VERSION 5.8 ;
BUSBITCHARS "[]" ;
DIVIDERCHAR "/" ;
UNITS
    DATABASE MICRONS 1000 ;
END UNITS

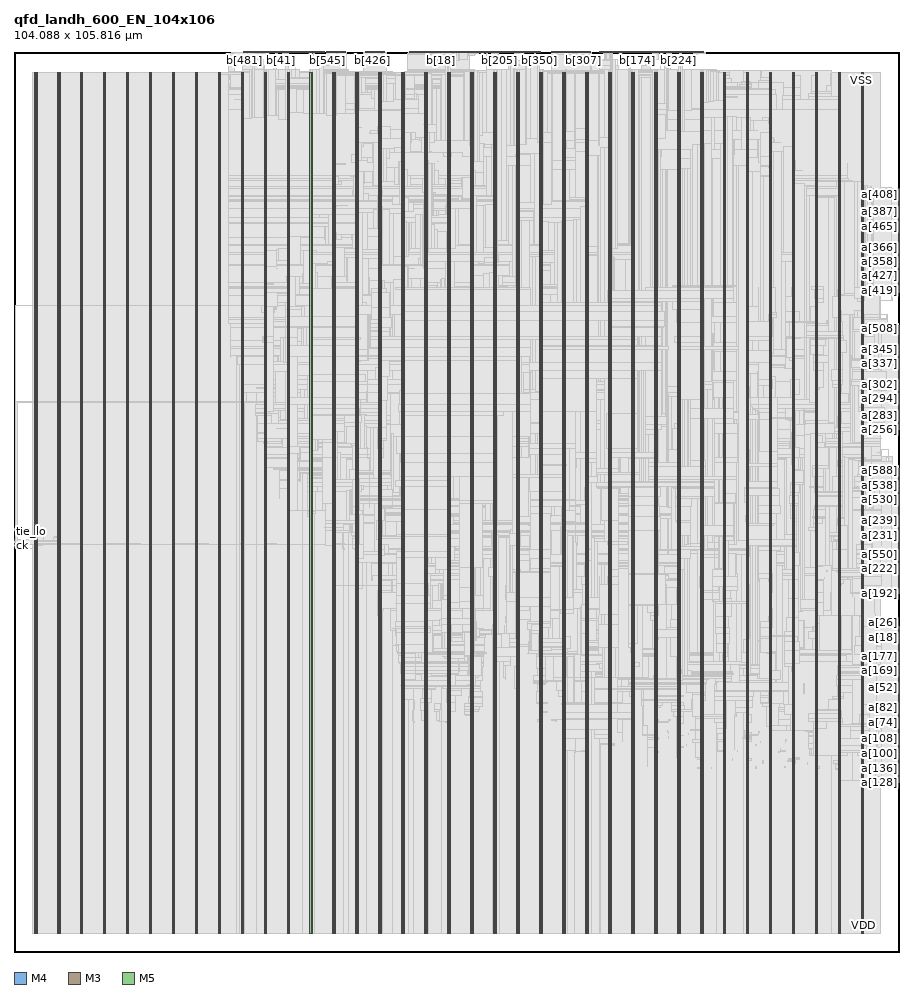
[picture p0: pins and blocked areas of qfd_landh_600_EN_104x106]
MACRO qfd_landh_600_EN_104x106
  FOREIGN qfd_landh_600_EN_104x106 0 0 ;
  CLASS BLOCK ;
  SIZE 104.088 BY 105.816 ;
  PIN a[0]
    DIRECTION INPUT ;
    USE SIGNAL ;
    PORT
      LAYER M4 ;
        RECT  104.004 35.28 104.088 35.304 ;
    END
  END a[0]
  PIN a[100]
    DIRECTION INPUT ;
    USE SIGNAL ;
    PORT
      LAYER M4 ;
        RECT  104.004 23.376 104.088 23.4 ;
    END
  END a[100]
  PIN a[101]
    DIRECTION INPUT ;
    USE SIGNAL ;
    PORT
      LAYER M4 ;
        RECT  104.004 23.472 104.088 23.496 ;
    END
  END a[101]
  PIN a[102]
    DIRECTION INPUT ;
    USE SIGNAL ;
    PORT
      LAYER M4 ;
        RECT  104.004 23.568 104.088 23.592 ;
    END
  END a[102]
  PIN a[103]
    DIRECTION INPUT ;
    USE SIGNAL ;
    PORT
      LAYER M4 ;
        RECT  104.004 23.664 104.088 23.688 ;
    END
  END a[103]
  PIN a[104]
    DIRECTION INPUT ;
    USE SIGNAL ;
    PORT
      LAYER M4 ;
        RECT  104.004 23.76 104.088 23.784 ;
    END
  END a[104]
  PIN a[105]
    DIRECTION INPUT ;
    USE SIGNAL ;
    PORT
      LAYER M4 ;
        RECT  104.004 23.856 104.088 23.88 ;
    END
  END a[105]
  PIN a[106]
    DIRECTION INPUT ;
    USE SIGNAL ;
    PORT
      LAYER M4 ;
        RECT  104.004 23.952 104.088 23.976 ;
    END
  END a[106]
  PIN a[107]
    DIRECTION INPUT ;
    USE SIGNAL ;
    PORT
      LAYER M4 ;
        RECT  104.004 24.048 104.088 24.072 ;
    END
  END a[107]
  PIN a[108]
    DIRECTION INPUT ;
    USE SIGNAL ;
    PORT
      LAYER M4 ;
        RECT  104.004 24.144 104.088 24.168 ;
    END
  END a[108]
  PIN a[109]
    DIRECTION INPUT ;
    USE SIGNAL ;
    PORT
      LAYER M4 ;
        RECT  104.004 24.24 104.088 24.264 ;
    END
  END a[109]
  PIN a[10]
    DIRECTION INPUT ;
    USE SIGNAL ;
    PORT
      LAYER M4 ;
        RECT  104.004 36.24 104.088 36.264 ;
    END
  END a[10]
  PIN a[110]
    DIRECTION INPUT ;
    USE SIGNAL ;
    PORT
      LAYER M4 ;
        RECT  104.004 24.336 104.088 24.36 ;
    END
  END a[110]
  PIN a[111]
    DIRECTION INPUT ;
    USE SIGNAL ;
    PORT
      LAYER M4 ;
        RECT  104.004 24.432 104.088 24.456 ;
    END
  END a[111]
  PIN a[112]
    DIRECTION INPUT ;
    USE SIGNAL ;
    PORT
      LAYER M4 ;
        RECT  104.004 24.528 104.088 24.552 ;
    END
  END a[112]
  PIN a[113]
    DIRECTION INPUT ;
    USE SIGNAL ;
    PORT
      LAYER M4 ;
        RECT  104.004 24.624 104.088 24.648 ;
    END
  END a[113]
  PIN a[114]
    DIRECTION INPUT ;
    USE SIGNAL ;
    PORT
      LAYER M4 ;
        RECT  104.004 24.72 104.088 24.744 ;
    END
  END a[114]
  PIN a[115]
    DIRECTION INPUT ;
    USE SIGNAL ;
    PORT
      LAYER M4 ;
        RECT  104.004 24.816 104.088 24.84 ;
    END
  END a[115]
  PIN a[116]
    DIRECTION INPUT ;
    USE SIGNAL ;
    PORT
      LAYER M4 ;
        RECT  104.004 24.912 104.088 24.936 ;
    END
  END a[116]
  PIN a[117]
    DIRECTION INPUT ;
    USE SIGNAL ;
    PORT
      LAYER M4 ;
        RECT  104.004 25.008 104.088 25.032 ;
    END
  END a[117]
  PIN a[118]
    DIRECTION INPUT ;
    USE SIGNAL ;
    PORT
      LAYER M4 ;
        RECT  104.004 25.104 104.088 25.128 ;
    END
  END a[118]
  PIN a[119]
    DIRECTION INPUT ;
    USE SIGNAL ;
    PORT
      LAYER M4 ;
        RECT  104.004 25.2 104.088 25.224 ;
    END
  END a[119]
  PIN a[11]
    DIRECTION INPUT ;
    USE SIGNAL ;
    PORT
      LAYER M4 ;
        RECT  104.004 36.336 104.088 36.36 ;
    END
  END a[11]
  PIN a[120]
    DIRECTION INPUT ;
    USE SIGNAL ;
    PORT
      LAYER M4 ;
        RECT  104.004 25.296 104.088 25.32 ;
    END
  END a[120]
  PIN a[121]
    DIRECTION INPUT ;
    USE SIGNAL ;
    PORT
      LAYER M4 ;
        RECT  104.004 25.392 104.088 25.416 ;
    END
  END a[121]
  PIN a[122]
    DIRECTION INPUT ;
    USE SIGNAL ;
    PORT
      LAYER M4 ;
        RECT  104.004 25.488 104.088 25.512 ;
    END
  END a[122]
  PIN a[123]
    DIRECTION INPUT ;
    USE SIGNAL ;
    PORT
      LAYER M4 ;
        RECT  104.004 25.584 104.088 25.608 ;
    END
  END a[123]
  PIN a[124]
    DIRECTION INPUT ;
    USE SIGNAL ;
    PORT
      LAYER M4 ;
        RECT  104.004 25.68 104.088 25.704 ;
    END
  END a[124]
  PIN a[125]
    DIRECTION INPUT ;
    USE SIGNAL ;
    PORT
      LAYER M4 ;
        RECT  104.004 25.776 104.088 25.8 ;
    END
  END a[125]
  PIN a[126]
    DIRECTION INPUT ;
    USE SIGNAL ;
    PORT
      LAYER M4 ;
        RECT  104.004 25.872 104.088 25.896 ;
    END
  END a[126]
  PIN a[127]
    DIRECTION INPUT ;
    USE SIGNAL ;
    PORT
      LAYER M4 ;
        RECT  104.004 25.968 104.088 25.992 ;
    END
  END a[127]
  PIN a[128]
    DIRECTION INPUT ;
    USE SIGNAL ;
    PORT
      LAYER M4 ;
        RECT  104.004 19.92 104.088 19.944 ;
    END
  END a[128]
  PIN a[129]
    DIRECTION INPUT ;
    USE SIGNAL ;
    PORT
      LAYER M4 ;
        RECT  104.004 20.016 104.088 20.04 ;
    END
  END a[129]
  PIN a[12]
    DIRECTION INPUT ;
    USE SIGNAL ;
    PORT
      LAYER M4 ;
        RECT  104.004 36.432 104.088 36.456 ;
    END
  END a[12]
  PIN a[130]
    DIRECTION INPUT ;
    USE SIGNAL ;
    PORT
      LAYER M4 ;
        RECT  104.004 20.112 104.088 20.136 ;
    END
  END a[130]
  PIN a[131]
    DIRECTION INPUT ;
    USE SIGNAL ;
    PORT
      LAYER M4 ;
        RECT  104.004 20.208 104.088 20.232 ;
    END
  END a[131]
  PIN a[132]
    DIRECTION INPUT ;
    USE SIGNAL ;
    PORT
      LAYER M4 ;
        RECT  104.004 20.304 104.088 20.328 ;
    END
  END a[132]
  PIN a[133]
    DIRECTION INPUT ;
    USE SIGNAL ;
    PORT
      LAYER M4 ;
        RECT  104.004 20.4 104.088 20.424 ;
    END
  END a[133]
  PIN a[134]
    DIRECTION INPUT ;
    USE SIGNAL ;
    PORT
      LAYER M4 ;
        RECT  104.004 20.496 104.088 20.52 ;
    END
  END a[134]
  PIN a[135]
    DIRECTION INPUT ;
    USE SIGNAL ;
    PORT
      LAYER M4 ;
        RECT  104.004 20.592 104.088 20.616 ;
    END
  END a[135]
  PIN a[136]
    DIRECTION INPUT ;
    USE SIGNAL ;
    PORT
      LAYER M4 ;
        RECT  104.004 20.688 104.088 20.712 ;
    END
  END a[136]
  PIN a[137]
    DIRECTION INPUT ;
    USE SIGNAL ;
    PORT
      LAYER M4 ;
        RECT  104.004 20.784 104.088 20.808 ;
    END
  END a[137]
  PIN a[138]
    DIRECTION INPUT ;
    USE SIGNAL ;
    PORT
      LAYER M4 ;
        RECT  104.004 20.88 104.088 20.904 ;
    END
  END a[138]
  PIN a[139]
    DIRECTION INPUT ;
    USE SIGNAL ;
    PORT
      LAYER M4 ;
        RECT  104.004 20.976 104.088 21 ;
    END
  END a[139]
  PIN a[13]
    DIRECTION INPUT ;
    USE SIGNAL ;
    PORT
      LAYER M4 ;
        RECT  104.004 36.528 104.088 36.552 ;
    END
  END a[13]
  PIN a[140]
    DIRECTION INPUT ;
    USE SIGNAL ;
    PORT
      LAYER M4 ;
        RECT  104.004 21.072 104.088 21.096 ;
    END
  END a[140]
  PIN a[141]
    DIRECTION INPUT ;
    USE SIGNAL ;
    PORT
      LAYER M4 ;
        RECT  104.004 21.168 104.088 21.192 ;
    END
  END a[141]
  PIN a[142]
    DIRECTION INPUT ;
    USE SIGNAL ;
    PORT
      LAYER M4 ;
        RECT  104.004 21.264 104.088 21.288 ;
    END
  END a[142]
  PIN a[143]
    DIRECTION INPUT ;
    USE SIGNAL ;
    PORT
      LAYER M4 ;
        RECT  104.004 21.36 104.088 21.384 ;
    END
  END a[143]
  PIN a[144]
    DIRECTION INPUT ;
    USE SIGNAL ;
    PORT
      LAYER M4 ;
        RECT  104.004 21.456 104.088 21.48 ;
    END
  END a[144]
  PIN a[145]
    DIRECTION INPUT ;
    USE SIGNAL ;
    PORT
      LAYER M4 ;
        RECT  104.004 21.552 104.088 21.576 ;
    END
  END a[145]
  PIN a[146]
    DIRECTION INPUT ;
    USE SIGNAL ;
    PORT
      LAYER M4 ;
        RECT  104.004 21.648 104.088 21.672 ;
    END
  END a[146]
  PIN a[147]
    DIRECTION INPUT ;
    USE SIGNAL ;
    PORT
      LAYER M4 ;
        RECT  104.004 21.744 104.088 21.768 ;
    END
  END a[147]
  PIN a[148]
    DIRECTION INPUT ;
    USE SIGNAL ;
    PORT
      LAYER M4 ;
        RECT  104.004 21.84 104.088 21.864 ;
    END
  END a[148]
  PIN a[149]
    DIRECTION INPUT ;
    USE SIGNAL ;
    PORT
      LAYER M4 ;
        RECT  104.004 21.936 104.088 21.96 ;
    END
  END a[149]
  PIN a[14]
    DIRECTION INPUT ;
    USE SIGNAL ;
    PORT
      LAYER M4 ;
        RECT  104.004 36.624 104.088 36.648 ;
    END
  END a[14]
  PIN a[150]
    DIRECTION INPUT ;
    USE SIGNAL ;
    PORT
      LAYER M4 ;
        RECT  104.004 22.032 104.088 22.056 ;
    END
  END a[150]
  PIN a[151]
    DIRECTION INPUT ;
    USE SIGNAL ;
    PORT
      LAYER M4 ;
        RECT  104.004 22.128 104.088 22.152 ;
    END
  END a[151]
  PIN a[152]
    DIRECTION INPUT ;
    USE SIGNAL ;
    PORT
      LAYER M4 ;
        RECT  104.004 22.224 104.088 22.248 ;
    END
  END a[152]
  PIN a[153]
    DIRECTION INPUT ;
    USE SIGNAL ;
    PORT
      LAYER M4 ;
        RECT  104.004 22.32 104.088 22.344 ;
    END
  END a[153]
  PIN a[154]
    DIRECTION INPUT ;
    USE SIGNAL ;
    PORT
      LAYER M4 ;
        RECT  104.004 22.416 104.088 22.44 ;
    END
  END a[154]
  PIN a[155]
    DIRECTION INPUT ;
    USE SIGNAL ;
    PORT
      LAYER M4 ;
        RECT  104.004 22.512 104.088 22.536 ;
    END
  END a[155]
  PIN a[156]
    DIRECTION INPUT ;
    USE SIGNAL ;
    PORT
      LAYER M4 ;
        RECT  104.004 22.608 104.088 22.632 ;
    END
  END a[156]
  PIN a[157]
    DIRECTION INPUT ;
    USE SIGNAL ;
    PORT
      LAYER M4 ;
        RECT  104.004 22.704 104.088 22.728 ;
    END
  END a[157]
  PIN a[158]
    DIRECTION INPUT ;
    USE SIGNAL ;
    PORT
      LAYER M4 ;
        RECT  104.004 22.8 104.088 22.824 ;
    END
  END a[158]
  PIN a[159]
    DIRECTION INPUT ;
    USE SIGNAL ;
    PORT
      LAYER M4 ;
        RECT  104.004 22.896 104.088 22.92 ;
    END
  END a[159]
  PIN a[15]
    DIRECTION INPUT ;
    USE SIGNAL ;
    PORT
      LAYER M4 ;
        RECT  104.004 36.72 104.088 36.744 ;
    END
  END a[15]
  PIN a[160]
    DIRECTION INPUT ;
    USE SIGNAL ;
    PORT
      LAYER M4 ;
        RECT  104.004 32.208 104.088 32.232 ;
    END
  END a[160]
  PIN a[161]
    DIRECTION INPUT ;
    USE SIGNAL ;
    PORT
      LAYER M4 ;
        RECT  104.004 32.304 104.088 32.328 ;
    END
  END a[161]
  PIN a[162]
    DIRECTION INPUT ;
    USE SIGNAL ;
    PORT
      LAYER M4 ;
        RECT  104.004 32.4 104.088 32.424 ;
    END
  END a[162]
  PIN a[163]
    DIRECTION INPUT ;
    USE SIGNAL ;
    PORT
      LAYER M4 ;
        RECT  104.004 32.496 104.088 32.52 ;
    END
  END a[163]
  PIN a[164]
    DIRECTION INPUT ;
    USE SIGNAL ;
    PORT
      LAYER M4 ;
        RECT  104.004 32.592 104.088 32.616 ;
    END
  END a[164]
  PIN a[165]
    DIRECTION INPUT ;
    USE SIGNAL ;
    PORT
      LAYER M4 ;
        RECT  104.004 32.688 104.088 32.712 ;
    END
  END a[165]
  PIN a[166]
    DIRECTION INPUT ;
    USE SIGNAL ;
    PORT
      LAYER M4 ;
        RECT  104.004 32.784 104.088 32.808 ;
    END
  END a[166]
  PIN a[167]
    DIRECTION INPUT ;
    USE SIGNAL ;
    PORT
      LAYER M4 ;
        RECT  104.004 32.88 104.088 32.904 ;
    END
  END a[167]
  PIN a[168]
    DIRECTION INPUT ;
    USE SIGNAL ;
    PORT
      LAYER M4 ;
        RECT  104.004 32.976 104.088 33 ;
    END
  END a[168]
  PIN a[169]
    DIRECTION INPUT ;
    USE SIGNAL ;
    PORT
      LAYER M4 ;
        RECT  104.004 33.072 104.088 33.096 ;
    END
  END a[169]
  PIN a[16]
    DIRECTION INPUT ;
    USE SIGNAL ;
    PORT
      LAYER M4 ;
        RECT  104.004 36.816 104.088 36.84 ;
    END
  END a[16]
  PIN a[170]
    DIRECTION INPUT ;
    USE SIGNAL ;
    PORT
      LAYER M4 ;
        RECT  104.004 33.168 104.088 33.192 ;
    END
  END a[170]
  PIN a[171]
    DIRECTION INPUT ;
    USE SIGNAL ;
    PORT
      LAYER M4 ;
        RECT  104.004 33.264 104.088 33.288 ;
    END
  END a[171]
  PIN a[172]
    DIRECTION INPUT ;
    USE SIGNAL ;
    PORT
      LAYER M4 ;
        RECT  104.004 33.36 104.088 33.384 ;
    END
  END a[172]
  PIN a[173]
    DIRECTION INPUT ;
    USE SIGNAL ;
    PORT
      LAYER M4 ;
        RECT  104.004 33.456 104.088 33.48 ;
    END
  END a[173]
  PIN a[174]
    DIRECTION INPUT ;
    USE SIGNAL ;
    PORT
      LAYER M4 ;
        RECT  104.004 33.552 104.088 33.576 ;
    END
  END a[174]
  PIN a[175]
    DIRECTION INPUT ;
    USE SIGNAL ;
    PORT
      LAYER M4 ;
        RECT  104.004 33.648 104.088 33.672 ;
    END
  END a[175]
  PIN a[176]
    DIRECTION INPUT ;
    USE SIGNAL ;
    PORT
      LAYER M4 ;
        RECT  104.004 33.744 104.088 33.768 ;
    END
  END a[176]
  PIN a[177]
    DIRECTION INPUT ;
    USE SIGNAL ;
    PORT
      LAYER M4 ;
        RECT  104.004 33.84 104.088 33.864 ;
    END
  END a[177]
  PIN a[178]
    DIRECTION INPUT ;
    USE SIGNAL ;
    PORT
      LAYER M4 ;
        RECT  104.004 33.936 104.088 33.96 ;
    END
  END a[178]
  PIN a[179]
    DIRECTION INPUT ;
    USE SIGNAL ;
    PORT
      LAYER M4 ;
        RECT  104.004 34.032 104.088 34.056 ;
    END
  END a[179]
  PIN a[17]
    DIRECTION INPUT ;
    USE SIGNAL ;
    PORT
      LAYER M4 ;
        RECT  104.004 36.912 104.088 36.936 ;
    END
  END a[17]
  PIN a[180]
    DIRECTION INPUT ;
    USE SIGNAL ;
    PORT
      LAYER M4 ;
        RECT  104.004 34.128 104.088 34.152 ;
    END
  END a[180]
  PIN a[181]
    DIRECTION INPUT ;
    USE SIGNAL ;
    PORT
      LAYER M4 ;
        RECT  104.004 34.224 104.088 34.248 ;
    END
  END a[181]
  PIN a[182]
    DIRECTION INPUT ;
    USE SIGNAL ;
    PORT
      LAYER M4 ;
        RECT  104.004 34.32 104.088 34.344 ;
    END
  END a[182]
  PIN a[183]
    DIRECTION INPUT ;
    USE SIGNAL ;
    PORT
      LAYER M4 ;
        RECT  104.004 34.416 104.088 34.44 ;
    END
  END a[183]
  PIN a[184]
    DIRECTION INPUT ;
    USE SIGNAL ;
    PORT
      LAYER M4 ;
        RECT  104.004 34.512 104.088 34.536 ;
    END
  END a[184]
  PIN a[185]
    DIRECTION INPUT ;
    USE SIGNAL ;
    PORT
      LAYER M4 ;
        RECT  104.004 34.608 104.088 34.632 ;
    END
  END a[185]
  PIN a[186]
    DIRECTION INPUT ;
    USE SIGNAL ;
    PORT
      LAYER M4 ;
        RECT  104.004 34.704 104.088 34.728 ;
    END
  END a[186]
  PIN a[187]
    DIRECTION INPUT ;
    USE SIGNAL ;
    PORT
      LAYER M4 ;
        RECT  104.004 34.8 104.088 34.824 ;
    END
  END a[187]
  PIN a[188]
    DIRECTION INPUT ;
    USE SIGNAL ;
    PORT
      LAYER M4 ;
        RECT  104.004 34.896 104.088 34.92 ;
    END
  END a[188]
  PIN a[189]
    DIRECTION INPUT ;
    USE SIGNAL ;
    PORT
      LAYER M4 ;
        RECT  104.004 34.992 104.088 35.016 ;
    END
  END a[189]
  PIN a[18]
    DIRECTION INPUT ;
    USE SIGNAL ;
    PORT
      LAYER M4 ;
        RECT  104.004 37.008 104.088 37.032 ;
    END
  END a[18]
  PIN a[190]
    DIRECTION INPUT ;
    USE SIGNAL ;
    PORT
      LAYER M4 ;
        RECT  104.004 35.088 104.088 35.112 ;
    END
  END a[190]
  PIN a[191]
    DIRECTION INPUT ;
    USE SIGNAL ;
    PORT
      LAYER M4 ;
        RECT  104.004 35.184 104.088 35.208 ;
    END
  END a[191]
  PIN a[192]
    DIRECTION INPUT ;
    USE SIGNAL ;
    PORT
      LAYER M4 ;
        RECT  104.004 42.192 104.088 42.216 ;
    END
  END a[192]
  PIN a[193]
    DIRECTION INPUT ;
    USE SIGNAL ;
    PORT
      LAYER M4 ;
        RECT  104.004 42.288 104.088 42.312 ;
    END
  END a[193]
  PIN a[194]
    DIRECTION INPUT ;
    USE SIGNAL ;
    PORT
      LAYER M4 ;
        RECT  104.004 42.384 104.088 42.408 ;
    END
  END a[194]
  PIN a[195]
    DIRECTION INPUT ;
    USE SIGNAL ;
    PORT
      LAYER M4 ;
        RECT  104.004 42.48 104.088 42.504 ;
    END
  END a[195]
  PIN a[196]
    DIRECTION INPUT ;
    USE SIGNAL ;
    PORT
      LAYER M4 ;
        RECT  104.004 42.576 104.088 42.6 ;
    END
  END a[196]
  PIN a[197]
    DIRECTION INPUT ;
    USE SIGNAL ;
    PORT
      LAYER M4 ;
        RECT  104.004 42.672 104.088 42.696 ;
    END
  END a[197]
  PIN a[198]
    DIRECTION INPUT ;
    USE SIGNAL ;
    PORT
      LAYER M4 ;
        RECT  104.004 42.768 104.088 42.792 ;
    END
  END a[198]
  PIN a[199]
    DIRECTION INPUT ;
    USE SIGNAL ;
    PORT
      LAYER M4 ;
        RECT  104.004 42.864 104.088 42.888 ;
    END
  END a[199]
  PIN a[19]
    DIRECTION INPUT ;
    USE SIGNAL ;
    PORT
      LAYER M4 ;
        RECT  104.004 37.104 104.088 37.128 ;
    END
  END a[19]
  PIN a[1]
    DIRECTION INPUT ;
    USE SIGNAL ;
    PORT
      LAYER M4 ;
        RECT  104.004 35.376 104.088 35.4 ;
    END
  END a[1]
  PIN a[200]
    DIRECTION INPUT ;
    USE SIGNAL ;
    PORT
      LAYER M4 ;
        RECT  104.004 42.96 104.088 42.984 ;
    END
  END a[200]
  PIN a[201]
    DIRECTION INPUT ;
    USE SIGNAL ;
    PORT
      LAYER M4 ;
        RECT  104.004 43.056 104.088 43.08 ;
    END
  END a[201]
  PIN a[202]
    DIRECTION INPUT ;
    USE SIGNAL ;
    PORT
      LAYER M4 ;
        RECT  104.004 43.152 104.088 43.176 ;
    END
  END a[202]
  PIN a[203]
    DIRECTION INPUT ;
    USE SIGNAL ;
    PORT
      LAYER M4 ;
        RECT  104.004 43.248 104.088 43.272 ;
    END
  END a[203]
  PIN a[204]
    DIRECTION INPUT ;
    USE SIGNAL ;
    PORT
      LAYER M4 ;
        RECT  104.004 43.344 104.088 43.368 ;
    END
  END a[204]
  PIN a[205]
    DIRECTION INPUT ;
    USE SIGNAL ;
    PORT
      LAYER M4 ;
        RECT  104.004 43.44 104.088 43.464 ;
    END
  END a[205]
  PIN a[206]
    DIRECTION INPUT ;
    USE SIGNAL ;
    PORT
      LAYER M4 ;
        RECT  104.004 43.536 104.088 43.56 ;
    END
  END a[206]
  PIN a[207]
    DIRECTION INPUT ;
    USE SIGNAL ;
    PORT
      LAYER M4 ;
        RECT  104.004 43.632 104.088 43.656 ;
    END
  END a[207]
  PIN a[208]
    DIRECTION INPUT ;
    USE SIGNAL ;
    PORT
      LAYER M4 ;
        RECT  104.004 43.728 104.088 43.752 ;
    END
  END a[208]
  PIN a[209]
    DIRECTION INPUT ;
    USE SIGNAL ;
    PORT
      LAYER M4 ;
        RECT  104.004 43.824 104.088 43.848 ;
    END
  END a[209]
  PIN a[20]
    DIRECTION INPUT ;
    USE SIGNAL ;
    PORT
      LAYER M4 ;
        RECT  104.004 37.2 104.088 37.224 ;
    END
  END a[20]
  PIN a[210]
    DIRECTION INPUT ;
    USE SIGNAL ;
    PORT
      LAYER M4 ;
        RECT  104.004 43.92 104.088 43.944 ;
    END
  END a[210]
  PIN a[211]
    DIRECTION INPUT ;
    USE SIGNAL ;
    PORT
      LAYER M4 ;
        RECT  104.004 44.016 104.088 44.04 ;
    END
  END a[211]
  PIN a[212]
    DIRECTION INPUT ;
    USE SIGNAL ;
    PORT
      LAYER M4 ;
        RECT  104.004 44.112 104.088 44.136 ;
    END
  END a[212]
  PIN a[213]
    DIRECTION INPUT ;
    USE SIGNAL ;
    PORT
      LAYER M4 ;
        RECT  104.004 44.208 104.088 44.232 ;
    END
  END a[213]
  PIN a[214]
    DIRECTION INPUT ;
    USE SIGNAL ;
    PORT
      LAYER M4 ;
        RECT  104.004 44.304 104.088 44.328 ;
    END
  END a[214]
  PIN a[215]
    DIRECTION INPUT ;
    USE SIGNAL ;
    PORT
      LAYER M4 ;
        RECT  104.004 44.4 104.088 44.424 ;
    END
  END a[215]
  PIN a[216]
    DIRECTION INPUT ;
    USE SIGNAL ;
    PORT
      LAYER M4 ;
        RECT  104.004 44.496 104.088 44.52 ;
    END
  END a[216]
  PIN a[217]
    DIRECTION INPUT ;
    USE SIGNAL ;
    PORT
      LAYER M4 ;
        RECT  104.004 44.592 104.088 44.616 ;
    END
  END a[217]
  PIN a[218]
    DIRECTION INPUT ;
    USE SIGNAL ;
    PORT
      LAYER M4 ;
        RECT  104.004 44.688 104.088 44.712 ;
    END
  END a[218]
  PIN a[219]
    DIRECTION INPUT ;
    USE SIGNAL ;
    PORT
      LAYER M4 ;
        RECT  104.004 44.784 104.088 44.808 ;
    END
  END a[219]
  PIN a[21]
    DIRECTION INPUT ;
    USE SIGNAL ;
    PORT
      LAYER M4 ;
        RECT  104.004 37.296 104.088 37.32 ;
    END
  END a[21]
  PIN a[220]
    DIRECTION INPUT ;
    USE SIGNAL ;
    PORT
      LAYER M4 ;
        RECT  104.004 44.88 104.088 44.904 ;
    END
  END a[220]
  PIN a[221]
    DIRECTION INPUT ;
    USE SIGNAL ;
    PORT
      LAYER M4 ;
        RECT  104.004 44.976 104.088 45 ;
    END
  END a[221]
  PIN a[222]
    DIRECTION INPUT ;
    USE SIGNAL ;
    PORT
      LAYER M4 ;
        RECT  104.004 45.072 104.088 45.096 ;
    END
  END a[222]
  PIN a[223]
    DIRECTION INPUT ;
    USE SIGNAL ;
    PORT
      LAYER M4 ;
        RECT  104.004 45.168 104.088 45.192 ;
    END
  END a[223]
  PIN a[224]
    DIRECTION INPUT ;
    USE SIGNAL ;
    PORT
      LAYER M4 ;
        RECT  104.004 48.336 104.088 48.36 ;
    END
  END a[224]
  PIN a[225]
    DIRECTION INPUT ;
    USE SIGNAL ;
    PORT
      LAYER M4 ;
        RECT  104.004 48.432 104.088 48.456 ;
    END
  END a[225]
  PIN a[226]
    DIRECTION INPUT ;
    USE SIGNAL ;
    PORT
      LAYER M4 ;
        RECT  104.004 48.528 104.088 48.552 ;
    END
  END a[226]
  PIN a[227]
    DIRECTION INPUT ;
    USE SIGNAL ;
    PORT
      LAYER M4 ;
        RECT  104.004 48.624 104.088 48.648 ;
    END
  END a[227]
  PIN a[228]
    DIRECTION INPUT ;
    USE SIGNAL ;
    PORT
      LAYER M4 ;
        RECT  104.004 48.72 104.088 48.744 ;
    END
  END a[228]
  PIN a[229]
    DIRECTION INPUT ;
    USE SIGNAL ;
    PORT
      LAYER M4 ;
        RECT  104.004 48.816 104.088 48.84 ;
    END
  END a[229]
  PIN a[22]
    DIRECTION INPUT ;
    USE SIGNAL ;
    PORT
      LAYER M4 ;
        RECT  104.004 37.392 104.088 37.416 ;
    END
  END a[22]
  PIN a[230]
    DIRECTION INPUT ;
    USE SIGNAL ;
    PORT
      LAYER M4 ;
        RECT  104.004 48.912 104.088 48.936 ;
    END
  END a[230]
  PIN a[231]
    DIRECTION INPUT ;
    USE SIGNAL ;
    PORT
      LAYER M4 ;
        RECT  104.004 49.008 104.088 49.032 ;
    END
  END a[231]
  PIN a[232]
    DIRECTION INPUT ;
    USE SIGNAL ;
    PORT
      LAYER M4 ;
        RECT  104.004 49.104 104.088 49.128 ;
    END
  END a[232]
  PIN a[233]
    DIRECTION INPUT ;
    USE SIGNAL ;
    PORT
      LAYER M4 ;
        RECT  104.004 49.2 104.088 49.224 ;
    END
  END a[233]
  PIN a[234]
    DIRECTION INPUT ;
    USE SIGNAL ;
    PORT
      LAYER M4 ;
        RECT  104.004 49.296 104.088 49.32 ;
    END
  END a[234]
  PIN a[235]
    DIRECTION INPUT ;
    USE SIGNAL ;
    PORT
      LAYER M4 ;
        RECT  104.004 49.392 104.088 49.416 ;
    END
  END a[235]
  PIN a[236]
    DIRECTION INPUT ;
    USE SIGNAL ;
    PORT
      LAYER M4 ;
        RECT  104.004 49.488 104.088 49.512 ;
    END
  END a[236]
  PIN a[237]
    DIRECTION INPUT ;
    USE SIGNAL ;
    PORT
      LAYER M4 ;
        RECT  104.004 49.584 104.088 49.608 ;
    END
  END a[237]
  PIN a[238]
    DIRECTION INPUT ;
    USE SIGNAL ;
    PORT
      LAYER M4 ;
        RECT  104.004 49.68 104.088 49.704 ;
    END
  END a[238]
  PIN a[239]
    DIRECTION INPUT ;
    USE SIGNAL ;
    PORT
      LAYER M4 ;
        RECT  104.004 49.776 104.088 49.8 ;
    END
  END a[239]
  PIN a[23]
    DIRECTION INPUT ;
    USE SIGNAL ;
    PORT
      LAYER M4 ;
        RECT  104.004 37.488 104.088 37.512 ;
    END
  END a[23]
  PIN a[240]
    DIRECTION INPUT ;
    USE SIGNAL ;
    PORT
      LAYER M4 ;
        RECT  104.004 49.872 104.088 49.896 ;
    END
  END a[240]
  PIN a[241]
    DIRECTION INPUT ;
    USE SIGNAL ;
    PORT
      LAYER M4 ;
        RECT  104.004 49.968 104.088 49.992 ;
    END
  END a[241]
  PIN a[242]
    DIRECTION INPUT ;
    USE SIGNAL ;
    PORT
      LAYER M4 ;
        RECT  104.004 50.064 104.088 50.088 ;
    END
  END a[242]
  PIN a[243]
    DIRECTION INPUT ;
    USE SIGNAL ;
    PORT
      LAYER M4 ;
        RECT  104.004 50.16 104.088 50.184 ;
    END
  END a[243]
  PIN a[244]
    DIRECTION INPUT ;
    USE SIGNAL ;
    PORT
      LAYER M4 ;
        RECT  104.004 50.256 104.088 50.28 ;
    END
  END a[244]
  PIN a[245]
    DIRECTION INPUT ;
    USE SIGNAL ;
    PORT
      LAYER M4 ;
        RECT  104.004 50.352 104.088 50.376 ;
    END
  END a[245]
  PIN a[246]
    DIRECTION INPUT ;
    USE SIGNAL ;
    PORT
      LAYER M4 ;
        RECT  104.004 50.448 104.088 50.472 ;
    END
  END a[246]
  PIN a[247]
    DIRECTION INPUT ;
    USE SIGNAL ;
    PORT
      LAYER M4 ;
        RECT  104.004 50.544 104.088 50.568 ;
    END
  END a[247]
  PIN a[248]
    DIRECTION INPUT ;
    USE SIGNAL ;
    PORT
      LAYER M4 ;
        RECT  104.004 50.64 104.088 50.664 ;
    END
  END a[248]
  PIN a[249]
    DIRECTION INPUT ;
    USE SIGNAL ;
    PORT
      LAYER M4 ;
        RECT  104.004 50.736 104.088 50.76 ;
    END
  END a[249]
  PIN a[24]
    DIRECTION INPUT ;
    USE SIGNAL ;
    PORT
      LAYER M4 ;
        RECT  104.004 37.584 104.088 37.608 ;
    END
  END a[24]
  PIN a[250]
    DIRECTION INPUT ;
    USE SIGNAL ;
    PORT
      LAYER M4 ;
        RECT  104.004 50.832 104.088 50.856 ;
    END
  END a[250]
  PIN a[251]
    DIRECTION INPUT ;
    USE SIGNAL ;
    PORT
      LAYER M4 ;
        RECT  104.004 50.928 104.088 50.952 ;
    END
  END a[251]
  PIN a[252]
    DIRECTION INPUT ;
    USE SIGNAL ;
    PORT
      LAYER M4 ;
        RECT  104.004 51.024 104.088 51.048 ;
    END
  END a[252]
  PIN a[253]
    DIRECTION INPUT ;
    USE SIGNAL ;
    PORT
      LAYER M4 ;
        RECT  104.004 51.12 104.088 51.144 ;
    END
  END a[253]
  PIN a[254]
    DIRECTION INPUT ;
    USE SIGNAL ;
    PORT
      LAYER M4 ;
        RECT  104.004 51.216 104.088 51.24 ;
    END
  END a[254]
  PIN a[255]
    DIRECTION INPUT ;
    USE SIGNAL ;
    PORT
      LAYER M4 ;
        RECT  104.004 51.312 104.088 51.336 ;
    END
  END a[255]
  PIN a[256]
    DIRECTION INPUT ;
    USE SIGNAL ;
    PORT
      LAYER M4 ;
        RECT  104.004 61.392 104.088 61.416 ;
    END
  END a[256]
  PIN a[257]
    DIRECTION INPUT ;
    USE SIGNAL ;
    PORT
      LAYER M4 ;
        RECT  104.004 61.488 104.088 61.512 ;
    END
  END a[257]
  PIN a[258]
    DIRECTION INPUT ;
    USE SIGNAL ;
    PORT
      LAYER M4 ;
        RECT  104.004 61.584 104.088 61.608 ;
    END
  END a[258]
  PIN a[259]
    DIRECTION INPUT ;
    USE SIGNAL ;
    PORT
      LAYER M4 ;
        RECT  104.004 61.68 104.088 61.704 ;
    END
  END a[259]
  PIN a[25]
    DIRECTION INPUT ;
    USE SIGNAL ;
    PORT
      LAYER M4 ;
        RECT  104.004 37.68 104.088 37.704 ;
    END
  END a[25]
  PIN a[260]
    DIRECTION INPUT ;
    USE SIGNAL ;
    PORT
      LAYER M4 ;
        RECT  104.004 61.776 104.088 61.8 ;
    END
  END a[260]
  PIN a[261]
    DIRECTION INPUT ;
    USE SIGNAL ;
    PORT
      LAYER M4 ;
        RECT  104.004 61.872 104.088 61.896 ;
    END
  END a[261]
  PIN a[262]
    DIRECTION INPUT ;
    USE SIGNAL ;
    PORT
      LAYER M4 ;
        RECT  104.004 61.968 104.088 61.992 ;
    END
  END a[262]
  PIN a[263]
    DIRECTION INPUT ;
    USE SIGNAL ;
    PORT
      LAYER M4 ;
        RECT  104.004 62.064 104.088 62.088 ;
    END
  END a[263]
  PIN a[264]
    DIRECTION INPUT ;
    USE SIGNAL ;
    PORT
      LAYER M4 ;
        RECT  104.004 62.16 104.088 62.184 ;
    END
  END a[264]
  PIN a[265]
    DIRECTION INPUT ;
    USE SIGNAL ;
    PORT
      LAYER M4 ;
        RECT  104.004 62.256 104.088 62.28 ;
    END
  END a[265]
  PIN a[266]
    DIRECTION INPUT ;
    USE SIGNAL ;
    PORT
      LAYER M4 ;
        RECT  104.004 62.352 104.088 62.376 ;
    END
  END a[266]
  PIN a[267]
    DIRECTION INPUT ;
    USE SIGNAL ;
    PORT
      LAYER M4 ;
        RECT  104.004 62.448 104.088 62.472 ;
    END
  END a[267]
  PIN a[268]
    DIRECTION INPUT ;
    USE SIGNAL ;
    PORT
      LAYER M4 ;
        RECT  104.004 62.544 104.088 62.568 ;
    END
  END a[268]
  PIN a[269]
    DIRECTION INPUT ;
    USE SIGNAL ;
    PORT
      LAYER M4 ;
        RECT  104.004 62.64 104.088 62.664 ;
    END
  END a[269]
  PIN a[26]
    DIRECTION INPUT ;
    USE SIGNAL ;
    PORT
      LAYER M4 ;
        RECT  104.004 37.776 104.088 37.8 ;
    END
  END a[26]
  PIN a[270]
    DIRECTION INPUT ;
    USE SIGNAL ;
    PORT
      LAYER M4 ;
        RECT  104.004 62.736 104.088 62.76 ;
    END
  END a[270]
  PIN a[271]
    DIRECTION INPUT ;
    USE SIGNAL ;
    PORT
      LAYER M4 ;
        RECT  104.004 62.832 104.088 62.856 ;
    END
  END a[271]
  PIN a[272]
    DIRECTION INPUT ;
    USE SIGNAL ;
    PORT
      LAYER M4 ;
        RECT  104.004 62.928 104.088 62.952 ;
    END
  END a[272]
  PIN a[273]
    DIRECTION INPUT ;
    USE SIGNAL ;
    PORT
      LAYER M4 ;
        RECT  104.004 63.024 104.088 63.048 ;
    END
  END a[273]
  PIN a[274]
    DIRECTION INPUT ;
    USE SIGNAL ;
    PORT
      LAYER M4 ;
        RECT  104.004 63.12 104.088 63.144 ;
    END
  END a[274]
  PIN a[275]
    DIRECTION INPUT ;
    USE SIGNAL ;
    PORT
      LAYER M4 ;
        RECT  104.004 63.216 104.088 63.24 ;
    END
  END a[275]
  PIN a[276]
    DIRECTION INPUT ;
    USE SIGNAL ;
    PORT
      LAYER M4 ;
        RECT  104.004 63.312 104.088 63.336 ;
    END
  END a[276]
  PIN a[277]
    DIRECTION INPUT ;
    USE SIGNAL ;
    PORT
      LAYER M4 ;
        RECT  104.004 63.408 104.088 63.432 ;
    END
  END a[277]
  PIN a[278]
    DIRECTION INPUT ;
    USE SIGNAL ;
    PORT
      LAYER M4 ;
        RECT  104.004 63.504 104.088 63.528 ;
    END
  END a[278]
  PIN a[279]
    DIRECTION INPUT ;
    USE SIGNAL ;
    PORT
      LAYER M4 ;
        RECT  104.004 63.6 104.088 63.624 ;
    END
  END a[279]
  PIN a[27]
    DIRECTION INPUT ;
    USE SIGNAL ;
    PORT
      LAYER M4 ;
        RECT  104.004 37.872 104.088 37.896 ;
    END
  END a[27]
  PIN a[280]
    DIRECTION INPUT ;
    USE SIGNAL ;
    PORT
      LAYER M4 ;
        RECT  104.004 63.696 104.088 63.72 ;
    END
  END a[280]
  PIN a[281]
    DIRECTION INPUT ;
    USE SIGNAL ;
    PORT
      LAYER M4 ;
        RECT  104.004 63.792 104.088 63.816 ;
    END
  END a[281]
  PIN a[282]
    DIRECTION INPUT ;
    USE SIGNAL ;
    PORT
      LAYER M4 ;
        RECT  104.004 63.888 104.088 63.912 ;
    END
  END a[282]
  PIN a[283]
    DIRECTION INPUT ;
    USE SIGNAL ;
    PORT
      LAYER M4 ;
        RECT  104.004 63.984 104.088 64.008 ;
    END
  END a[283]
  PIN a[284]
    DIRECTION INPUT ;
    USE SIGNAL ;
    PORT
      LAYER M4 ;
        RECT  104.004 64.08 104.088 64.104 ;
    END
  END a[284]
  PIN a[285]
    DIRECTION INPUT ;
    USE SIGNAL ;
    PORT
      LAYER M4 ;
        RECT  104.004 64.176 104.088 64.2 ;
    END
  END a[285]
  PIN a[286]
    DIRECTION INPUT ;
    USE SIGNAL ;
    PORT
      LAYER M4 ;
        RECT  104.004 64.272 104.088 64.296 ;
    END
  END a[286]
  PIN a[287]
    DIRECTION INPUT ;
    USE SIGNAL ;
    PORT
      LAYER M4 ;
        RECT  104.004 64.368 104.088 64.392 ;
    END
  END a[287]
  PIN a[288]
    DIRECTION INPUT ;
    USE SIGNAL ;
    PORT
      LAYER M4 ;
        RECT  104.004 64.464 104.088 64.488 ;
    END
  END a[288]
  PIN a[289]
    DIRECTION INPUT ;
    USE SIGNAL ;
    PORT
      LAYER M4 ;
        RECT  104.004 64.56 104.088 64.584 ;
    END
  END a[289]
  PIN a[28]
    DIRECTION INPUT ;
    USE SIGNAL ;
    PORT
      LAYER M4 ;
        RECT  104.004 37.968 104.088 37.992 ;
    END
  END a[28]
  PIN a[290]
    DIRECTION INPUT ;
    USE SIGNAL ;
    PORT
      LAYER M4 ;
        RECT  104.004 64.656 104.088 64.68 ;
    END
  END a[290]
  PIN a[291]
    DIRECTION INPUT ;
    USE SIGNAL ;
    PORT
      LAYER M4 ;
        RECT  104.004 64.752 104.088 64.776 ;
    END
  END a[291]
  PIN a[292]
    DIRECTION INPUT ;
    USE SIGNAL ;
    PORT
      LAYER M4 ;
        RECT  104.004 64.848 104.088 64.872 ;
    END
  END a[292]
  PIN a[293]
    DIRECTION INPUT ;
    USE SIGNAL ;
    PORT
      LAYER M4 ;
        RECT  104.004 64.944 104.088 64.968 ;
    END
  END a[293]
  PIN a[294]
    DIRECTION INPUT ;
    USE SIGNAL ;
    PORT
      LAYER M4 ;
        RECT  104.004 65.04 104.088 65.064 ;
    END
  END a[294]
  PIN a[295]
    DIRECTION INPUT ;
    USE SIGNAL ;
    PORT
      LAYER M4 ;
        RECT  104.004 65.136 104.088 65.16 ;
    END
  END a[295]
  PIN a[296]
    DIRECTION INPUT ;
    USE SIGNAL ;
    PORT
      LAYER M4 ;
        RECT  104.004 65.232 104.088 65.256 ;
    END
  END a[296]
  PIN a[297]
    DIRECTION INPUT ;
    USE SIGNAL ;
    PORT
      LAYER M4 ;
        RECT  104.004 65.328 104.088 65.352 ;
    END
  END a[297]
  PIN a[298]
    DIRECTION INPUT ;
    USE SIGNAL ;
    PORT
      LAYER M4 ;
        RECT  104.004 65.424 104.088 65.448 ;
    END
  END a[298]
  PIN a[299]
    DIRECTION INPUT ;
    USE SIGNAL ;
    PORT
      LAYER M4 ;
        RECT  104.004 65.52 104.088 65.544 ;
    END
  END a[299]
  PIN a[29]
    DIRECTION INPUT ;
    USE SIGNAL ;
    PORT
      LAYER M4 ;
        RECT  104.004 38.064 104.088 38.088 ;
    END
  END a[29]
  PIN a[2]
    DIRECTION INPUT ;
    USE SIGNAL ;
    PORT
      LAYER M4 ;
        RECT  104.004 35.472 104.088 35.496 ;
    END
  END a[2]
  PIN a[300]
    DIRECTION INPUT ;
    USE SIGNAL ;
    PORT
      LAYER M4 ;
        RECT  104.004 65.616 104.088 65.64 ;
    END
  END a[300]
  PIN a[301]
    DIRECTION INPUT ;
    USE SIGNAL ;
    PORT
      LAYER M4 ;
        RECT  104.004 65.712 104.088 65.736 ;
    END
  END a[301]
  PIN a[302]
    DIRECTION INPUT ;
    USE SIGNAL ;
    PORT
      LAYER M4 ;
        RECT  104.004 65.808 104.088 65.832 ;
    END
  END a[302]
  PIN a[303]
    DIRECTION INPUT ;
    USE SIGNAL ;
    PORT
      LAYER M4 ;
        RECT  104.004 65.904 104.088 65.928 ;
    END
  END a[303]
  PIN a[304]
    DIRECTION INPUT ;
    USE SIGNAL ;
    PORT
      LAYER M4 ;
        RECT  104.004 66 104.088 66.024 ;
    END
  END a[304]
  PIN a[305]
    DIRECTION INPUT ;
    USE SIGNAL ;
    PORT
      LAYER M4 ;
        RECT  104.004 66.096 104.088 66.12 ;
    END
  END a[305]
  PIN a[306]
    DIRECTION INPUT ;
    USE SIGNAL ;
    PORT
      LAYER M4 ;
        RECT  104.004 66.192 104.088 66.216 ;
    END
  END a[306]
  PIN a[307]
    DIRECTION INPUT ;
    USE SIGNAL ;
    PORT
      LAYER M4 ;
        RECT  104.004 66.288 104.088 66.312 ;
    END
  END a[307]
  PIN a[308]
    DIRECTION INPUT ;
    USE SIGNAL ;
    PORT
      LAYER M4 ;
        RECT  104.004 66.384 104.088 66.408 ;
    END
  END a[308]
  PIN a[309]
    DIRECTION INPUT ;
    USE SIGNAL ;
    PORT
      LAYER M4 ;
        RECT  104.004 66.48 104.088 66.504 ;
    END
  END a[309]
  PIN a[30]
    DIRECTION INPUT ;
    USE SIGNAL ;
    PORT
      LAYER M4 ;
        RECT  104.004 38.16 104.088 38.184 ;
    END
  END a[30]
  PIN a[310]
    DIRECTION INPUT ;
    USE SIGNAL ;
    PORT
      LAYER M4 ;
        RECT  104.004 66.576 104.088 66.6 ;
    END
  END a[310]
  PIN a[311]
    DIRECTION INPUT ;
    USE SIGNAL ;
    PORT
      LAYER M4 ;
        RECT  104.004 66.672 104.088 66.696 ;
    END
  END a[311]
  PIN a[312]
    DIRECTION INPUT ;
    USE SIGNAL ;
    PORT
      LAYER M4 ;
        RECT  104.004 66.768 104.088 66.792 ;
    END
  END a[312]
  PIN a[313]
    DIRECTION INPUT ;
    USE SIGNAL ;
    PORT
      LAYER M4 ;
        RECT  104.004 66.864 104.088 66.888 ;
    END
  END a[313]
  PIN a[314]
    DIRECTION INPUT ;
    USE SIGNAL ;
    PORT
      LAYER M4 ;
        RECT  104.004 66.96 104.088 66.984 ;
    END
  END a[314]
  PIN a[315]
    DIRECTION INPUT ;
    USE SIGNAL ;
    PORT
      LAYER M4 ;
        RECT  104.004 67.056 104.088 67.08 ;
    END
  END a[315]
  PIN a[316]
    DIRECTION INPUT ;
    USE SIGNAL ;
    PORT
      LAYER M4 ;
        RECT  104.004 67.152 104.088 67.176 ;
    END
  END a[316]
  PIN a[317]
    DIRECTION INPUT ;
    USE SIGNAL ;
    PORT
      LAYER M4 ;
        RECT  104.004 67.248 104.088 67.272 ;
    END
  END a[317]
  PIN a[318]
    DIRECTION INPUT ;
    USE SIGNAL ;
    PORT
      LAYER M4 ;
        RECT  104.004 67.344 104.088 67.368 ;
    END
  END a[318]
  PIN a[319]
    DIRECTION INPUT ;
    USE SIGNAL ;
    PORT
      LAYER M4 ;
        RECT  104.004 67.44 104.088 67.464 ;
    END
  END a[319]
  PIN a[31]
    DIRECTION INPUT ;
    USE SIGNAL ;
    PORT
      LAYER M4 ;
        RECT  104.004 38.256 104.088 38.28 ;
    END
  END a[31]
  PIN a[320]
    DIRECTION INPUT ;
    USE SIGNAL ;
    PORT
      LAYER M4 ;
        RECT  104.004 67.536 104.088 67.56 ;
    END
  END a[320]
  PIN a[321]
    DIRECTION INPUT ;
    USE SIGNAL ;
    PORT
      LAYER M4 ;
        RECT  104.004 67.632 104.088 67.656 ;
    END
  END a[321]
  PIN a[322]
    DIRECTION INPUT ;
    USE SIGNAL ;
    PORT
      LAYER M4 ;
        RECT  104.004 67.728 104.088 67.752 ;
    END
  END a[322]
  PIN a[323]
    DIRECTION INPUT ;
    USE SIGNAL ;
    PORT
      LAYER M4 ;
        RECT  104.004 67.824 104.088 67.848 ;
    END
  END a[323]
  PIN a[324]
    DIRECTION INPUT ;
    USE SIGNAL ;
    PORT
      LAYER M4 ;
        RECT  104.004 67.92 104.088 67.944 ;
    END
  END a[324]
  PIN a[325]
    DIRECTION INPUT ;
    USE SIGNAL ;
    PORT
      LAYER M4 ;
        RECT  104.004 68.016 104.088 68.04 ;
    END
  END a[325]
  PIN a[326]
    DIRECTION INPUT ;
    USE SIGNAL ;
    PORT
      LAYER M4 ;
        RECT  104.004 68.112 104.088 68.136 ;
    END
  END a[326]
  PIN a[327]
    DIRECTION INPUT ;
    USE SIGNAL ;
    PORT
      LAYER M4 ;
        RECT  104.004 68.208 104.088 68.232 ;
    END
  END a[327]
  PIN a[328]
    DIRECTION INPUT ;
    USE SIGNAL ;
    PORT
      LAYER M4 ;
        RECT  104.004 68.304 104.088 68.328 ;
    END
  END a[328]
  PIN a[329]
    DIRECTION INPUT ;
    USE SIGNAL ;
    PORT
      LAYER M4 ;
        RECT  104.004 68.4 104.088 68.424 ;
    END
  END a[329]
  PIN a[32]
    DIRECTION INPUT ;
    USE SIGNAL ;
    PORT
      LAYER M4 ;
        RECT  104.004 29.136 104.088 29.16 ;
    END
  END a[32]
  PIN a[330]
    DIRECTION INPUT ;
    USE SIGNAL ;
    PORT
      LAYER M4 ;
        RECT  104.004 68.496 104.088 68.52 ;
    END
  END a[330]
  PIN a[331]
    DIRECTION INPUT ;
    USE SIGNAL ;
    PORT
      LAYER M4 ;
        RECT  104.004 68.592 104.088 68.616 ;
    END
  END a[331]
  PIN a[332]
    DIRECTION INPUT ;
    USE SIGNAL ;
    PORT
      LAYER M4 ;
        RECT  104.004 68.688 104.088 68.712 ;
    END
  END a[332]
  PIN a[333]
    DIRECTION INPUT ;
    USE SIGNAL ;
    PORT
      LAYER M4 ;
        RECT  104.004 68.784 104.088 68.808 ;
    END
  END a[333]
  PIN a[334]
    DIRECTION INPUT ;
    USE SIGNAL ;
    PORT
      LAYER M4 ;
        RECT  104.004 68.88 104.088 68.904 ;
    END
  END a[334]
  PIN a[335]
    DIRECTION INPUT ;
    USE SIGNAL ;
    PORT
      LAYER M4 ;
        RECT  104.004 68.976 104.088 69 ;
    END
  END a[335]
  PIN a[336]
    DIRECTION INPUT ;
    USE SIGNAL ;
    PORT
      LAYER M4 ;
        RECT  104.004 69.072 104.088 69.096 ;
    END
  END a[336]
  PIN a[337]
    DIRECTION INPUT ;
    USE SIGNAL ;
    PORT
      LAYER M4 ;
        RECT  104.004 69.168 104.088 69.192 ;
    END
  END a[337]
  PIN a[338]
    DIRECTION INPUT ;
    USE SIGNAL ;
    PORT
      LAYER M4 ;
        RECT  104.004 69.264 104.088 69.288 ;
    END
  END a[338]
  PIN a[339]
    DIRECTION INPUT ;
    USE SIGNAL ;
    PORT
      LAYER M4 ;
        RECT  104.004 69.36 104.088 69.384 ;
    END
  END a[339]
  PIN a[33]
    DIRECTION INPUT ;
    USE SIGNAL ;
    PORT
      LAYER M4 ;
        RECT  104.004 29.232 104.088 29.256 ;
    END
  END a[33]
  PIN a[340]
    DIRECTION INPUT ;
    USE SIGNAL ;
    PORT
      LAYER M4 ;
        RECT  104.004 69.456 104.088 69.48 ;
    END
  END a[340]
  PIN a[341]
    DIRECTION INPUT ;
    USE SIGNAL ;
    PORT
      LAYER M4 ;
        RECT  104.004 69.552 104.088 69.576 ;
    END
  END a[341]
  PIN a[342]
    DIRECTION INPUT ;
    USE SIGNAL ;
    PORT
      LAYER M4 ;
        RECT  104.004 69.648 104.088 69.672 ;
    END
  END a[342]
  PIN a[343]
    DIRECTION INPUT ;
    USE SIGNAL ;
    PORT
      LAYER M4 ;
        RECT  104.004 69.744 104.088 69.768 ;
    END
  END a[343]
  PIN a[344]
    DIRECTION INPUT ;
    USE SIGNAL ;
    PORT
      LAYER M4 ;
        RECT  104.004 69.84 104.088 69.864 ;
    END
  END a[344]
  PIN a[345]
    DIRECTION INPUT ;
    USE SIGNAL ;
    PORT
      LAYER M4 ;
        RECT  104.004 69.936 104.088 69.96 ;
    END
  END a[345]
  PIN a[346]
    DIRECTION INPUT ;
    USE SIGNAL ;
    PORT
      LAYER M4 ;
        RECT  104.004 70.032 104.088 70.056 ;
    END
  END a[346]
  PIN a[347]
    DIRECTION INPUT ;
    USE SIGNAL ;
    PORT
      LAYER M4 ;
        RECT  104.004 70.128 104.088 70.152 ;
    END
  END a[347]
  PIN a[348]
    DIRECTION INPUT ;
    USE SIGNAL ;
    PORT
      LAYER M4 ;
        RECT  104.004 70.224 104.088 70.248 ;
    END
  END a[348]
  PIN a[349]
    DIRECTION INPUT ;
    USE SIGNAL ;
    PORT
      LAYER M4 ;
        RECT  104.004 70.32 104.088 70.344 ;
    END
  END a[349]
  PIN a[34]
    DIRECTION INPUT ;
    USE SIGNAL ;
    PORT
      LAYER M4 ;
        RECT  104.004 29.328 104.088 29.352 ;
    END
  END a[34]
  PIN a[350]
    DIRECTION INPUT ;
    USE SIGNAL ;
    PORT
      LAYER M4 ;
        RECT  104.004 70.416 104.088 70.44 ;
    END
  END a[350]
  PIN a[351]
    DIRECTION INPUT ;
    USE SIGNAL ;
    PORT
      LAYER M4 ;
        RECT  104.004 70.512 104.088 70.536 ;
    END
  END a[351]
  PIN a[352]
    DIRECTION INPUT ;
    USE SIGNAL ;
    PORT
      LAYER M4 ;
        RECT  104.004 80.592 104.088 80.616 ;
    END
  END a[352]
  PIN a[353]
    DIRECTION INPUT ;
    USE SIGNAL ;
    PORT
      LAYER M4 ;
        RECT  104.004 80.688 104.088 80.712 ;
    END
  END a[353]
  PIN a[354]
    DIRECTION INPUT ;
    USE SIGNAL ;
    PORT
      LAYER M4 ;
        RECT  104.004 80.784 104.088 80.808 ;
    END
  END a[354]
  PIN a[355]
    DIRECTION INPUT ;
    USE SIGNAL ;
    PORT
      LAYER M4 ;
        RECT  104.004 80.88 104.088 80.904 ;
    END
  END a[355]
  PIN a[356]
    DIRECTION INPUT ;
    USE SIGNAL ;
    PORT
      LAYER M4 ;
        RECT  104.004 80.976 104.088 81 ;
    END
  END a[356]
  PIN a[357]
    DIRECTION INPUT ;
    USE SIGNAL ;
    PORT
      LAYER M4 ;
        RECT  104.004 81.072 104.088 81.096 ;
    END
  END a[357]
  PIN a[358]
    DIRECTION INPUT ;
    USE SIGNAL ;
    PORT
      LAYER M4 ;
        RECT  104.004 81.168 104.088 81.192 ;
    END
  END a[358]
  PIN a[359]
    DIRECTION INPUT ;
    USE SIGNAL ;
    PORT
      LAYER M4 ;
        RECT  104.004 81.264 104.088 81.288 ;
    END
  END a[359]
  PIN a[35]
    DIRECTION INPUT ;
    USE SIGNAL ;
    PORT
      LAYER M4 ;
        RECT  104.004 29.424 104.088 29.448 ;
    END
  END a[35]
  PIN a[360]
    DIRECTION INPUT ;
    USE SIGNAL ;
    PORT
      LAYER M4 ;
        RECT  104.004 81.36 104.088 81.384 ;
    END
  END a[360]
  PIN a[361]
    DIRECTION INPUT ;
    USE SIGNAL ;
    PORT
      LAYER M4 ;
        RECT  104.004 81.456 104.088 81.48 ;
    END
  END a[361]
  PIN a[362]
    DIRECTION INPUT ;
    USE SIGNAL ;
    PORT
      LAYER M4 ;
        RECT  104.004 81.552 104.088 81.576 ;
    END
  END a[362]
  PIN a[363]
    DIRECTION INPUT ;
    USE SIGNAL ;
    PORT
      LAYER M4 ;
        RECT  104.004 81.648 104.088 81.672 ;
    END
  END a[363]
  PIN a[364]
    DIRECTION INPUT ;
    USE SIGNAL ;
    PORT
      LAYER M4 ;
        RECT  104.004 81.744 104.088 81.768 ;
    END
  END a[364]
  PIN a[365]
    DIRECTION INPUT ;
    USE SIGNAL ;
    PORT
      LAYER M4 ;
        RECT  104.004 81.84 104.088 81.864 ;
    END
  END a[365]
  PIN a[366]
    DIRECTION INPUT ;
    USE SIGNAL ;
    PORT
      LAYER M4 ;
        RECT  104.004 81.936 104.088 81.96 ;
    END
  END a[366]
  PIN a[367]
    DIRECTION INPUT ;
    USE SIGNAL ;
    PORT
      LAYER M4 ;
        RECT  104.004 82.032 104.088 82.056 ;
    END
  END a[367]
  PIN a[368]
    DIRECTION INPUT ;
    USE SIGNAL ;
    PORT
      LAYER M4 ;
        RECT  104.004 82.128 104.088 82.152 ;
    END
  END a[368]
  PIN a[369]
    DIRECTION INPUT ;
    USE SIGNAL ;
    PORT
      LAYER M4 ;
        RECT  104.004 82.224 104.088 82.248 ;
    END
  END a[369]
  PIN a[36]
    DIRECTION INPUT ;
    USE SIGNAL ;
    PORT
      LAYER M4 ;
        RECT  104.004 29.52 104.088 29.544 ;
    END
  END a[36]
  PIN a[370]
    DIRECTION INPUT ;
    USE SIGNAL ;
    PORT
      LAYER M4 ;
        RECT  104.004 82.32 104.088 82.344 ;
    END
  END a[370]
  PIN a[371]
    DIRECTION INPUT ;
    USE SIGNAL ;
    PORT
      LAYER M4 ;
        RECT  104.004 82.416 104.088 82.44 ;
    END
  END a[371]
  PIN a[372]
    DIRECTION INPUT ;
    USE SIGNAL ;
    PORT
      LAYER M4 ;
        RECT  104.004 82.512 104.088 82.536 ;
    END
  END a[372]
  PIN a[373]
    DIRECTION INPUT ;
    USE SIGNAL ;
    PORT
      LAYER M4 ;
        RECT  104.004 82.608 104.088 82.632 ;
    END
  END a[373]
  PIN a[374]
    DIRECTION INPUT ;
    USE SIGNAL ;
    PORT
      LAYER M4 ;
        RECT  104.004 82.704 104.088 82.728 ;
    END
  END a[374]
  PIN a[375]
    DIRECTION INPUT ;
    USE SIGNAL ;
    PORT
      LAYER M4 ;
        RECT  104.004 82.8 104.088 82.824 ;
    END
  END a[375]
  PIN a[376]
    DIRECTION INPUT ;
    USE SIGNAL ;
    PORT
      LAYER M4 ;
        RECT  104.004 82.896 104.088 82.92 ;
    END
  END a[376]
  PIN a[377]
    DIRECTION INPUT ;
    USE SIGNAL ;
    PORT
      LAYER M4 ;
        RECT  104.004 82.992 104.088 83.016 ;
    END
  END a[377]
  PIN a[378]
    DIRECTION INPUT ;
    USE SIGNAL ;
    PORT
      LAYER M4 ;
        RECT  104.004 83.088 104.088 83.112 ;
    END
  END a[378]
  PIN a[379]
    DIRECTION INPUT ;
    USE SIGNAL ;
    PORT
      LAYER M4 ;
        RECT  104.004 83.184 104.088 83.208 ;
    END
  END a[379]
  PIN a[37]
    DIRECTION INPUT ;
    USE SIGNAL ;
    PORT
      LAYER M4 ;
        RECT  104.004 29.616 104.088 29.64 ;
    END
  END a[37]
  PIN a[380]
    DIRECTION INPUT ;
    USE SIGNAL ;
    PORT
      LAYER M4 ;
        RECT  104.004 83.28 104.088 83.304 ;
    END
  END a[380]
  PIN a[381]
    DIRECTION INPUT ;
    USE SIGNAL ;
    PORT
      LAYER M4 ;
        RECT  104.004 83.376 104.088 83.4 ;
    END
  END a[381]
  PIN a[382]
    DIRECTION INPUT ;
    USE SIGNAL ;
    PORT
      LAYER M4 ;
        RECT  104.004 83.472 104.088 83.496 ;
    END
  END a[382]
  PIN a[383]
    DIRECTION INPUT ;
    USE SIGNAL ;
    PORT
      LAYER M4 ;
        RECT  104.004 83.568 104.088 83.592 ;
    END
  END a[383]
  PIN a[384]
    DIRECTION INPUT ;
    USE SIGNAL ;
    PORT
      LAYER M4 ;
        RECT  104.004 86.736 104.088 86.76 ;
    END
  END a[384]
  PIN a[385]
    DIRECTION INPUT ;
    USE SIGNAL ;
    PORT
      LAYER M4 ;
        RECT  104.004 86.832 104.088 86.856 ;
    END
  END a[385]
  PIN a[386]
    DIRECTION INPUT ;
    USE SIGNAL ;
    PORT
      LAYER M4 ;
        RECT  104.004 86.928 104.088 86.952 ;
    END
  END a[386]
  PIN a[387]
    DIRECTION INPUT ;
    USE SIGNAL ;
    PORT
      LAYER M4 ;
        RECT  104.004 87.024 104.088 87.048 ;
    END
  END a[387]
  PIN a[388]
    DIRECTION INPUT ;
    USE SIGNAL ;
    PORT
      LAYER M4 ;
        RECT  104.004 87.12 104.088 87.144 ;
    END
  END a[388]
  PIN a[389]
    DIRECTION INPUT ;
    USE SIGNAL ;
    PORT
      LAYER M4 ;
        RECT  104.004 87.216 104.088 87.24 ;
    END
  END a[389]
  PIN a[38]
    DIRECTION INPUT ;
    USE SIGNAL ;
    PORT
      LAYER M4 ;
        RECT  104.004 29.712 104.088 29.736 ;
    END
  END a[38]
  PIN a[390]
    DIRECTION INPUT ;
    USE SIGNAL ;
    PORT
      LAYER M4 ;
        RECT  104.004 87.312 104.088 87.336 ;
    END
  END a[390]
  PIN a[391]
    DIRECTION INPUT ;
    USE SIGNAL ;
    PORT
      LAYER M4 ;
        RECT  104.004 87.408 104.088 87.432 ;
    END
  END a[391]
  PIN a[392]
    DIRECTION INPUT ;
    USE SIGNAL ;
    PORT
      LAYER M4 ;
        RECT  104.004 87.504 104.088 87.528 ;
    END
  END a[392]
  PIN a[393]
    DIRECTION INPUT ;
    USE SIGNAL ;
    PORT
      LAYER M4 ;
        RECT  104.004 87.6 104.088 87.624 ;
    END
  END a[393]
  PIN a[394]
    DIRECTION INPUT ;
    USE SIGNAL ;
    PORT
      LAYER M4 ;
        RECT  104.004 87.696 104.088 87.72 ;
    END
  END a[394]
  PIN a[395]
    DIRECTION INPUT ;
    USE SIGNAL ;
    PORT
      LAYER M4 ;
        RECT  104.004 87.792 104.088 87.816 ;
    END
  END a[395]
  PIN a[396]
    DIRECTION INPUT ;
    USE SIGNAL ;
    PORT
      LAYER M4 ;
        RECT  104.004 87.888 104.088 87.912 ;
    END
  END a[396]
  PIN a[397]
    DIRECTION INPUT ;
    USE SIGNAL ;
    PORT
      LAYER M4 ;
        RECT  104.004 87.984 104.088 88.008 ;
    END
  END a[397]
  PIN a[398]
    DIRECTION INPUT ;
    USE SIGNAL ;
    PORT
      LAYER M4 ;
        RECT  104.004 88.08 104.088 88.104 ;
    END
  END a[398]
  PIN a[399]
    DIRECTION INPUT ;
    USE SIGNAL ;
    PORT
      LAYER M4 ;
        RECT  104.004 88.176 104.088 88.2 ;
    END
  END a[399]
  PIN a[39]
    DIRECTION INPUT ;
    USE SIGNAL ;
    PORT
      LAYER M4 ;
        RECT  104.004 29.808 104.088 29.832 ;
    END
  END a[39]
  PIN a[3]
    DIRECTION INPUT ;
    USE SIGNAL ;
    PORT
      LAYER M4 ;
        RECT  104.004 35.568 104.088 35.592 ;
    END
  END a[3]
  PIN a[400]
    DIRECTION INPUT ;
    USE SIGNAL ;
    PORT
      LAYER M4 ;
        RECT  104.004 88.272 104.088 88.296 ;
    END
  END a[400]
  PIN a[401]
    DIRECTION INPUT ;
    USE SIGNAL ;
    PORT
      LAYER M4 ;
        RECT  104.004 88.368 104.088 88.392 ;
    END
  END a[401]
  PIN a[402]
    DIRECTION INPUT ;
    USE SIGNAL ;
    PORT
      LAYER M4 ;
        RECT  104.004 88.464 104.088 88.488 ;
    END
  END a[402]
  PIN a[403]
    DIRECTION INPUT ;
    USE SIGNAL ;
    PORT
      LAYER M4 ;
        RECT  104.004 88.56 104.088 88.584 ;
    END
  END a[403]
  PIN a[404]
    DIRECTION INPUT ;
    USE SIGNAL ;
    PORT
      LAYER M4 ;
        RECT  104.004 88.656 104.088 88.68 ;
    END
  END a[404]
  PIN a[405]
    DIRECTION INPUT ;
    USE SIGNAL ;
    PORT
      LAYER M4 ;
        RECT  104.004 88.752 104.088 88.776 ;
    END
  END a[405]
  PIN a[406]
    DIRECTION INPUT ;
    USE SIGNAL ;
    PORT
      LAYER M4 ;
        RECT  104.004 88.848 104.088 88.872 ;
    END
  END a[406]
  PIN a[407]
    DIRECTION INPUT ;
    USE SIGNAL ;
    PORT
      LAYER M4 ;
        RECT  104.004 88.944 104.088 88.968 ;
    END
  END a[407]
  PIN a[408]
    DIRECTION INPUT ;
    USE SIGNAL ;
    PORT
      LAYER M4 ;
        RECT  104.004 89.04 104.088 89.064 ;
    END
  END a[408]
  PIN a[409]
    DIRECTION INPUT ;
    USE SIGNAL ;
    PORT
      LAYER M4 ;
        RECT  104.004 89.136 104.088 89.16 ;
    END
  END a[409]
  PIN a[40]
    DIRECTION INPUT ;
    USE SIGNAL ;
    PORT
      LAYER M4 ;
        RECT  104.004 29.904 104.088 29.928 ;
    END
  END a[40]
  PIN a[410]
    DIRECTION INPUT ;
    USE SIGNAL ;
    PORT
      LAYER M4 ;
        RECT  104.004 89.232 104.088 89.256 ;
    END
  END a[410]
  PIN a[411]
    DIRECTION INPUT ;
    USE SIGNAL ;
    PORT
      LAYER M4 ;
        RECT  104.004 89.328 104.088 89.352 ;
    END
  END a[411]
  PIN a[412]
    DIRECTION INPUT ;
    USE SIGNAL ;
    PORT
      LAYER M4 ;
        RECT  104.004 89.424 104.088 89.448 ;
    END
  END a[412]
  PIN a[413]
    DIRECTION INPUT ;
    USE SIGNAL ;
    PORT
      LAYER M4 ;
        RECT  104.004 89.52 104.088 89.544 ;
    END
  END a[413]
  PIN a[414]
    DIRECTION INPUT ;
    USE SIGNAL ;
    PORT
      LAYER M4 ;
        RECT  104.004 89.616 104.088 89.64 ;
    END
  END a[414]
  PIN a[415]
    DIRECTION INPUT ;
    USE SIGNAL ;
    PORT
      LAYER M4 ;
        RECT  104.004 89.712 104.088 89.736 ;
    END
  END a[415]
  PIN a[416]
    DIRECTION INPUT ;
    USE SIGNAL ;
    PORT
      LAYER M4 ;
        RECT  104.004 77.52 104.088 77.544 ;
    END
  END a[416]
  PIN a[417]
    DIRECTION INPUT ;
    USE SIGNAL ;
    PORT
      LAYER M4 ;
        RECT  104.004 77.616 104.088 77.64 ;
    END
  END a[417]
  PIN a[418]
    DIRECTION INPUT ;
    USE SIGNAL ;
    PORT
      LAYER M4 ;
        RECT  104.004 77.712 104.088 77.736 ;
    END
  END a[418]
  PIN a[419]
    DIRECTION INPUT ;
    USE SIGNAL ;
    PORT
      LAYER M4 ;
        RECT  104.004 77.808 104.088 77.832 ;
    END
  END a[419]
  PIN a[41]
    DIRECTION INPUT ;
    USE SIGNAL ;
    PORT
      LAYER M4 ;
        RECT  104.004 30 104.088 30.024 ;
    END
  END a[41]
  PIN a[420]
    DIRECTION INPUT ;
    USE SIGNAL ;
    PORT
      LAYER M4 ;
        RECT  104.004 77.904 104.088 77.928 ;
    END
  END a[420]
  PIN a[421]
    DIRECTION INPUT ;
    USE SIGNAL ;
    PORT
      LAYER M4 ;
        RECT  104.004 78 104.088 78.024 ;
    END
  END a[421]
  PIN a[422]
    DIRECTION INPUT ;
    USE SIGNAL ;
    PORT
      LAYER M4 ;
        RECT  104.004 78.096 104.088 78.12 ;
    END
  END a[422]
  PIN a[423]
    DIRECTION INPUT ;
    USE SIGNAL ;
    PORT
      LAYER M4 ;
        RECT  104.004 78.192 104.088 78.216 ;
    END
  END a[423]
  PIN a[424]
    DIRECTION INPUT ;
    USE SIGNAL ;
    PORT
      LAYER M4 ;
        RECT  104.004 78.288 104.088 78.312 ;
    END
  END a[424]
  PIN a[425]
    DIRECTION INPUT ;
    USE SIGNAL ;
    PORT
      LAYER M4 ;
        RECT  104.004 78.384 104.088 78.408 ;
    END
  END a[425]
  PIN a[426]
    DIRECTION INPUT ;
    USE SIGNAL ;
    PORT
      LAYER M4 ;
        RECT  104.004 78.48 104.088 78.504 ;
    END
  END a[426]
  PIN a[427]
    DIRECTION INPUT ;
    USE SIGNAL ;
    PORT
      LAYER M4 ;
        RECT  104.004 78.576 104.088 78.6 ;
    END
  END a[427]
  PIN a[428]
    DIRECTION INPUT ;
    USE SIGNAL ;
    PORT
      LAYER M4 ;
        RECT  104.004 78.672 104.088 78.696 ;
    END
  END a[428]
  PIN a[429]
    DIRECTION INPUT ;
    USE SIGNAL ;
    PORT
      LAYER M4 ;
        RECT  104.004 78.768 104.088 78.792 ;
    END
  END a[429]
  PIN a[42]
    DIRECTION INPUT ;
    USE SIGNAL ;
    PORT
      LAYER M4 ;
        RECT  104.004 30.096 104.088 30.12 ;
    END
  END a[42]
  PIN a[430]
    DIRECTION INPUT ;
    USE SIGNAL ;
    PORT
      LAYER M4 ;
        RECT  104.004 78.864 104.088 78.888 ;
    END
  END a[430]
  PIN a[431]
    DIRECTION INPUT ;
    USE SIGNAL ;
    PORT
      LAYER M4 ;
        RECT  104.004 78.96 104.088 78.984 ;
    END
  END a[431]
  PIN a[432]
    DIRECTION INPUT ;
    USE SIGNAL ;
    PORT
      LAYER M4 ;
        RECT  104.004 79.056 104.088 79.08 ;
    END
  END a[432]
  PIN a[433]
    DIRECTION INPUT ;
    USE SIGNAL ;
    PORT
      LAYER M4 ;
        RECT  104.004 79.152 104.088 79.176 ;
    END
  END a[433]
  PIN a[434]
    DIRECTION INPUT ;
    USE SIGNAL ;
    PORT
      LAYER M4 ;
        RECT  104.004 79.248 104.088 79.272 ;
    END
  END a[434]
  PIN a[435]
    DIRECTION INPUT ;
    USE SIGNAL ;
    PORT
      LAYER M4 ;
        RECT  104.004 79.344 104.088 79.368 ;
    END
  END a[435]
  PIN a[436]
    DIRECTION INPUT ;
    USE SIGNAL ;
    PORT
      LAYER M4 ;
        RECT  104.004 79.44 104.088 79.464 ;
    END
  END a[436]
  PIN a[437]
    DIRECTION INPUT ;
    USE SIGNAL ;
    PORT
      LAYER M4 ;
        RECT  104.004 79.536 104.088 79.56 ;
    END
  END a[437]
  PIN a[438]
    DIRECTION INPUT ;
    USE SIGNAL ;
    PORT
      LAYER M4 ;
        RECT  104.004 79.632 104.088 79.656 ;
    END
  END a[438]
  PIN a[439]
    DIRECTION INPUT ;
    USE SIGNAL ;
    PORT
      LAYER M4 ;
        RECT  104.004 79.728 104.088 79.752 ;
    END
  END a[439]
  PIN a[43]
    DIRECTION INPUT ;
    USE SIGNAL ;
    PORT
      LAYER M4 ;
        RECT  104.004 30.192 104.088 30.216 ;
    END
  END a[43]
  PIN a[440]
    DIRECTION INPUT ;
    USE SIGNAL ;
    PORT
      LAYER M4 ;
        RECT  104.004 79.824 104.088 79.848 ;
    END
  END a[440]
  PIN a[441]
    DIRECTION INPUT ;
    USE SIGNAL ;
    PORT
      LAYER M4 ;
        RECT  104.004 79.92 104.088 79.944 ;
    END
  END a[441]
  PIN a[442]
    DIRECTION INPUT ;
    USE SIGNAL ;
    PORT
      LAYER M4 ;
        RECT  104.004 80.016 104.088 80.04 ;
    END
  END a[442]
  PIN a[443]
    DIRECTION INPUT ;
    USE SIGNAL ;
    PORT
      LAYER M4 ;
        RECT  104.004 80.112 104.088 80.136 ;
    END
  END a[443]
  PIN a[444]
    DIRECTION INPUT ;
    USE SIGNAL ;
    PORT
      LAYER M4 ;
        RECT  104.004 80.208 104.088 80.232 ;
    END
  END a[444]
  PIN a[445]
    DIRECTION INPUT ;
    USE SIGNAL ;
    PORT
      LAYER M4 ;
        RECT  104.004 80.304 104.088 80.328 ;
    END
  END a[445]
  PIN a[446]
    DIRECTION INPUT ;
    USE SIGNAL ;
    PORT
      LAYER M4 ;
        RECT  104.004 80.4 104.088 80.424 ;
    END
  END a[446]
  PIN a[447]
    DIRECTION INPUT ;
    USE SIGNAL ;
    PORT
      LAYER M4 ;
        RECT  104.004 80.496 104.088 80.52 ;
    END
  END a[447]
  PIN a[448]
    DIRECTION INPUT ;
    USE SIGNAL ;
    PORT
      LAYER M4 ;
        RECT  104.004 83.664 104.088 83.688 ;
    END
  END a[448]
  PIN a[449]
    DIRECTION INPUT ;
    USE SIGNAL ;
    PORT
      LAYER M4 ;
        RECT  104.004 83.76 104.088 83.784 ;
    END
  END a[449]
  PIN a[44]
    DIRECTION INPUT ;
    USE SIGNAL ;
    PORT
      LAYER M4 ;
        RECT  104.004 30.288 104.088 30.312 ;
    END
  END a[44]
  PIN a[450]
    DIRECTION INPUT ;
    USE SIGNAL ;
    PORT
      LAYER M4 ;
        RECT  104.004 83.856 104.088 83.88 ;
    END
  END a[450]
  PIN a[451]
    DIRECTION INPUT ;
    USE SIGNAL ;
    PORT
      LAYER M4 ;
        RECT  104.004 83.952 104.088 83.976 ;
    END
  END a[451]
  PIN a[452]
    DIRECTION INPUT ;
    USE SIGNAL ;
    PORT
      LAYER M4 ;
        RECT  104.004 84.048 104.088 84.072 ;
    END
  END a[452]
  PIN a[453]
    DIRECTION INPUT ;
    USE SIGNAL ;
    PORT
      LAYER M4 ;
        RECT  104.004 84.144 104.088 84.168 ;
    END
  END a[453]
  PIN a[454]
    DIRECTION INPUT ;
    USE SIGNAL ;
    PORT
      LAYER M4 ;
        RECT  104.004 84.24 104.088 84.264 ;
    END
  END a[454]
  PIN a[455]
    DIRECTION INPUT ;
    USE SIGNAL ;
    PORT
      LAYER M4 ;
        RECT  104.004 84.336 104.088 84.36 ;
    END
  END a[455]
  PIN a[456]
    DIRECTION INPUT ;
    USE SIGNAL ;
    PORT
      LAYER M4 ;
        RECT  104.004 84.432 104.088 84.456 ;
    END
  END a[456]
  PIN a[457]
    DIRECTION INPUT ;
    USE SIGNAL ;
    PORT
      LAYER M4 ;
        RECT  104.004 84.528 104.088 84.552 ;
    END
  END a[457]
  PIN a[458]
    DIRECTION INPUT ;
    USE SIGNAL ;
    PORT
      LAYER M4 ;
        RECT  104.004 84.624 104.088 84.648 ;
    END
  END a[458]
  PIN a[459]
    DIRECTION INPUT ;
    USE SIGNAL ;
    PORT
      LAYER M4 ;
        RECT  104.004 84.72 104.088 84.744 ;
    END
  END a[459]
  PIN a[45]
    DIRECTION INPUT ;
    USE SIGNAL ;
    PORT
      LAYER M4 ;
        RECT  104.004 30.384 104.088 30.408 ;
    END
  END a[45]
  PIN a[460]
    DIRECTION INPUT ;
    USE SIGNAL ;
    PORT
      LAYER M4 ;
        RECT  104.004 84.816 104.088 84.84 ;
    END
  END a[460]
  PIN a[461]
    DIRECTION INPUT ;
    USE SIGNAL ;
    PORT
      LAYER M4 ;
        RECT  104.004 84.912 104.088 84.936 ;
    END
  END a[461]
  PIN a[462]
    DIRECTION INPUT ;
    USE SIGNAL ;
    PORT
      LAYER M4 ;
        RECT  104.004 85.008 104.088 85.032 ;
    END
  END a[462]
  PIN a[463]
    DIRECTION INPUT ;
    USE SIGNAL ;
    PORT
      LAYER M4 ;
        RECT  104.004 85.104 104.088 85.128 ;
    END
  END a[463]
  PIN a[464]
    DIRECTION INPUT ;
    USE SIGNAL ;
    PORT
      LAYER M4 ;
        RECT  104.004 85.2 104.088 85.224 ;
    END
  END a[464]
  PIN a[465]
    DIRECTION INPUT ;
    USE SIGNAL ;
    PORT
      LAYER M4 ;
        RECT  104.004 85.296 104.088 85.32 ;
    END
  END a[465]
  PIN a[466]
    DIRECTION INPUT ;
    USE SIGNAL ;
    PORT
      LAYER M4 ;
        RECT  104.004 85.392 104.088 85.416 ;
    END
  END a[466]
  PIN a[467]
    DIRECTION INPUT ;
    USE SIGNAL ;
    PORT
      LAYER M4 ;
        RECT  104.004 85.488 104.088 85.512 ;
    END
  END a[467]
  PIN a[468]
    DIRECTION INPUT ;
    USE SIGNAL ;
    PORT
      LAYER M4 ;
        RECT  104.004 85.584 104.088 85.608 ;
    END
  END a[468]
  PIN a[469]
    DIRECTION INPUT ;
    USE SIGNAL ;
    PORT
      LAYER M4 ;
        RECT  104.004 85.68 104.088 85.704 ;
    END
  END a[469]
  PIN a[46]
    DIRECTION INPUT ;
    USE SIGNAL ;
    PORT
      LAYER M4 ;
        RECT  104.004 30.48 104.088 30.504 ;
    END
  END a[46]
  PIN a[470]
    DIRECTION INPUT ;
    USE SIGNAL ;
    PORT
      LAYER M4 ;
        RECT  104.004 85.776 104.088 85.8 ;
    END
  END a[470]
  PIN a[471]
    DIRECTION INPUT ;
    USE SIGNAL ;
    PORT
      LAYER M4 ;
        RECT  104.004 85.872 104.088 85.896 ;
    END
  END a[471]
  PIN a[472]
    DIRECTION INPUT ;
    USE SIGNAL ;
    PORT
      LAYER M4 ;
        RECT  104.004 85.968 104.088 85.992 ;
    END
  END a[472]
  PIN a[473]
    DIRECTION INPUT ;
    USE SIGNAL ;
    PORT
      LAYER M4 ;
        RECT  104.004 86.064 104.088 86.088 ;
    END
  END a[473]
  PIN a[474]
    DIRECTION INPUT ;
    USE SIGNAL ;
    PORT
      LAYER M4 ;
        RECT  104.004 86.16 104.088 86.184 ;
    END
  END a[474]
  PIN a[475]
    DIRECTION INPUT ;
    USE SIGNAL ;
    PORT
      LAYER M4 ;
        RECT  104.004 86.256 104.088 86.28 ;
    END
  END a[475]
  PIN a[476]
    DIRECTION INPUT ;
    USE SIGNAL ;
    PORT
      LAYER M4 ;
        RECT  104.004 86.352 104.088 86.376 ;
    END
  END a[476]
  PIN a[477]
    DIRECTION INPUT ;
    USE SIGNAL ;
    PORT
      LAYER M4 ;
        RECT  104.004 86.448 104.088 86.472 ;
    END
  END a[477]
  PIN a[478]
    DIRECTION INPUT ;
    USE SIGNAL ;
    PORT
      LAYER M4 ;
        RECT  104.004 86.544 104.088 86.568 ;
    END
  END a[478]
  PIN a[479]
    DIRECTION INPUT ;
    USE SIGNAL ;
    PORT
      LAYER M4 ;
        RECT  104.004 86.64 104.088 86.664 ;
    END
  END a[479]
  PIN a[47]
    DIRECTION INPUT ;
    USE SIGNAL ;
    PORT
      LAYER M4 ;
        RECT  104.004 30.576 104.088 30.6 ;
    END
  END a[47]
  PIN a[480]
    DIRECTION INPUT ;
    USE SIGNAL ;
    PORT
      LAYER M4 ;
        RECT  104.004 70.608 104.088 70.632 ;
    END
  END a[480]
  PIN a[481]
    DIRECTION INPUT ;
    USE SIGNAL ;
    PORT
      LAYER M4 ;
        RECT  104.004 70.704 104.088 70.728 ;
    END
  END a[481]
  PIN a[482]
    DIRECTION INPUT ;
    USE SIGNAL ;
    PORT
      LAYER M4 ;
        RECT  104.004 70.8 104.088 70.824 ;
    END
  END a[482]
  PIN a[483]
    DIRECTION INPUT ;
    USE SIGNAL ;
    PORT
      LAYER M4 ;
        RECT  104.004 70.896 104.088 70.92 ;
    END
  END a[483]
  PIN a[484]
    DIRECTION INPUT ;
    USE SIGNAL ;
    PORT
      LAYER M4 ;
        RECT  104.004 70.992 104.088 71.016 ;
    END
  END a[484]
  PIN a[485]
    DIRECTION INPUT ;
    USE SIGNAL ;
    PORT
      LAYER M4 ;
        RECT  104.004 71.088 104.088 71.112 ;
    END
  END a[485]
  PIN a[486]
    DIRECTION INPUT ;
    USE SIGNAL ;
    PORT
      LAYER M4 ;
        RECT  104.004 71.184 104.088 71.208 ;
    END
  END a[486]
  PIN a[487]
    DIRECTION INPUT ;
    USE SIGNAL ;
    PORT
      LAYER M4 ;
        RECT  104.004 71.28 104.088 71.304 ;
    END
  END a[487]
  PIN a[488]
    DIRECTION INPUT ;
    USE SIGNAL ;
    PORT
      LAYER M4 ;
        RECT  104.004 71.376 104.088 71.4 ;
    END
  END a[488]
  PIN a[489]
    DIRECTION INPUT ;
    USE SIGNAL ;
    PORT
      LAYER M4 ;
        RECT  104.004 71.472 104.088 71.496 ;
    END
  END a[489]
  PIN a[48]
    DIRECTION INPUT ;
    USE SIGNAL ;
    PORT
      LAYER M4 ;
        RECT  104.004 30.672 104.088 30.696 ;
    END
  END a[48]
  PIN a[490]
    DIRECTION INPUT ;
    USE SIGNAL ;
    PORT
      LAYER M4 ;
        RECT  104.004 71.568 104.088 71.592 ;
    END
  END a[490]
  PIN a[491]
    DIRECTION INPUT ;
    USE SIGNAL ;
    PORT
      LAYER M4 ;
        RECT  104.004 71.664 104.088 71.688 ;
    END
  END a[491]
  PIN a[492]
    DIRECTION INPUT ;
    USE SIGNAL ;
    PORT
      LAYER M4 ;
        RECT  104.004 71.76 104.088 71.784 ;
    END
  END a[492]
  PIN a[493]
    DIRECTION INPUT ;
    USE SIGNAL ;
    PORT
      LAYER M4 ;
        RECT  104.004 71.856 104.088 71.88 ;
    END
  END a[493]
  PIN a[494]
    DIRECTION INPUT ;
    USE SIGNAL ;
    PORT
      LAYER M4 ;
        RECT  104.004 71.952 104.088 71.976 ;
    END
  END a[494]
  PIN a[495]
    DIRECTION INPUT ;
    USE SIGNAL ;
    PORT
      LAYER M4 ;
        RECT  104.004 72.048 104.088 72.072 ;
    END
  END a[495]
  PIN a[496]
    DIRECTION INPUT ;
    USE SIGNAL ;
    PORT
      LAYER M4 ;
        RECT  104.004 72.144 104.088 72.168 ;
    END
  END a[496]
  PIN a[497]
    DIRECTION INPUT ;
    USE SIGNAL ;
    PORT
      LAYER M4 ;
        RECT  104.004 72.24 104.088 72.264 ;
    END
  END a[497]
  PIN a[498]
    DIRECTION INPUT ;
    USE SIGNAL ;
    PORT
      LAYER M4 ;
        RECT  104.004 72.336 104.088 72.36 ;
    END
  END a[498]
  PIN a[499]
    DIRECTION INPUT ;
    USE SIGNAL ;
    PORT
      LAYER M4 ;
        RECT  104.004 72.432 104.088 72.456 ;
    END
  END a[499]
  PIN a[49]
    DIRECTION INPUT ;
    USE SIGNAL ;
    PORT
      LAYER M4 ;
        RECT  104.004 30.768 104.088 30.792 ;
    END
  END a[49]
  PIN a[4]
    DIRECTION INPUT ;
    USE SIGNAL ;
    PORT
      LAYER M4 ;
        RECT  104.004 35.664 104.088 35.688 ;
    END
  END a[4]
  PIN a[500]
    DIRECTION INPUT ;
    USE SIGNAL ;
    PORT
      LAYER M4 ;
        RECT  104.004 72.528 104.088 72.552 ;
    END
  END a[500]
  PIN a[501]
    DIRECTION INPUT ;
    USE SIGNAL ;
    PORT
      LAYER M4 ;
        RECT  104.004 72.624 104.088 72.648 ;
    END
  END a[501]
  PIN a[502]
    DIRECTION INPUT ;
    USE SIGNAL ;
    PORT
      LAYER M4 ;
        RECT  104.004 72.72 104.088 72.744 ;
    END
  END a[502]
  PIN a[503]
    DIRECTION INPUT ;
    USE SIGNAL ;
    PORT
      LAYER M4 ;
        RECT  104.004 72.816 104.088 72.84 ;
    END
  END a[503]
  PIN a[504]
    DIRECTION INPUT ;
    USE SIGNAL ;
    PORT
      LAYER M4 ;
        RECT  104.004 72.912 104.088 72.936 ;
    END
  END a[504]
  PIN a[505]
    DIRECTION INPUT ;
    USE SIGNAL ;
    PORT
      LAYER M4 ;
        RECT  104.004 73.008 104.088 73.032 ;
    END
  END a[505]
  PIN a[506]
    DIRECTION INPUT ;
    USE SIGNAL ;
    PORT
      LAYER M4 ;
        RECT  104.004 73.104 104.088 73.128 ;
    END
  END a[506]
  PIN a[507]
    DIRECTION INPUT ;
    USE SIGNAL ;
    PORT
      LAYER M4 ;
        RECT  104.004 73.2 104.088 73.224 ;
    END
  END a[507]
  PIN a[508]
    DIRECTION INPUT ;
    USE SIGNAL ;
    PORT
      LAYER M4 ;
        RECT  104.004 73.296 104.088 73.32 ;
    END
  END a[508]
  PIN a[509]
    DIRECTION INPUT ;
    USE SIGNAL ;
    PORT
      LAYER M4 ;
        RECT  104.004 73.392 104.088 73.416 ;
    END
  END a[509]
  PIN a[50]
    DIRECTION INPUT ;
    USE SIGNAL ;
    PORT
      LAYER M4 ;
        RECT  104.004 30.864 104.088 30.888 ;
    END
  END a[50]
  PIN a[510]
    DIRECTION INPUT ;
    USE SIGNAL ;
    PORT
      LAYER M4 ;
        RECT  104.004 73.488 104.088 73.512 ;
    END
  END a[510]
  PIN a[511]
    DIRECTION INPUT ;
    USE SIGNAL ;
    PORT
      LAYER M4 ;
        RECT  104.004 73.584 104.088 73.608 ;
    END
  END a[511]
  PIN a[512]
    DIRECTION INPUT ;
    USE SIGNAL ;
    PORT
      LAYER M4 ;
        RECT  104.004 51.408 104.088 51.432 ;
    END
  END a[512]
  PIN a[513]
    DIRECTION INPUT ;
    USE SIGNAL ;
    PORT
      LAYER M4 ;
        RECT  104.004 51.504 104.088 51.528 ;
    END
  END a[513]
  PIN a[514]
    DIRECTION INPUT ;
    USE SIGNAL ;
    PORT
      LAYER M4 ;
        RECT  104.004 51.6 104.088 51.624 ;
    END
  END a[514]
  PIN a[515]
    DIRECTION INPUT ;
    USE SIGNAL ;
    PORT
      LAYER M4 ;
        RECT  104.004 51.696 104.088 51.72 ;
    END
  END a[515]
  PIN a[516]
    DIRECTION INPUT ;
    USE SIGNAL ;
    PORT
      LAYER M4 ;
        RECT  104.004 51.792 104.088 51.816 ;
    END
  END a[516]
  PIN a[517]
    DIRECTION INPUT ;
    USE SIGNAL ;
    PORT
      LAYER M4 ;
        RECT  104.004 51.888 104.088 51.912 ;
    END
  END a[517]
  PIN a[518]
    DIRECTION INPUT ;
    USE SIGNAL ;
    PORT
      LAYER M4 ;
        RECT  104.004 51.984 104.088 52.008 ;
    END
  END a[518]
  PIN a[519]
    DIRECTION INPUT ;
    USE SIGNAL ;
    PORT
      LAYER M4 ;
        RECT  104.004 52.08 104.088 52.104 ;
    END
  END a[519]
  PIN a[51]
    DIRECTION INPUT ;
    USE SIGNAL ;
    PORT
      LAYER M4 ;
        RECT  104.004 30.96 104.088 30.984 ;
    END
  END a[51]
  PIN a[520]
    DIRECTION INPUT ;
    USE SIGNAL ;
    PORT
      LAYER M4 ;
        RECT  104.004 52.176 104.088 52.2 ;
    END
  END a[520]
  PIN a[521]
    DIRECTION INPUT ;
    USE SIGNAL ;
    PORT
      LAYER M4 ;
        RECT  104.004 52.272 104.088 52.296 ;
    END
  END a[521]
  PIN a[522]
    DIRECTION INPUT ;
    USE SIGNAL ;
    PORT
      LAYER M4 ;
        RECT  104.004 52.368 104.088 52.392 ;
    END
  END a[522]
  PIN a[523]
    DIRECTION INPUT ;
    USE SIGNAL ;
    PORT
      LAYER M4 ;
        RECT  104.004 52.464 104.088 52.488 ;
    END
  END a[523]
  PIN a[524]
    DIRECTION INPUT ;
    USE SIGNAL ;
    PORT
      LAYER M4 ;
        RECT  104.004 52.56 104.088 52.584 ;
    END
  END a[524]
  PIN a[525]
    DIRECTION INPUT ;
    USE SIGNAL ;
    PORT
      LAYER M4 ;
        RECT  104.004 52.656 104.088 52.68 ;
    END
  END a[525]
  PIN a[526]
    DIRECTION INPUT ;
    USE SIGNAL ;
    PORT
      LAYER M4 ;
        RECT  104.004 52.752 104.088 52.776 ;
    END
  END a[526]
  PIN a[527]
    DIRECTION INPUT ;
    USE SIGNAL ;
    PORT
      LAYER M4 ;
        RECT  104.004 52.848 104.088 52.872 ;
    END
  END a[527]
  PIN a[528]
    DIRECTION INPUT ;
    USE SIGNAL ;
    PORT
      LAYER M4 ;
        RECT  104.004 52.944 104.088 52.968 ;
    END
  END a[528]
  PIN a[529]
    DIRECTION INPUT ;
    USE SIGNAL ;
    PORT
      LAYER M4 ;
        RECT  104.004 53.04 104.088 53.064 ;
    END
  END a[529]
  PIN a[52]
    DIRECTION INPUT ;
    USE SIGNAL ;
    PORT
      LAYER M4 ;
        RECT  104.004 31.056 104.088 31.08 ;
    END
  END a[52]
  PIN a[530]
    DIRECTION INPUT ;
    USE SIGNAL ;
    PORT
      LAYER M4 ;
        RECT  104.004 53.136 104.088 53.16 ;
    END
  END a[530]
  PIN a[531]
    DIRECTION INPUT ;
    USE SIGNAL ;
    PORT
      LAYER M4 ;
        RECT  104.004 53.232 104.088 53.256 ;
    END
  END a[531]
  PIN a[532]
    DIRECTION INPUT ;
    USE SIGNAL ;
    PORT
      LAYER M4 ;
        RECT  104.004 53.328 104.088 53.352 ;
    END
  END a[532]
  PIN a[533]
    DIRECTION INPUT ;
    USE SIGNAL ;
    PORT
      LAYER M4 ;
        RECT  104.004 53.424 104.088 53.448 ;
    END
  END a[533]
  PIN a[534]
    DIRECTION INPUT ;
    USE SIGNAL ;
    PORT
      LAYER M4 ;
        RECT  104.004 53.52 104.088 53.544 ;
    END
  END a[534]
  PIN a[535]
    DIRECTION INPUT ;
    USE SIGNAL ;
    PORT
      LAYER M4 ;
        RECT  104.004 53.616 104.088 53.64 ;
    END
  END a[535]
  PIN a[536]
    DIRECTION INPUT ;
    USE SIGNAL ;
    PORT
      LAYER M4 ;
        RECT  104.004 53.712 104.088 53.736 ;
    END
  END a[536]
  PIN a[537]
    DIRECTION INPUT ;
    USE SIGNAL ;
    PORT
      LAYER M4 ;
        RECT  104.004 53.808 104.088 53.832 ;
    END
  END a[537]
  PIN a[538]
    DIRECTION INPUT ;
    USE SIGNAL ;
    PORT
      LAYER M4 ;
        RECT  104.004 53.904 104.088 53.928 ;
    END
  END a[538]
  PIN a[539]
    DIRECTION INPUT ;
    USE SIGNAL ;
    PORT
      LAYER M4 ;
        RECT  104.004 54 104.088 54.024 ;
    END
  END a[539]
  PIN a[53]
    DIRECTION INPUT ;
    USE SIGNAL ;
    PORT
      LAYER M4 ;
        RECT  104.004 31.152 104.088 31.176 ;
    END
  END a[53]
  PIN a[540]
    DIRECTION INPUT ;
    USE SIGNAL ;
    PORT
      LAYER M4 ;
        RECT  104.004 54.096 104.088 54.12 ;
    END
  END a[540]
  PIN a[541]
    DIRECTION INPUT ;
    USE SIGNAL ;
    PORT
      LAYER M4 ;
        RECT  104.004 54.192 104.088 54.216 ;
    END
  END a[541]
  PIN a[542]
    DIRECTION INPUT ;
    USE SIGNAL ;
    PORT
      LAYER M4 ;
        RECT  104.004 54.288 104.088 54.312 ;
    END
  END a[542]
  PIN a[543]
    DIRECTION INPUT ;
    USE SIGNAL ;
    PORT
      LAYER M4 ;
        RECT  104.004 54.384 104.088 54.408 ;
    END
  END a[543]
  PIN a[544]
    DIRECTION INPUT ;
    USE SIGNAL ;
    PORT
      LAYER M4 ;
        RECT  104.004 45.264 104.088 45.288 ;
    END
  END a[544]
  PIN a[545]
    DIRECTION INPUT ;
    USE SIGNAL ;
    PORT
      LAYER M4 ;
        RECT  104.004 45.36 104.088 45.384 ;
    END
  END a[545]
  PIN a[546]
    DIRECTION INPUT ;
    USE SIGNAL ;
    PORT
      LAYER M4 ;
        RECT  104.004 45.456 104.088 45.48 ;
    END
  END a[546]
  PIN a[547]
    DIRECTION INPUT ;
    USE SIGNAL ;
    PORT
      LAYER M4 ;
        RECT  104.004 45.552 104.088 45.576 ;
    END
  END a[547]
  PIN a[548]
    DIRECTION INPUT ;
    USE SIGNAL ;
    PORT
      LAYER M4 ;
        RECT  104.004 45.648 104.088 45.672 ;
    END
  END a[548]
  PIN a[549]
    DIRECTION INPUT ;
    USE SIGNAL ;
    PORT
      LAYER M4 ;
        RECT  104.004 45.744 104.088 45.768 ;
    END
  END a[549]
  PIN a[54]
    DIRECTION INPUT ;
    USE SIGNAL ;
    PORT
      LAYER M4 ;
        RECT  104.004 31.248 104.088 31.272 ;
    END
  END a[54]
  PIN a[550]
    DIRECTION INPUT ;
    USE SIGNAL ;
    PORT
      LAYER M4 ;
        RECT  104.004 45.84 104.088 45.864 ;
    END
  END a[550]
  PIN a[551]
    DIRECTION INPUT ;
    USE SIGNAL ;
    PORT
      LAYER M4 ;
        RECT  104.004 45.936 104.088 45.96 ;
    END
  END a[551]
  PIN a[552]
    DIRECTION INPUT ;
    USE SIGNAL ;
    PORT
      LAYER M4 ;
        RECT  104.004 46.032 104.088 46.056 ;
    END
  END a[552]
  PIN a[553]
    DIRECTION INPUT ;
    USE SIGNAL ;
    PORT
      LAYER M4 ;
        RECT  104.004 46.128 104.088 46.152 ;
    END
  END a[553]
  PIN a[554]
    DIRECTION INPUT ;
    USE SIGNAL ;
    PORT
      LAYER M4 ;
        RECT  104.004 46.224 104.088 46.248 ;
    END
  END a[554]
  PIN a[555]
    DIRECTION INPUT ;
    USE SIGNAL ;
    PORT
      LAYER M4 ;
        RECT  104.004 46.32 104.088 46.344 ;
    END
  END a[555]
  PIN a[556]
    DIRECTION INPUT ;
    USE SIGNAL ;
    PORT
      LAYER M4 ;
        RECT  104.004 46.416 104.088 46.44 ;
    END
  END a[556]
  PIN a[557]
    DIRECTION INPUT ;
    USE SIGNAL ;
    PORT
      LAYER M4 ;
        RECT  104.004 46.512 104.088 46.536 ;
    END
  END a[557]
  PIN a[558]
    DIRECTION INPUT ;
    USE SIGNAL ;
    PORT
      LAYER M4 ;
        RECT  104.004 46.608 104.088 46.632 ;
    END
  END a[558]
  PIN a[559]
    DIRECTION INPUT ;
    USE SIGNAL ;
    PORT
      LAYER M4 ;
        RECT  104.004 46.704 104.088 46.728 ;
    END
  END a[559]
  PIN a[55]
    DIRECTION INPUT ;
    USE SIGNAL ;
    PORT
      LAYER M4 ;
        RECT  104.004 31.344 104.088 31.368 ;
    END
  END a[55]
  PIN a[560]
    DIRECTION INPUT ;
    USE SIGNAL ;
    PORT
      LAYER M4 ;
        RECT  104.004 46.8 104.088 46.824 ;
    END
  END a[560]
  PIN a[561]
    DIRECTION INPUT ;
    USE SIGNAL ;
    PORT
      LAYER M4 ;
        RECT  104.004 46.896 104.088 46.92 ;
    END
  END a[561]
  PIN a[562]
    DIRECTION INPUT ;
    USE SIGNAL ;
    PORT
      LAYER M4 ;
        RECT  104.004 46.992 104.088 47.016 ;
    END
  END a[562]
  PIN a[563]
    DIRECTION INPUT ;
    USE SIGNAL ;
    PORT
      LAYER M4 ;
        RECT  104.004 47.088 104.088 47.112 ;
    END
  END a[563]
  PIN a[564]
    DIRECTION INPUT ;
    USE SIGNAL ;
    PORT
      LAYER M4 ;
        RECT  104.004 47.184 104.088 47.208 ;
    END
  END a[564]
  PIN a[565]
    DIRECTION INPUT ;
    USE SIGNAL ;
    PORT
      LAYER M4 ;
        RECT  104.004 47.28 104.088 47.304 ;
    END
  END a[565]
  PIN a[566]
    DIRECTION INPUT ;
    USE SIGNAL ;
    PORT
      LAYER M4 ;
        RECT  104.004 47.376 104.088 47.4 ;
    END
  END a[566]
  PIN a[567]
    DIRECTION INPUT ;
    USE SIGNAL ;
    PORT
      LAYER M4 ;
        RECT  104.004 47.472 104.088 47.496 ;
    END
  END a[567]
  PIN a[568]
    DIRECTION INPUT ;
    USE SIGNAL ;
    PORT
      LAYER M4 ;
        RECT  104.004 47.568 104.088 47.592 ;
    END
  END a[568]
  PIN a[569]
    DIRECTION INPUT ;
    USE SIGNAL ;
    PORT
      LAYER M4 ;
        RECT  104.004 47.664 104.088 47.688 ;
    END
  END a[569]
  PIN a[56]
    DIRECTION INPUT ;
    USE SIGNAL ;
    PORT
      LAYER M4 ;
        RECT  104.004 31.44 104.088 31.464 ;
    END
  END a[56]
  PIN a[570]
    DIRECTION INPUT ;
    USE SIGNAL ;
    PORT
      LAYER M4 ;
        RECT  104.004 47.76 104.088 47.784 ;
    END
  END a[570]
  PIN a[571]
    DIRECTION INPUT ;
    USE SIGNAL ;
    PORT
      LAYER M4 ;
        RECT  104.004 47.856 104.088 47.88 ;
    END
  END a[571]
  PIN a[572]
    DIRECTION INPUT ;
    USE SIGNAL ;
    PORT
      LAYER M4 ;
        RECT  104.004 47.952 104.088 47.976 ;
    END
  END a[572]
  PIN a[573]
    DIRECTION INPUT ;
    USE SIGNAL ;
    PORT
      LAYER M4 ;
        RECT  104.004 48.048 104.088 48.072 ;
    END
  END a[573]
  PIN a[574]
    DIRECTION INPUT ;
    USE SIGNAL ;
    PORT
      LAYER M4 ;
        RECT  104.004 48.144 104.088 48.168 ;
    END
  END a[574]
  PIN a[575]
    DIRECTION INPUT ;
    USE SIGNAL ;
    PORT
      LAYER M4 ;
        RECT  104.004 48.24 104.088 48.264 ;
    END
  END a[575]
  PIN a[576]
    DIRECTION INPUT ;
    USE SIGNAL ;
    PORT
      LAYER M4 ;
        RECT  104.004 54.48 104.088 54.504 ;
    END
  END a[576]
  PIN a[577]
    DIRECTION INPUT ;
    USE SIGNAL ;
    PORT
      LAYER M4 ;
        RECT  104.004 54.576 104.088 54.6 ;
    END
  END a[577]
  PIN a[578]
    DIRECTION INPUT ;
    USE SIGNAL ;
    PORT
      LAYER M4 ;
        RECT  104.004 54.672 104.088 54.696 ;
    END
  END a[578]
  PIN a[579]
    DIRECTION INPUT ;
    USE SIGNAL ;
    PORT
      LAYER M4 ;
        RECT  104.004 54.768 104.088 54.792 ;
    END
  END a[579]
  PIN a[57]
    DIRECTION INPUT ;
    USE SIGNAL ;
    PORT
      LAYER M4 ;
        RECT  104.004 31.536 104.088 31.56 ;
    END
  END a[57]
  PIN a[580]
    DIRECTION INPUT ;
    USE SIGNAL ;
    PORT
      LAYER M4 ;
        RECT  104.004 54.864 104.088 54.888 ;
    END
  END a[580]
  PIN a[581]
    DIRECTION INPUT ;
    USE SIGNAL ;
    PORT
      LAYER M4 ;
        RECT  104.004 54.96 104.088 54.984 ;
    END
  END a[581]
  PIN a[582]
    DIRECTION INPUT ;
    USE SIGNAL ;
    PORT
      LAYER M4 ;
        RECT  104.004 55.056 104.088 55.08 ;
    END
  END a[582]
  PIN a[583]
    DIRECTION INPUT ;
    USE SIGNAL ;
    PORT
      LAYER M4 ;
        RECT  104.004 55.152 104.088 55.176 ;
    END
  END a[583]
  PIN a[584]
    DIRECTION INPUT ;
    USE SIGNAL ;
    PORT
      LAYER M4 ;
        RECT  104.004 55.248 104.088 55.272 ;
    END
  END a[584]
  PIN a[585]
    DIRECTION INPUT ;
    USE SIGNAL ;
    PORT
      LAYER M4 ;
        RECT  104.004 55.344 104.088 55.368 ;
    END
  END a[585]
  PIN a[586]
    DIRECTION INPUT ;
    USE SIGNAL ;
    PORT
      LAYER M4 ;
        RECT  104.004 55.44 104.088 55.464 ;
    END
  END a[586]
  PIN a[587]
    DIRECTION INPUT ;
    USE SIGNAL ;
    PORT
      LAYER M4 ;
        RECT  104.004 55.536 104.088 55.56 ;
    END
  END a[587]
  PIN a[588]
    DIRECTION INPUT ;
    USE SIGNAL ;
    PORT
      LAYER M4 ;
        RECT  104.004 55.632 104.088 55.656 ;
    END
  END a[588]
  PIN a[589]
    DIRECTION INPUT ;
    USE SIGNAL ;
    PORT
      LAYER M4 ;
        RECT  104.004 55.728 104.088 55.752 ;
    END
  END a[589]
  PIN a[58]
    DIRECTION INPUT ;
    USE SIGNAL ;
    PORT
      LAYER M4 ;
        RECT  104.004 31.632 104.088 31.656 ;
    END
  END a[58]
  PIN a[590]
    DIRECTION INPUT ;
    USE SIGNAL ;
    PORT
      LAYER M4 ;
        RECT  104.004 55.824 104.088 55.848 ;
    END
  END a[590]
  PIN a[591]
    DIRECTION INPUT ;
    USE SIGNAL ;
    PORT
      LAYER M4 ;
        RECT  104.004 55.92 104.088 55.944 ;
    END
  END a[591]
  PIN a[592]
    DIRECTION INPUT ;
    USE SIGNAL ;
    PORT
      LAYER M4 ;
        RECT  104.004 56.016 104.088 56.04 ;
    END
  END a[592]
  PIN a[593]
    DIRECTION INPUT ;
    USE SIGNAL ;
    PORT
      LAYER M4 ;
        RECT  104.004 56.112 104.088 56.136 ;
    END
  END a[593]
  PIN a[594]
    DIRECTION INPUT ;
    USE SIGNAL ;
    PORT
      LAYER M4 ;
        RECT  104.004 56.208 104.088 56.232 ;
    END
  END a[594]
  PIN a[595]
    DIRECTION INPUT ;
    USE SIGNAL ;
    PORT
      LAYER M4 ;
        RECT  104.004 56.304 104.088 56.328 ;
    END
  END a[595]
  PIN a[596]
    DIRECTION INPUT ;
    USE SIGNAL ;
    PORT
      LAYER M4 ;
        RECT  104.004 56.4 104.088 56.424 ;
    END
  END a[596]
  PIN a[597]
    DIRECTION INPUT ;
    USE SIGNAL ;
    PORT
      LAYER M4 ;
        RECT  104.004 56.496 104.088 56.52 ;
    END
  END a[597]
  PIN a[598]
    DIRECTION INPUT ;
    USE SIGNAL ;
    PORT
      LAYER M4 ;
        RECT  104.004 56.592 104.088 56.616 ;
    END
  END a[598]
  PIN a[599]
    DIRECTION INPUT ;
    USE SIGNAL ;
    PORT
      LAYER M4 ;
        RECT  104.004 56.688 104.088 56.712 ;
    END
  END a[599]
  PIN a[59]
    DIRECTION INPUT ;
    USE SIGNAL ;
    PORT
      LAYER M4 ;
        RECT  104.004 31.728 104.088 31.752 ;
    END
  END a[59]
  PIN a[5]
    DIRECTION INPUT ;
    USE SIGNAL ;
    PORT
      LAYER M4 ;
        RECT  104.004 35.76 104.088 35.784 ;
    END
  END a[5]
  PIN a[60]
    DIRECTION INPUT ;
    USE SIGNAL ;
    PORT
      LAYER M4 ;
        RECT  104.004 31.824 104.088 31.848 ;
    END
  END a[60]
  PIN a[61]
    DIRECTION INPUT ;
    USE SIGNAL ;
    PORT
      LAYER M4 ;
        RECT  104.004 31.92 104.088 31.944 ;
    END
  END a[61]
  PIN a[62]
    DIRECTION INPUT ;
    USE SIGNAL ;
    PORT
      LAYER M4 ;
        RECT  104.004 32.016 104.088 32.04 ;
    END
  END a[62]
  PIN a[63]
    DIRECTION INPUT ;
    USE SIGNAL ;
    PORT
      LAYER M4 ;
        RECT  104.004 32.112 104.088 32.136 ;
    END
  END a[63]
  PIN a[64]
    DIRECTION INPUT ;
    USE SIGNAL ;
    PORT
      LAYER M4 ;
        RECT  104.004 26.064 104.088 26.088 ;
    END
  END a[64]
  PIN a[65]
    DIRECTION INPUT ;
    USE SIGNAL ;
    PORT
      LAYER M4 ;
        RECT  104.004 26.16 104.088 26.184 ;
    END
  END a[65]
  PIN a[66]
    DIRECTION INPUT ;
    USE SIGNAL ;
    PORT
      LAYER M4 ;
        RECT  104.004 26.256 104.088 26.28 ;
    END
  END a[66]
  PIN a[67]
    DIRECTION INPUT ;
    USE SIGNAL ;
    PORT
      LAYER M4 ;
        RECT  104.004 26.352 104.088 26.376 ;
    END
  END a[67]
  PIN a[68]
    DIRECTION INPUT ;
    USE SIGNAL ;
    PORT
      LAYER M4 ;
        RECT  104.004 26.448 104.088 26.472 ;
    END
  END a[68]
  PIN a[69]
    DIRECTION INPUT ;
    USE SIGNAL ;
    PORT
      LAYER M4 ;
        RECT  104.004 26.544 104.088 26.568 ;
    END
  END a[69]
  PIN a[6]
    DIRECTION INPUT ;
    USE SIGNAL ;
    PORT
      LAYER M4 ;
        RECT  104.004 35.856 104.088 35.88 ;
    END
  END a[6]
  PIN a[70]
    DIRECTION INPUT ;
    USE SIGNAL ;
    PORT
      LAYER M4 ;
        RECT  104.004 26.64 104.088 26.664 ;
    END
  END a[70]
  PIN a[71]
    DIRECTION INPUT ;
    USE SIGNAL ;
    PORT
      LAYER M4 ;
        RECT  104.004 26.736 104.088 26.76 ;
    END
  END a[71]
  PIN a[72]
    DIRECTION INPUT ;
    USE SIGNAL ;
    PORT
      LAYER M4 ;
        RECT  104.004 26.832 104.088 26.856 ;
    END
  END a[72]
  PIN a[73]
    DIRECTION INPUT ;
    USE SIGNAL ;
    PORT
      LAYER M4 ;
        RECT  104.004 26.928 104.088 26.952 ;
    END
  END a[73]
  PIN a[74]
    DIRECTION INPUT ;
    USE SIGNAL ;
    PORT
      LAYER M4 ;
        RECT  104.004 27.024 104.088 27.048 ;
    END
  END a[74]
  PIN a[75]
    DIRECTION INPUT ;
    USE SIGNAL ;
    PORT
      LAYER M4 ;
        RECT  104.004 27.12 104.088 27.144 ;
    END
  END a[75]
  PIN a[76]
    DIRECTION INPUT ;
    USE SIGNAL ;
    PORT
      LAYER M4 ;
        RECT  104.004 27.216 104.088 27.24 ;
    END
  END a[76]
  PIN a[77]
    DIRECTION INPUT ;
    USE SIGNAL ;
    PORT
      LAYER M4 ;
        RECT  104.004 27.312 104.088 27.336 ;
    END
  END a[77]
  PIN a[78]
    DIRECTION INPUT ;
    USE SIGNAL ;
    PORT
      LAYER M4 ;
        RECT  104.004 27.408 104.088 27.432 ;
    END
  END a[78]
  PIN a[79]
    DIRECTION INPUT ;
    USE SIGNAL ;
    PORT
      LAYER M4 ;
        RECT  104.004 27.504 104.088 27.528 ;
    END
  END a[79]
  PIN a[7]
    DIRECTION INPUT ;
    USE SIGNAL ;
    PORT
      LAYER M4 ;
        RECT  104.004 35.952 104.088 35.976 ;
    END
  END a[7]
  PIN a[80]
    DIRECTION INPUT ;
    USE SIGNAL ;
    PORT
      LAYER M4 ;
        RECT  104.004 27.6 104.088 27.624 ;
    END
  END a[80]
  PIN a[81]
    DIRECTION INPUT ;
    USE SIGNAL ;
    PORT
      LAYER M4 ;
        RECT  104.004 27.696 104.088 27.72 ;
    END
  END a[81]
  PIN a[82]
    DIRECTION INPUT ;
    USE SIGNAL ;
    PORT
      LAYER M4 ;
        RECT  104.004 27.792 104.088 27.816 ;
    END
  END a[82]
  PIN a[83]
    DIRECTION INPUT ;
    USE SIGNAL ;
    PORT
      LAYER M4 ;
        RECT  104.004 27.888 104.088 27.912 ;
    END
  END a[83]
  PIN a[84]
    DIRECTION INPUT ;
    USE SIGNAL ;
    PORT
      LAYER M4 ;
        RECT  104.004 27.984 104.088 28.008 ;
    END
  END a[84]
  PIN a[85]
    DIRECTION INPUT ;
    USE SIGNAL ;
    PORT
      LAYER M4 ;
        RECT  104.004 28.08 104.088 28.104 ;
    END
  END a[85]
  PIN a[86]
    DIRECTION INPUT ;
    USE SIGNAL ;
    PORT
      LAYER M4 ;
        RECT  104.004 28.176 104.088 28.2 ;
    END
  END a[86]
  PIN a[87]
    DIRECTION INPUT ;
    USE SIGNAL ;
    PORT
      LAYER M4 ;
        RECT  104.004 28.272 104.088 28.296 ;
    END
  END a[87]
  PIN a[88]
    DIRECTION INPUT ;
    USE SIGNAL ;
    PORT
      LAYER M4 ;
        RECT  104.004 28.368 104.088 28.392 ;
    END
  END a[88]
  PIN a[89]
    DIRECTION INPUT ;
    USE SIGNAL ;
    PORT
      LAYER M4 ;
        RECT  104.004 28.464 104.088 28.488 ;
    END
  END a[89]
  PIN a[8]
    DIRECTION INPUT ;
    USE SIGNAL ;
    PORT
      LAYER M4 ;
        RECT  104.004 36.048 104.088 36.072 ;
    END
  END a[8]
  PIN a[90]
    DIRECTION INPUT ;
    USE SIGNAL ;
    PORT
      LAYER M4 ;
        RECT  104.004 28.56 104.088 28.584 ;
    END
  END a[90]
  PIN a[91]
    DIRECTION INPUT ;
    USE SIGNAL ;
    PORT
      LAYER M4 ;
        RECT  104.004 28.656 104.088 28.68 ;
    END
  END a[91]
  PIN a[92]
    DIRECTION INPUT ;
    USE SIGNAL ;
    PORT
      LAYER M4 ;
        RECT  104.004 28.752 104.088 28.776 ;
    END
  END a[92]
  PIN a[93]
    DIRECTION INPUT ;
    USE SIGNAL ;
    PORT
      LAYER M4 ;
        RECT  104.004 28.848 104.088 28.872 ;
    END
  END a[93]
  PIN a[94]
    DIRECTION INPUT ;
    USE SIGNAL ;
    PORT
      LAYER M4 ;
        RECT  104.004 28.944 104.088 28.968 ;
    END
  END a[94]
  PIN a[95]
    DIRECTION INPUT ;
    USE SIGNAL ;
    PORT
      LAYER M4 ;
        RECT  104.004 29.04 104.088 29.064 ;
    END
  END a[95]
  PIN a[96]
    DIRECTION INPUT ;
    USE SIGNAL ;
    PORT
      LAYER M4 ;
        RECT  104.004 22.992 104.088 23.016 ;
    END
  END a[96]
  PIN a[97]
    DIRECTION INPUT ;
    USE SIGNAL ;
    PORT
      LAYER M4 ;
        RECT  104.004 23.088 104.088 23.112 ;
    END
  END a[97]
  PIN a[98]
    DIRECTION INPUT ;
    USE SIGNAL ;
    PORT
      LAYER M4 ;
        RECT  104.004 23.184 104.088 23.208 ;
    END
  END a[98]
  PIN a[99]
    DIRECTION INPUT ;
    USE SIGNAL ;
    PORT
      LAYER M4 ;
        RECT  104.004 23.28 104.088 23.304 ;
    END
  END a[99]
  PIN a[9]
    DIRECTION INPUT ;
    USE SIGNAL ;
    PORT
      LAYER M4 ;
        RECT  104.004 36.144 104.088 36.168 ;
    END
  END a[9]
  PIN b[0]
    DIRECTION OUTPUT ;
    USE SIGNAL ;
    PORT
      LAYER M3 ;
        RECT  48.852 105.779 48.87 105.816 ;
    END
  END b[0]
  PIN b[100]
    DIRECTION OUTPUT ;
    USE SIGNAL ;
    PORT
      LAYER M5 ;
        RECT  53.136 105.732 53.16 105.816 ;
    END
  END b[100]
  PIN b[101]
    DIRECTION OUTPUT ;
    USE SIGNAL ;
    PORT
      LAYER M5 ;
        RECT  53.232 105.732 53.256 105.816 ;
    END
  END b[101]
  PIN b[102]
    DIRECTION OUTPUT ;
    USE SIGNAL ;
    PORT
      LAYER M5 ;
        RECT  53.328 105.732 53.352 105.816 ;
    END
  END b[102]
  PIN b[103]
    DIRECTION OUTPUT ;
    USE SIGNAL ;
    PORT
      LAYER M5 ;
        RECT  53.424 105.732 53.448 105.816 ;
    END
  END b[103]
  PIN b[104]
    DIRECTION OUTPUT ;
    USE SIGNAL ;
    PORT
      LAYER M5 ;
        RECT  53.52 105.732 53.544 105.816 ;
    END
  END b[104]
  PIN b[105]
    DIRECTION OUTPUT ;
    USE SIGNAL ;
    PORT
      LAYER M5 ;
        RECT  53.616 105.732 53.64 105.816 ;
    END
  END b[105]
  PIN b[106]
    DIRECTION OUTPUT ;
    USE SIGNAL ;
    PORT
      LAYER M5 ;
        RECT  53.712 105.732 53.736 105.816 ;
    END
  END b[106]
  PIN b[107]
    DIRECTION OUTPUT ;
    USE SIGNAL ;
    PORT
      LAYER M5 ;
        RECT  53.808 105.732 53.832 105.816 ;
    END
  END b[107]
  PIN b[108]
    DIRECTION OUTPUT ;
    USE SIGNAL ;
    PORT
      LAYER M5 ;
        RECT  53.904 105.732 53.928 105.816 ;
    END
  END b[108]
  PIN b[109]
    DIRECTION OUTPUT ;
    USE SIGNAL ;
    PORT
      LAYER M5 ;
        RECT  54 105.732 54.024 105.816 ;
    END
  END b[109]
  PIN b[10]
    DIRECTION OUTPUT ;
    USE SIGNAL ;
    PORT
      LAYER M3 ;
        RECT  49.572 105.779 49.59 105.816 ;
    END
  END b[10]
  PIN b[110]
    DIRECTION OUTPUT ;
    USE SIGNAL ;
    PORT
      LAYER M5 ;
        RECT  54.096 105.732 54.12 105.816 ;
    END
  END b[110]
  PIN b[111]
    DIRECTION OUTPUT ;
    USE SIGNAL ;
    PORT
      LAYER M5 ;
        RECT  54.192 105.732 54.216 105.816 ;
    END
  END b[111]
  PIN b[112]
    DIRECTION OUTPUT ;
    USE SIGNAL ;
    PORT
      LAYER M5 ;
        RECT  54.288 105.732 54.312 105.816 ;
    END
  END b[112]
  PIN b[113]
    DIRECTION OUTPUT ;
    USE SIGNAL ;
    PORT
      LAYER M5 ;
        RECT  54.384 105.732 54.408 105.816 ;
    END
  END b[113]
  PIN b[114]
    DIRECTION OUTPUT ;
    USE SIGNAL ;
    PORT
      LAYER M5 ;
        RECT  54.48 105.732 54.504 105.816 ;
    END
  END b[114]
  PIN b[115]
    DIRECTION OUTPUT ;
    USE SIGNAL ;
    PORT
      LAYER M5 ;
        RECT  54.576 105.732 54.6 105.816 ;
    END
  END b[115]
  PIN b[116]
    DIRECTION OUTPUT ;
    USE SIGNAL ;
    PORT
      LAYER M5 ;
        RECT  54.672 105.732 54.696 105.816 ;
    END
  END b[116]
  PIN b[117]
    DIRECTION OUTPUT ;
    USE SIGNAL ;
    PORT
      LAYER M5 ;
        RECT  54.768 105.732 54.792 105.816 ;
    END
  END b[117]
  PIN b[118]
    DIRECTION OUTPUT ;
    USE SIGNAL ;
    PORT
      LAYER M5 ;
        RECT  54.864 105.732 54.888 105.816 ;
    END
  END b[118]
  PIN b[119]
    DIRECTION OUTPUT ;
    USE SIGNAL ;
    PORT
      LAYER M5 ;
        RECT  54.96 105.732 54.984 105.816 ;
    END
  END b[119]
  PIN b[11]
    DIRECTION OUTPUT ;
    USE SIGNAL ;
    PORT
      LAYER M3 ;
        RECT  49.644 105.779 49.662 105.816 ;
    END
  END b[11]
  PIN b[120]
    DIRECTION OUTPUT ;
    USE SIGNAL ;
    PORT
      LAYER M5 ;
        RECT  55.056 105.732 55.08 105.816 ;
    END
  END b[120]
  PIN b[121]
    DIRECTION OUTPUT ;
    USE SIGNAL ;
    PORT
      LAYER M5 ;
        RECT  55.152 105.732 55.176 105.816 ;
    END
  END b[121]
  PIN b[122]
    DIRECTION OUTPUT ;
    USE SIGNAL ;
    PORT
      LAYER M5 ;
        RECT  55.248 105.732 55.272 105.816 ;
    END
  END b[122]
  PIN b[123]
    DIRECTION OUTPUT ;
    USE SIGNAL ;
    PORT
      LAYER M5 ;
        RECT  55.344 105.732 55.368 105.816 ;
    END
  END b[123]
  PIN b[124]
    DIRECTION OUTPUT ;
    USE SIGNAL ;
    PORT
      LAYER M5 ;
        RECT  55.44 105.732 55.464 105.816 ;
    END
  END b[124]
  PIN b[125]
    DIRECTION OUTPUT ;
    USE SIGNAL ;
    PORT
      LAYER M5 ;
        RECT  55.536 105.732 55.56 105.816 ;
    END
  END b[125]
  PIN b[126]
    DIRECTION OUTPUT ;
    USE SIGNAL ;
    PORT
      LAYER M5 ;
        RECT  55.632 105.732 55.656 105.816 ;
    END
  END b[126]
  PIN b[127]
    DIRECTION OUTPUT ;
    USE SIGNAL ;
    PORT
      LAYER M5 ;
        RECT  55.728 105.732 55.752 105.816 ;
    END
  END b[127]
  PIN b[128]
    DIRECTION OUTPUT ;
    USE SIGNAL ;
    PORT
      LAYER M5 ;
        RECT  68.88 105.732 68.904 105.816 ;
    END
  END b[128]
  PIN b[129]
    DIRECTION OUTPUT ;
    USE SIGNAL ;
    PORT
      LAYER M5 ;
        RECT  68.976 105.732 69 105.816 ;
    END
  END b[129]
  PIN b[12]
    DIRECTION OUTPUT ;
    USE SIGNAL ;
    PORT
      LAYER M3 ;
        RECT  49.716 105.779 49.734 105.816 ;
    END
  END b[12]
  PIN b[130]
    DIRECTION OUTPUT ;
    USE SIGNAL ;
    PORT
      LAYER M5 ;
        RECT  69.072 105.732 69.096 105.816 ;
    END
  END b[130]
  PIN b[131]
    DIRECTION OUTPUT ;
    USE SIGNAL ;
    PORT
      LAYER M5 ;
        RECT  69.168 105.732 69.192 105.816 ;
    END
  END b[131]
  PIN b[132]
    DIRECTION OUTPUT ;
    USE SIGNAL ;
    PORT
      LAYER M5 ;
        RECT  69.264 105.732 69.288 105.816 ;
    END
  END b[132]
  PIN b[133]
    DIRECTION OUTPUT ;
    USE SIGNAL ;
    PORT
      LAYER M5 ;
        RECT  69.36 105.732 69.384 105.816 ;
    END
  END b[133]
  PIN b[134]
    DIRECTION OUTPUT ;
    USE SIGNAL ;
    PORT
      LAYER M5 ;
        RECT  69.456 105.732 69.48 105.816 ;
    END
  END b[134]
  PIN b[135]
    DIRECTION OUTPUT ;
    USE SIGNAL ;
    PORT
      LAYER M5 ;
        RECT  69.552 105.732 69.576 105.816 ;
    END
  END b[135]
  PIN b[136]
    DIRECTION OUTPUT ;
    USE SIGNAL ;
    PORT
      LAYER M5 ;
        RECT  69.648 105.732 69.672 105.816 ;
    END
  END b[136]
  PIN b[137]
    DIRECTION OUTPUT ;
    USE SIGNAL ;
    PORT
      LAYER M5 ;
        RECT  69.744 105.732 69.768 105.816 ;
    END
  END b[137]
  PIN b[138]
    DIRECTION OUTPUT ;
    USE SIGNAL ;
    PORT
      LAYER M5 ;
        RECT  69.84 105.732 69.864 105.816 ;
    END
  END b[138]
  PIN b[139]
    DIRECTION OUTPUT ;
    USE SIGNAL ;
    PORT
      LAYER M5 ;
        RECT  69.936 105.732 69.96 105.816 ;
    END
  END b[139]
  PIN b[13]
    DIRECTION OUTPUT ;
    USE SIGNAL ;
    PORT
      LAYER M3 ;
        RECT  49.788 105.779 49.806 105.816 ;
    END
  END b[13]
  PIN b[140]
    DIRECTION OUTPUT ;
    USE SIGNAL ;
    PORT
      LAYER M5 ;
        RECT  70.032 105.732 70.056 105.816 ;
    END
  END b[140]
  PIN b[141]
    DIRECTION OUTPUT ;
    USE SIGNAL ;
    PORT
      LAYER M5 ;
        RECT  70.128 105.732 70.152 105.816 ;
    END
  END b[141]
  PIN b[142]
    DIRECTION OUTPUT ;
    USE SIGNAL ;
    PORT
      LAYER M5 ;
        RECT  70.224 105.732 70.248 105.816 ;
    END
  END b[142]
  PIN b[143]
    DIRECTION OUTPUT ;
    USE SIGNAL ;
    PORT
      LAYER M5 ;
        RECT  70.32 105.732 70.344 105.816 ;
    END
  END b[143]
  PIN b[144]
    DIRECTION OUTPUT ;
    USE SIGNAL ;
    PORT
      LAYER M5 ;
        RECT  70.416 105.732 70.44 105.816 ;
    END
  END b[144]
  PIN b[145]
    DIRECTION OUTPUT ;
    USE SIGNAL ;
    PORT
      LAYER M5 ;
        RECT  70.512 105.732 70.536 105.816 ;
    END
  END b[145]
  PIN b[146]
    DIRECTION OUTPUT ;
    USE SIGNAL ;
    PORT
      LAYER M5 ;
        RECT  70.608 105.732 70.632 105.816 ;
    END
  END b[146]
  PIN b[147]
    DIRECTION OUTPUT ;
    USE SIGNAL ;
    PORT
      LAYER M5 ;
        RECT  70.704 105.732 70.728 105.816 ;
    END
  END b[147]
  PIN b[148]
    DIRECTION OUTPUT ;
    USE SIGNAL ;
    PORT
      LAYER M5 ;
        RECT  70.8 105.732 70.824 105.816 ;
    END
  END b[148]
  PIN b[149]
    DIRECTION OUTPUT ;
    USE SIGNAL ;
    PORT
      LAYER M5 ;
        RECT  70.896 105.732 70.92 105.816 ;
    END
  END b[149]
  PIN b[14]
    DIRECTION OUTPUT ;
    USE SIGNAL ;
    PORT
      LAYER M3 ;
        RECT  49.86 105.779 49.878 105.816 ;
    END
  END b[14]
  PIN b[150]
    DIRECTION OUTPUT ;
    USE SIGNAL ;
    PORT
      LAYER M5 ;
        RECT  70.992 105.732 71.016 105.816 ;
    END
  END b[150]
  PIN b[151]
    DIRECTION OUTPUT ;
    USE SIGNAL ;
    PORT
      LAYER M5 ;
        RECT  71.088 105.732 71.112 105.816 ;
    END
  END b[151]
  PIN b[152]
    DIRECTION OUTPUT ;
    USE SIGNAL ;
    PORT
      LAYER M5 ;
        RECT  71.184 105.732 71.208 105.816 ;
    END
  END b[152]
  PIN b[153]
    DIRECTION OUTPUT ;
    USE SIGNAL ;
    PORT
      LAYER M5 ;
        RECT  71.28 105.732 71.304 105.816 ;
    END
  END b[153]
  PIN b[154]
    DIRECTION OUTPUT ;
    USE SIGNAL ;
    PORT
      LAYER M5 ;
        RECT  71.376 105.732 71.4 105.816 ;
    END
  END b[154]
  PIN b[155]
    DIRECTION OUTPUT ;
    USE SIGNAL ;
    PORT
      LAYER M5 ;
        RECT  71.472 105.732 71.496 105.816 ;
    END
  END b[155]
  PIN b[156]
    DIRECTION OUTPUT ;
    USE SIGNAL ;
    PORT
      LAYER M5 ;
        RECT  71.568 105.732 71.592 105.816 ;
    END
  END b[156]
  PIN b[157]
    DIRECTION OUTPUT ;
    USE SIGNAL ;
    PORT
      LAYER M5 ;
        RECT  71.664 105.732 71.688 105.816 ;
    END
  END b[157]
  PIN b[158]
    DIRECTION OUTPUT ;
    USE SIGNAL ;
    PORT
      LAYER M5 ;
        RECT  71.76 105.732 71.784 105.816 ;
    END
  END b[158]
  PIN b[159]
    DIRECTION OUTPUT ;
    USE SIGNAL ;
    PORT
      LAYER M5 ;
        RECT  71.856 105.732 71.88 105.816 ;
    END
  END b[159]
  PIN b[15]
    DIRECTION OUTPUT ;
    USE SIGNAL ;
    PORT
      LAYER M3 ;
        RECT  49.932 105.779 49.95 105.816 ;
    END
  END b[15]
  PIN b[160]
    DIRECTION OUTPUT ;
    USE SIGNAL ;
    PORT
      LAYER M5 ;
        RECT  71.952 105.732 71.976 105.816 ;
    END
  END b[160]
  PIN b[161]
    DIRECTION OUTPUT ;
    USE SIGNAL ;
    PORT
      LAYER M5 ;
        RECT  72.048 105.732 72.072 105.816 ;
    END
  END b[161]
  PIN b[162]
    DIRECTION OUTPUT ;
    USE SIGNAL ;
    PORT
      LAYER M5 ;
        RECT  72.144 105.732 72.168 105.816 ;
    END
  END b[162]
  PIN b[163]
    DIRECTION OUTPUT ;
    USE SIGNAL ;
    PORT
      LAYER M5 ;
        RECT  72.24 105.732 72.264 105.816 ;
    END
  END b[163]
  PIN b[164]
    DIRECTION OUTPUT ;
    USE SIGNAL ;
    PORT
      LAYER M5 ;
        RECT  72.336 105.732 72.36 105.816 ;
    END
  END b[164]
  PIN b[165]
    DIRECTION OUTPUT ;
    USE SIGNAL ;
    PORT
      LAYER M5 ;
        RECT  72.432 105.732 72.456 105.816 ;
    END
  END b[165]
  PIN b[166]
    DIRECTION OUTPUT ;
    USE SIGNAL ;
    PORT
      LAYER M5 ;
        RECT  72.528 105.732 72.552 105.816 ;
    END
  END b[166]
  PIN b[167]
    DIRECTION OUTPUT ;
    USE SIGNAL ;
    PORT
      LAYER M5 ;
        RECT  72.624 105.732 72.648 105.816 ;
    END
  END b[167]
  PIN b[168]
    DIRECTION OUTPUT ;
    USE SIGNAL ;
    PORT
      LAYER M5 ;
        RECT  72.72 105.732 72.744 105.816 ;
    END
  END b[168]
  PIN b[169]
    DIRECTION OUTPUT ;
    USE SIGNAL ;
    PORT
      LAYER M5 ;
        RECT  72.816 105.732 72.84 105.816 ;
    END
  END b[169]
  PIN b[16]
    DIRECTION OUTPUT ;
    USE SIGNAL ;
    PORT
      LAYER M3 ;
        RECT  50.004 105.779 50.022 105.816 ;
    END
  END b[16]
  PIN b[170]
    DIRECTION OUTPUT ;
    USE SIGNAL ;
    PORT
      LAYER M5 ;
        RECT  72.912 105.732 72.936 105.816 ;
    END
  END b[170]
  PIN b[171]
    DIRECTION OUTPUT ;
    USE SIGNAL ;
    PORT
      LAYER M5 ;
        RECT  73.008 105.732 73.032 105.816 ;
    END
  END b[171]
  PIN b[172]
    DIRECTION OUTPUT ;
    USE SIGNAL ;
    PORT
      LAYER M5 ;
        RECT  73.104 105.732 73.128 105.816 ;
    END
  END b[172]
  PIN b[173]
    DIRECTION OUTPUT ;
    USE SIGNAL ;
    PORT
      LAYER M5 ;
        RECT  73.2 105.732 73.224 105.816 ;
    END
  END b[173]
  PIN b[174]
    DIRECTION OUTPUT ;
    USE SIGNAL ;
    PORT
      LAYER M5 ;
        RECT  73.296 105.732 73.32 105.816 ;
    END
  END b[174]
  PIN b[175]
    DIRECTION OUTPUT ;
    USE SIGNAL ;
    PORT
      LAYER M5 ;
        RECT  73.392 105.732 73.416 105.816 ;
    END
  END b[175]
  PIN b[176]
    DIRECTION OUTPUT ;
    USE SIGNAL ;
    PORT
      LAYER M5 ;
        RECT  73.488 105.732 73.512 105.816 ;
    END
  END b[176]
  PIN b[177]
    DIRECTION OUTPUT ;
    USE SIGNAL ;
    PORT
      LAYER M5 ;
        RECT  73.584 105.732 73.608 105.816 ;
    END
  END b[177]
  PIN b[178]
    DIRECTION OUTPUT ;
    USE SIGNAL ;
    PORT
      LAYER M5 ;
        RECT  73.68 105.732 73.704 105.816 ;
    END
  END b[178]
  PIN b[179]
    DIRECTION OUTPUT ;
    USE SIGNAL ;
    PORT
      LAYER M5 ;
        RECT  73.776 105.732 73.8 105.816 ;
    END
  END b[179]
  PIN b[17]
    DIRECTION OUTPUT ;
    USE SIGNAL ;
    PORT
      LAYER M3 ;
        RECT  50.076 105.779 50.094 105.816 ;
    END
  END b[17]
  PIN b[180]
    DIRECTION OUTPUT ;
    USE SIGNAL ;
    PORT
      LAYER M5 ;
        RECT  73.872 105.732 73.896 105.816 ;
    END
  END b[180]
  PIN b[181]
    DIRECTION OUTPUT ;
    USE SIGNAL ;
    PORT
      LAYER M5 ;
        RECT  73.968 105.732 73.992 105.816 ;
    END
  END b[181]
  PIN b[182]
    DIRECTION OUTPUT ;
    USE SIGNAL ;
    PORT
      LAYER M5 ;
        RECT  74.064 105.732 74.088 105.816 ;
    END
  END b[182]
  PIN b[183]
    DIRECTION OUTPUT ;
    USE SIGNAL ;
    PORT
      LAYER M5 ;
        RECT  74.16 105.732 74.184 105.816 ;
    END
  END b[183]
  PIN b[184]
    DIRECTION OUTPUT ;
    USE SIGNAL ;
    PORT
      LAYER M5 ;
        RECT  74.256 105.732 74.28 105.816 ;
    END
  END b[184]
  PIN b[185]
    DIRECTION OUTPUT ;
    USE SIGNAL ;
    PORT
      LAYER M5 ;
        RECT  74.352 105.732 74.376 105.816 ;
    END
  END b[185]
  PIN b[186]
    DIRECTION OUTPUT ;
    USE SIGNAL ;
    PORT
      LAYER M5 ;
        RECT  74.448 105.732 74.472 105.816 ;
    END
  END b[186]
  PIN b[187]
    DIRECTION OUTPUT ;
    USE SIGNAL ;
    PORT
      LAYER M5 ;
        RECT  74.544 105.732 74.568 105.816 ;
    END
  END b[187]
  PIN b[188]
    DIRECTION OUTPUT ;
    USE SIGNAL ;
    PORT
      LAYER M5 ;
        RECT  74.64 105.732 74.664 105.816 ;
    END
  END b[188]
  PIN b[189]
    DIRECTION OUTPUT ;
    USE SIGNAL ;
    PORT
      LAYER M5 ;
        RECT  74.736 105.732 74.76 105.816 ;
    END
  END b[189]
  PIN b[18]
    DIRECTION OUTPUT ;
    USE SIGNAL ;
    PORT
      LAYER M3 ;
        RECT  50.148 105.779 50.166 105.816 ;
    END
  END b[18]
  PIN b[190]
    DIRECTION OUTPUT ;
    USE SIGNAL ;
    PORT
      LAYER M5 ;
        RECT  74.832 105.732 74.856 105.816 ;
    END
  END b[190]
  PIN b[191]
    DIRECTION OUTPUT ;
    USE SIGNAL ;
    PORT
      LAYER M5 ;
        RECT  74.928 105.732 74.952 105.816 ;
    END
  END b[191]
  PIN b[192]
    DIRECTION OUTPUT ;
    USE SIGNAL ;
    PORT
      LAYER M5 ;
        RECT  55.824 105.732 55.848 105.816 ;
    END
  END b[192]
  PIN b[193]
    DIRECTION OUTPUT ;
    USE SIGNAL ;
    PORT
      LAYER M5 ;
        RECT  55.92 105.732 55.944 105.816 ;
    END
  END b[193]
  PIN b[194]
    DIRECTION OUTPUT ;
    USE SIGNAL ;
    PORT
      LAYER M5 ;
        RECT  56.016 105.732 56.04 105.816 ;
    END
  END b[194]
  PIN b[195]
    DIRECTION OUTPUT ;
    USE SIGNAL ;
    PORT
      LAYER M5 ;
        RECT  56.112 105.732 56.136 105.816 ;
    END
  END b[195]
  PIN b[196]
    DIRECTION OUTPUT ;
    USE SIGNAL ;
    PORT
      LAYER M5 ;
        RECT  56.208 105.732 56.232 105.816 ;
    END
  END b[196]
  PIN b[197]
    DIRECTION OUTPUT ;
    USE SIGNAL ;
    PORT
      LAYER M5 ;
        RECT  56.304 105.732 56.328 105.816 ;
    END
  END b[197]
  PIN b[198]
    DIRECTION OUTPUT ;
    USE SIGNAL ;
    PORT
      LAYER M5 ;
        RECT  56.4 105.732 56.424 105.816 ;
    END
  END b[198]
  PIN b[199]
    DIRECTION OUTPUT ;
    USE SIGNAL ;
    PORT
      LAYER M5 ;
        RECT  56.496 105.732 56.52 105.816 ;
    END
  END b[199]
  PIN b[19]
    DIRECTION OUTPUT ;
    USE SIGNAL ;
    PORT
      LAYER M3 ;
        RECT  50.22 105.779 50.238 105.816 ;
    END
  END b[19]
  PIN b[1]
    DIRECTION OUTPUT ;
    USE SIGNAL ;
    PORT
      LAYER M3 ;
        RECT  48.924 105.779 48.942 105.816 ;
    END
  END b[1]
  PIN b[200]
    DIRECTION OUTPUT ;
    USE SIGNAL ;
    PORT
      LAYER M5 ;
        RECT  56.592 105.732 56.616 105.816 ;
    END
  END b[200]
  PIN b[201]
    DIRECTION OUTPUT ;
    USE SIGNAL ;
    PORT
      LAYER M5 ;
        RECT  56.688 105.732 56.712 105.816 ;
    END
  END b[201]
  PIN b[202]
    DIRECTION OUTPUT ;
    USE SIGNAL ;
    PORT
      LAYER M5 ;
        RECT  56.784 105.732 56.808 105.816 ;
    END
  END b[202]
  PIN b[203]
    DIRECTION OUTPUT ;
    USE SIGNAL ;
    PORT
      LAYER M5 ;
        RECT  56.88 105.732 56.904 105.816 ;
    END
  END b[203]
  PIN b[204]
    DIRECTION OUTPUT ;
    USE SIGNAL ;
    PORT
      LAYER M5 ;
        RECT  56.976 105.732 57 105.816 ;
    END
  END b[204]
  PIN b[205]
    DIRECTION OUTPUT ;
    USE SIGNAL ;
    PORT
      LAYER M5 ;
        RECT  57.072 105.732 57.096 105.816 ;
    END
  END b[205]
  PIN b[206]
    DIRECTION OUTPUT ;
    USE SIGNAL ;
    PORT
      LAYER M5 ;
        RECT  57.168 105.732 57.192 105.816 ;
    END
  END b[206]
  PIN b[207]
    DIRECTION OUTPUT ;
    USE SIGNAL ;
    PORT
      LAYER M5 ;
        RECT  57.264 105.732 57.288 105.816 ;
    END
  END b[207]
  PIN b[208]
    DIRECTION OUTPUT ;
    USE SIGNAL ;
    PORT
      LAYER M5 ;
        RECT  57.36 105.732 57.384 105.816 ;
    END
  END b[208]
  PIN b[209]
    DIRECTION OUTPUT ;
    USE SIGNAL ;
    PORT
      LAYER M5 ;
        RECT  57.456 105.732 57.48 105.816 ;
    END
  END b[209]
  PIN b[20]
    DIRECTION OUTPUT ;
    USE SIGNAL ;
    PORT
      LAYER M3 ;
        RECT  50.292 105.779 50.31 105.816 ;
    END
  END b[20]
  PIN b[210]
    DIRECTION OUTPUT ;
    USE SIGNAL ;
    PORT
      LAYER M5 ;
        RECT  57.552 105.732 57.576 105.816 ;
    END
  END b[210]
  PIN b[211]
    DIRECTION OUTPUT ;
    USE SIGNAL ;
    PORT
      LAYER M5 ;
        RECT  57.648 105.732 57.672 105.816 ;
    END
  END b[211]
  PIN b[212]
    DIRECTION OUTPUT ;
    USE SIGNAL ;
    PORT
      LAYER M5 ;
        RECT  57.744 105.732 57.768 105.816 ;
    END
  END b[212]
  PIN b[213]
    DIRECTION OUTPUT ;
    USE SIGNAL ;
    PORT
      LAYER M5 ;
        RECT  57.84 105.732 57.864 105.816 ;
    END
  END b[213]
  PIN b[214]
    DIRECTION OUTPUT ;
    USE SIGNAL ;
    PORT
      LAYER M5 ;
        RECT  57.936 105.732 57.96 105.816 ;
    END
  END b[214]
  PIN b[215]
    DIRECTION OUTPUT ;
    USE SIGNAL ;
    PORT
      LAYER M5 ;
        RECT  58.032 105.732 58.056 105.816 ;
    END
  END b[215]
  PIN b[216]
    DIRECTION OUTPUT ;
    USE SIGNAL ;
    PORT
      LAYER M5 ;
        RECT  58.128 105.732 58.152 105.816 ;
    END
  END b[216]
  PIN b[217]
    DIRECTION OUTPUT ;
    USE SIGNAL ;
    PORT
      LAYER M5 ;
        RECT  58.224 105.732 58.248 105.816 ;
    END
  END b[217]
  PIN b[218]
    DIRECTION OUTPUT ;
    USE SIGNAL ;
    PORT
      LAYER M5 ;
        RECT  58.32 105.732 58.344 105.816 ;
    END
  END b[218]
  PIN b[219]
    DIRECTION OUTPUT ;
    USE SIGNAL ;
    PORT
      LAYER M5 ;
        RECT  58.416 105.732 58.44 105.816 ;
    END
  END b[219]
  PIN b[21]
    DIRECTION OUTPUT ;
    USE SIGNAL ;
    PORT
      LAYER M3 ;
        RECT  50.364 105.779 50.382 105.816 ;
    END
  END b[21]
  PIN b[220]
    DIRECTION OUTPUT ;
    USE SIGNAL ;
    PORT
      LAYER M5 ;
        RECT  58.512 105.732 58.536 105.816 ;
    END
  END b[220]
  PIN b[221]
    DIRECTION OUTPUT ;
    USE SIGNAL ;
    PORT
      LAYER M5 ;
        RECT  58.608 105.732 58.632 105.816 ;
    END
  END b[221]
  PIN b[222]
    DIRECTION OUTPUT ;
    USE SIGNAL ;
    PORT
      LAYER M5 ;
        RECT  58.704 105.732 58.728 105.816 ;
    END
  END b[222]
  PIN b[223]
    DIRECTION OUTPUT ;
    USE SIGNAL ;
    PORT
      LAYER M5 ;
        RECT  58.8 105.732 58.824 105.816 ;
    END
  END b[223]
  PIN b[224]
    DIRECTION OUTPUT ;
    USE SIGNAL ;
    PORT
      LAYER M5 ;
        RECT  78.096 105.732 78.12 105.816 ;
    END
  END b[224]
  PIN b[225]
    DIRECTION OUTPUT ;
    USE SIGNAL ;
    PORT
      LAYER M5 ;
        RECT  78.192 105.732 78.216 105.816 ;
    END
  END b[225]
  PIN b[226]
    DIRECTION OUTPUT ;
    USE SIGNAL ;
    PORT
      LAYER M5 ;
        RECT  78.288 105.732 78.312 105.816 ;
    END
  END b[226]
  PIN b[227]
    DIRECTION OUTPUT ;
    USE SIGNAL ;
    PORT
      LAYER M5 ;
        RECT  78.384 105.732 78.408 105.816 ;
    END
  END b[227]
  PIN b[228]
    DIRECTION OUTPUT ;
    USE SIGNAL ;
    PORT
      LAYER M5 ;
        RECT  78.48 105.732 78.504 105.816 ;
    END
  END b[228]
  PIN b[229]
    DIRECTION OUTPUT ;
    USE SIGNAL ;
    PORT
      LAYER M5 ;
        RECT  78.576 105.732 78.6 105.816 ;
    END
  END b[229]
  PIN b[22]
    DIRECTION OUTPUT ;
    USE SIGNAL ;
    PORT
      LAYER M3 ;
        RECT  50.436 105.779 50.454 105.816 ;
    END
  END b[22]
  PIN b[230]
    DIRECTION OUTPUT ;
    USE SIGNAL ;
    PORT
      LAYER M5 ;
        RECT  78.672 105.732 78.696 105.816 ;
    END
  END b[230]
  PIN b[231]
    DIRECTION OUTPUT ;
    USE SIGNAL ;
    PORT
      LAYER M5 ;
        RECT  78.768 105.732 78.792 105.816 ;
    END
  END b[231]
  PIN b[232]
    DIRECTION OUTPUT ;
    USE SIGNAL ;
    PORT
      LAYER M5 ;
        RECT  78.864 105.732 78.888 105.816 ;
    END
  END b[232]
  PIN b[233]
    DIRECTION OUTPUT ;
    USE SIGNAL ;
    PORT
      LAYER M5 ;
        RECT  78.96 105.732 78.984 105.816 ;
    END
  END b[233]
  PIN b[234]
    DIRECTION OUTPUT ;
    USE SIGNAL ;
    PORT
      LAYER M5 ;
        RECT  79.056 105.732 79.08 105.816 ;
    END
  END b[234]
  PIN b[235]
    DIRECTION OUTPUT ;
    USE SIGNAL ;
    PORT
      LAYER M5 ;
        RECT  79.152 105.732 79.176 105.816 ;
    END
  END b[235]
  PIN b[236]
    DIRECTION OUTPUT ;
    USE SIGNAL ;
    PORT
      LAYER M5 ;
        RECT  79.248 105.732 79.272 105.816 ;
    END
  END b[236]
  PIN b[237]
    DIRECTION OUTPUT ;
    USE SIGNAL ;
    PORT
      LAYER M5 ;
        RECT  79.344 105.732 79.368 105.816 ;
    END
  END b[237]
  PIN b[238]
    DIRECTION OUTPUT ;
    USE SIGNAL ;
    PORT
      LAYER M5 ;
        RECT  79.44 105.732 79.464 105.816 ;
    END
  END b[238]
  PIN b[239]
    DIRECTION OUTPUT ;
    USE SIGNAL ;
    PORT
      LAYER M5 ;
        RECT  79.536 105.732 79.56 105.816 ;
    END
  END b[239]
  PIN b[23]
    DIRECTION OUTPUT ;
    USE SIGNAL ;
    PORT
      LAYER M3 ;
        RECT  50.508 105.779 50.526 105.816 ;
    END
  END b[23]
  PIN b[240]
    DIRECTION OUTPUT ;
    USE SIGNAL ;
    PORT
      LAYER M5 ;
        RECT  79.632 105.732 79.656 105.816 ;
    END
  END b[240]
  PIN b[241]
    DIRECTION OUTPUT ;
    USE SIGNAL ;
    PORT
      LAYER M5 ;
        RECT  79.728 105.732 79.752 105.816 ;
    END
  END b[241]
  PIN b[242]
    DIRECTION OUTPUT ;
    USE SIGNAL ;
    PORT
      LAYER M5 ;
        RECT  79.824 105.732 79.848 105.816 ;
    END
  END b[242]
  PIN b[243]
    DIRECTION OUTPUT ;
    USE SIGNAL ;
    PORT
      LAYER M5 ;
        RECT  79.92 105.732 79.944 105.816 ;
    END
  END b[243]
  PIN b[244]
    DIRECTION OUTPUT ;
    USE SIGNAL ;
    PORT
      LAYER M5 ;
        RECT  80.016 105.732 80.04 105.816 ;
    END
  END b[244]
  PIN b[245]
    DIRECTION OUTPUT ;
    USE SIGNAL ;
    PORT
      LAYER M5 ;
        RECT  80.112 105.732 80.136 105.816 ;
    END
  END b[245]
  PIN b[246]
    DIRECTION OUTPUT ;
    USE SIGNAL ;
    PORT
      LAYER M5 ;
        RECT  80.208 105.732 80.232 105.816 ;
    END
  END b[246]
  PIN b[247]
    DIRECTION OUTPUT ;
    USE SIGNAL ;
    PORT
      LAYER M5 ;
        RECT  80.304 105.732 80.328 105.816 ;
    END
  END b[247]
  PIN b[248]
    DIRECTION OUTPUT ;
    USE SIGNAL ;
    PORT
      LAYER M5 ;
        RECT  80.4 105.732 80.424 105.816 ;
    END
  END b[248]
  PIN b[249]
    DIRECTION OUTPUT ;
    USE SIGNAL ;
    PORT
      LAYER M5 ;
        RECT  80.496 105.732 80.52 105.816 ;
    END
  END b[249]
  PIN b[24]
    DIRECTION OUTPUT ;
    USE SIGNAL ;
    PORT
      LAYER M3 ;
        RECT  50.58 105.779 50.598 105.816 ;
    END
  END b[24]
  PIN b[250]
    DIRECTION OUTPUT ;
    USE SIGNAL ;
    PORT
      LAYER M5 ;
        RECT  80.592 105.732 80.616 105.816 ;
    END
  END b[250]
  PIN b[251]
    DIRECTION OUTPUT ;
    USE SIGNAL ;
    PORT
      LAYER M5 ;
        RECT  80.688 105.732 80.712 105.816 ;
    END
  END b[251]
  PIN b[252]
    DIRECTION OUTPUT ;
    USE SIGNAL ;
    PORT
      LAYER M5 ;
        RECT  80.784 105.732 80.808 105.816 ;
    END
  END b[252]
  PIN b[253]
    DIRECTION OUTPUT ;
    USE SIGNAL ;
    PORT
      LAYER M5 ;
        RECT  80.88 105.732 80.904 105.816 ;
    END
  END b[253]
  PIN b[254]
    DIRECTION OUTPUT ;
    USE SIGNAL ;
    PORT
      LAYER M5 ;
        RECT  80.976 105.732 81 105.816 ;
    END
  END b[254]
  PIN b[255]
    DIRECTION OUTPUT ;
    USE SIGNAL ;
    PORT
      LAYER M5 ;
        RECT  81.072 105.732 81.096 105.816 ;
    END
  END b[255]
  PIN b[256]
    DIRECTION OUTPUT ;
    USE SIGNAL ;
    PORT
      LAYER M5 ;
        RECT  75.024 105.732 75.048 105.816 ;
    END
  END b[256]
  PIN b[257]
    DIRECTION OUTPUT ;
    USE SIGNAL ;
    PORT
      LAYER M5 ;
        RECT  75.12 105.732 75.144 105.816 ;
    END
  END b[257]
  PIN b[258]
    DIRECTION OUTPUT ;
    USE SIGNAL ;
    PORT
      LAYER M5 ;
        RECT  75.216 105.732 75.24 105.816 ;
    END
  END b[258]
  PIN b[259]
    DIRECTION OUTPUT ;
    USE SIGNAL ;
    PORT
      LAYER M5 ;
        RECT  75.312 105.732 75.336 105.816 ;
    END
  END b[259]
  PIN b[25]
    DIRECTION OUTPUT ;
    USE SIGNAL ;
    PORT
      LAYER M3 ;
        RECT  50.652 105.779 50.67 105.816 ;
    END
  END b[25]
  PIN b[260]
    DIRECTION OUTPUT ;
    USE SIGNAL ;
    PORT
      LAYER M5 ;
        RECT  75.408 105.732 75.432 105.816 ;
    END
  END b[260]
  PIN b[261]
    DIRECTION OUTPUT ;
    USE SIGNAL ;
    PORT
      LAYER M5 ;
        RECT  75.504 105.732 75.528 105.816 ;
    END
  END b[261]
  PIN b[262]
    DIRECTION OUTPUT ;
    USE SIGNAL ;
    PORT
      LAYER M5 ;
        RECT  75.6 105.732 75.624 105.816 ;
    END
  END b[262]
  PIN b[263]
    DIRECTION OUTPUT ;
    USE SIGNAL ;
    PORT
      LAYER M5 ;
        RECT  75.696 105.732 75.72 105.816 ;
    END
  END b[263]
  PIN b[264]
    DIRECTION OUTPUT ;
    USE SIGNAL ;
    PORT
      LAYER M5 ;
        RECT  75.792 105.732 75.816 105.816 ;
    END
  END b[264]
  PIN b[265]
    DIRECTION OUTPUT ;
    USE SIGNAL ;
    PORT
      LAYER M5 ;
        RECT  75.888 105.732 75.912 105.816 ;
    END
  END b[265]
  PIN b[266]
    DIRECTION OUTPUT ;
    USE SIGNAL ;
    PORT
      LAYER M5 ;
        RECT  75.984 105.732 76.008 105.816 ;
    END
  END b[266]
  PIN b[267]
    DIRECTION OUTPUT ;
    USE SIGNAL ;
    PORT
      LAYER M5 ;
        RECT  76.08 105.732 76.104 105.816 ;
    END
  END b[267]
  PIN b[268]
    DIRECTION OUTPUT ;
    USE SIGNAL ;
    PORT
      LAYER M5 ;
        RECT  76.176 105.732 76.2 105.816 ;
    END
  END b[268]
  PIN b[269]
    DIRECTION OUTPUT ;
    USE SIGNAL ;
    PORT
      LAYER M5 ;
        RECT  76.272 105.732 76.296 105.816 ;
    END
  END b[269]
  PIN b[26]
    DIRECTION OUTPUT ;
    USE SIGNAL ;
    PORT
      LAYER M3 ;
        RECT  50.724 105.779 50.742 105.816 ;
    END
  END b[26]
  PIN b[270]
    DIRECTION OUTPUT ;
    USE SIGNAL ;
    PORT
      LAYER M5 ;
        RECT  76.368 105.732 76.392 105.816 ;
    END
  END b[270]
  PIN b[271]
    DIRECTION OUTPUT ;
    USE SIGNAL ;
    PORT
      LAYER M5 ;
        RECT  76.464 105.732 76.488 105.816 ;
    END
  END b[271]
  PIN b[272]
    DIRECTION OUTPUT ;
    USE SIGNAL ;
    PORT
      LAYER M5 ;
        RECT  76.56 105.732 76.584 105.816 ;
    END
  END b[272]
  PIN b[273]
    DIRECTION OUTPUT ;
    USE SIGNAL ;
    PORT
      LAYER M5 ;
        RECT  76.656 105.732 76.68 105.816 ;
    END
  END b[273]
  PIN b[274]
    DIRECTION OUTPUT ;
    USE SIGNAL ;
    PORT
      LAYER M5 ;
        RECT  76.752 105.732 76.776 105.816 ;
    END
  END b[274]
  PIN b[275]
    DIRECTION OUTPUT ;
    USE SIGNAL ;
    PORT
      LAYER M5 ;
        RECT  76.848 105.732 76.872 105.816 ;
    END
  END b[275]
  PIN b[276]
    DIRECTION OUTPUT ;
    USE SIGNAL ;
    PORT
      LAYER M5 ;
        RECT  76.944 105.732 76.968 105.816 ;
    END
  END b[276]
  PIN b[277]
    DIRECTION OUTPUT ;
    USE SIGNAL ;
    PORT
      LAYER M5 ;
        RECT  77.04 105.732 77.064 105.816 ;
    END
  END b[277]
  PIN b[278]
    DIRECTION OUTPUT ;
    USE SIGNAL ;
    PORT
      LAYER M5 ;
        RECT  77.136 105.732 77.16 105.816 ;
    END
  END b[278]
  PIN b[279]
    DIRECTION OUTPUT ;
    USE SIGNAL ;
    PORT
      LAYER M5 ;
        RECT  77.232 105.732 77.256 105.816 ;
    END
  END b[279]
  PIN b[27]
    DIRECTION OUTPUT ;
    USE SIGNAL ;
    PORT
      LAYER M3 ;
        RECT  50.796 105.779 50.814 105.816 ;
    END
  END b[27]
  PIN b[280]
    DIRECTION OUTPUT ;
    USE SIGNAL ;
    PORT
      LAYER M5 ;
        RECT  77.328 105.732 77.352 105.816 ;
    END
  END b[280]
  PIN b[281]
    DIRECTION OUTPUT ;
    USE SIGNAL ;
    PORT
      LAYER M5 ;
        RECT  77.424 105.732 77.448 105.816 ;
    END
  END b[281]
  PIN b[282]
    DIRECTION OUTPUT ;
    USE SIGNAL ;
    PORT
      LAYER M5 ;
        RECT  77.52 105.732 77.544 105.816 ;
    END
  END b[282]
  PIN b[283]
    DIRECTION OUTPUT ;
    USE SIGNAL ;
    PORT
      LAYER M5 ;
        RECT  77.616 105.732 77.64 105.816 ;
    END
  END b[283]
  PIN b[284]
    DIRECTION OUTPUT ;
    USE SIGNAL ;
    PORT
      LAYER M5 ;
        RECT  77.712 105.732 77.736 105.816 ;
    END
  END b[284]
  PIN b[285]
    DIRECTION OUTPUT ;
    USE SIGNAL ;
    PORT
      LAYER M5 ;
        RECT  77.808 105.732 77.832 105.816 ;
    END
  END b[285]
  PIN b[286]
    DIRECTION OUTPUT ;
    USE SIGNAL ;
    PORT
      LAYER M5 ;
        RECT  77.904 105.732 77.928 105.816 ;
    END
  END b[286]
  PIN b[287]
    DIRECTION OUTPUT ;
    USE SIGNAL ;
    PORT
      LAYER M5 ;
        RECT  78 105.732 78.024 105.816 ;
    END
  END b[287]
  PIN b[288]
    DIRECTION OUTPUT ;
    USE SIGNAL ;
    PORT
      LAYER M3 ;
        RECT  65.556 105.779 65.574 105.816 ;
    END
  END b[288]
  PIN b[289]
    DIRECTION OUTPUT ;
    USE SIGNAL ;
    PORT
      LAYER M3 ;
        RECT  65.628 105.779 65.646 105.816 ;
    END
  END b[289]
  PIN b[28]
    DIRECTION OUTPUT ;
    USE SIGNAL ;
    PORT
      LAYER M3 ;
        RECT  50.868 105.779 50.886 105.816 ;
    END
  END b[28]
  PIN b[290]
    DIRECTION OUTPUT ;
    USE SIGNAL ;
    PORT
      LAYER M3 ;
        RECT  65.7 105.779 65.718 105.816 ;
    END
  END b[290]
  PIN b[291]
    DIRECTION OUTPUT ;
    USE SIGNAL ;
    PORT
      LAYER M3 ;
        RECT  65.772 105.779 65.79 105.816 ;
    END
  END b[291]
  PIN b[292]
    DIRECTION OUTPUT ;
    USE SIGNAL ;
    PORT
      LAYER M3 ;
        RECT  65.844 105.779 65.862 105.816 ;
    END
  END b[292]
  PIN b[293]
    DIRECTION OUTPUT ;
    USE SIGNAL ;
    PORT
      LAYER M3 ;
        RECT  65.916 105.779 65.934 105.816 ;
    END
  END b[293]
  PIN b[294]
    DIRECTION OUTPUT ;
    USE SIGNAL ;
    PORT
      LAYER M3 ;
        RECT  65.988 105.779 66.006 105.816 ;
    END
  END b[294]
  PIN b[295]
    DIRECTION OUTPUT ;
    USE SIGNAL ;
    PORT
      LAYER M3 ;
        RECT  66.06 105.779 66.078 105.816 ;
    END
  END b[295]
  PIN b[296]
    DIRECTION OUTPUT ;
    USE SIGNAL ;
    PORT
      LAYER M3 ;
        RECT  66.132 105.779 66.15 105.816 ;
    END
  END b[296]
  PIN b[297]
    DIRECTION OUTPUT ;
    USE SIGNAL ;
    PORT
      LAYER M3 ;
        RECT  66.204 105.779 66.222 105.816 ;
    END
  END b[297]
  PIN b[298]
    DIRECTION OUTPUT ;
    USE SIGNAL ;
    PORT
      LAYER M3 ;
        RECT  66.276 105.779 66.294 105.816 ;
    END
  END b[298]
  PIN b[299]
    DIRECTION OUTPUT ;
    USE SIGNAL ;
    PORT
      LAYER M3 ;
        RECT  66.348 105.779 66.366 105.816 ;
    END
  END b[299]
  PIN b[29]
    DIRECTION OUTPUT ;
    USE SIGNAL ;
    PORT
      LAYER M3 ;
        RECT  50.94 105.779 50.958 105.816 ;
    END
  END b[29]
  PIN b[2]
    DIRECTION OUTPUT ;
    USE SIGNAL ;
    PORT
      LAYER M3 ;
        RECT  48.996 105.779 49.014 105.816 ;
    END
  END b[2]
  PIN b[300]
    DIRECTION OUTPUT ;
    USE SIGNAL ;
    PORT
      LAYER M3 ;
        RECT  66.42 105.779 66.438 105.816 ;
    END
  END b[300]
  PIN b[301]
    DIRECTION OUTPUT ;
    USE SIGNAL ;
    PORT
      LAYER M3 ;
        RECT  66.492 105.779 66.51 105.816 ;
    END
  END b[301]
  PIN b[302]
    DIRECTION OUTPUT ;
    USE SIGNAL ;
    PORT
      LAYER M3 ;
        RECT  66.564 105.779 66.582 105.816 ;
    END
  END b[302]
  PIN b[303]
    DIRECTION OUTPUT ;
    USE SIGNAL ;
    PORT
      LAYER M3 ;
        RECT  66.636 105.779 66.654 105.816 ;
    END
  END b[303]
  PIN b[304]
    DIRECTION OUTPUT ;
    USE SIGNAL ;
    PORT
      LAYER M3 ;
        RECT  66.708 105.779 66.726 105.816 ;
    END
  END b[304]
  PIN b[305]
    DIRECTION OUTPUT ;
    USE SIGNAL ;
    PORT
      LAYER M3 ;
        RECT  66.78 105.779 66.798 105.816 ;
    END
  END b[305]
  PIN b[306]
    DIRECTION OUTPUT ;
    USE SIGNAL ;
    PORT
      LAYER M3 ;
        RECT  66.852 105.779 66.87 105.816 ;
    END
  END b[306]
  PIN b[307]
    DIRECTION OUTPUT ;
    USE SIGNAL ;
    PORT
      LAYER M3 ;
        RECT  66.924 105.779 66.942 105.816 ;
    END
  END b[307]
  PIN b[308]
    DIRECTION OUTPUT ;
    USE SIGNAL ;
    PORT
      LAYER M3 ;
        RECT  66.996 105.779 67.014 105.816 ;
    END
  END b[308]
  PIN b[309]
    DIRECTION OUTPUT ;
    USE SIGNAL ;
    PORT
      LAYER M3 ;
        RECT  67.068 105.779 67.086 105.816 ;
    END
  END b[309]
  PIN b[30]
    DIRECTION OUTPUT ;
    USE SIGNAL ;
    PORT
      LAYER M3 ;
        RECT  51.012 105.779 51.03 105.816 ;
    END
  END b[30]
  PIN b[310]
    DIRECTION OUTPUT ;
    USE SIGNAL ;
    PORT
      LAYER M3 ;
        RECT  67.14 105.779 67.158 105.816 ;
    END
  END b[310]
  PIN b[311]
    DIRECTION OUTPUT ;
    USE SIGNAL ;
    PORT
      LAYER M3 ;
        RECT  67.212 105.779 67.23 105.816 ;
    END
  END b[311]
  PIN b[312]
    DIRECTION OUTPUT ;
    USE SIGNAL ;
    PORT
      LAYER M3 ;
        RECT  67.284 105.779 67.302 105.816 ;
    END
  END b[312]
  PIN b[313]
    DIRECTION OUTPUT ;
    USE SIGNAL ;
    PORT
      LAYER M3 ;
        RECT  67.356 105.779 67.374 105.816 ;
    END
  END b[313]
  PIN b[314]
    DIRECTION OUTPUT ;
    USE SIGNAL ;
    PORT
      LAYER M3 ;
        RECT  67.428 105.779 67.446 105.816 ;
    END
  END b[314]
  PIN b[315]
    DIRECTION OUTPUT ;
    USE SIGNAL ;
    PORT
      LAYER M3 ;
        RECT  67.5 105.779 67.518 105.816 ;
    END
  END b[315]
  PIN b[316]
    DIRECTION OUTPUT ;
    USE SIGNAL ;
    PORT
      LAYER M3 ;
        RECT  67.572 105.779 67.59 105.816 ;
    END
  END b[316]
  PIN b[317]
    DIRECTION OUTPUT ;
    USE SIGNAL ;
    PORT
      LAYER M3 ;
        RECT  67.644 105.779 67.662 105.816 ;
    END
  END b[317]
  PIN b[318]
    DIRECTION OUTPUT ;
    USE SIGNAL ;
    PORT
      LAYER M3 ;
        RECT  67.716 105.779 67.734 105.816 ;
    END
  END b[318]
  PIN b[319]
    DIRECTION OUTPUT ;
    USE SIGNAL ;
    PORT
      LAYER M3 ;
        RECT  67.788 105.779 67.806 105.816 ;
    END
  END b[319]
  PIN b[31]
    DIRECTION OUTPUT ;
    USE SIGNAL ;
    PORT
      LAYER M3 ;
        RECT  51.084 105.779 51.102 105.816 ;
    END
  END b[31]
  PIN b[320]
    DIRECTION OUTPUT ;
    USE SIGNAL ;
    PORT
      LAYER M5 ;
        RECT  58.896 105.732 58.92 105.816 ;
    END
  END b[320]
  PIN b[321]
    DIRECTION OUTPUT ;
    USE SIGNAL ;
    PORT
      LAYER M5 ;
        RECT  58.992 105.732 59.016 105.816 ;
    END
  END b[321]
  PIN b[322]
    DIRECTION OUTPUT ;
    USE SIGNAL ;
    PORT
      LAYER M5 ;
        RECT  59.088 105.732 59.112 105.816 ;
    END
  END b[322]
  PIN b[323]
    DIRECTION OUTPUT ;
    USE SIGNAL ;
    PORT
      LAYER M5 ;
        RECT  59.184 105.732 59.208 105.816 ;
    END
  END b[323]
  PIN b[324]
    DIRECTION OUTPUT ;
    USE SIGNAL ;
    PORT
      LAYER M5 ;
        RECT  59.28 105.732 59.304 105.816 ;
    END
  END b[324]
  PIN b[325]
    DIRECTION OUTPUT ;
    USE SIGNAL ;
    PORT
      LAYER M5 ;
        RECT  59.376 105.732 59.4 105.816 ;
    END
  END b[325]
  PIN b[326]
    DIRECTION OUTPUT ;
    USE SIGNAL ;
    PORT
      LAYER M5 ;
        RECT  59.472 105.732 59.496 105.816 ;
    END
  END b[326]
  PIN b[327]
    DIRECTION OUTPUT ;
    USE SIGNAL ;
    PORT
      LAYER M5 ;
        RECT  59.568 105.732 59.592 105.816 ;
    END
  END b[327]
  PIN b[328]
    DIRECTION OUTPUT ;
    USE SIGNAL ;
    PORT
      LAYER M5 ;
        RECT  59.664 105.732 59.688 105.816 ;
    END
  END b[328]
  PIN b[329]
    DIRECTION OUTPUT ;
    USE SIGNAL ;
    PORT
      LAYER M5 ;
        RECT  59.76 105.732 59.784 105.816 ;
    END
  END b[329]
  PIN b[32]
    DIRECTION OUTPUT ;
    USE SIGNAL ;
    PORT
      LAYER M5 ;
        RECT  30.48 105.732 30.504 105.816 ;
    END
  END b[32]
  PIN b[330]
    DIRECTION OUTPUT ;
    USE SIGNAL ;
    PORT
      LAYER M5 ;
        RECT  59.856 105.732 59.88 105.816 ;
    END
  END b[330]
  PIN b[331]
    DIRECTION OUTPUT ;
    USE SIGNAL ;
    PORT
      LAYER M5 ;
        RECT  59.952 105.732 59.976 105.816 ;
    END
  END b[331]
  PIN b[332]
    DIRECTION OUTPUT ;
    USE SIGNAL ;
    PORT
      LAYER M5 ;
        RECT  60.048 105.732 60.072 105.816 ;
    END
  END b[332]
  PIN b[333]
    DIRECTION OUTPUT ;
    USE SIGNAL ;
    PORT
      LAYER M5 ;
        RECT  60.144 105.732 60.168 105.816 ;
    END
  END b[333]
  PIN b[334]
    DIRECTION OUTPUT ;
    USE SIGNAL ;
    PORT
      LAYER M5 ;
        RECT  60.24 105.732 60.264 105.816 ;
    END
  END b[334]
  PIN b[335]
    DIRECTION OUTPUT ;
    USE SIGNAL ;
    PORT
      LAYER M5 ;
        RECT  60.336 105.732 60.36 105.816 ;
    END
  END b[335]
  PIN b[336]
    DIRECTION OUTPUT ;
    USE SIGNAL ;
    PORT
      LAYER M5 ;
        RECT  60.432 105.732 60.456 105.816 ;
    END
  END b[336]
  PIN b[337]
    DIRECTION OUTPUT ;
    USE SIGNAL ;
    PORT
      LAYER M5 ;
        RECT  60.528 105.732 60.552 105.816 ;
    END
  END b[337]
  PIN b[338]
    DIRECTION OUTPUT ;
    USE SIGNAL ;
    PORT
      LAYER M5 ;
        RECT  60.624 105.732 60.648 105.816 ;
    END
  END b[338]
  PIN b[339]
    DIRECTION OUTPUT ;
    USE SIGNAL ;
    PORT
      LAYER M5 ;
        RECT  60.72 105.732 60.744 105.816 ;
    END
  END b[339]
  PIN b[33]
    DIRECTION OUTPUT ;
    USE SIGNAL ;
    PORT
      LAYER M5 ;
        RECT  30.576 105.732 30.6 105.816 ;
    END
  END b[33]
  PIN b[340]
    DIRECTION OUTPUT ;
    USE SIGNAL ;
    PORT
      LAYER M5 ;
        RECT  60.816 105.732 60.84 105.816 ;
    END
  END b[340]
  PIN b[341]
    DIRECTION OUTPUT ;
    USE SIGNAL ;
    PORT
      LAYER M5 ;
        RECT  60.912 105.732 60.936 105.816 ;
    END
  END b[341]
  PIN b[342]
    DIRECTION OUTPUT ;
    USE SIGNAL ;
    PORT
      LAYER M5 ;
        RECT  61.008 105.732 61.032 105.816 ;
    END
  END b[342]
  PIN b[343]
    DIRECTION OUTPUT ;
    USE SIGNAL ;
    PORT
      LAYER M5 ;
        RECT  61.104 105.732 61.128 105.816 ;
    END
  END b[343]
  PIN b[344]
    DIRECTION OUTPUT ;
    USE SIGNAL ;
    PORT
      LAYER M5 ;
        RECT  61.2 105.732 61.224 105.816 ;
    END
  END b[344]
  PIN b[345]
    DIRECTION OUTPUT ;
    USE SIGNAL ;
    PORT
      LAYER M5 ;
        RECT  61.296 105.732 61.32 105.816 ;
    END
  END b[345]
  PIN b[346]
    DIRECTION OUTPUT ;
    USE SIGNAL ;
    PORT
      LAYER M5 ;
        RECT  61.392 105.732 61.416 105.816 ;
    END
  END b[346]
  PIN b[347]
    DIRECTION OUTPUT ;
    USE SIGNAL ;
    PORT
      LAYER M5 ;
        RECT  61.488 105.732 61.512 105.816 ;
    END
  END b[347]
  PIN b[348]
    DIRECTION OUTPUT ;
    USE SIGNAL ;
    PORT
      LAYER M5 ;
        RECT  61.584 105.732 61.608 105.816 ;
    END
  END b[348]
  PIN b[349]
    DIRECTION OUTPUT ;
    USE SIGNAL ;
    PORT
      LAYER M5 ;
        RECT  61.68 105.732 61.704 105.816 ;
    END
  END b[349]
  PIN b[34]
    DIRECTION OUTPUT ;
    USE SIGNAL ;
    PORT
      LAYER M5 ;
        RECT  30.672 105.732 30.696 105.816 ;
    END
  END b[34]
  PIN b[350]
    DIRECTION OUTPUT ;
    USE SIGNAL ;
    PORT
      LAYER M5 ;
        RECT  61.776 105.732 61.8 105.816 ;
    END
  END b[350]
  PIN b[351]
    DIRECTION OUTPUT ;
    USE SIGNAL ;
    PORT
      LAYER M5 ;
        RECT  61.872 105.732 61.896 105.816 ;
    END
  END b[351]
  PIN b[352]
    DIRECTION OUTPUT ;
    USE SIGNAL ;
    PORT
      LAYER M3 ;
        RECT  63.252 105.779 63.27 105.816 ;
    END
  END b[352]
  PIN b[353]
    DIRECTION OUTPUT ;
    USE SIGNAL ;
    PORT
      LAYER M3 ;
        RECT  63.324 105.779 63.342 105.816 ;
    END
  END b[353]
  PIN b[354]
    DIRECTION OUTPUT ;
    USE SIGNAL ;
    PORT
      LAYER M3 ;
        RECT  63.396 105.779 63.414 105.816 ;
    END
  END b[354]
  PIN b[355]
    DIRECTION OUTPUT ;
    USE SIGNAL ;
    PORT
      LAYER M3 ;
        RECT  63.468 105.779 63.486 105.816 ;
    END
  END b[355]
  PIN b[356]
    DIRECTION OUTPUT ;
    USE SIGNAL ;
    PORT
      LAYER M3 ;
        RECT  63.54 105.779 63.558 105.816 ;
    END
  END b[356]
  PIN b[357]
    DIRECTION OUTPUT ;
    USE SIGNAL ;
    PORT
      LAYER M3 ;
        RECT  63.612 105.779 63.63 105.816 ;
    END
  END b[357]
  PIN b[358]
    DIRECTION OUTPUT ;
    USE SIGNAL ;
    PORT
      LAYER M3 ;
        RECT  63.684 105.779 63.702 105.816 ;
    END
  END b[358]
  PIN b[359]
    DIRECTION OUTPUT ;
    USE SIGNAL ;
    PORT
      LAYER M3 ;
        RECT  63.756 105.779 63.774 105.816 ;
    END
  END b[359]
  PIN b[35]
    DIRECTION OUTPUT ;
    USE SIGNAL ;
    PORT
      LAYER M5 ;
        RECT  30.768 105.732 30.792 105.816 ;
    END
  END b[35]
  PIN b[360]
    DIRECTION OUTPUT ;
    USE SIGNAL ;
    PORT
      LAYER M3 ;
        RECT  63.828 105.779 63.846 105.816 ;
    END
  END b[360]
  PIN b[361]
    DIRECTION OUTPUT ;
    USE SIGNAL ;
    PORT
      LAYER M3 ;
        RECT  63.9 105.779 63.918 105.816 ;
    END
  END b[361]
  PIN b[362]
    DIRECTION OUTPUT ;
    USE SIGNAL ;
    PORT
      LAYER M3 ;
        RECT  63.972 105.779 63.99 105.816 ;
    END
  END b[362]
  PIN b[363]
    DIRECTION OUTPUT ;
    USE SIGNAL ;
    PORT
      LAYER M3 ;
        RECT  64.044 105.779 64.062 105.816 ;
    END
  END b[363]
  PIN b[364]
    DIRECTION OUTPUT ;
    USE SIGNAL ;
    PORT
      LAYER M3 ;
        RECT  64.116 105.779 64.134 105.816 ;
    END
  END b[364]
  PIN b[365]
    DIRECTION OUTPUT ;
    USE SIGNAL ;
    PORT
      LAYER M3 ;
        RECT  64.188 105.779 64.206 105.816 ;
    END
  END b[365]
  PIN b[366]
    DIRECTION OUTPUT ;
    USE SIGNAL ;
    PORT
      LAYER M3 ;
        RECT  64.26 105.779 64.278 105.816 ;
    END
  END b[366]
  PIN b[367]
    DIRECTION OUTPUT ;
    USE SIGNAL ;
    PORT
      LAYER M3 ;
        RECT  64.332 105.779 64.35 105.816 ;
    END
  END b[367]
  PIN b[368]
    DIRECTION OUTPUT ;
    USE SIGNAL ;
    PORT
      LAYER M3 ;
        RECT  64.404 105.779 64.422 105.816 ;
    END
  END b[368]
  PIN b[369]
    DIRECTION OUTPUT ;
    USE SIGNAL ;
    PORT
      LAYER M3 ;
        RECT  64.476 105.779 64.494 105.816 ;
    END
  END b[369]
  PIN b[36]
    DIRECTION OUTPUT ;
    USE SIGNAL ;
    PORT
      LAYER M5 ;
        RECT  30.864 105.732 30.888 105.816 ;
    END
  END b[36]
  PIN b[370]
    DIRECTION OUTPUT ;
    USE SIGNAL ;
    PORT
      LAYER M3 ;
        RECT  64.548 105.779 64.566 105.816 ;
    END
  END b[370]
  PIN b[371]
    DIRECTION OUTPUT ;
    USE SIGNAL ;
    PORT
      LAYER M3 ;
        RECT  64.62 105.779 64.638 105.816 ;
    END
  END b[371]
  PIN b[372]
    DIRECTION OUTPUT ;
    USE SIGNAL ;
    PORT
      LAYER M3 ;
        RECT  64.692 105.779 64.71 105.816 ;
    END
  END b[372]
  PIN b[373]
    DIRECTION OUTPUT ;
    USE SIGNAL ;
    PORT
      LAYER M3 ;
        RECT  64.764 105.779 64.782 105.816 ;
    END
  END b[373]
  PIN b[374]
    DIRECTION OUTPUT ;
    USE SIGNAL ;
    PORT
      LAYER M3 ;
        RECT  64.836 105.779 64.854 105.816 ;
    END
  END b[374]
  PIN b[375]
    DIRECTION OUTPUT ;
    USE SIGNAL ;
    PORT
      LAYER M3 ;
        RECT  64.908 105.779 64.926 105.816 ;
    END
  END b[375]
  PIN b[376]
    DIRECTION OUTPUT ;
    USE SIGNAL ;
    PORT
      LAYER M3 ;
        RECT  64.98 105.779 64.998 105.816 ;
    END
  END b[376]
  PIN b[377]
    DIRECTION OUTPUT ;
    USE SIGNAL ;
    PORT
      LAYER M3 ;
        RECT  65.052 105.779 65.07 105.816 ;
    END
  END b[377]
  PIN b[378]
    DIRECTION OUTPUT ;
    USE SIGNAL ;
    PORT
      LAYER M3 ;
        RECT  65.124 105.779 65.142 105.816 ;
    END
  END b[378]
  PIN b[379]
    DIRECTION OUTPUT ;
    USE SIGNAL ;
    PORT
      LAYER M3 ;
        RECT  65.196 105.779 65.214 105.816 ;
    END
  END b[379]
  PIN b[37]
    DIRECTION OUTPUT ;
    USE SIGNAL ;
    PORT
      LAYER M5 ;
        RECT  30.96 105.732 30.984 105.816 ;
    END
  END b[37]
  PIN b[380]
    DIRECTION OUTPUT ;
    USE SIGNAL ;
    PORT
      LAYER M3 ;
        RECT  65.268 105.779 65.286 105.816 ;
    END
  END b[380]
  PIN b[381]
    DIRECTION OUTPUT ;
    USE SIGNAL ;
    PORT
      LAYER M3 ;
        RECT  65.34 105.779 65.358 105.816 ;
    END
  END b[381]
  PIN b[382]
    DIRECTION OUTPUT ;
    USE SIGNAL ;
    PORT
      LAYER M3 ;
        RECT  65.412 105.779 65.43 105.816 ;
    END
  END b[382]
  PIN b[383]
    DIRECTION OUTPUT ;
    USE SIGNAL ;
    PORT
      LAYER M3 ;
        RECT  65.484 105.779 65.502 105.816 ;
    END
  END b[383]
  PIN b[384]
    DIRECTION OUTPUT ;
    USE SIGNAL ;
    PORT
      LAYER M5 ;
        RECT  49.68 105.732 49.704 105.816 ;
    END
  END b[384]
  PIN b[385]
    DIRECTION OUTPUT ;
    USE SIGNAL ;
    PORT
      LAYER M5 ;
        RECT  49.776 105.732 49.8 105.816 ;
    END
  END b[385]
  PIN b[386]
    DIRECTION OUTPUT ;
    USE SIGNAL ;
    PORT
      LAYER M5 ;
        RECT  49.872 105.732 49.896 105.816 ;
    END
  END b[386]
  PIN b[387]
    DIRECTION OUTPUT ;
    USE SIGNAL ;
    PORT
      LAYER M5 ;
        RECT  49.968 105.732 49.992 105.816 ;
    END
  END b[387]
  PIN b[388]
    DIRECTION OUTPUT ;
    USE SIGNAL ;
    PORT
      LAYER M5 ;
        RECT  50.064 105.732 50.088 105.816 ;
    END
  END b[388]
  PIN b[389]
    DIRECTION OUTPUT ;
    USE SIGNAL ;
    PORT
      LAYER M5 ;
        RECT  50.16 105.732 50.184 105.816 ;
    END
  END b[389]
  PIN b[38]
    DIRECTION OUTPUT ;
    USE SIGNAL ;
    PORT
      LAYER M5 ;
        RECT  31.056 105.732 31.08 105.816 ;
    END
  END b[38]
  PIN b[390]
    DIRECTION OUTPUT ;
    USE SIGNAL ;
    PORT
      LAYER M5 ;
        RECT  50.256 105.732 50.28 105.816 ;
    END
  END b[390]
  PIN b[391]
    DIRECTION OUTPUT ;
    USE SIGNAL ;
    PORT
      LAYER M5 ;
        RECT  50.352 105.732 50.376 105.816 ;
    END
  END b[391]
  PIN b[392]
    DIRECTION OUTPUT ;
    USE SIGNAL ;
    PORT
      LAYER M5 ;
        RECT  50.448 105.732 50.472 105.816 ;
    END
  END b[392]
  PIN b[393]
    DIRECTION OUTPUT ;
    USE SIGNAL ;
    PORT
      LAYER M5 ;
        RECT  50.544 105.732 50.568 105.816 ;
    END
  END b[393]
  PIN b[394]
    DIRECTION OUTPUT ;
    USE SIGNAL ;
    PORT
      LAYER M5 ;
        RECT  50.64 105.732 50.664 105.816 ;
    END
  END b[394]
  PIN b[395]
    DIRECTION OUTPUT ;
    USE SIGNAL ;
    PORT
      LAYER M5 ;
        RECT  50.736 105.732 50.76 105.816 ;
    END
  END b[395]
  PIN b[396]
    DIRECTION OUTPUT ;
    USE SIGNAL ;
    PORT
      LAYER M5 ;
        RECT  50.832 105.732 50.856 105.816 ;
    END
  END b[396]
  PIN b[397]
    DIRECTION OUTPUT ;
    USE SIGNAL ;
    PORT
      LAYER M5 ;
        RECT  50.928 105.732 50.952 105.816 ;
    END
  END b[397]
  PIN b[398]
    DIRECTION OUTPUT ;
    USE SIGNAL ;
    PORT
      LAYER M5 ;
        RECT  51.024 105.732 51.048 105.816 ;
    END
  END b[398]
  PIN b[399]
    DIRECTION OUTPUT ;
    USE SIGNAL ;
    PORT
      LAYER M5 ;
        RECT  51.12 105.732 51.144 105.816 ;
    END
  END b[399]
  PIN b[39]
    DIRECTION OUTPUT ;
    USE SIGNAL ;
    PORT
      LAYER M5 ;
        RECT  31.152 105.732 31.176 105.816 ;
    END
  END b[39]
  PIN b[3]
    DIRECTION OUTPUT ;
    USE SIGNAL ;
    PORT
      LAYER M3 ;
        RECT  49.068 105.779 49.086 105.816 ;
    END
  END b[3]
  PIN b[400]
    DIRECTION OUTPUT ;
    USE SIGNAL ;
    PORT
      LAYER M5 ;
        RECT  51.216 105.732 51.24 105.816 ;
    END
  END b[400]
  PIN b[401]
    DIRECTION OUTPUT ;
    USE SIGNAL ;
    PORT
      LAYER M5 ;
        RECT  51.312 105.732 51.336 105.816 ;
    END
  END b[401]
  PIN b[402]
    DIRECTION OUTPUT ;
    USE SIGNAL ;
    PORT
      LAYER M5 ;
        RECT  51.408 105.732 51.432 105.816 ;
    END
  END b[402]
  PIN b[403]
    DIRECTION OUTPUT ;
    USE SIGNAL ;
    PORT
      LAYER M5 ;
        RECT  51.504 105.732 51.528 105.816 ;
    END
  END b[403]
  PIN b[404]
    DIRECTION OUTPUT ;
    USE SIGNAL ;
    PORT
      LAYER M5 ;
        RECT  51.6 105.732 51.624 105.816 ;
    END
  END b[404]
  PIN b[405]
    DIRECTION OUTPUT ;
    USE SIGNAL ;
    PORT
      LAYER M5 ;
        RECT  51.696 105.732 51.72 105.816 ;
    END
  END b[405]
  PIN b[406]
    DIRECTION OUTPUT ;
    USE SIGNAL ;
    PORT
      LAYER M5 ;
        RECT  51.792 105.732 51.816 105.816 ;
    END
  END b[406]
  PIN b[407]
    DIRECTION OUTPUT ;
    USE SIGNAL ;
    PORT
      LAYER M5 ;
        RECT  51.888 105.732 51.912 105.816 ;
    END
  END b[407]
  PIN b[408]
    DIRECTION OUTPUT ;
    USE SIGNAL ;
    PORT
      LAYER M5 ;
        RECT  51.984 105.732 52.008 105.816 ;
    END
  END b[408]
  PIN b[409]
    DIRECTION OUTPUT ;
    USE SIGNAL ;
    PORT
      LAYER M5 ;
        RECT  52.08 105.732 52.104 105.816 ;
    END
  END b[409]
  PIN b[40]
    DIRECTION OUTPUT ;
    USE SIGNAL ;
    PORT
      LAYER M5 ;
        RECT  31.248 105.732 31.272 105.816 ;
    END
  END b[40]
  PIN b[410]
    DIRECTION OUTPUT ;
    USE SIGNAL ;
    PORT
      LAYER M5 ;
        RECT  52.176 105.732 52.2 105.816 ;
    END
  END b[410]
  PIN b[411]
    DIRECTION OUTPUT ;
    USE SIGNAL ;
    PORT
      LAYER M5 ;
        RECT  52.272 105.732 52.296 105.816 ;
    END
  END b[411]
  PIN b[412]
    DIRECTION OUTPUT ;
    USE SIGNAL ;
    PORT
      LAYER M5 ;
        RECT  52.368 105.732 52.392 105.816 ;
    END
  END b[412]
  PIN b[413]
    DIRECTION OUTPUT ;
    USE SIGNAL ;
    PORT
      LAYER M5 ;
        RECT  52.464 105.732 52.488 105.816 ;
    END
  END b[413]
  PIN b[414]
    DIRECTION OUTPUT ;
    USE SIGNAL ;
    PORT
      LAYER M5 ;
        RECT  52.56 105.732 52.584 105.816 ;
    END
  END b[414]
  PIN b[415]
    DIRECTION OUTPUT ;
    USE SIGNAL ;
    PORT
      LAYER M5 ;
        RECT  52.656 105.732 52.68 105.816 ;
    END
  END b[415]
  PIN b[416]
    DIRECTION OUTPUT ;
    USE SIGNAL ;
    PORT
      LAYER M3 ;
        RECT  41.364 105.779 41.382 105.816 ;
    END
  END b[416]
  PIN b[417]
    DIRECTION OUTPUT ;
    USE SIGNAL ;
    PORT
      LAYER M3 ;
        RECT  41.436 105.779 41.454 105.816 ;
    END
  END b[417]
  PIN b[418]
    DIRECTION OUTPUT ;
    USE SIGNAL ;
    PORT
      LAYER M3 ;
        RECT  41.508 105.779 41.526 105.816 ;
    END
  END b[418]
  PIN b[419]
    DIRECTION OUTPUT ;
    USE SIGNAL ;
    PORT
      LAYER M3 ;
        RECT  41.58 105.779 41.598 105.816 ;
    END
  END b[419]
  PIN b[41]
    DIRECTION OUTPUT ;
    USE SIGNAL ;
    PORT
      LAYER M5 ;
        RECT  31.344 105.732 31.368 105.816 ;
    END
  END b[41]
  PIN b[420]
    DIRECTION OUTPUT ;
    USE SIGNAL ;
    PORT
      LAYER M3 ;
        RECT  41.652 105.779 41.67 105.816 ;
    END
  END b[420]
  PIN b[421]
    DIRECTION OUTPUT ;
    USE SIGNAL ;
    PORT
      LAYER M3 ;
        RECT  41.724 105.779 41.742 105.816 ;
    END
  END b[421]
  PIN b[422]
    DIRECTION OUTPUT ;
    USE SIGNAL ;
    PORT
      LAYER M3 ;
        RECT  41.796 105.779 41.814 105.816 ;
    END
  END b[422]
  PIN b[423]
    DIRECTION OUTPUT ;
    USE SIGNAL ;
    PORT
      LAYER M3 ;
        RECT  41.868 105.779 41.886 105.816 ;
    END
  END b[423]
  PIN b[424]
    DIRECTION OUTPUT ;
    USE SIGNAL ;
    PORT
      LAYER M3 ;
        RECT  41.94 105.779 41.958 105.816 ;
    END
  END b[424]
  PIN b[425]
    DIRECTION OUTPUT ;
    USE SIGNAL ;
    PORT
      LAYER M3 ;
        RECT  42.012 105.779 42.03 105.816 ;
    END
  END b[425]
  PIN b[426]
    DIRECTION OUTPUT ;
    USE SIGNAL ;
    PORT
      LAYER M3 ;
        RECT  42.084 105.779 42.102 105.816 ;
    END
  END b[426]
  PIN b[427]
    DIRECTION OUTPUT ;
    USE SIGNAL ;
    PORT
      LAYER M3 ;
        RECT  42.156 105.779 42.174 105.816 ;
    END
  END b[427]
  PIN b[428]
    DIRECTION OUTPUT ;
    USE SIGNAL ;
    PORT
      LAYER M3 ;
        RECT  42.228 105.779 42.246 105.816 ;
    END
  END b[428]
  PIN b[429]
    DIRECTION OUTPUT ;
    USE SIGNAL ;
    PORT
      LAYER M3 ;
        RECT  42.3 105.779 42.318 105.816 ;
    END
  END b[429]
  PIN b[42]
    DIRECTION OUTPUT ;
    USE SIGNAL ;
    PORT
      LAYER M5 ;
        RECT  31.44 105.732 31.464 105.816 ;
    END
  END b[42]
  PIN b[430]
    DIRECTION OUTPUT ;
    USE SIGNAL ;
    PORT
      LAYER M3 ;
        RECT  42.372 105.779 42.39 105.816 ;
    END
  END b[430]
  PIN b[431]
    DIRECTION OUTPUT ;
    USE SIGNAL ;
    PORT
      LAYER M3 ;
        RECT  42.444 105.779 42.462 105.816 ;
    END
  END b[431]
  PIN b[432]
    DIRECTION OUTPUT ;
    USE SIGNAL ;
    PORT
      LAYER M3 ;
        RECT  42.516 105.779 42.534 105.816 ;
    END
  END b[432]
  PIN b[433]
    DIRECTION OUTPUT ;
    USE SIGNAL ;
    PORT
      LAYER M3 ;
        RECT  42.588 105.779 42.606 105.816 ;
    END
  END b[433]
  PIN b[434]
    DIRECTION OUTPUT ;
    USE SIGNAL ;
    PORT
      LAYER M3 ;
        RECT  42.66 105.779 42.678 105.816 ;
    END
  END b[434]
  PIN b[435]
    DIRECTION OUTPUT ;
    USE SIGNAL ;
    PORT
      LAYER M3 ;
        RECT  42.732 105.779 42.75 105.816 ;
    END
  END b[435]
  PIN b[436]
    DIRECTION OUTPUT ;
    USE SIGNAL ;
    PORT
      LAYER M3 ;
        RECT  42.804 105.779 42.822 105.816 ;
    END
  END b[436]
  PIN b[437]
    DIRECTION OUTPUT ;
    USE SIGNAL ;
    PORT
      LAYER M3 ;
        RECT  42.876 105.779 42.894 105.816 ;
    END
  END b[437]
  PIN b[438]
    DIRECTION OUTPUT ;
    USE SIGNAL ;
    PORT
      LAYER M3 ;
        RECT  42.948 105.779 42.966 105.816 ;
    END
  END b[438]
  PIN b[439]
    DIRECTION OUTPUT ;
    USE SIGNAL ;
    PORT
      LAYER M3 ;
        RECT  43.02 105.779 43.038 105.816 ;
    END
  END b[439]
  PIN b[43]
    DIRECTION OUTPUT ;
    USE SIGNAL ;
    PORT
      LAYER M5 ;
        RECT  31.536 105.732 31.56 105.816 ;
    END
  END b[43]
  PIN b[440]
    DIRECTION OUTPUT ;
    USE SIGNAL ;
    PORT
      LAYER M3 ;
        RECT  43.092 105.779 43.11 105.816 ;
    END
  END b[440]
  PIN b[441]
    DIRECTION OUTPUT ;
    USE SIGNAL ;
    PORT
      LAYER M3 ;
        RECT  43.164 105.779 43.182 105.816 ;
    END
  END b[441]
  PIN b[442]
    DIRECTION OUTPUT ;
    USE SIGNAL ;
    PORT
      LAYER M3 ;
        RECT  43.236 105.779 43.254 105.816 ;
    END
  END b[442]
  PIN b[443]
    DIRECTION OUTPUT ;
    USE SIGNAL ;
    PORT
      LAYER M3 ;
        RECT  43.308 105.779 43.326 105.816 ;
    END
  END b[443]
  PIN b[444]
    DIRECTION OUTPUT ;
    USE SIGNAL ;
    PORT
      LAYER M3 ;
        RECT  43.38 105.779 43.398 105.816 ;
    END
  END b[444]
  PIN b[445]
    DIRECTION OUTPUT ;
    USE SIGNAL ;
    PORT
      LAYER M3 ;
        RECT  43.452 105.779 43.47 105.816 ;
    END
  END b[445]
  PIN b[446]
    DIRECTION OUTPUT ;
    USE SIGNAL ;
    PORT
      LAYER M3 ;
        RECT  43.524 105.779 43.542 105.816 ;
    END
  END b[446]
  PIN b[447]
    DIRECTION OUTPUT ;
    USE SIGNAL ;
    PORT
      LAYER M3 ;
        RECT  43.596 105.779 43.614 105.816 ;
    END
  END b[447]
  PIN b[448]
    DIRECTION OUTPUT ;
    USE SIGNAL ;
    PORT
      LAYER M5 ;
        RECT  33.552 105.732 33.576 105.816 ;
    END
  END b[448]
  PIN b[449]
    DIRECTION OUTPUT ;
    USE SIGNAL ;
    PORT
      LAYER M5 ;
        RECT  33.648 105.732 33.672 105.816 ;
    END
  END b[449]
  PIN b[44]
    DIRECTION OUTPUT ;
    USE SIGNAL ;
    PORT
      LAYER M5 ;
        RECT  31.632 105.732 31.656 105.816 ;
    END
  END b[44]
  PIN b[450]
    DIRECTION OUTPUT ;
    USE SIGNAL ;
    PORT
      LAYER M5 ;
        RECT  33.744 105.732 33.768 105.816 ;
    END
  END b[450]
  PIN b[451]
    DIRECTION OUTPUT ;
    USE SIGNAL ;
    PORT
      LAYER M5 ;
        RECT  33.84 105.732 33.864 105.816 ;
    END
  END b[451]
  PIN b[452]
    DIRECTION OUTPUT ;
    USE SIGNAL ;
    PORT
      LAYER M5 ;
        RECT  33.936 105.732 33.96 105.816 ;
    END
  END b[452]
  PIN b[453]
    DIRECTION OUTPUT ;
    USE SIGNAL ;
    PORT
      LAYER M5 ;
        RECT  34.032 105.732 34.056 105.816 ;
    END
  END b[453]
  PIN b[454]
    DIRECTION OUTPUT ;
    USE SIGNAL ;
    PORT
      LAYER M5 ;
        RECT  34.128 105.732 34.152 105.816 ;
    END
  END b[454]
  PIN b[455]
    DIRECTION OUTPUT ;
    USE SIGNAL ;
    PORT
      LAYER M5 ;
        RECT  34.224 105.732 34.248 105.816 ;
    END
  END b[455]
  PIN b[456]
    DIRECTION OUTPUT ;
    USE SIGNAL ;
    PORT
      LAYER M5 ;
        RECT  34.32 105.732 34.344 105.816 ;
    END
  END b[456]
  PIN b[457]
    DIRECTION OUTPUT ;
    USE SIGNAL ;
    PORT
      LAYER M5 ;
        RECT  34.416 105.732 34.44 105.816 ;
    END
  END b[457]
  PIN b[458]
    DIRECTION OUTPUT ;
    USE SIGNAL ;
    PORT
      LAYER M5 ;
        RECT  34.512 105.732 34.536 105.816 ;
    END
  END b[458]
  PIN b[459]
    DIRECTION OUTPUT ;
    USE SIGNAL ;
    PORT
      LAYER M5 ;
        RECT  34.608 105.732 34.632 105.816 ;
    END
  END b[459]
  PIN b[45]
    DIRECTION OUTPUT ;
    USE SIGNAL ;
    PORT
      LAYER M5 ;
        RECT  31.728 105.732 31.752 105.816 ;
    END
  END b[45]
  PIN b[460]
    DIRECTION OUTPUT ;
    USE SIGNAL ;
    PORT
      LAYER M5 ;
        RECT  34.704 105.732 34.728 105.816 ;
    END
  END b[460]
  PIN b[461]
    DIRECTION OUTPUT ;
    USE SIGNAL ;
    PORT
      LAYER M5 ;
        RECT  34.8 105.732 34.824 105.816 ;
    END
  END b[461]
  PIN b[462]
    DIRECTION OUTPUT ;
    USE SIGNAL ;
    PORT
      LAYER M5 ;
        RECT  34.896 105.732 34.92 105.816 ;
    END
  END b[462]
  PIN b[463]
    DIRECTION OUTPUT ;
    USE SIGNAL ;
    PORT
      LAYER M5 ;
        RECT  34.992 105.732 35.016 105.816 ;
    END
  END b[463]
  PIN b[464]
    DIRECTION OUTPUT ;
    USE SIGNAL ;
    PORT
      LAYER M5 ;
        RECT  35.088 105.732 35.112 105.816 ;
    END
  END b[464]
  PIN b[465]
    DIRECTION OUTPUT ;
    USE SIGNAL ;
    PORT
      LAYER M5 ;
        RECT  35.184 105.732 35.208 105.816 ;
    END
  END b[465]
  PIN b[466]
    DIRECTION OUTPUT ;
    USE SIGNAL ;
    PORT
      LAYER M5 ;
        RECT  35.28 105.732 35.304 105.816 ;
    END
  END b[466]
  PIN b[467]
    DIRECTION OUTPUT ;
    USE SIGNAL ;
    PORT
      LAYER M5 ;
        RECT  35.376 105.732 35.4 105.816 ;
    END
  END b[467]
  PIN b[468]
    DIRECTION OUTPUT ;
    USE SIGNAL ;
    PORT
      LAYER M5 ;
        RECT  35.472 105.732 35.496 105.816 ;
    END
  END b[468]
  PIN b[469]
    DIRECTION OUTPUT ;
    USE SIGNAL ;
    PORT
      LAYER M5 ;
        RECT  35.568 105.732 35.592 105.816 ;
    END
  END b[469]
  PIN b[46]
    DIRECTION OUTPUT ;
    USE SIGNAL ;
    PORT
      LAYER M5 ;
        RECT  31.824 105.732 31.848 105.816 ;
    END
  END b[46]
  PIN b[470]
    DIRECTION OUTPUT ;
    USE SIGNAL ;
    PORT
      LAYER M5 ;
        RECT  35.664 105.732 35.688 105.816 ;
    END
  END b[470]
  PIN b[471]
    DIRECTION OUTPUT ;
    USE SIGNAL ;
    PORT
      LAYER M5 ;
        RECT  35.76 105.732 35.784 105.816 ;
    END
  END b[471]
  PIN b[472]
    DIRECTION OUTPUT ;
    USE SIGNAL ;
    PORT
      LAYER M5 ;
        RECT  35.856 105.732 35.88 105.816 ;
    END
  END b[472]
  PIN b[473]
    DIRECTION OUTPUT ;
    USE SIGNAL ;
    PORT
      LAYER M5 ;
        RECT  35.952 105.732 35.976 105.816 ;
    END
  END b[473]
  PIN b[474]
    DIRECTION OUTPUT ;
    USE SIGNAL ;
    PORT
      LAYER M5 ;
        RECT  36.048 105.732 36.072 105.816 ;
    END
  END b[474]
  PIN b[475]
    DIRECTION OUTPUT ;
    USE SIGNAL ;
    PORT
      LAYER M5 ;
        RECT  36.144 105.732 36.168 105.816 ;
    END
  END b[475]
  PIN b[476]
    DIRECTION OUTPUT ;
    USE SIGNAL ;
    PORT
      LAYER M5 ;
        RECT  36.24 105.732 36.264 105.816 ;
    END
  END b[476]
  PIN b[477]
    DIRECTION OUTPUT ;
    USE SIGNAL ;
    PORT
      LAYER M5 ;
        RECT  36.336 105.732 36.36 105.816 ;
    END
  END b[477]
  PIN b[478]
    DIRECTION OUTPUT ;
    USE SIGNAL ;
    PORT
      LAYER M5 ;
        RECT  36.432 105.732 36.456 105.816 ;
    END
  END b[478]
  PIN b[479]
    DIRECTION OUTPUT ;
    USE SIGNAL ;
    PORT
      LAYER M5 ;
        RECT  36.528 105.732 36.552 105.816 ;
    END
  END b[479]
  PIN b[47]
    DIRECTION OUTPUT ;
    USE SIGNAL ;
    PORT
      LAYER M5 ;
        RECT  31.92 105.732 31.944 105.816 ;
    END
  END b[47]
  PIN b[480]
    DIRECTION OUTPUT ;
    USE SIGNAL ;
    PORT
      LAYER M3 ;
        RECT  26.964 105.779 26.982 105.816 ;
    END
  END b[480]
  PIN b[481]
    DIRECTION OUTPUT ;
    USE SIGNAL ;
    PORT
      LAYER M3 ;
        RECT  27.036 105.779 27.054 105.816 ;
    END
  END b[481]
  PIN b[482]
    DIRECTION OUTPUT ;
    USE SIGNAL ;
    PORT
      LAYER M3 ;
        RECT  27.108 105.779 27.126 105.816 ;
    END
  END b[482]
  PIN b[483]
    DIRECTION OUTPUT ;
    USE SIGNAL ;
    PORT
      LAYER M3 ;
        RECT  27.18 105.779 27.198 105.816 ;
    END
  END b[483]
  PIN b[484]
    DIRECTION OUTPUT ;
    USE SIGNAL ;
    PORT
      LAYER M3 ;
        RECT  27.252 105.779 27.27 105.816 ;
    END
  END b[484]
  PIN b[485]
    DIRECTION OUTPUT ;
    USE SIGNAL ;
    PORT
      LAYER M3 ;
        RECT  27.324 105.779 27.342 105.816 ;
    END
  END b[485]
  PIN b[486]
    DIRECTION OUTPUT ;
    USE SIGNAL ;
    PORT
      LAYER M3 ;
        RECT  27.396 105.779 27.414 105.816 ;
    END
  END b[486]
  PIN b[487]
    DIRECTION OUTPUT ;
    USE SIGNAL ;
    PORT
      LAYER M3 ;
        RECT  27.468 105.779 27.486 105.816 ;
    END
  END b[487]
  PIN b[488]
    DIRECTION OUTPUT ;
    USE SIGNAL ;
    PORT
      LAYER M3 ;
        RECT  27.54 105.779 27.558 105.816 ;
    END
  END b[488]
  PIN b[489]
    DIRECTION OUTPUT ;
    USE SIGNAL ;
    PORT
      LAYER M3 ;
        RECT  27.612 105.779 27.63 105.816 ;
    END
  END b[489]
  PIN b[48]
    DIRECTION OUTPUT ;
    USE SIGNAL ;
    PORT
      LAYER M5 ;
        RECT  32.016 105.732 32.04 105.816 ;
    END
  END b[48]
  PIN b[490]
    DIRECTION OUTPUT ;
    USE SIGNAL ;
    PORT
      LAYER M3 ;
        RECT  27.684 105.779 27.702 105.816 ;
    END
  END b[490]
  PIN b[491]
    DIRECTION OUTPUT ;
    USE SIGNAL ;
    PORT
      LAYER M3 ;
        RECT  27.756 105.779 27.774 105.816 ;
    END
  END b[491]
  PIN b[492]
    DIRECTION OUTPUT ;
    USE SIGNAL ;
    PORT
      LAYER M3 ;
        RECT  27.828 105.779 27.846 105.816 ;
    END
  END b[492]
  PIN b[493]
    DIRECTION OUTPUT ;
    USE SIGNAL ;
    PORT
      LAYER M3 ;
        RECT  27.9 105.779 27.918 105.816 ;
    END
  END b[493]
  PIN b[494]
    DIRECTION OUTPUT ;
    USE SIGNAL ;
    PORT
      LAYER M3 ;
        RECT  27.972 105.779 27.99 105.816 ;
    END
  END b[494]
  PIN b[495]
    DIRECTION OUTPUT ;
    USE SIGNAL ;
    PORT
      LAYER M3 ;
        RECT  28.044 105.779 28.062 105.816 ;
    END
  END b[495]
  PIN b[496]
    DIRECTION OUTPUT ;
    USE SIGNAL ;
    PORT
      LAYER M3 ;
        RECT  28.116 105.779 28.134 105.816 ;
    END
  END b[496]
  PIN b[497]
    DIRECTION OUTPUT ;
    USE SIGNAL ;
    PORT
      LAYER M3 ;
        RECT  28.188 105.779 28.206 105.816 ;
    END
  END b[497]
  PIN b[498]
    DIRECTION OUTPUT ;
    USE SIGNAL ;
    PORT
      LAYER M3 ;
        RECT  28.26 105.779 28.278 105.816 ;
    END
  END b[498]
  PIN b[499]
    DIRECTION OUTPUT ;
    USE SIGNAL ;
    PORT
      LAYER M3 ;
        RECT  28.332 105.779 28.35 105.816 ;
    END
  END b[499]
  PIN b[49]
    DIRECTION OUTPUT ;
    USE SIGNAL ;
    PORT
      LAYER M5 ;
        RECT  32.112 105.732 32.136 105.816 ;
    END
  END b[49]
  PIN b[4]
    DIRECTION OUTPUT ;
    USE SIGNAL ;
    PORT
      LAYER M3 ;
        RECT  49.14 105.779 49.158 105.816 ;
    END
  END b[4]
  PIN b[500]
    DIRECTION OUTPUT ;
    USE SIGNAL ;
    PORT
      LAYER M3 ;
        RECT  28.404 105.779 28.422 105.816 ;
    END
  END b[500]
  PIN b[501]
    DIRECTION OUTPUT ;
    USE SIGNAL ;
    PORT
      LAYER M3 ;
        RECT  28.476 105.779 28.494 105.816 ;
    END
  END b[501]
  PIN b[502]
    DIRECTION OUTPUT ;
    USE SIGNAL ;
    PORT
      LAYER M3 ;
        RECT  28.548 105.779 28.566 105.816 ;
    END
  END b[502]
  PIN b[503]
    DIRECTION OUTPUT ;
    USE SIGNAL ;
    PORT
      LAYER M3 ;
        RECT  28.62 105.779 28.638 105.816 ;
    END
  END b[503]
  PIN b[504]
    DIRECTION OUTPUT ;
    USE SIGNAL ;
    PORT
      LAYER M3 ;
        RECT  28.692 105.779 28.71 105.816 ;
    END
  END b[504]
  PIN b[505]
    DIRECTION OUTPUT ;
    USE SIGNAL ;
    PORT
      LAYER M3 ;
        RECT  28.764 105.779 28.782 105.816 ;
    END
  END b[505]
  PIN b[506]
    DIRECTION OUTPUT ;
    USE SIGNAL ;
    PORT
      LAYER M3 ;
        RECT  28.836 105.779 28.854 105.816 ;
    END
  END b[506]
  PIN b[507]
    DIRECTION OUTPUT ;
    USE SIGNAL ;
    PORT
      LAYER M3 ;
        RECT  28.908 105.779 28.926 105.816 ;
    END
  END b[507]
  PIN b[508]
    DIRECTION OUTPUT ;
    USE SIGNAL ;
    PORT
      LAYER M3 ;
        RECT  28.98 105.779 28.998 105.816 ;
    END
  END b[508]
  PIN b[509]
    DIRECTION OUTPUT ;
    USE SIGNAL ;
    PORT
      LAYER M3 ;
        RECT  29.052 105.779 29.07 105.816 ;
    END
  END b[509]
  PIN b[50]
    DIRECTION OUTPUT ;
    USE SIGNAL ;
    PORT
      LAYER M5 ;
        RECT  32.208 105.732 32.232 105.816 ;
    END
  END b[50]
  PIN b[510]
    DIRECTION OUTPUT ;
    USE SIGNAL ;
    PORT
      LAYER M3 ;
        RECT  29.124 105.779 29.142 105.816 ;
    END
  END b[510]
  PIN b[511]
    DIRECTION OUTPUT ;
    USE SIGNAL ;
    PORT
      LAYER M3 ;
        RECT  29.196 105.779 29.214 105.816 ;
    END
  END b[511]
  PIN b[512]
    DIRECTION OUTPUT ;
    USE SIGNAL ;
    PORT
      LAYER M5 ;
        RECT  27.408 105.732 27.432 105.816 ;
    END
  END b[512]
  PIN b[513]
    DIRECTION OUTPUT ;
    USE SIGNAL ;
    PORT
      LAYER M5 ;
        RECT  27.504 105.732 27.528 105.816 ;
    END
  END b[513]
  PIN b[514]
    DIRECTION OUTPUT ;
    USE SIGNAL ;
    PORT
      LAYER M5 ;
        RECT  27.6 105.732 27.624 105.816 ;
    END
  END b[514]
  PIN b[515]
    DIRECTION OUTPUT ;
    USE SIGNAL ;
    PORT
      LAYER M5 ;
        RECT  27.696 105.732 27.72 105.816 ;
    END
  END b[515]
  PIN b[516]
    DIRECTION OUTPUT ;
    USE SIGNAL ;
    PORT
      LAYER M5 ;
        RECT  27.792 105.732 27.816 105.816 ;
    END
  END b[516]
  PIN b[517]
    DIRECTION OUTPUT ;
    USE SIGNAL ;
    PORT
      LAYER M5 ;
        RECT  27.888 105.732 27.912 105.816 ;
    END
  END b[517]
  PIN b[518]
    DIRECTION OUTPUT ;
    USE SIGNAL ;
    PORT
      LAYER M5 ;
        RECT  27.984 105.732 28.008 105.816 ;
    END
  END b[518]
  PIN b[519]
    DIRECTION OUTPUT ;
    USE SIGNAL ;
    PORT
      LAYER M5 ;
        RECT  28.08 105.732 28.104 105.816 ;
    END
  END b[519]
  PIN b[51]
    DIRECTION OUTPUT ;
    USE SIGNAL ;
    PORT
      LAYER M5 ;
        RECT  32.304 105.732 32.328 105.816 ;
    END
  END b[51]
  PIN b[520]
    DIRECTION OUTPUT ;
    USE SIGNAL ;
    PORT
      LAYER M5 ;
        RECT  28.176 105.732 28.2 105.816 ;
    END
  END b[520]
  PIN b[521]
    DIRECTION OUTPUT ;
    USE SIGNAL ;
    PORT
      LAYER M5 ;
        RECT  28.272 105.732 28.296 105.816 ;
    END
  END b[521]
  PIN b[522]
    DIRECTION OUTPUT ;
    USE SIGNAL ;
    PORT
      LAYER M5 ;
        RECT  28.368 105.732 28.392 105.816 ;
    END
  END b[522]
  PIN b[523]
    DIRECTION OUTPUT ;
    USE SIGNAL ;
    PORT
      LAYER M5 ;
        RECT  28.464 105.732 28.488 105.816 ;
    END
  END b[523]
  PIN b[524]
    DIRECTION OUTPUT ;
    USE SIGNAL ;
    PORT
      LAYER M5 ;
        RECT  28.56 105.732 28.584 105.816 ;
    END
  END b[524]
  PIN b[525]
    DIRECTION OUTPUT ;
    USE SIGNAL ;
    PORT
      LAYER M5 ;
        RECT  28.656 105.732 28.68 105.816 ;
    END
  END b[525]
  PIN b[526]
    DIRECTION OUTPUT ;
    USE SIGNAL ;
    PORT
      LAYER M5 ;
        RECT  28.752 105.732 28.776 105.816 ;
    END
  END b[526]
  PIN b[527]
    DIRECTION OUTPUT ;
    USE SIGNAL ;
    PORT
      LAYER M5 ;
        RECT  28.848 105.732 28.872 105.816 ;
    END
  END b[527]
  PIN b[528]
    DIRECTION OUTPUT ;
    USE SIGNAL ;
    PORT
      LAYER M5 ;
        RECT  28.944 105.732 28.968 105.816 ;
    END
  END b[528]
  PIN b[529]
    DIRECTION OUTPUT ;
    USE SIGNAL ;
    PORT
      LAYER M5 ;
        RECT  29.04 105.732 29.064 105.816 ;
    END
  END b[529]
  PIN b[52]
    DIRECTION OUTPUT ;
    USE SIGNAL ;
    PORT
      LAYER M5 ;
        RECT  32.4 105.732 32.424 105.816 ;
    END
  END b[52]
  PIN b[530]
    DIRECTION OUTPUT ;
    USE SIGNAL ;
    PORT
      LAYER M5 ;
        RECT  29.136 105.732 29.16 105.816 ;
    END
  END b[530]
  PIN b[531]
    DIRECTION OUTPUT ;
    USE SIGNAL ;
    PORT
      LAYER M5 ;
        RECT  29.232 105.732 29.256 105.816 ;
    END
  END b[531]
  PIN b[532]
    DIRECTION OUTPUT ;
    USE SIGNAL ;
    PORT
      LAYER M5 ;
        RECT  29.328 105.732 29.352 105.816 ;
    END
  END b[532]
  PIN b[533]
    DIRECTION OUTPUT ;
    USE SIGNAL ;
    PORT
      LAYER M5 ;
        RECT  29.424 105.732 29.448 105.816 ;
    END
  END b[533]
  PIN b[534]
    DIRECTION OUTPUT ;
    USE SIGNAL ;
    PORT
      LAYER M5 ;
        RECT  29.52 105.732 29.544 105.816 ;
    END
  END b[534]
  PIN b[535]
    DIRECTION OUTPUT ;
    USE SIGNAL ;
    PORT
      LAYER M5 ;
        RECT  29.616 105.732 29.64 105.816 ;
    END
  END b[535]
  PIN b[536]
    DIRECTION OUTPUT ;
    USE SIGNAL ;
    PORT
      LAYER M5 ;
        RECT  29.712 105.732 29.736 105.816 ;
    END
  END b[536]
  PIN b[537]
    DIRECTION OUTPUT ;
    USE SIGNAL ;
    PORT
      LAYER M5 ;
        RECT  29.808 105.732 29.832 105.816 ;
    END
  END b[537]
  PIN b[538]
    DIRECTION OUTPUT ;
    USE SIGNAL ;
    PORT
      LAYER M5 ;
        RECT  29.904 105.732 29.928 105.816 ;
    END
  END b[538]
  PIN b[539]
    DIRECTION OUTPUT ;
    USE SIGNAL ;
    PORT
      LAYER M5 ;
        RECT  30 105.732 30.024 105.816 ;
    END
  END b[539]
  PIN b[53]
    DIRECTION OUTPUT ;
    USE SIGNAL ;
    PORT
      LAYER M5 ;
        RECT  32.496 105.732 32.52 105.816 ;
    END
  END b[53]
  PIN b[540]
    DIRECTION OUTPUT ;
    USE SIGNAL ;
    PORT
      LAYER M5 ;
        RECT  30.096 105.732 30.12 105.816 ;
    END
  END b[540]
  PIN b[541]
    DIRECTION OUTPUT ;
    USE SIGNAL ;
    PORT
      LAYER M5 ;
        RECT  30.192 105.732 30.216 105.816 ;
    END
  END b[541]
  PIN b[542]
    DIRECTION OUTPUT ;
    USE SIGNAL ;
    PORT
      LAYER M5 ;
        RECT  30.288 105.732 30.312 105.816 ;
    END
  END b[542]
  PIN b[543]
    DIRECTION OUTPUT ;
    USE SIGNAL ;
    PORT
      LAYER M5 ;
        RECT  30.384 105.732 30.408 105.816 ;
    END
  END b[543]
  PIN b[544]
    DIRECTION OUTPUT ;
    USE SIGNAL ;
    PORT
      LAYER M3 ;
        RECT  36.756 105.779 36.774 105.816 ;
    END
  END b[544]
  PIN b[545]
    DIRECTION OUTPUT ;
    USE SIGNAL ;
    PORT
      LAYER M3 ;
        RECT  36.828 105.779 36.846 105.816 ;
    END
  END b[545]
  PIN b[546]
    DIRECTION OUTPUT ;
    USE SIGNAL ;
    PORT
      LAYER M3 ;
        RECT  36.9 105.779 36.918 105.816 ;
    END
  END b[546]
  PIN b[547]
    DIRECTION OUTPUT ;
    USE SIGNAL ;
    PORT
      LAYER M3 ;
        RECT  36.972 105.779 36.99 105.816 ;
    END
  END b[547]
  PIN b[548]
    DIRECTION OUTPUT ;
    USE SIGNAL ;
    PORT
      LAYER M3 ;
        RECT  37.044 105.779 37.062 105.816 ;
    END
  END b[548]
  PIN b[549]
    DIRECTION OUTPUT ;
    USE SIGNAL ;
    PORT
      LAYER M3 ;
        RECT  37.116 105.779 37.134 105.816 ;
    END
  END b[549]
  PIN b[54]
    DIRECTION OUTPUT ;
    USE SIGNAL ;
    PORT
      LAYER M5 ;
        RECT  32.592 105.732 32.616 105.816 ;
    END
  END b[54]
  PIN b[550]
    DIRECTION OUTPUT ;
    USE SIGNAL ;
    PORT
      LAYER M3 ;
        RECT  37.188 105.779 37.206 105.816 ;
    END
  END b[550]
  PIN b[551]
    DIRECTION OUTPUT ;
    USE SIGNAL ;
    PORT
      LAYER M3 ;
        RECT  37.26 105.779 37.278 105.816 ;
    END
  END b[551]
  PIN b[552]
    DIRECTION OUTPUT ;
    USE SIGNAL ;
    PORT
      LAYER M3 ;
        RECT  37.332 105.779 37.35 105.816 ;
    END
  END b[552]
  PIN b[553]
    DIRECTION OUTPUT ;
    USE SIGNAL ;
    PORT
      LAYER M3 ;
        RECT  37.404 105.779 37.422 105.816 ;
    END
  END b[553]
  PIN b[554]
    DIRECTION OUTPUT ;
    USE SIGNAL ;
    PORT
      LAYER M3 ;
        RECT  37.476 105.779 37.494 105.816 ;
    END
  END b[554]
  PIN b[555]
    DIRECTION OUTPUT ;
    USE SIGNAL ;
    PORT
      LAYER M3 ;
        RECT  37.548 105.779 37.566 105.816 ;
    END
  END b[555]
  PIN b[556]
    DIRECTION OUTPUT ;
    USE SIGNAL ;
    PORT
      LAYER M3 ;
        RECT  37.62 105.779 37.638 105.816 ;
    END
  END b[556]
  PIN b[557]
    DIRECTION OUTPUT ;
    USE SIGNAL ;
    PORT
      LAYER M3 ;
        RECT  37.692 105.779 37.71 105.816 ;
    END
  END b[557]
  PIN b[558]
    DIRECTION OUTPUT ;
    USE SIGNAL ;
    PORT
      LAYER M3 ;
        RECT  37.764 105.779 37.782 105.816 ;
    END
  END b[558]
  PIN b[559]
    DIRECTION OUTPUT ;
    USE SIGNAL ;
    PORT
      LAYER M3 ;
        RECT  37.836 105.779 37.854 105.816 ;
    END
  END b[559]
  PIN b[55]
    DIRECTION OUTPUT ;
    USE SIGNAL ;
    PORT
      LAYER M5 ;
        RECT  32.688 105.732 32.712 105.816 ;
    END
  END b[55]
  PIN b[560]
    DIRECTION OUTPUT ;
    USE SIGNAL ;
    PORT
      LAYER M3 ;
        RECT  37.908 105.779 37.926 105.816 ;
    END
  END b[560]
  PIN b[561]
    DIRECTION OUTPUT ;
    USE SIGNAL ;
    PORT
      LAYER M3 ;
        RECT  37.98 105.779 37.998 105.816 ;
    END
  END b[561]
  PIN b[562]
    DIRECTION OUTPUT ;
    USE SIGNAL ;
    PORT
      LAYER M3 ;
        RECT  38.052 105.779 38.07 105.816 ;
    END
  END b[562]
  PIN b[563]
    DIRECTION OUTPUT ;
    USE SIGNAL ;
    PORT
      LAYER M3 ;
        RECT  38.124 105.779 38.142 105.816 ;
    END
  END b[563]
  PIN b[564]
    DIRECTION OUTPUT ;
    USE SIGNAL ;
    PORT
      LAYER M3 ;
        RECT  38.196 105.779 38.214 105.816 ;
    END
  END b[564]
  PIN b[565]
    DIRECTION OUTPUT ;
    USE SIGNAL ;
    PORT
      LAYER M3 ;
        RECT  38.268 105.779 38.286 105.816 ;
    END
  END b[565]
  PIN b[566]
    DIRECTION OUTPUT ;
    USE SIGNAL ;
    PORT
      LAYER M3 ;
        RECT  38.34 105.779 38.358 105.816 ;
    END
  END b[566]
  PIN b[567]
    DIRECTION OUTPUT ;
    USE SIGNAL ;
    PORT
      LAYER M3 ;
        RECT  38.412 105.779 38.43 105.816 ;
    END
  END b[567]
  PIN b[568]
    DIRECTION OUTPUT ;
    USE SIGNAL ;
    PORT
      LAYER M3 ;
        RECT  38.484 105.779 38.502 105.816 ;
    END
  END b[568]
  PIN b[569]
    DIRECTION OUTPUT ;
    USE SIGNAL ;
    PORT
      LAYER M3 ;
        RECT  38.556 105.779 38.574 105.816 ;
    END
  END b[569]
  PIN b[56]
    DIRECTION OUTPUT ;
    USE SIGNAL ;
    PORT
      LAYER M5 ;
        RECT  32.784 105.732 32.808 105.816 ;
    END
  END b[56]
  PIN b[570]
    DIRECTION OUTPUT ;
    USE SIGNAL ;
    PORT
      LAYER M3 ;
        RECT  38.628 105.779 38.646 105.816 ;
    END
  END b[570]
  PIN b[571]
    DIRECTION OUTPUT ;
    USE SIGNAL ;
    PORT
      LAYER M3 ;
        RECT  38.7 105.779 38.718 105.816 ;
    END
  END b[571]
  PIN b[572]
    DIRECTION OUTPUT ;
    USE SIGNAL ;
    PORT
      LAYER M3 ;
        RECT  38.772 105.779 38.79 105.816 ;
    END
  END b[572]
  PIN b[573]
    DIRECTION OUTPUT ;
    USE SIGNAL ;
    PORT
      LAYER M3 ;
        RECT  38.844 105.779 38.862 105.816 ;
    END
  END b[573]
  PIN b[574]
    DIRECTION OUTPUT ;
    USE SIGNAL ;
    PORT
      LAYER M3 ;
        RECT  38.916 105.779 38.934 105.816 ;
    END
  END b[574]
  PIN b[575]
    DIRECTION OUTPUT ;
    USE SIGNAL ;
    PORT
      LAYER M3 ;
        RECT  38.988 105.779 39.006 105.816 ;
    END
  END b[575]
  PIN b[576]
    DIRECTION OUTPUT ;
    USE SIGNAL ;
    PORT
      LAYER M3 ;
        RECT  51.732 105.779 51.75 105.816 ;
    END
  END b[576]
  PIN b[577]
    DIRECTION OUTPUT ;
    USE SIGNAL ;
    PORT
      LAYER M3 ;
        RECT  51.804 105.779 51.822 105.816 ;
    END
  END b[577]
  PIN b[578]
    DIRECTION OUTPUT ;
    USE SIGNAL ;
    PORT
      LAYER M3 ;
        RECT  51.876 105.779 51.894 105.816 ;
    END
  END b[578]
  PIN b[579]
    DIRECTION OUTPUT ;
    USE SIGNAL ;
    PORT
      LAYER M3 ;
        RECT  51.948 105.779 51.966 105.816 ;
    END
  END b[579]
  PIN b[57]
    DIRECTION OUTPUT ;
    USE SIGNAL ;
    PORT
      LAYER M5 ;
        RECT  32.88 105.732 32.904 105.816 ;
    END
  END b[57]
  PIN b[580]
    DIRECTION OUTPUT ;
    USE SIGNAL ;
    PORT
      LAYER M3 ;
        RECT  52.02 105.779 52.038 105.816 ;
    END
  END b[580]
  PIN b[581]
    DIRECTION OUTPUT ;
    USE SIGNAL ;
    PORT
      LAYER M3 ;
        RECT  52.092 105.779 52.11 105.816 ;
    END
  END b[581]
  PIN b[582]
    DIRECTION OUTPUT ;
    USE SIGNAL ;
    PORT
      LAYER M3 ;
        RECT  52.164 105.779 52.182 105.816 ;
    END
  END b[582]
  PIN b[583]
    DIRECTION OUTPUT ;
    USE SIGNAL ;
    PORT
      LAYER M3 ;
        RECT  52.236 105.779 52.254 105.816 ;
    END
  END b[583]
  PIN b[584]
    DIRECTION OUTPUT ;
    USE SIGNAL ;
    PORT
      LAYER M3 ;
        RECT  52.308 105.779 52.326 105.816 ;
    END
  END b[584]
  PIN b[585]
    DIRECTION OUTPUT ;
    USE SIGNAL ;
    PORT
      LAYER M3 ;
        RECT  52.38 105.779 52.398 105.816 ;
    END
  END b[585]
  PIN b[586]
    DIRECTION OUTPUT ;
    USE SIGNAL ;
    PORT
      LAYER M3 ;
        RECT  52.452 105.779 52.47 105.816 ;
    END
  END b[586]
  PIN b[587]
    DIRECTION OUTPUT ;
    USE SIGNAL ;
    PORT
      LAYER M3 ;
        RECT  52.524 105.779 52.542 105.816 ;
    END
  END b[587]
  PIN b[588]
    DIRECTION OUTPUT ;
    USE SIGNAL ;
    PORT
      LAYER M3 ;
        RECT  52.596 105.779 52.614 105.816 ;
    END
  END b[588]
  PIN b[589]
    DIRECTION OUTPUT ;
    USE SIGNAL ;
    PORT
      LAYER M3 ;
        RECT  52.668 105.779 52.686 105.816 ;
    END
  END b[589]
  PIN b[58]
    DIRECTION OUTPUT ;
    USE SIGNAL ;
    PORT
      LAYER M5 ;
        RECT  32.976 105.732 33 105.816 ;
    END
  END b[58]
  PIN b[590]
    DIRECTION OUTPUT ;
    USE SIGNAL ;
    PORT
      LAYER M3 ;
        RECT  52.74 105.779 52.758 105.816 ;
    END
  END b[590]
  PIN b[591]
    DIRECTION OUTPUT ;
    USE SIGNAL ;
    PORT
      LAYER M3 ;
        RECT  52.812 105.779 52.83 105.816 ;
    END
  END b[591]
  PIN b[592]
    DIRECTION OUTPUT ;
    USE SIGNAL ;
    PORT
      LAYER M3 ;
        RECT  52.884 105.779 52.902 105.816 ;
    END
  END b[592]
  PIN b[593]
    DIRECTION OUTPUT ;
    USE SIGNAL ;
    PORT
      LAYER M3 ;
        RECT  52.956 105.779 52.974 105.816 ;
    END
  END b[593]
  PIN b[594]
    DIRECTION OUTPUT ;
    USE SIGNAL ;
    PORT
      LAYER M3 ;
        RECT  53.028 105.779 53.046 105.816 ;
    END
  END b[594]
  PIN b[595]
    DIRECTION OUTPUT ;
    USE SIGNAL ;
    PORT
      LAYER M3 ;
        RECT  53.1 105.779 53.118 105.816 ;
    END
  END b[595]
  PIN b[596]
    DIRECTION OUTPUT ;
    USE SIGNAL ;
    PORT
      LAYER M3 ;
        RECT  53.172 105.779 53.19 105.816 ;
    END
  END b[596]
  PIN b[597]
    DIRECTION OUTPUT ;
    USE SIGNAL ;
    PORT
      LAYER M3 ;
        RECT  53.244 105.779 53.262 105.816 ;
    END
  END b[597]
  PIN b[598]
    DIRECTION OUTPUT ;
    USE SIGNAL ;
    PORT
      LAYER M3 ;
        RECT  53.316 105.779 53.334 105.816 ;
    END
  END b[598]
  PIN b[599]
    DIRECTION OUTPUT ;
    USE SIGNAL ;
    PORT
      LAYER M3 ;
        RECT  53.388 105.779 53.406 105.816 ;
    END
  END b[599]
  PIN b[59]
    DIRECTION OUTPUT ;
    USE SIGNAL ;
    PORT
      LAYER M5 ;
        RECT  33.072 105.732 33.096 105.816 ;
    END
  END b[59]
  PIN b[5]
    DIRECTION OUTPUT ;
    USE SIGNAL ;
    PORT
      LAYER M3 ;
        RECT  49.212 105.779 49.23 105.816 ;
    END
  END b[5]
  PIN b[60]
    DIRECTION OUTPUT ;
    USE SIGNAL ;
    PORT
      LAYER M5 ;
        RECT  33.168 105.732 33.192 105.816 ;
    END
  END b[60]
  PIN b[61]
    DIRECTION OUTPUT ;
    USE SIGNAL ;
    PORT
      LAYER M5 ;
        RECT  33.264 105.732 33.288 105.816 ;
    END
  END b[61]
  PIN b[62]
    DIRECTION OUTPUT ;
    USE SIGNAL ;
    PORT
      LAYER M5 ;
        RECT  33.36 105.732 33.384 105.816 ;
    END
  END b[62]
  PIN b[63]
    DIRECTION OUTPUT ;
    USE SIGNAL ;
    PORT
      LAYER M5 ;
        RECT  33.456 105.732 33.48 105.816 ;
    END
  END b[63]
  PIN b[64]
    DIRECTION OUTPUT ;
    USE SIGNAL ;
    PORT
      LAYER M3 ;
        RECT  46.548 105.779 46.566 105.816 ;
    END
  END b[64]
  PIN b[65]
    DIRECTION OUTPUT ;
    USE SIGNAL ;
    PORT
      LAYER M3 ;
        RECT  46.62 105.779 46.638 105.816 ;
    END
  END b[65]
  PIN b[66]
    DIRECTION OUTPUT ;
    USE SIGNAL ;
    PORT
      LAYER M3 ;
        RECT  46.692 105.779 46.71 105.816 ;
    END
  END b[66]
  PIN b[67]
    DIRECTION OUTPUT ;
    USE SIGNAL ;
    PORT
      LAYER M3 ;
        RECT  46.764 105.779 46.782 105.816 ;
    END
  END b[67]
  PIN b[68]
    DIRECTION OUTPUT ;
    USE SIGNAL ;
    PORT
      LAYER M3 ;
        RECT  46.836 105.779 46.854 105.816 ;
    END
  END b[68]
  PIN b[69]
    DIRECTION OUTPUT ;
    USE SIGNAL ;
    PORT
      LAYER M3 ;
        RECT  46.908 105.779 46.926 105.816 ;
    END
  END b[69]
  PIN b[6]
    DIRECTION OUTPUT ;
    USE SIGNAL ;
    PORT
      LAYER M3 ;
        RECT  49.284 105.779 49.302 105.816 ;
    END
  END b[6]
  PIN b[70]
    DIRECTION OUTPUT ;
    USE SIGNAL ;
    PORT
      LAYER M3 ;
        RECT  46.98 105.779 46.998 105.816 ;
    END
  END b[70]
  PIN b[71]
    DIRECTION OUTPUT ;
    USE SIGNAL ;
    PORT
      LAYER M3 ;
        RECT  47.052 105.779 47.07 105.816 ;
    END
  END b[71]
  PIN b[72]
    DIRECTION OUTPUT ;
    USE SIGNAL ;
    PORT
      LAYER M3 ;
        RECT  47.124 105.779 47.142 105.816 ;
    END
  END b[72]
  PIN b[73]
    DIRECTION OUTPUT ;
    USE SIGNAL ;
    PORT
      LAYER M3 ;
        RECT  47.196 105.779 47.214 105.816 ;
    END
  END b[73]
  PIN b[74]
    DIRECTION OUTPUT ;
    USE SIGNAL ;
    PORT
      LAYER M3 ;
        RECT  47.268 105.779 47.286 105.816 ;
    END
  END b[74]
  PIN b[75]
    DIRECTION OUTPUT ;
    USE SIGNAL ;
    PORT
      LAYER M3 ;
        RECT  47.34 105.779 47.358 105.816 ;
    END
  END b[75]
  PIN b[76]
    DIRECTION OUTPUT ;
    USE SIGNAL ;
    PORT
      LAYER M3 ;
        RECT  47.412 105.779 47.43 105.816 ;
    END
  END b[76]
  PIN b[77]
    DIRECTION OUTPUT ;
    USE SIGNAL ;
    PORT
      LAYER M3 ;
        RECT  47.484 105.779 47.502 105.816 ;
    END
  END b[77]
  PIN b[78]
    DIRECTION OUTPUT ;
    USE SIGNAL ;
    PORT
      LAYER M3 ;
        RECT  47.556 105.779 47.574 105.816 ;
    END
  END b[78]
  PIN b[79]
    DIRECTION OUTPUT ;
    USE SIGNAL ;
    PORT
      LAYER M3 ;
        RECT  47.628 105.779 47.646 105.816 ;
    END
  END b[79]
  PIN b[7]
    DIRECTION OUTPUT ;
    USE SIGNAL ;
    PORT
      LAYER M3 ;
        RECT  49.356 105.779 49.374 105.816 ;
    END
  END b[7]
  PIN b[80]
    DIRECTION OUTPUT ;
    USE SIGNAL ;
    PORT
      LAYER M3 ;
        RECT  47.7 105.779 47.718 105.816 ;
    END
  END b[80]
  PIN b[81]
    DIRECTION OUTPUT ;
    USE SIGNAL ;
    PORT
      LAYER M3 ;
        RECT  47.772 105.779 47.79 105.816 ;
    END
  END b[81]
  PIN b[82]
    DIRECTION OUTPUT ;
    USE SIGNAL ;
    PORT
      LAYER M3 ;
        RECT  47.844 105.779 47.862 105.816 ;
    END
  END b[82]
  PIN b[83]
    DIRECTION OUTPUT ;
    USE SIGNAL ;
    PORT
      LAYER M3 ;
        RECT  47.916 105.779 47.934 105.816 ;
    END
  END b[83]
  PIN b[84]
    DIRECTION OUTPUT ;
    USE SIGNAL ;
    PORT
      LAYER M3 ;
        RECT  47.988 105.779 48.006 105.816 ;
    END
  END b[84]
  PIN b[85]
    DIRECTION OUTPUT ;
    USE SIGNAL ;
    PORT
      LAYER M3 ;
        RECT  48.06 105.779 48.078 105.816 ;
    END
  END b[85]
  PIN b[86]
    DIRECTION OUTPUT ;
    USE SIGNAL ;
    PORT
      LAYER M3 ;
        RECT  48.132 105.779 48.15 105.816 ;
    END
  END b[86]
  PIN b[87]
    DIRECTION OUTPUT ;
    USE SIGNAL ;
    PORT
      LAYER M3 ;
        RECT  48.204 105.779 48.222 105.816 ;
    END
  END b[87]
  PIN b[88]
    DIRECTION OUTPUT ;
    USE SIGNAL ;
    PORT
      LAYER M3 ;
        RECT  48.276 105.779 48.294 105.816 ;
    END
  END b[88]
  PIN b[89]
    DIRECTION OUTPUT ;
    USE SIGNAL ;
    PORT
      LAYER M3 ;
        RECT  48.348 105.779 48.366 105.816 ;
    END
  END b[89]
  PIN b[8]
    DIRECTION OUTPUT ;
    USE SIGNAL ;
    PORT
      LAYER M3 ;
        RECT  49.428 105.779 49.446 105.816 ;
    END
  END b[8]
  PIN b[90]
    DIRECTION OUTPUT ;
    USE SIGNAL ;
    PORT
      LAYER M3 ;
        RECT  48.42 105.779 48.438 105.816 ;
    END
  END b[90]
  PIN b[91]
    DIRECTION OUTPUT ;
    USE SIGNAL ;
    PORT
      LAYER M3 ;
        RECT  48.492 105.779 48.51 105.816 ;
    END
  END b[91]
  PIN b[92]
    DIRECTION OUTPUT ;
    USE SIGNAL ;
    PORT
      LAYER M3 ;
        RECT  48.564 105.779 48.582 105.816 ;
    END
  END b[92]
  PIN b[93]
    DIRECTION OUTPUT ;
    USE SIGNAL ;
    PORT
      LAYER M3 ;
        RECT  48.636 105.779 48.654 105.816 ;
    END
  END b[93]
  PIN b[94]
    DIRECTION OUTPUT ;
    USE SIGNAL ;
    PORT
      LAYER M3 ;
        RECT  48.708 105.779 48.726 105.816 ;
    END
  END b[94]
  PIN b[95]
    DIRECTION OUTPUT ;
    USE SIGNAL ;
    PORT
      LAYER M3 ;
        RECT  48.78 105.779 48.798 105.816 ;
    END
  END b[95]
  PIN b[96]
    DIRECTION OUTPUT ;
    USE SIGNAL ;
    PORT
      LAYER M5 ;
        RECT  52.752 105.732 52.776 105.816 ;
    END
  END b[96]
  PIN b[97]
    DIRECTION OUTPUT ;
    USE SIGNAL ;
    PORT
      LAYER M5 ;
        RECT  52.848 105.732 52.872 105.816 ;
    END
  END b[97]
  PIN b[98]
    DIRECTION OUTPUT ;
    USE SIGNAL ;
    PORT
      LAYER M5 ;
        RECT  52.944 105.732 52.968 105.816 ;
    END
  END b[98]
  PIN b[99]
    DIRECTION OUTPUT ;
    USE SIGNAL ;
    PORT
      LAYER M5 ;
        RECT  53.04 105.732 53.064 105.816 ;
    END
  END b[99]
  PIN b[9]
    DIRECTION OUTPUT ;
    USE SIGNAL ;
    PORT
      LAYER M3 ;
        RECT  49.5 105.779 49.518 105.816 ;
    END
  END b[9]
  PIN ck
    DIRECTION INPUT ;
    USE SIGNAL ;
    PORT
      LAYER M4 ;
        RECT  0 47.76 0.084 47.784 ;
    END
  END ck
  PIN ckf
    DIRECTION INPUT ;
    USE SIGNAL ;
    PORT
      LAYER M4 ;
        RECT  0 47.856 0.084 47.88 ;
    END
  END ckf
  PIN ea
    DIRECTION INPUT ;
    USE SIGNAL ;
    PORT
      LAYER M4 ;
        RECT  104.004 56.784 104.088 56.808 ;
    END
  END ea
  PIN fault
    DIRECTION OUTPUT ;
    USE SIGNAL ;
    PORT
      LAYER M4 ;
        RECT  0 47.952 0.084 47.976 ;
    END
  END fault
  PIN k0
    DIRECTION INPUT ;
    USE SIGNAL ;
    PORT
      LAYER M4 ;
        RECT  0 48.048 0.084 48.072 ;
    END
  END k0
  PIN k1
    DIRECTION INPUT ;
    USE SIGNAL ;
    PORT
      LAYER M4 ;
        RECT  0 48.144 0.084 48.168 ;
    END
  END k1
  PIN k2
    DIRECTION INPUT ;
    USE SIGNAL ;
    PORT
      LAYER M4 ;
        RECT  0 48.24 0.084 48.264 ;
    END
  END k2
  PIN rs
    DIRECTION INPUT ;
    USE SIGNAL ;
    PORT
      LAYER M4 ;
        RECT  0 48.336 0.084 48.36 ;
    END
  END rs
  PIN tie_hi
    DIRECTION OUTPUT ;
    USE SIGNAL ;
    PORT
      LAYER M4 ;
        RECT  0 48.432 0.084 48.456 ;
    END
  END tie_hi
  PIN tie_lo
    DIRECTION OUTPUT ;
    USE SIGNAL ;
    PORT
      LAYER M4 ;
        RECT  0 48.528 0.084 48.552 ;
    END
  END tie_lo
  PIN VDD
    DIRECTION INOUT ;
    USE POWER ;
    PORT
      LAYER M5 ;
        RECT  99.792 2.151 99.912 103.433 ;
        RECT  97.092 2.151 97.212 103.433 ;
        RECT  94.392 2.151 94.512 103.433 ;
        RECT  91.692 2.151 91.812 103.433 ;
        RECT  88.992 2.151 89.112 103.433 ;
        RECT  86.292 2.151 86.412 103.433 ;
        RECT  83.592 2.151 83.712 103.433 ;
        RECT  80.892 2.151 81.012 103.433 ;
        RECT  78.192 2.151 78.312 103.433 ;
        RECT  75.492 2.151 75.612 103.433 ;
        RECT  72.792 2.151 72.912 103.433 ;
        RECT  70.092 2.151 70.212 103.433 ;
        RECT  67.392 2.151 67.512 103.433 ;
        RECT  64.692 2.151 64.812 103.433 ;
        RECT  61.992 2.151 62.112 103.433 ;
        RECT  59.292 2.151 59.412 103.433 ;
        RECT  56.592 2.151 56.712 103.433 ;
        RECT  53.892 2.151 54.012 103.433 ;
        RECT  51.192 2.151 51.312 103.433 ;
        RECT  48.492 2.151 48.612 103.433 ;
        RECT  45.792 2.151 45.912 103.433 ;
        RECT  43.092 2.151 43.212 103.433 ;
        RECT  40.392 2.151 40.512 103.433 ;
        RECT  37.692 2.151 37.812 103.433 ;
        RECT  34.992 2.151 35.112 103.433 ;
        RECT  32.292 2.151 32.412 103.433 ;
        RECT  29.592 2.151 29.712 103.433 ;
        RECT  26.892 2.151 27.012 103.433 ;
        RECT  24.192 2.151 24.312 103.433 ;
        RECT  21.492 2.151 21.612 103.433 ;
        RECT  18.792 2.151 18.912 103.433 ;
        RECT  16.092 2.151 16.212 103.433 ;
        RECT  13.392 2.151 13.512 103.433 ;
        RECT  10.692 2.151 10.812 103.433 ;
        RECT  7.992 2.151 8.112 103.433 ;
        RECT  5.292 2.151 5.412 103.433 ;
        RECT  2.592 2.151 2.712 103.433 ;
    END
  END VDD
  PIN VSS
    DIRECTION INOUT ;
    USE GROUND ;
    PORT
      LAYER M5 ;
        RECT  99.6 2.137 99.72 103.419 ;
        RECT  96.9 2.137 97.02 103.419 ;
        RECT  94.2 2.137 94.32 103.419 ;
        RECT  91.5 2.137 91.62 103.419 ;
        RECT  88.8 2.137 88.92 103.419 ;
        RECT  86.1 2.137 86.22 103.419 ;
        RECT  83.4 2.137 83.52 103.419 ;
        RECT  80.7 2.137 80.82 103.419 ;
        RECT  78 2.137 78.12 103.419 ;
        RECT  75.3 2.137 75.42 103.419 ;
        RECT  72.6 2.137 72.72 103.419 ;
        RECT  69.9 2.137 70.02 103.419 ;
        RECT  67.2 2.137 67.32 103.419 ;
        RECT  64.5 2.137 64.62 103.419 ;
        RECT  61.8 2.137 61.92 103.419 ;
        RECT  59.1 2.137 59.22 103.419 ;
        RECT  56.4 2.137 56.52 103.419 ;
        RECT  53.7 2.137 53.82 103.419 ;
        RECT  51 2.137 51.12 103.419 ;
        RECT  48.3 2.137 48.42 103.419 ;
        RECT  45.6 2.137 45.72 103.419 ;
        RECT  42.9 2.137 43.02 103.419 ;
        RECT  40.2 2.137 40.32 103.419 ;
        RECT  37.5 2.137 37.62 103.419 ;
        RECT  34.8 2.137 34.92 103.419 ;
        RECT  32.1 2.137 32.22 103.419 ;
        RECT  29.4 2.137 29.52 103.419 ;
        RECT  26.7 2.137 26.82 103.419 ;
        RECT  24 2.137 24.12 103.419 ;
        RECT  21.3 2.137 21.42 103.419 ;
        RECT  18.6 2.137 18.72 103.419 ;
        RECT  15.9 2.137 16.02 103.419 ;
        RECT  13.2 2.137 13.32 103.419 ;
        RECT  10.5 2.137 10.62 103.419 ;
        RECT  7.8 2.137 7.92 103.419 ;
        RECT  5.1 2.137 5.22 103.419 ;
        RECT  2.4 2.137 2.52 103.419 ;
    END
  END VSS
  OBS
    LAYER RVTN ;
     RECT  2.16 2.16 101.898 2.295 ;
     RECT  2.16 2.565 101.898 2.835 ;
     RECT  2.16 3.105 101.898 3.375 ;
     RECT  2.16 3.645 101.898 3.915 ;
     RECT  2.16 4.185 101.898 4.455 ;
     RECT  2.16 4.725 101.898 4.995 ;
     RECT  2.16 5.265 101.898 5.535 ;
     RECT  2.16 5.805 101.898 6.075 ;
     RECT  2.16 6.345 101.898 6.615 ;
     RECT  2.16 6.885 101.898 7.155 ;
     RECT  2.16 7.425 101.898 7.695 ;
     RECT  2.16 7.965 101.898 8.235 ;
     RECT  2.16 8.505 101.898 8.775 ;
     RECT  2.16 9.045 101.898 9.315 ;
     RECT  2.16 9.585 101.898 9.855 ;
     RECT  2.16 10.125 101.898 10.395 ;
     RECT  2.16 10.665 101.898 10.935 ;
     RECT  2.16 11.205 101.898 11.475 ;
     RECT  2.16 11.745 101.898 12.015 ;
     RECT  2.16 12.285 101.898 12.555 ;
     RECT  2.16 12.825 101.898 13.095 ;
     RECT  2.16 13.365 101.898 13.635 ;
     RECT  2.16 13.905 101.898 14.175 ;
     RECT  2.16 14.445 101.898 14.715 ;
     RECT  2.16 14.985 101.898 15.255 ;
     RECT  2.16 15.525 101.898 15.795 ;
     RECT  2.16 16.065 101.898 16.335 ;
     RECT  2.16 16.605 101.898 16.875 ;
     RECT  2.16 17.145 101.898 17.415 ;
     RECT  2.16 17.685 101.898 17.955 ;
     RECT  2.16 18.225 101.898 18.495 ;
     RECT  2.16 18.765 101.898 19.035 ;
     RECT  2.16 19.305 101.898 19.575 ;
     RECT  2.16 19.845 101.898 20.115 ;
     RECT  2.16 20.385 101.898 20.655 ;
     RECT  2.16 20.925 101.898 21.195 ;
     RECT  2.16 21.465 101.898 21.735 ;
     RECT  2.16 22.005 101.898 22.275 ;
     RECT  2.16 22.545 101.898 22.815 ;
     RECT  2.16 23.085 101.898 23.355 ;
     RECT  2.16 23.625 101.898 23.895 ;
     RECT  2.16 24.165 101.898 24.435 ;
     RECT  2.16 24.705 101.898 24.975 ;
     RECT  2.16 25.245 101.898 25.515 ;
     RECT  2.16 25.785 101.898 26.055 ;
     RECT  2.16 26.325 101.898 26.595 ;
     RECT  2.16 26.865 101.898 27.135 ;
     RECT  2.16 27.405 101.898 27.675 ;
     RECT  2.16 27.945 101.898 28.215 ;
     RECT  2.16 28.485 101.898 28.755 ;
     RECT  2.16 29.025 101.898 29.295 ;
     RECT  2.16 29.565 101.898 29.835 ;
     RECT  2.16 30.105 101.898 30.375 ;
     RECT  2.16 30.645 101.898 30.915 ;
     RECT  2.16 31.185 101.898 31.455 ;
     RECT  2.16 31.725 101.898 31.995 ;
     RECT  2.16 32.265 101.898 32.535 ;
     RECT  2.16 32.805 101.898 33.075 ;
     RECT  2.16 33.345 101.898 33.615 ;
     RECT  2.16 33.885 101.898 34.155 ;
     RECT  2.16 34.425 101.898 34.695 ;
     RECT  2.16 34.965 101.898 35.235 ;
     RECT  2.16 35.505 101.898 35.775 ;
     RECT  2.16 36.045 101.898 36.315 ;
     RECT  2.16 36.585 101.898 36.855 ;
     RECT  2.16 37.125 101.898 37.395 ;
     RECT  2.16 37.665 101.898 37.935 ;
     RECT  2.16 38.205 101.898 38.475 ;
     RECT  2.16 38.745 101.898 39.015 ;
     RECT  2.16 39.285 101.898 39.555 ;
     RECT  2.16 39.825 101.898 40.095 ;
     RECT  2.16 40.365 101.898 40.635 ;
     RECT  2.16 40.905 101.898 41.175 ;
     RECT  2.16 41.445 101.898 41.715 ;
     RECT  2.16 41.985 101.898 42.255 ;
     RECT  2.16 42.525 101.898 42.795 ;
     RECT  2.16 43.065 101.898 43.335 ;
     RECT  2.16 43.605 101.898 43.875 ;
     RECT  2.16 44.145 101.898 44.415 ;
     RECT  2.16 44.685 101.898 44.955 ;
     RECT  2.16 45.225 101.898 45.495 ;
     RECT  2.16 45.765 101.898 46.035 ;
     RECT  2.16 46.305 101.898 46.575 ;
     RECT  2.16 46.845 101.898 47.115 ;
     RECT  2.16 47.385 101.898 47.655 ;
     RECT  2.16 47.925 101.898 48.195 ;
     RECT  2.16 48.465 101.898 48.735 ;
     RECT  2.16 49.005 101.898 49.275 ;
     RECT  2.16 49.545 101.898 49.815 ;
     RECT  2.16 50.085 101.898 50.355 ;
     RECT  2.16 50.625 101.898 50.895 ;
     RECT  2.16 51.165 101.898 51.435 ;
     RECT  2.16 51.705 101.898 51.975 ;
     RECT  2.16 52.245 101.898 52.515 ;
     RECT  2.16 52.785 101.898 53.055 ;
     RECT  2.16 53.325 101.898 53.595 ;
     RECT  2.16 53.865 101.898 54.135 ;
     RECT  2.16 54.405 101.898 54.675 ;
     RECT  2.16 54.945 101.898 55.215 ;
     RECT  2.16 55.485 101.898 55.755 ;
     RECT  2.16 56.025 101.898 56.295 ;
     RECT  2.16 56.565 101.898 56.835 ;
     RECT  2.16 57.105 101.898 57.375 ;
     RECT  2.16 57.645 101.898 57.915 ;
     RECT  2.16 58.185 101.898 58.455 ;
     RECT  2.16 58.725 101.898 58.995 ;
     RECT  2.16 59.265 101.898 59.535 ;
     RECT  2.16 59.805 101.898 60.075 ;
     RECT  2.16 60.345 101.898 60.615 ;
     RECT  2.16 60.885 101.898 61.155 ;
     RECT  2.16 61.425 101.898 61.695 ;
     RECT  2.16 61.965 101.898 62.235 ;
     RECT  2.16 62.505 101.898 62.775 ;
     RECT  2.16 63.045 101.898 63.315 ;
     RECT  2.16 63.585 101.898 63.855 ;
     RECT  2.16 64.125 101.898 64.395 ;
     RECT  2.16 64.665 101.898 64.935 ;
     RECT  2.16 65.205 101.898 65.475 ;
     RECT  2.16 65.745 101.898 66.015 ;
     RECT  2.16 66.285 101.898 66.555 ;
     RECT  2.16 66.825 101.898 67.095 ;
     RECT  2.16 67.365 101.898 67.635 ;
     RECT  2.16 67.905 101.898 68.175 ;
     RECT  2.16 68.445 101.898 68.715 ;
     RECT  2.16 68.985 101.898 69.255 ;
     RECT  2.16 69.525 101.898 69.795 ;
     RECT  2.16 70.065 101.898 70.335 ;
     RECT  2.16 70.605 101.898 70.875 ;
     RECT  2.16 71.145 101.898 71.415 ;
     RECT  2.16 71.685 101.898 71.955 ;
     RECT  2.16 72.225 101.898 72.495 ;
     RECT  2.16 72.765 101.898 73.035 ;
     RECT  2.16 73.305 101.898 73.575 ;
     RECT  2.16 73.845 101.898 74.115 ;
     RECT  2.16 74.385 101.898 74.655 ;
     RECT  2.16 74.925 101.898 75.195 ;
     RECT  2.16 75.465 101.898 75.735 ;
     RECT  2.16 76.005 101.898 76.275 ;
     RECT  2.16 76.545 101.898 76.815 ;
     RECT  2.16 77.085 101.898 77.355 ;
     RECT  2.16 77.625 101.898 77.895 ;
     RECT  2.16 78.165 101.898 78.435 ;
     RECT  2.16 78.705 101.898 78.975 ;
     RECT  2.16 79.245 101.898 79.515 ;
     RECT  2.16 79.785 101.898 80.055 ;
     RECT  2.16 80.325 101.898 80.595 ;
     RECT  2.16 80.865 101.898 81.135 ;
     RECT  2.16 81.405 101.898 81.675 ;
     RECT  2.16 81.945 101.898 82.215 ;
     RECT  2.16 82.485 101.898 82.755 ;
     RECT  2.16 83.025 101.898 83.295 ;
     RECT  2.16 83.565 101.898 83.835 ;
     RECT  2.16 84.105 101.898 84.375 ;
     RECT  2.16 84.645 101.898 84.915 ;
     RECT  2.16 85.185 101.898 85.455 ;
     RECT  2.16 85.725 101.898 85.995 ;
     RECT  2.16 86.265 101.898 86.535 ;
     RECT  2.16 86.805 101.898 87.075 ;
     RECT  2.16 87.345 101.898 87.615 ;
     RECT  2.16 87.885 101.898 88.155 ;
     RECT  2.16 88.425 101.898 88.695 ;
     RECT  2.16 88.965 101.898 89.235 ;
     RECT  2.16 89.505 101.898 89.775 ;
     RECT  2.16 90.045 101.898 90.315 ;
     RECT  2.16 90.585 101.898 90.855 ;
     RECT  2.16 91.125 101.898 91.395 ;
     RECT  2.16 91.665 101.898 91.935 ;
     RECT  2.16 92.205 101.898 92.475 ;
     RECT  2.16 92.745 101.898 93.015 ;
     RECT  2.16 93.285 101.898 93.555 ;
     RECT  2.16 93.825 101.898 94.095 ;
     RECT  2.16 94.365 101.898 94.635 ;
     RECT  2.16 94.905 101.898 95.175 ;
     RECT  2.16 95.445 101.898 95.715 ;
     RECT  2.16 95.985 101.898 96.255 ;
     RECT  2.16 96.525 101.898 96.795 ;
     RECT  2.16 97.065 101.898 97.335 ;
     RECT  2.16 97.605 101.898 97.875 ;
     RECT  2.16 98.145 101.898 98.415 ;
     RECT  2.16 98.685 101.898 98.955 ;
     RECT  2.16 99.225 101.898 99.495 ;
     RECT  2.16 99.765 101.898 100.035 ;
     RECT  2.16 100.305 101.898 100.575 ;
     RECT  2.16 100.845 101.898 101.115 ;
     RECT  2.16 101.385 101.898 101.655 ;
     RECT  2.16 101.925 101.898 102.195 ;
     RECT  2.16 102.465 101.898 102.735 ;
     RECT  2.16 103.005 101.898 103.275 ;
    LAYER RVTP ;
     RECT  2.16 2.295 101.898 2.565 ;
     RECT  2.16 2.835 101.898 3.105 ;
     RECT  2.16 3.375 101.898 3.645 ;
     RECT  2.16 3.915 101.898 4.185 ;
     RECT  2.16 4.455 101.898 4.725 ;
     RECT  2.16 4.995 101.898 5.265 ;
     RECT  2.16 5.535 101.898 5.805 ;
     RECT  2.16 6.075 101.898 6.345 ;
     RECT  2.16 6.615 101.898 6.885 ;
     RECT  2.16 7.155 101.898 7.425 ;
     RECT  2.16 7.695 101.898 7.965 ;
     RECT  2.16 8.235 101.898 8.505 ;
     RECT  2.16 8.775 101.898 9.045 ;
     RECT  2.16 9.315 101.898 9.585 ;
     RECT  2.16 9.855 101.898 10.125 ;
     RECT  2.16 10.395 101.898 10.665 ;
     RECT  2.16 10.935 101.898 11.205 ;
     RECT  2.16 11.475 101.898 11.745 ;
     RECT  2.16 12.015 101.898 12.285 ;
     RECT  2.16 12.555 101.898 12.825 ;
     RECT  2.16 13.095 101.898 13.365 ;
     RECT  2.16 13.635 101.898 13.905 ;
     RECT  2.16 14.175 101.898 14.445 ;
     RECT  2.16 14.715 101.898 14.985 ;
     RECT  2.16 15.255 101.898 15.525 ;
     RECT  2.16 15.795 101.898 16.065 ;
     RECT  2.16 16.335 101.898 16.605 ;
     RECT  2.16 16.875 101.898 17.145 ;
     RECT  2.16 17.415 101.898 17.685 ;
     RECT  2.16 17.955 101.898 18.225 ;
     RECT  2.16 18.495 101.898 18.765 ;
     RECT  2.16 19.035 101.898 19.305 ;
     RECT  2.16 19.575 101.898 19.845 ;
     RECT  2.16 20.115 101.898 20.385 ;
     RECT  2.16 20.655 101.898 20.925 ;
     RECT  2.16 21.195 101.898 21.465 ;
     RECT  2.16 21.735 101.898 22.005 ;
     RECT  2.16 22.275 101.898 22.545 ;
     RECT  2.16 22.815 101.898 23.085 ;
     RECT  2.16 23.355 101.898 23.625 ;
     RECT  2.16 23.895 101.898 24.165 ;
     RECT  2.16 24.435 101.898 24.705 ;
     RECT  2.16 24.975 101.898 25.245 ;
     RECT  2.16 25.515 101.898 25.785 ;
     RECT  2.16 26.055 101.898 26.325 ;
     RECT  2.16 26.595 101.898 26.865 ;
     RECT  2.16 27.135 101.898 27.405 ;
     RECT  2.16 27.675 101.898 27.945 ;
     RECT  2.16 28.215 101.898 28.485 ;
     RECT  2.16 28.755 101.898 29.025 ;
     RECT  2.16 29.295 101.898 29.565 ;
     RECT  2.16 29.835 101.898 30.105 ;
     RECT  2.16 30.375 101.898 30.645 ;
     RECT  2.16 30.915 101.898 31.185 ;
     RECT  2.16 31.455 101.898 31.725 ;
     RECT  2.16 31.995 101.898 32.265 ;
     RECT  2.16 32.535 101.898 32.805 ;
     RECT  2.16 33.075 101.898 33.345 ;
     RECT  2.16 33.615 101.898 33.885 ;
     RECT  2.16 34.155 101.898 34.425 ;
     RECT  2.16 34.695 101.898 34.965 ;
     RECT  2.16 35.235 101.898 35.505 ;
     RECT  2.16 35.775 101.898 36.045 ;
     RECT  2.16 36.315 101.898 36.585 ;
     RECT  2.16 36.855 101.898 37.125 ;
     RECT  2.16 37.395 101.898 37.665 ;
     RECT  2.16 37.935 101.898 38.205 ;
     RECT  2.16 38.475 101.898 38.745 ;
     RECT  2.16 39.015 101.898 39.285 ;
     RECT  2.16 39.555 101.898 39.825 ;
     RECT  2.16 40.095 101.898 40.365 ;
     RECT  2.16 40.635 101.898 40.905 ;
     RECT  2.16 41.175 101.898 41.445 ;
     RECT  2.16 41.715 101.898 41.985 ;
     RECT  2.16 42.255 101.898 42.525 ;
     RECT  2.16 42.795 101.898 43.065 ;
     RECT  2.16 43.335 101.898 43.605 ;
     RECT  2.16 43.875 101.898 44.145 ;
     RECT  2.16 44.415 101.898 44.685 ;
     RECT  2.16 44.955 101.898 45.225 ;
     RECT  2.16 45.495 101.898 45.765 ;
     RECT  2.16 46.035 101.898 46.305 ;
     RECT  2.16 46.575 101.898 46.845 ;
     RECT  2.16 47.115 101.898 47.385 ;
     RECT  2.16 47.655 101.898 47.925 ;
     RECT  2.16 48.195 101.898 48.465 ;
     RECT  2.16 48.735 101.898 49.005 ;
     RECT  2.16 49.275 101.898 49.545 ;
     RECT  2.16 49.815 101.898 50.085 ;
     RECT  2.16 50.355 101.898 50.625 ;
     RECT  2.16 50.895 101.898 51.165 ;
     RECT  2.16 51.435 101.898 51.705 ;
     RECT  2.16 51.975 101.898 52.245 ;
     RECT  2.16 52.515 101.898 52.785 ;
     RECT  2.16 53.055 101.898 53.325 ;
     RECT  2.16 53.595 101.898 53.865 ;
     RECT  2.16 54.135 101.898 54.405 ;
     RECT  2.16 54.675 101.898 54.945 ;
     RECT  2.16 55.215 101.898 55.485 ;
     RECT  2.16 55.755 101.898 56.025 ;
     RECT  2.16 56.295 101.898 56.565 ;
     RECT  2.16 56.835 101.898 57.105 ;
     RECT  2.16 57.375 101.898 57.645 ;
     RECT  2.16 57.915 101.898 58.185 ;
     RECT  2.16 58.455 101.898 58.725 ;
     RECT  2.16 58.995 101.898 59.265 ;
     RECT  2.16 59.535 101.898 59.805 ;
     RECT  2.16 60.075 101.898 60.345 ;
     RECT  2.16 60.615 101.898 60.885 ;
     RECT  2.16 61.155 101.898 61.425 ;
     RECT  2.16 61.695 101.898 61.965 ;
     RECT  2.16 62.235 101.898 62.505 ;
     RECT  2.16 62.775 101.898 63.045 ;
     RECT  2.16 63.315 101.898 63.585 ;
     RECT  2.16 63.855 101.898 64.125 ;
     RECT  2.16 64.395 101.898 64.665 ;
     RECT  2.16 64.935 101.898 65.205 ;
     RECT  2.16 65.475 101.898 65.745 ;
     RECT  2.16 66.015 101.898 66.285 ;
     RECT  2.16 66.555 101.898 66.825 ;
     RECT  2.16 67.095 101.898 67.365 ;
     RECT  2.16 67.635 101.898 67.905 ;
     RECT  2.16 68.175 101.898 68.445 ;
     RECT  2.16 68.715 101.898 68.985 ;
     RECT  2.16 69.255 101.898 69.525 ;
     RECT  2.16 69.795 101.898 70.065 ;
     RECT  2.16 70.335 101.898 70.605 ;
     RECT  2.16 70.875 101.898 71.145 ;
     RECT  2.16 71.415 101.898 71.685 ;
     RECT  2.16 71.955 101.898 72.225 ;
     RECT  2.16 72.495 101.898 72.765 ;
     RECT  2.16 73.035 101.898 73.305 ;
     RECT  2.16 73.575 101.898 73.845 ;
     RECT  2.16 74.115 101.898 74.385 ;
     RECT  2.16 74.655 101.898 74.925 ;
     RECT  2.16 75.195 101.898 75.465 ;
     RECT  2.16 75.735 101.898 76.005 ;
     RECT  2.16 76.275 101.898 76.545 ;
     RECT  2.16 76.815 101.898 77.085 ;
     RECT  2.16 77.355 101.898 77.625 ;
     RECT  2.16 77.895 101.898 78.165 ;
     RECT  2.16 78.435 101.898 78.705 ;
     RECT  2.16 78.975 101.898 79.245 ;
     RECT  2.16 79.515 101.898 79.785 ;
     RECT  2.16 80.055 101.898 80.325 ;
     RECT  2.16 80.595 101.898 80.865 ;
     RECT  2.16 81.135 101.898 81.405 ;
     RECT  2.16 81.675 101.898 81.945 ;
     RECT  2.16 82.215 101.898 82.485 ;
     RECT  2.16 82.755 101.898 83.025 ;
     RECT  2.16 83.295 101.898 83.565 ;
     RECT  2.16 83.835 101.898 84.105 ;
     RECT  2.16 84.375 101.898 84.645 ;
     RECT  2.16 84.915 101.898 85.185 ;
     RECT  2.16 85.455 101.898 85.725 ;
     RECT  2.16 85.995 101.898 86.265 ;
     RECT  2.16 86.535 101.898 86.805 ;
     RECT  2.16 87.075 101.898 87.345 ;
     RECT  2.16 87.615 101.898 87.885 ;
     RECT  2.16 88.155 101.898 88.425 ;
     RECT  2.16 88.695 101.898 88.965 ;
     RECT  2.16 89.235 101.898 89.505 ;
     RECT  2.16 89.775 101.898 90.045 ;
     RECT  2.16 90.315 101.898 90.585 ;
     RECT  2.16 90.855 101.898 91.125 ;
     RECT  2.16 91.395 101.898 91.665 ;
     RECT  2.16 91.935 101.898 92.205 ;
     RECT  2.16 92.475 101.898 92.745 ;
     RECT  2.16 93.015 101.898 93.285 ;
     RECT  2.16 93.555 101.898 93.825 ;
     RECT  2.16 94.095 101.898 94.365 ;
     RECT  2.16 94.635 101.898 94.905 ;
     RECT  2.16 95.175 101.898 95.445 ;
     RECT  2.16 95.715 101.898 95.985 ;
     RECT  2.16 96.255 101.898 96.525 ;
     RECT  2.16 96.795 101.898 97.065 ;
     RECT  2.16 97.335 101.898 97.605 ;
     RECT  2.16 97.875 101.898 98.145 ;
     RECT  2.16 98.415 101.898 98.685 ;
     RECT  2.16 98.955 101.898 99.225 ;
     RECT  2.16 99.495 101.898 99.765 ;
     RECT  2.16 100.035 101.898 100.305 ;
     RECT  2.16 100.575 101.898 100.845 ;
     RECT  2.16 101.115 101.898 101.385 ;
     RECT  2.16 101.655 101.898 101.925 ;
     RECT  2.16 102.195 101.898 102.465 ;
     RECT  2.16 102.735 101.898 103.005 ;
     RECT  2.16 103.275 101.898 103.41 ;
    LAYER M1 ;
     RECT  2.16 2.151 101.898 103.419 ;
    LAYER M2 ;
     RECT  0.535 47.43 2.16 47.448 ;
     RECT  0.103 48.402 2.16 48.42 ;
     RECT  2.16 2.151 26.167 103.419 ;
     RECT  26.167 2.151 26.527 103.464 ;
     RECT  26.851 104.868 26.987 104.886 ;
     RECT  26.527 2.151 27.139 103.536 ;
     RECT  27.211 105.75 27.499 105.768 ;
     RECT  27.499 105.516 27.967 105.768 ;
     RECT  27.967 104.796 28.067 105.768 ;
     RECT  28.067 104.868 28.103 105.768 ;
     RECT  27.139 2.151 28.499 103.608 ;
     RECT  28.867 104.796 28.975 104.814 ;
     RECT  28.103 105.561 28.975 105.768 ;
     RECT  28.975 104.796 29.003 105.768 ;
     RECT  29.003 104.868 29.039 105.768 ;
     RECT  29.039 104.868 29.075 105.624 ;
     RECT  29.075 104.868 29.327 104.886 ;
     RECT  28.499 2.151 29.579 103.464 ;
     RECT  31.783 104.868 31.919 104.886 ;
     RECT  29.579 2.151 33.943 103.419 ;
     RECT  33.943 2.151 35.275 103.536 ;
     RECT  36.715 105.75 36.823 105.768 ;
     RECT  36.823 105.642 36.895 105.768 ;
     RECT  36.895 105.561 38.003 105.768 ;
     RECT  38.003 105.642 38.687 105.768 ;
     RECT  38.687 105.678 38.723 105.768 ;
     RECT  35.275 2.151 38.767 103.572 ;
     RECT  38.723 105.714 39.083 105.768 ;
     RECT  39.083 105.75 39.119 105.768 ;
     RECT  38.767 2.151 39.335 103.734 ;
     RECT  39.335 2.151 41.495 103.572 ;
     RECT  41.431 104.868 41.827 104.886 ;
     RECT  41.107 105.75 41.827 105.768 ;
     RECT  41.827 104.796 42.035 104.886 ;
     RECT  42.035 104.868 42.187 104.886 ;
     RECT  41.827 105.678 42.187 105.768 ;
     RECT  42.187 104.868 42.647 105.768 ;
     RECT  42.647 105.561 43.187 105.768 ;
     RECT  41.495 2.151 43.195 103.5 ;
     RECT  43.195 2.151 43.367 103.734 ;
     RECT  43.187 105.678 43.799 105.768 ;
     RECT  43.799 105.678 43.835 105.696 ;
     RECT  43.367 2.151 44.483 103.572 ;
     RECT  44.483 2.151 45.931 103.419 ;
     RECT  46.291 105.606 46.363 105.624 ;
     RECT  45.931 2.151 46.399 103.464 ;
     RECT  46.363 105.606 46.471 105.696 ;
     RECT  46.399 2.151 46.931 103.5 ;
     RECT  46.471 105.606 47.983 105.768 ;
     RECT  47.983 105.561 48.199 105.768 ;
     RECT  48.199 105.48 48.443 105.768 ;
     RECT  46.931 2.151 48.451 103.464 ;
     RECT  48.451 2.151 48.587 103.5 ;
     RECT  48.587 2.151 48.731 103.464 ;
     RECT  48.443 105.516 49.279 105.768 ;
     RECT  49.279 104.868 49.351 105.768 ;
     RECT  49.351 104.328 49.487 105.768 ;
     RECT  49.487 104.328 49.883 104.346 ;
     RECT  48.731 2.151 50.251 103.419 ;
     RECT  49.487 105.606 50.431 105.768 ;
     RECT  50.431 105.516 50.539 105.768 ;
     RECT  50.539 105.444 50.675 105.768 ;
     RECT  50.675 105.642 50.711 105.768 ;
     RECT  51.583 104.796 51.619 104.814 ;
     RECT  51.619 104.796 51.727 104.886 ;
     RECT  50.711 105.75 51.727 105.768 ;
     RECT  51.727 104.796 51.907 105.768 ;
     RECT  51.907 104.751 52.123 105.768 ;
     RECT  52.123 104.634 52.331 105.768 ;
     RECT  52.331 104.751 52.943 105.768 ;
     RECT  52.943 104.796 52.979 105.768 ;
     RECT  52.979 104.796 53.411 105.696 ;
     RECT  53.411 104.796 53.555 104.886 ;
     RECT  53.411 105.642 53.555 105.696 ;
     RECT  53.555 105.642 53.591 105.66 ;
     RECT  50.251 2.151 56.291 103.644 ;
     RECT  56.291 2.151 57.055 103.572 ;
     RECT  63.319 105.75 63.355 105.768 ;
     RECT  63.355 104.796 63.535 104.814 ;
     RECT  63.355 105.561 63.535 105.768 ;
     RECT  63.535 104.796 63.643 105.768 ;
     RECT  63.643 104.751 63.851 105.768 ;
     RECT  63.851 104.796 64.103 105.768 ;
     RECT  57.055 2.151 64.543 103.689 ;
     RECT  64.543 2.151 65.039 103.734 ;
     RECT  64.103 105.516 65.047 105.768 ;
     RECT  65.047 104.868 65.119 105.768 ;
     RECT  65.119 104.67 65.219 105.768 ;
     RECT  65.039 2.151 65.911 103.689 ;
     RECT  65.219 104.706 66.011 105.768 ;
     RECT  66.011 104.796 66.811 105.768 ;
     RECT  65.911 2.151 67.279 103.734 ;
     RECT  66.811 104.751 67.279 105.768 ;
     RECT  67.279 2.151 67.883 105.768 ;
     RECT  67.883 2.151 68.891 104.886 ;
     RECT  68.891 2.151 68.963 104.346 ;
     RECT  68.963 2.151 72.967 103.689 ;
     RECT  72.967 2.151 82.643 103.734 ;
     RECT  82.643 2.151 85.775 103.689 ;
     RECT  85.775 2.151 96.143 103.644 ;
     RECT  96.143 2.151 101.898 103.419 ;
     RECT  101.898 52.56 101.903 52.578 ;
     RECT  101.898 62.478 101.903 62.838 ;
     RECT  101.898 66.33 101.903 68.436 ;
     RECT  101.898 54.216 101.939 55.044 ;
     RECT  101.898 55.962 101.939 59.058 ;
     RECT  101.898 60.39 101.939 60.408 ;
     RECT  101.939 54.306 101.975 55.044 ;
     RECT  101.939 56.61 101.975 59.058 ;
     RECT  101.898 69.264 101.975 70.974 ;
     RECT  101.898 33.39 102.011 34.146 ;
     RECT  101.898 45.846 102.047 46.332 ;
     RECT  101.898 83.07 102.047 85.788 ;
     RECT  101.903 67.608 102.083 68.436 ;
     RECT  101.898 47.43 102.299 51.228 ;
     RECT  101.898 71.73 102.371 72.054 ;
     RECT  101.898 73.116 102.551 74.484 ;
     RECT  101.898 80.604 102.551 81.468 ;
     RECT  101.898 22.086 102.587 22.5 ;
     RECT  101.898 25.794 102.587 25.812 ;
     RECT  101.898 63.666 102.587 63.684 ;
     RECT  102.371 71.73 102.587 71.748 ;
     RECT  102.551 80.604 102.587 80.622 ;
     RECT  101.898 24.516 102.623 25.038 ;
     RECT  102.011 33.588 102.623 34.146 ;
     RECT  101.898 36.09 102.623 37.89 ;
     RECT  101.975 56.61 102.623 58.248 ;
     RECT  101.903 66.33 102.623 66.582 ;
     RECT  102.083 67.608 102.623 67.698 ;
     RECT  102.551 73.116 102.623 74.448 ;
     RECT  101.898 77.904 102.623 79.344 ;
     RECT  102.551 81.378 102.623 81.468 ;
     RECT  101.898 87.858 102.623 89.874 ;
     RECT  102.623 36.594 102.659 37.89 ;
     RECT  102.299 47.43 102.659 50.994 ;
     RECT  101.898 64.944 102.659 65.502 ;
     RECT  102.623 66.33 102.659 66.348 ;
     RECT  101.975 69.264 102.659 69.282 ;
     RECT  101.898 82.26 102.659 82.278 ;
     RECT  102.623 89.316 102.659 89.874 ;
     RECT  102.659 47.43 102.695 48.564 ;
     RECT  102.659 49.626 102.731 50.994 ;
     RECT  102.047 83.61 102.767 85.788 ;
     RECT  101.898 35.01 102.803 35.028 ;
     RECT  101.903 62.82 102.803 62.838 ;
     RECT  102.731 49.626 102.875 50.184 ;
     RECT  101.975 59.04 102.875 59.058 ;
     RECT  101.975 70.146 102.875 70.974 ;
     RECT  102.623 73.116 102.911 73.908 ;
     RECT  101.898 26.802 103.163 26.928 ;
     RECT  102.587 22.482 103.199 22.5 ;
     RECT  101.898 23.436 103.199 23.454 ;
     RECT  102.623 24.678 103.199 24.696 ;
     RECT  103.163 26.838 103.199 26.928 ;
     RECT  101.898 27.684 103.199 29.052 ;
     RECT  101.898 32.274 103.199 32.292 ;
     RECT  102.659 36.666 103.199 37.89 ;
     RECT  102.623 58.194 103.199 58.248 ;
     RECT  102.659 64.944 103.199 65.232 ;
     RECT  102.623 67.68 103.199 67.698 ;
     RECT  102.875 70.146 103.199 70.362 ;
     RECT  102.623 77.904 103.199 78.768 ;
     RECT  102.623 81.378 103.199 81.396 ;
     RECT  102.767 84.15 103.199 85.788 ;
     RECT  101.898 87.048 103.199 87.066 ;
     RECT  102.623 87.858 103.199 88.452 ;
     RECT  102.659 89.478 103.199 89.874 ;
     RECT  103.199 37.368 103.235 37.386 ;
     RECT  102.623 56.61 103.235 57.204 ;
     RECT  103.199 65.214 103.235 65.232 ;
     RECT  101.898 76.59 103.235 76.608 ;
     RECT  103.199 84.15 103.235 84.942 ;
     RECT  103.199 89.55 103.235 89.568 ;
     RECT  103.199 26.874 103.271 26.892 ;
     RECT  103.199 27.684 103.271 27.702 ;
     RECT  103.199 58.194 103.271 58.212 ;
     RECT  103.199 78.174 103.271 78.192 ;
     RECT  103.235 84.186 103.271 84.942 ;
     RECT  103.271 84.186 103.307 84.438 ;
     RECT  103.307 84.42 103.343 84.438 ;
     RECT  102.875 49.626 103.883 49.644 ;
     RECT  103.819 46.701 103.927 46.719 ;
     RECT  103.927 46.62 103.955 46.719 ;
     RECT  102.695 47.898 103.955 48.564 ;
     RECT  102.911 73.116 103.955 73.134 ;
     RECT  103.891 22.896 103.963 22.914 ;
     RECT  103.963 22.824 103.991 22.914 ;
     RECT  103.199 28.458 103.991 29.016 ;
     RECT  102.047 45.846 103.991 45.864 ;
     RECT  102.731 50.976 103.991 50.994 ;
     RECT  103.235 57.186 103.991 57.204 ;
     RECT  102.911 73.89 103.991 73.908 ;
     RECT  103.963 20.466 104.063 20.484 ;
     RECT  103.991 22.824 104.063 22.842 ;
     RECT  103.991 28.998 104.063 29.016 ;
     RECT  103.963 30.15 104.063 30.168 ;
     RECT  103.963 31.392 104.063 31.41 ;
     RECT  103.963 38.106 104.063 38.124 ;
     RECT  103.955 46.62 104.063 46.638 ;
     RECT  103.955 47.898 104.063 47.916 ;
     RECT  103.927 55.026 104.063 55.044 ;
     RECT  103.891 71.424 104.063 71.442 ;
     RECT  103.963 78.912 104.063 78.93 ;
     RECT  103.963 86.931 104.063 86.949 ;
    LAYER M3 ;
     RECT  2.415 2.143 2.505 2.413 ;
     RECT  5.115 2.143 5.205 2.413 ;
     RECT  7.815 2.143 7.905 2.413 ;
     RECT  10.515 2.143 10.605 2.413 ;
     RECT  13.215 2.143 13.305 2.413 ;
     RECT  15.915 2.143 16.005 2.413 ;
     RECT  18.615 2.143 18.705 2.413 ;
     RECT  21.315 2.143 21.405 2.413 ;
     RECT  24.015 2.143 24.105 2.413 ;
     RECT  26.715 2.143 26.805 2.413 ;
     RECT  29.415 2.143 29.505 2.413 ;
     RECT  32.115 2.143 32.205 2.413 ;
     RECT  34.815 2.143 34.905 2.413 ;
     RECT  37.515 2.143 37.605 2.413 ;
     RECT  40.215 2.143 40.305 2.413 ;
     RECT  42.915 2.143 43.005 2.413 ;
     RECT  45.615 2.143 45.705 2.413 ;
     RECT  48.315 2.143 48.405 2.413 ;
     RECT  51.015 2.143 51.105 2.413 ;
     RECT  53.715 2.143 53.805 2.413 ;
     RECT  56.415 2.143 56.505 2.413 ;
     RECT  59.115 2.143 59.205 2.413 ;
     RECT  61.815 2.143 61.905 2.413 ;
     RECT  64.515 2.143 64.605 2.413 ;
     RECT  67.215 2.143 67.305 2.413 ;
     RECT  69.915 2.143 70.005 2.413 ;
     RECT  72.615 2.143 72.705 2.413 ;
     RECT  75.315 2.143 75.405 2.413 ;
     RECT  78.015 2.143 78.105 2.413 ;
     RECT  80.715 2.143 80.805 2.413 ;
     RECT  83.415 2.143 83.505 2.413 ;
     RECT  86.115 2.143 86.205 2.413 ;
     RECT  88.815 2.143 88.905 2.413 ;
     RECT  91.515 2.143 91.605 2.413 ;
     RECT  94.215 2.143 94.305 2.413 ;
     RECT  96.915 2.143 97.005 2.413 ;
     RECT  99.615 2.143 99.705 2.413 ;
     RECT  96.915 2.413 97.197 20.107 ;
     RECT  99.615 2.413 99.897 20.299 ;
     RECT  104.04 20.443 104.058 20.461 ;
     RECT  103.968 20.461 104.058 20.489 ;
     RECT  103.968 20.489 103.986 20.525 ;
     RECT  99.468 20.299 99.897 20.587 ;
     RECT  99.468 20.587 100.602 20.875 ;
     RECT  96.915 20.107 97.614 21.163 ;
     RECT  98.892 20.875 100.602 21.403 ;
     RECT  96.915 21.163 97.758 21.499 ;
     RECT  80.715 2.413 80.997 21.541 ;
     RECT  94.215 2.413 94.497 21.631 ;
     RECT  80.352 21.541 80.997 21.695 ;
     RECT  82.044 21.541 82.062 21.695 ;
     RECT  98.496 21.403 100.602 21.739 ;
     RECT  87.228 21.631 87.246 21.767 ;
     RECT  90.648 21.667 90.666 21.767 ;
     RECT  94.215 21.631 94.662 21.767 ;
     RECT  98.496 21.739 100.818 22.027 ;
     RECT  96.624 21.499 97.758 22.081 ;
     RECT  98.496 22.027 100.926 22.081 ;
     RECT  102.564 22.027 102.582 22.123 ;
     RECT  91.515 2.413 91.797 22.171 ;
     RECT  96.624 22.081 100.926 22.171 ;
     RECT  96.336 22.171 100.926 22.199 ;
     RECT  93.24 22.081 93.258 22.235 ;
     RECT  88.056 22.207 88.074 22.351 ;
     RECT  98.496 22.199 100.926 22.411 ;
     RECT  101.736 21.643 101.754 22.411 ;
     RECT  91.515 22.171 91.854 22.441 ;
     RECT  87.948 22.351 88.074 22.469 ;
     RECT  96.336 22.199 97.758 22.469 ;
     RECT  87.948 22.469 87.966 22.505 ;
     RECT  102.564 22.123 103.194 22.505 ;
     RECT  90.9 22.441 91.854 22.541 ;
     RECT  86.115 2.413 86.397 22.549 ;
     RECT  80.715 21.695 80.997 22.621 ;
     RECT  91.044 22.541 91.854 22.621 ;
     RECT  103.968 22.315 103.986 22.699 ;
     RECT  84.42 22.549 84.438 22.775 ;
     RECT  86.115 22.549 86.67 22.775 ;
     RECT  91.044 22.621 92.358 22.775 ;
     RECT  98.496 22.411 101.754 22.795 ;
     RECT  102.564 22.505 102.582 22.795 ;
     RECT  91.515 22.775 92.358 22.811 ;
     RECT  103.896 22.699 103.986 22.819 ;
     RECT  78.015 2.413 78.297 22.891 ;
     RECT  80.316 22.621 80.997 22.891 ;
     RECT  103.896 22.819 104.058 22.919 ;
     RECT  94.215 21.767 94.497 23.083 ;
     RECT  98.496 22.795 102.582 23.117 ;
     RECT  93.816 23.083 94.497 23.125 ;
     RECT  93.816 23.125 94.59 23.131 ;
     RECT  93.816 23.131 94.626 23.161 ;
     RECT  93.492 23.161 94.626 23.371 ;
     RECT  75.315 2.413 75.597 23.431 ;
     RECT  103.176 23.275 103.194 23.459 ;
     RECT  75.315 23.431 75.762 23.549 ;
     RECT  66.024 23.431 66.042 23.557 ;
     RECT  67.215 2.413 67.497 23.557 ;
     RECT  89.928 23.431 89.946 23.557 ;
     RECT  96.915 22.469 97.758 23.563 ;
     RECT  66.024 23.557 67.497 23.585 ;
     RECT  82.548 22.351 82.566 23.593 ;
     RECT  83.415 2.413 83.697 23.593 ;
     RECT  89.928 23.557 90.666 23.621 ;
     RECT  66.708 23.585 67.497 23.657 ;
     RECT  90.072 23.621 90.666 23.657 ;
     RECT  96.372 23.563 97.758 23.659 ;
     RECT  85.032 23.521 85.05 23.693 ;
     RECT  64.515 2.413 64.797 23.701 ;
     RECT  82.548 23.593 83.697 23.729 ;
     RECT  93.492 23.371 94.698 23.851 ;
     RECT  96.084 23.659 97.758 23.899 ;
     RECT  90.072 23.657 90.09 23.927 ;
     RECT  93.492 23.851 94.842 23.947 ;
     RECT  74.484 21.811 74.502 24.061 ;
     RECT  75.315 23.549 75.597 24.061 ;
     RECT  77.94 22.891 78.297 24.061 ;
     RECT  77.94 24.061 78.678 24.161 ;
     RECT  69.915 2.413 70.197 24.331 ;
     RECT  95.94 23.899 97.758 24.427 ;
     RECT  79.092 24.331 79.11 24.431 ;
     RECT  87.228 24.331 87.246 24.431 ;
     RECT  68.868 24.241 68.886 24.439 ;
     RECT  69.915 24.331 70.578 24.439 ;
     RECT  68.868 24.439 70.578 24.467 ;
     RECT  95.652 24.427 97.758 24.467 ;
     RECT  93.456 23.947 94.842 24.511 ;
     RECT  102.6 24.331 102.618 24.523 ;
     RECT  80.172 22.891 80.997 24.637 ;
     RECT  102.6 24.523 103.194 24.701 ;
     RECT  86.115 22.775 86.397 24.709 ;
     RECT  87.732 24.601 87.75 24.773 ;
     RECT  82.548 23.729 82.674 24.781 ;
     RECT  83.415 23.729 83.697 24.781 ;
     RECT  98.496 23.117 101.754 24.811 ;
     RECT  102.6 24.701 102.618 24.811 ;
     RECT  90.684 24.637 90.702 24.871 ;
     RECT  82.548 24.781 83.697 24.935 ;
     RECT  98.496 24.811 102.618 24.941 ;
     RECT  74.484 24.061 75.597 24.943 ;
     RECT  86.115 24.709 86.67 24.943 ;
     RECT  90.684 24.871 90.774 25.007 ;
     RECT  79.74 24.637 80.997 25.043 ;
     RECT  90.684 25.007 90.702 25.043 ;
     RECT  102.564 24.941 102.618 25.043 ;
     RECT  64.515 23.701 65.97 25.051 ;
     RECT  67.215 23.657 67.497 25.051 ;
     RECT  68.868 24.467 70.197 25.051 ;
     RECT  86.04 24.943 86.67 25.051 ;
     RECT  95.94 24.467 97.758 25.099 ;
     RECT  98.496 24.941 101.754 25.099 ;
     RECT  74.484 24.943 75.834 25.169 ;
     RECT  85.68 25.051 86.67 25.169 ;
     RECT  95.94 25.099 101.754 25.277 ;
     RECT  76.932 25.141 76.95 25.313 ;
     RECT  85.896 25.169 86.67 25.321 ;
     RECT  93.456 24.511 95.13 25.321 ;
     RECT  95.94 25.277 100.458 25.321 ;
     RECT  93.456 25.321 100.458 25.349 ;
     RECT  77.94 24.161 78.297 25.411 ;
     RECT  85.896 25.321 86.706 25.411 ;
     RECT  93.456 25.349 100.314 25.475 ;
     RECT  74.484 25.169 75.597 25.483 ;
     RECT  77.94 25.411 78.678 25.511 ;
     RECT  73.872 25.483 75.597 25.583 ;
     RECT  85.896 25.411 87.426 25.583 ;
     RECT  68.292 25.051 70.197 25.591 ;
     RECT  82.548 24.935 82.674 25.681 ;
     RECT  83.415 24.935 83.697 25.681 ;
     RECT  79.308 25.555 79.326 25.709 ;
     RECT  93.456 25.475 94.914 25.757 ;
     RECT  87.516 25.591 87.534 25.817 ;
     RECT  102.564 25.043 102.582 25.817 ;
     RECT  85.896 25.583 86.706 25.853 ;
     RECT  71.568 24.781 71.586 25.861 ;
     RECT  76.896 25.717 76.914 25.951 ;
     RECT  93.456 25.757 94.842 25.951 ;
     RECT  76.824 25.951 76.914 25.979 ;
     RECT  87.588 25.861 87.606 25.979 ;
     RECT  80.172 25.043 80.997 25.987 ;
     RECT  85.896 25.853 86.397 26.015 ;
     RECT  76.824 25.979 76.842 26.051 ;
     RECT  90 26.059 90.018 26.107 ;
     RECT  79.488 25.987 80.997 26.123 ;
     RECT  64.515 25.051 67.497 26.131 ;
     RECT  68.292 25.591 70.254 26.131 ;
     RECT  82.548 25.681 83.697 26.221 ;
     RECT  90 26.107 90.234 26.251 ;
     RECT  95.94 25.475 100.314 26.251 ;
     RECT  95.94 26.251 100.386 26.299 ;
     RECT  101.196 25.277 101.754 26.299 ;
     RECT  89.928 26.251 90.234 26.347 ;
     RECT  91.515 22.811 91.797 26.365 ;
     RECT  88.815 2.413 89.097 26.491 ;
     RECT  73.944 25.583 74.502 26.591 ;
     RECT  89.928 26.347 90.702 26.635 ;
     RECT  91.515 26.365 92.322 26.635 ;
     RECT  95.94 26.299 101.754 26.765 ;
     RECT  103.14 26.797 103.158 26.827 ;
     RECT  77.94 25.511 78.297 26.869 ;
     RECT  103.14 26.827 103.194 26.869 ;
     RECT  103.968 22.919 104.058 26.869 ;
     RECT  51.015 2.413 51.297 26.941 ;
     RECT  75.315 25.583 75.597 26.941 ;
     RECT  82.548 26.221 83.79 26.941 ;
     RECT  75.315 26.941 76.05 27.031 ;
     RECT  76.968 26.941 76.986 27.031 ;
     RECT  86.115 26.015 86.397 27.031 ;
     RECT  75.315 27.031 76.986 27.059 ;
     RECT  50.688 26.941 51.297 27.067 ;
     RECT  61.815 2.413 62.097 27.067 ;
     RECT  47.124 26.941 47.142 27.095 ;
     RECT  49.968 27.067 51.297 27.095 ;
     RECT  103.14 26.869 104.058 27.115 ;
     RECT  76.68 27.059 76.986 27.131 ;
     RECT  49.968 27.095 50.022 27.139 ;
     RECT  93.096 25.951 94.842 27.139 ;
     RECT  63.72 27.139 63.738 27.175 ;
     RECT  48.315 2.413 48.597 27.211 ;
     RECT  49.932 27.139 50.022 27.211 ;
     RECT  76.968 27.131 76.986 27.211 ;
     RECT  101.196 26.765 101.754 27.211 ;
     RECT  102.564 27.115 104.058 27.245 ;
     RECT  70.992 25.861 71.586 27.301 ;
     RECT  72.615 2.413 72.897 27.301 ;
     RECT  89.928 26.635 92.322 27.301 ;
     RECT  93.096 27.139 94.986 27.301 ;
     RECT  61.596 27.067 62.097 27.329 ;
     RECT  63.252 27.175 63.738 27.337 ;
     RECT  64.515 26.131 70.254 27.337 ;
     RECT  75.315 27.059 75.798 27.365 ;
     RECT  76.968 27.211 77.202 27.365 ;
     RECT  63.18 27.337 70.254 27.389 ;
     RECT  64.515 27.389 70.254 27.481 ;
     RECT  70.992 27.301 72.897 27.481 ;
     RECT  80.172 26.123 80.997 27.481 ;
     RECT  82.332 26.941 83.79 27.481 ;
     RECT  101.196 27.211 101.79 27.481 ;
     RECT  77.94 26.869 78.678 27.643 ;
     RECT  77.508 27.643 78.678 27.679 ;
     RECT  80.172 27.481 83.79 27.679 ;
     RECT  84.708 23.791 84.726 27.679 ;
     RECT  79.776 27.679 83.79 27.707 ;
     RECT  103.176 27.245 104.058 27.707 ;
     RECT  101.196 27.481 101.826 27.743 ;
     RECT  103.176 27.707 103.194 27.743 ;
     RECT  101.196 27.743 101.79 27.779 ;
     RECT  53.715 2.413 53.997 27.841 ;
     RECT  80.715 27.707 83.79 27.905 ;
     RECT  84.708 27.679 84.978 27.905 ;
     RECT  53.136 27.841 53.997 27.913 ;
     RECT  95.94 26.765 100.314 27.931 ;
     RECT  86.115 27.031 86.742 27.941 ;
     RECT  61.815 27.329 62.097 28.111 ;
     RECT  64.515 27.481 72.897 28.175 ;
     RECT  84.816 27.905 84.978 28.183 ;
     RECT  86.115 27.941 86.397 28.183 ;
     RECT  77.508 27.679 78.75 28.219 ;
     RECT  61.815 28.111 62.766 28.247 ;
     RECT  52.992 27.913 53.997 28.255 ;
     RECT  49.68 27.211 50.022 28.291 ;
     RECT  51.015 27.095 51.297 28.291 ;
     RECT  77.256 28.219 78.75 28.291 ;
     RECT  79.776 27.707 79.794 28.291 ;
     RECT  89.928 27.301 94.986 28.291 ;
     RECT  61.815 28.247 62.73 28.319 ;
     RECT  47.88 27.211 48.597 28.381 ;
     RECT  46.908 27.211 46.926 28.445 ;
     RECT  49.464 28.291 50.022 28.453 ;
     RECT  95.94 27.931 100.674 28.453 ;
     RECT  77.256 28.291 79.794 28.481 ;
     RECT  103.968 27.707 104.058 28.481 ;
     RECT  89.928 28.291 95.022 28.507 ;
     RECT  95.868 28.453 100.674 28.507 ;
     RECT  52.992 28.255 54.594 28.561 ;
     RECT  89.928 28.507 100.674 28.715 ;
     RECT  101.448 27.779 101.79 28.715 ;
     RECT  75.315 27.365 75.597 28.759 ;
     RECT  84.816 28.183 86.397 28.759 ;
     RECT  52.992 28.561 54.702 28.831 ;
     RECT  88.488 26.491 89.097 28.831 ;
     RECT  77.256 28.481 78.786 28.949 ;
     RECT  75.315 28.759 75.978 28.957 ;
     RECT  104.04 28.481 104.058 29.021 ;
     RECT  73.944 26.591 74.07 29.029 ;
     RECT  64.515 28.175 70.254 29.057 ;
     RECT  103.176 28.747 103.194 29.057 ;
     RECT  64.515 29.057 67.497 29.101 ;
     RECT  87.984 28.831 89.097 29.227 ;
     RECT  49.464 28.453 50.094 29.255 ;
     RECT  52.92 28.831 55.026 29.255 ;
     RECT  64.404 29.101 67.497 29.255 ;
     RECT  70.992 28.175 72.897 29.255 ;
     RECT  61.815 28.319 62.097 29.263 ;
     RECT  68.292 29.057 70.254 29.263 ;
     RECT  70.992 29.255 71.586 29.263 ;
     RECT  87.948 29.227 89.097 29.275 ;
     RECT  64.512 29.255 67.497 29.291 ;
     RECT  75.315 28.957 76.302 29.299 ;
     RECT  77.256 28.949 78.678 29.299 ;
     RECT  75.315 29.299 78.678 29.327 ;
     RECT  61.488 29.263 62.766 29.363 ;
     RECT  65.736 29.291 67.497 29.363 ;
     RECT  68.292 29.263 71.586 29.363 ;
     RECT  47.772 28.381 48.597 29.371 ;
     RECT  51.015 28.291 51.966 29.371 ;
     RECT  47.016 28.561 47.034 29.525 ;
     RECT  73.728 29.029 74.07 29.533 ;
     RECT  75.315 29.327 78.297 29.533 ;
     RECT  80.715 27.905 80.997 29.533 ;
     RECT  84.816 28.759 86.814 29.533 ;
     RECT  82.332 27.905 83.79 29.569 ;
     RECT  84.816 29.533 86.85 29.569 ;
     RECT  73.728 29.533 78.297 29.633 ;
     RECT  79.632 28.481 79.794 29.633 ;
     RECT  45.615 2.413 45.897 29.641 ;
     RECT  47.772 29.371 49.122 29.795 ;
     RECT  87.732 29.275 89.097 29.899 ;
     RECT  53.388 29.255 55.026 29.911 ;
     RECT  64.512 29.291 64.89 30.001 ;
     RECT  53.388 29.911 55.134 30.065 ;
     RECT  72.615 29.255 72.897 30.073 ;
     RECT  75.315 29.633 78.297 30.073 ;
     RECT  82.332 29.569 86.85 30.073 ;
     RECT  87.732 29.899 89.19 30.139 ;
     RECT  90 28.715 100.674 30.139 ;
     RECT  80.715 29.533 81.27 30.145 ;
     RECT  104.04 30.136 104.058 30.145 ;
     RECT  103.968 30.145 104.058 30.173 ;
     RECT  50.832 29.371 51.966 30.181 ;
     RECT  75.315 30.073 78.75 30.209 ;
     RECT  103.968 30.173 103.986 30.221 ;
     RECT  79.776 29.633 79.794 30.271 ;
     RECT  80.676 30.145 81.27 30.271 ;
     RECT  79.776 30.271 81.27 30.541 ;
     RECT  53.532 30.065 55.134 30.605 ;
     RECT  61.488 29.363 62.097 30.605 ;
     RECT  66.672 29.363 67.497 30.605 ;
     RECT  82.332 30.073 86.994 30.619 ;
     RECT  87.732 30.139 100.674 30.619 ;
     RECT  70.992 29.363 71.586 30.649 ;
     RECT  72.324 30.073 72.897 30.649 ;
     RECT  50.832 30.181 52.578 30.721 ;
     RECT  63.972 30.001 64.89 30.721 ;
     RECT  82.332 30.619 100.674 30.749 ;
     RECT  70.992 30.649 72.897 30.811 ;
     RECT  73.728 29.633 74.07 30.811 ;
     RECT  75.315 30.209 78.297 30.811 ;
     RECT  47.988 29.795 49.122 30.847 ;
     RECT  68.292 29.363 70.254 30.883 ;
     RECT  70.992 30.811 78.297 30.883 ;
     RECT  50.796 30.721 52.578 30.955 ;
     RECT  45.615 29.641 46.926 30.991 ;
     RECT  47.988 30.847 49.554 30.991 ;
     RECT  50.4 30.955 52.578 30.991 ;
     RECT  53.532 30.605 54.882 30.991 ;
     RECT  59.115 2.413 59.397 30.991 ;
     RECT  68.292 30.883 78.297 31.019 ;
     RECT  70.992 31.019 78.297 31.181 ;
     RECT  45.615 30.991 49.554 31.189 ;
     RECT  45.615 31.189 49.59 31.225 ;
     RECT  50.4 30.991 54.882 31.225 ;
     RECT  101.448 28.715 101.718 31.261 ;
     RECT  45.504 31.225 54.882 31.325 ;
     RECT  103.968 31.339 103.986 31.387 ;
     RECT  82.332 30.749 82.638 31.415 ;
     RECT  103.968 31.387 104.058 31.415 ;
     RECT  72.216 31.181 78.297 31.423 ;
     RECT  79.092 30.541 81.27 31.423 ;
     RECT  104.04 31.415 104.058 31.424 ;
     RECT  61.596 30.605 62.097 31.495 ;
     RECT  61.596 31.495 62.514 31.531 ;
     RECT  72.216 31.423 81.27 31.621 ;
     RECT  83.415 30.749 100.674 31.685 ;
     RECT  61.056 31.531 62.514 31.693 ;
     RECT  65.736 29.363 65.754 31.693 ;
     RECT  72.216 31.621 81.378 31.693 ;
     RECT  82.44 31.415 82.638 31.729 ;
     RECT  61.056 31.693 62.73 31.765 ;
     RECT  63.756 30.721 64.89 31.765 ;
     RECT  65.736 31.693 65.934 31.801 ;
     RECT  66.708 30.605 67.497 31.801 ;
     RECT  82.44 31.729 82.674 31.801 ;
     RECT  83.415 31.685 84.366 31.801 ;
     RECT  45.615 31.325 54.882 31.891 ;
     RECT  85.284 31.685 100.674 31.891 ;
     RECT  101.448 31.261 101.754 31.891 ;
     RECT  61.056 31.765 64.89 31.919 ;
     RECT  65.736 31.801 67.497 31.955 ;
     RECT  70.992 31.181 71.406 32.035 ;
     RECT  72.216 31.693 81.414 32.035 ;
     RECT  70.992 32.035 81.414 32.071 ;
     RECT  70.992 32.071 81.666 32.161 ;
     RECT  82.44 31.801 84.366 32.161 ;
     RECT  57.816 32.035 57.834 32.233 ;
     RECT  68.292 31.019 70.197 32.261 ;
     RECT  103.176 32.011 103.194 32.297 ;
     RECT  63.432 31.919 64.89 32.299 ;
     RECT  68.328 32.261 70.197 32.299 ;
     RECT  68.328 32.299 70.254 32.341 ;
     RECT  70.992 32.161 84.366 32.341 ;
     RECT  61.056 31.919 62.514 32.495 ;
     RECT  85.284 31.891 101.754 32.495 ;
     RECT  68.328 32.341 84.366 32.575 ;
     RECT  45.615 31.891 55.026 32.737 ;
     RECT  68.328 32.575 84.546 32.765 ;
     RECT  86.076 32.495 101.754 32.765 ;
     RECT  68.328 32.765 84.474 32.909 ;
     RECT  68.328 32.909 84.438 32.999 ;
     RECT  66.6 31.955 67.497 33.007 ;
     RECT  68.328 32.999 84.222 33.007 ;
     RECT  66.6 33.007 84.222 33.035 ;
     RECT  45.432 32.737 55.026 33.043 ;
     RECT  61.596 32.495 62.514 33.349 ;
     RECT  85.284 32.495 85.302 33.349 ;
     RECT  86.076 32.765 95.994 33.349 ;
     RECT  96.732 32.765 101.754 33.385 ;
     RECT  102.6 33.067 102.618 33.385 ;
     RECT  58.86 30.991 59.397 33.575 ;
     RECT  45.432 33.043 55.134 33.583 ;
     RECT  85.284 33.349 95.994 33.655 ;
     RECT  96.732 33.385 102.618 33.655 ;
     RECT  57.528 32.233 57.834 33.691 ;
     RECT  66.6 33.035 84.186 33.817 ;
     RECT  66.6 33.817 84.51 33.853 ;
     RECT  85.284 33.655 102.618 33.853 ;
     RECT  45.432 33.583 55.17 33.961 ;
     RECT  45.324 33.961 55.17 34.075 ;
     RECT  45.18 34.075 55.17 34.115 ;
     RECT  66.6 33.853 102.618 34.115 ;
     RECT  56.415 2.413 56.697 34.159 ;
     RECT  57.528 33.691 58.374 34.159 ;
     RECT  65.736 31.955 65.754 34.501 ;
     RECT  98.604 34.115 102.618 34.541 ;
     RECT  102.6 34.541 102.618 34.603 ;
     RECT  61.488 33.349 62.514 34.699 ;
     RECT  63.432 32.299 64.926 34.699 ;
     RECT  56.415 34.159 58.374 34.771 ;
     RECT  59.115 33.575 59.397 34.771 ;
     RECT  61.488 34.699 64.926 34.771 ;
     RECT  65.736 34.501 65.862 34.771 ;
     RECT  66.6 34.115 97.83 34.861 ;
     RECT  45.216 34.115 55.17 34.933 ;
     RECT  66.6 34.861 97.866 34.933 ;
     RECT  98.604 34.541 101.754 34.933 ;
     RECT  66.6 34.933 101.754 34.961 ;
     RECT  61.488 34.771 65.862 34.987 ;
     RECT  66.6 34.961 101.682 34.987 ;
     RECT  45.18 34.933 55.17 35.005 ;
     RECT  45.18 35.005 55.278 35.041 ;
     RECT  61.488 34.987 101.682 35.041 ;
     RECT  45.108 35.041 55.566 35.159 ;
     RECT  45.108 35.159 55.278 35.311 ;
     RECT  102.6 34.603 102.798 35.371 ;
     RECT  60.48 35.041 101.682 35.609 ;
     RECT  60.48 35.609 98.694 35.699 ;
     RECT  99.576 35.609 101.682 35.699 ;
     RECT  60.48 35.699 98.622 35.779 ;
     RECT  56.415 34.771 59.397 35.843 ;
     RECT  60.444 35.779 98.622 35.843 ;
     RECT  58.248 35.843 59.397 35.941 ;
     RECT  60.444 35.843 98.55 35.941 ;
     RECT  44.928 35.311 55.278 36.043 ;
     RECT  44.568 36.043 55.278 36.083 ;
     RECT  99.615 35.699 101.682 36.149 ;
     RECT  44.928 36.083 55.278 36.173 ;
     RECT  101.124 36.149 101.682 36.247 ;
     RECT  58.248 35.941 98.55 36.365 ;
     RECT  98.028 36.365 98.55 36.661 ;
     RECT  58.248 36.365 97.197 36.815 ;
     RECT  98.028 36.661 98.622 36.907 ;
     RECT  45.108 36.173 55.278 36.931 ;
     RECT  98.028 36.907 98.838 36.931 ;
     RECT  99.615 36.149 100.35 36.931 ;
     RECT  101.124 36.247 101.718 36.959 ;
     RECT  45.072 36.931 55.278 37.021 ;
     RECT  99.615 36.931 100.386 37.049 ;
     RECT  98.028 36.931 98.874 37.051 ;
     RECT  99.615 37.049 100.242 37.051 ;
     RECT  98.028 37.051 100.242 37.085 ;
     RECT  101.16 36.959 101.718 37.165 ;
     RECT  102.6 35.371 103.23 37.165 ;
     RECT  45.072 37.021 55.494 37.201 ;
     RECT  101.16 37.165 103.23 37.229 ;
     RECT  96.915 36.815 97.197 37.291 ;
     RECT  98.028 37.085 99.99 37.291 ;
     RECT  96.915 37.291 99.99 37.319 ;
     RECT  44.82 37.201 55.494 37.387 ;
     RECT  56.415 35.843 57.294 37.387 ;
     RECT  103.176 37.229 103.23 37.391 ;
     RECT  101.16 37.229 102.042 37.427 ;
     RECT  44.82 37.387 57.294 37.429 ;
     RECT  58.248 36.815 96.102 37.429 ;
     RECT  98.532 37.319 99.99 37.499 ;
     RECT  98.568 37.499 99.99 37.517 ;
     RECT  42.915 2.413 43.197 37.705 ;
     RECT  96.915 37.319 97.506 37.769 ;
     RECT  44.82 37.429 96.102 37.831 ;
     RECT  103.176 37.391 103.194 37.895 ;
     RECT  98.568 37.517 99.897 37.967 ;
     RECT  103.968 38.059 103.986 38.101 ;
     RECT  103.968 38.101 104.058 38.129 ;
     RECT  104.04 38.129 104.058 38.141 ;
     RECT  101.16 37.427 101.538 38.201 ;
     RECT  101.16 38.201 101.322 38.471 ;
     RECT  98.856 37.967 99.897 39.515 ;
     RECT  42.915 37.705 43.29 39.523 ;
     RECT  42.768 39.523 43.29 39.631 ;
     RECT  99.612 39.515 99.897 39.659 ;
     RECT  101.304 38.471 101.322 39.785 ;
     RECT  42.732 39.631 43.29 40.171 ;
     RECT  44.208 37.831 96.102 40.199 ;
     RECT  42.732 40.171 43.434 40.441 ;
     RECT  44.208 40.199 95.166 40.441 ;
     RECT  98.856 39.515 98.874 41.675 ;
     RECT  98.568 41.791 98.586 42.187 ;
     RECT  96.012 40.199 96.102 42.215 ;
     RECT  42.732 40.441 95.166 42.317 ;
     RECT  96.084 42.215 96.102 42.359 ;
     RECT  42.732 42.317 44.334 42.485 ;
     RECT  40.215 2.413 40.497 42.691 ;
     RECT  99.615 39.659 99.897 42.955 ;
     RECT  96.915 37.769 97.197 43.141 ;
     RECT  96.915 43.141 97.29 43.303 ;
     RECT  99.615 42.955 100.314 43.339 ;
     RECT  101.196 39.865 101.214 43.339 ;
     RECT  103.968 42.667 103.986 43.339 ;
     RECT  99.615 43.339 101.214 43.627 ;
     RECT  102.024 43.531 102.042 43.627 ;
     RECT  42.876 42.485 44.334 43.681 ;
     RECT  45.072 42.317 95.166 43.681 ;
     RECT  98.316 42.187 98.586 43.771 ;
     RECT  42.876 43.681 95.166 43.835 ;
     RECT  98.316 43.771 98.622 43.901 ;
     RECT  99.615 43.627 102.042 44.011 ;
     RECT  95.256 43.951 95.274 44.069 ;
     RECT  99.615 44.011 102.618 44.107 ;
     RECT  99.615 44.107 102.726 44.203 ;
     RECT  42.876 43.835 94.497 44.213 ;
     RECT  42.084 43.681 42.102 44.221 ;
     RECT  42.876 44.213 44.01 44.221 ;
     RECT  99.615 44.203 102.834 44.299 ;
     RECT  45 44.213 94.497 44.447 ;
     RECT  99.615 44.299 102.942 44.477 ;
     RECT  103.932 43.339 103.986 44.683 ;
     RECT  95.58 44.761 95.598 44.879 ;
     RECT  96.915 43.303 97.506 45.019 ;
     RECT  98.316 43.901 98.514 45.019 ;
     RECT  96.915 45.019 98.766 45.121 ;
     RECT  45.18 44.447 94.497 45.301 ;
     RECT  45.18 45.301 95.022 45.419 ;
     RECT  42.084 44.221 44.01 45.661 ;
     RECT  45.18 45.419 94.497 45.661 ;
     RECT  96.876 45.121 98.766 45.805 ;
     RECT  99.615 44.477 102.042 45.805 ;
     RECT  96.876 45.805 102.042 45.821 ;
     RECT  40.215 42.691 41.022 45.841 ;
     RECT  42.084 45.661 94.497 45.841 ;
     RECT  103.824 44.683 103.986 45.869 ;
     RECT  96.876 45.821 100.206 45.931 ;
     RECT  96.768 45.931 100.206 46.171 ;
     RECT  101.052 45.821 102.042 46.411 ;
     RECT  102.852 45.643 102.87 46.411 ;
     RECT  103.824 45.869 103.95 46.615 ;
     RECT  101.052 46.411 102.87 46.645 ;
     RECT  103.824 46.615 104.058 46.732 ;
     RECT  40.215 45.841 94.497 46.741 ;
     RECT  96.372 46.171 100.206 46.795 ;
     RECT  100.98 46.645 102.87 46.795 ;
     RECT  96.372 46.795 102.87 47.083 ;
     RECT  96.3 47.083 102.87 47.119 ;
     RECT  40.215 46.741 94.554 47.191 ;
     RECT  40.215 47.191 94.734 47.317 ;
     RECT  96.048 47.119 102.87 47.317 ;
     RECT  38.736 43.051 38.754 47.353 ;
     RECT  95.94 47.317 102.87 47.357 ;
     RECT  40.032 47.317 94.734 47.389 ;
     RECT  38.736 47.353 38.826 47.453 ;
     RECT  38.736 47.453 38.79 47.461 ;
     RECT  2.415 2.413 2.697 47.848 ;
     RECT  2.415 47.848 3.294 47.857 ;
     RECT  2.415 47.857 4.086 47.893 ;
     RECT  26.715 2.413 26.997 47.899 ;
     RECT  103.86 46.732 104.058 47.921 ;
     RECT  2.415 47.893 4.23 47.947 ;
     RECT  5.115 2.413 5.397 47.992 ;
     RECT  13.215 2.413 13.497 47.992 ;
     RECT  21.315 2.413 21.597 47.992 ;
     RECT  2.304 47.947 4.23 48.001 ;
     RECT  5.004 47.992 5.397 48.001 ;
     RECT  6.84 47.899 6.858 48.029 ;
     RECT  13.104 47.992 13.497 48.029 ;
     RECT  14.832 47.899 14.85 48.029 ;
     RECT  21.204 47.992 21.597 48.029 ;
     RECT  22.824 47.899 22.842 48.029 ;
     RECT  26.676 47.899 26.997 48.029 ;
     RECT  30.672 47.899 30.798 48.029 ;
     RECT  38.592 47.461 38.79 48.029 ;
     RECT  2.268 48.001 5.397 48.077 ;
     RECT  0.54 47.425 0.558 48.173 ;
     RECT  2.304 48.077 5.397 48.227 ;
     RECT  96.3 47.357 102.87 48.331 ;
     RECT  103.86 47.921 103.986 48.331 ;
     RECT  2.415 48.227 5.397 48.389 ;
     RECT  2.415 48.389 3.438 48.425 ;
     RECT  96.3 48.331 103.986 48.461 ;
     RECT  0.108 48.397 0.126 48.557 ;
     RECT  39.744 47.389 94.734 48.661 ;
     RECT  4.644 48.389 5.397 48.731 ;
     RECT  39.744 48.661 95.418 48.811 ;
     RECT  96.3 48.461 102.87 48.811 ;
     RECT  3.42 48.425 3.438 48.839 ;
     RECT  4.716 48.731 5.397 48.839 ;
     RECT  37.515 2.413 37.797 48.901 ;
     RECT  39.744 48.811 102.87 49.009 ;
     RECT  37.476 48.901 37.797 49.291 ;
     RECT  39.636 49.009 102.87 49.325 ;
     RECT  39.636 49.325 84.222 49.441 ;
     RECT  37.044 49.291 37.797 49.531 ;
     RECT  38.592 48.029 38.61 49.531 ;
     RECT  39.348 49.441 84.222 49.531 ;
     RECT  36.72 49.531 37.797 49.565 ;
     RECT  103.86 48.461 103.986 49.649 ;
     RECT  36.72 49.565 36.738 49.891 ;
     RECT  36.576 49.891 36.738 49.949 ;
     RECT  84.96 49.325 102.87 50.189 ;
     RECT  37.476 49.565 37.797 50.251 ;
     RECT  37.476 50.251 37.854 50.287 ;
     RECT  38.592 49.531 84.222 50.287 ;
     RECT  37.476 50.287 84.222 50.347 ;
     RECT  84.96 50.189 102.726 50.347 ;
     RECT  37.476 50.347 102.726 50.431 ;
     RECT  37.188 50.431 102.726 50.459 ;
     RECT  103.968 49.649 103.986 50.999 ;
     RECT  34.815 2.413 35.097 51.241 ;
     RECT  37.188 50.459 102.294 51.307 ;
     RECT  37.188 51.307 102.474 51.403 ;
     RECT  34.524 51.241 35.097 51.511 ;
     RECT  37.188 51.403 102.582 51.581 ;
     RECT  34.452 51.511 35.478 51.746 ;
     RECT  36.432 52.285 36.45 52.321 ;
     RECT  37.188 51.581 101.898 52.321 ;
     RECT  36.432 52.321 101.898 52.459 ;
     RECT  36.432 52.459 102.042 53.035 ;
     RECT  36.432 53.035 102.114 53.165 ;
     RECT  36.432 53.165 101.754 53.321 ;
     RECT  36.432 53.321 100.098 53.597 ;
     RECT  36.432 53.597 99.99 53.627 ;
     RECT  84.708 53.627 99.99 53.897 ;
     RECT  84.78 53.897 99.99 53.969 ;
     RECT  84.852 53.969 99.99 53.981 ;
     RECT  100.872 53.321 101.754 54.031 ;
     RECT  34.452 51.746 35.442 54.139 ;
     RECT  32.115 2.413 32.397 54.211 ;
     RECT  100.872 54.031 101.79 54.211 ;
     RECT  100.872 54.211 101.934 54.301 ;
     RECT  84.924 53.981 99.99 54.329 ;
     RECT  31.176 53.293 31.194 54.481 ;
     RECT  32.115 54.211 33.102 54.481 ;
     RECT  31.176 54.481 33.102 54.509 ;
     RECT  84.96 54.329 99.99 54.571 ;
     RECT  100.872 54.301 101.97 54.571 ;
     RECT  34.452 54.139 35.658 54.751 ;
     RECT  36.432 53.627 83.934 54.751 ;
     RECT  84.96 54.571 101.97 54.763 ;
     RECT  84.96 54.763 102.582 54.859 ;
     RECT  103.968 53.803 103.986 55.003 ;
     RECT  103.968 55.003 104.058 55.021 ;
     RECT  103.932 55.021 104.058 55.049 ;
     RECT  103.932 55.049 103.986 55.085 ;
     RECT  34.452 54.751 83.934 55.219 ;
     RECT  84.96 54.859 102.87 55.243 ;
     RECT  31.176 54.509 32.397 55.381 ;
     RECT  33.624 55.291 33.642 55.381 ;
     RECT  31.176 55.381 33.642 55.589 ;
     RECT  34.452 55.219 84.006 55.627 ;
     RECT  84.852 55.243 102.87 55.627 ;
     RECT  34.452 55.627 102.87 56.107 ;
     RECT  33.624 55.589 33.642 56.263 ;
     RECT  34.452 56.107 103.194 56.263 ;
     RECT  33.624 56.263 103.194 56.395 ;
     RECT  103.968 55.085 103.986 56.395 ;
     RECT  31.176 55.589 32.397 56.569 ;
     RECT  33.624 56.395 103.986 56.569 ;
     RECT  31.176 56.569 103.986 56.731 ;
     RECT  30.528 56.731 103.986 56.903 ;
     RECT  29.415 2.413 29.697 56.911 ;
     RECT  30.528 56.903 59.49 56.911 ;
     RECT  29.415 56.911 59.49 56.939 ;
     RECT  60.264 56.903 103.986 57.209 ;
     RECT  60.264 57.209 103.266 57.677 ;
     RECT  33.624 56.939 59.49 57.685 ;
     RECT  60.264 57.677 102.042 57.685 ;
     RECT  33.624 57.685 102.042 57.721 ;
     RECT  33.48 57.721 102.042 57.749 ;
     RECT  33.48 57.749 101.97 57.947 ;
     RECT  29.415 56.939 32.634 58.081 ;
     RECT  33.48 57.947 100.062 58.081 ;
     RECT  29.415 58.081 100.062 58.109 ;
     RECT  29.415 58.109 99.954 58.145 ;
     RECT  102.852 57.677 103.266 58.217 ;
     RECT  102.852 58.217 103.194 58.253 ;
     RECT  100.8 57.947 101.97 58.415 ;
     RECT  29.415 58.145 99.897 58.523 ;
     RECT  102.852 58.253 102.87 59.063 ;
     RECT  29.415 58.523 32.397 59.275 ;
     RECT  33.228 58.523 99.897 59.275 ;
     RECT  29.415 59.275 99.897 59.467 ;
     RECT  100.8 58.415 101.934 59.467 ;
     RECT  29.415 59.467 101.934 59.773 ;
     RECT  29.376 59.773 101.934 60.043 ;
     RECT  28.656 60.043 101.934 60.413 ;
     RECT  28.656 60.413 101.898 62.195 ;
     RECT  31.14 62.195 101.898 62.501 ;
     RECT  102.78 62.443 102.798 62.539 ;
     RECT  102.456 62.539 102.798 62.861 ;
     RECT  102.564 62.861 102.798 62.923 ;
     RECT  102.564 62.923 103.194 63.019 ;
     RECT  28.656 62.195 30.33 63.121 ;
     RECT  28.404 63.121 30.33 63.481 ;
     RECT  31.14 62.501 101.718 63.481 ;
     RECT  102.564 63.019 103.23 63.689 ;
     RECT  28.404 63.481 101.718 63.883 ;
     RECT  28.404 63.883 101.79 64.355 ;
     RECT  26.715 48.029 26.997 64.669 ;
     RECT  103.176 63.689 103.23 64.843 ;
     RECT  102.6 64.843 103.23 65.237 ;
     RECT  26.715 64.669 27.378 65.785 ;
     RECT  28.476 64.355 101.79 65.785 ;
     RECT  26.715 65.785 101.79 65.821 ;
     RECT  102.6 65.237 102.726 65.885 ;
     RECT  102.6 65.885 102.654 66.667 ;
     RECT  26.715 65.821 101.826 66.763 ;
     RECT  102.6 66.667 103.194 66.763 ;
     RECT  26.715 66.763 103.194 69.061 ;
     RECT  26.28 69.061 103.194 70.025 ;
     RECT  25.452 69.871 25.47 70.141 ;
     RECT  26.28 70.025 98.658 70.141 ;
     RECT  103.932 69.547 103.95 70.507 ;
     RECT  25.452 70.141 98.658 70.951 ;
     RECT  99.468 70.025 103.194 71.105 ;
     RECT  99.504 71.105 103.194 71.117 ;
     RECT  25.452 70.951 98.694 71.141 ;
     RECT  103.932 70.507 103.986 71.371 ;
     RECT  103.896 71.371 103.986 71.419 ;
     RECT  103.896 71.419 104.058 71.447 ;
     RECT  103.932 71.447 104.058 71.456 ;
     RECT  25.452 71.141 98.586 71.899 ;
     RECT  99.504 71.117 102.906 71.899 ;
     RECT  103.932 71.456 103.986 73.139 ;
     RECT  25.452 71.899 102.906 73.409 ;
     RECT  103.968 73.139 103.986 73.913 ;
     RECT  25.452 73.409 102.654 73.921 ;
     RECT  25.2 73.921 102.654 74.417 ;
     RECT  102.528 74.417 102.654 74.489 ;
     RECT  25.2 74.417 101.79 74.651 ;
     RECT  102.636 74.489 102.654 74.957 ;
     RECT  25.2 74.651 101.754 77.153 ;
     RECT  103.212 76.585 103.23 77.515 ;
     RECT  103.176 77.515 103.23 77.803 ;
     RECT  25.2 77.153 101.646 78.043 ;
     RECT  25.2 78.043 101.682 78.089 ;
     RECT  102.6 77.803 103.23 78.169 ;
     RECT  102.6 78.169 103.266 78.221 ;
     RECT  25.2 78.089 101.646 78.233 ;
     RECT  25.2 78.233 101.466 78.665 ;
     RECT  102.6 78.221 103.194 78.763 ;
     RECT  103.968 78.859 103.986 78.907 ;
     RECT  103.968 78.907 104.058 78.935 ;
     RECT  104.04 78.935 104.058 78.944 ;
     RECT  102.564 78.763 103.194 78.989 ;
     RECT  102.564 78.989 102.618 79.003 ;
     RECT  102.492 79.003 102.618 79.469 ;
     RECT  102.492 79.469 102.582 79.627 ;
     RECT  102.456 79.627 102.582 79.757 ;
     RECT  102.528 79.757 102.582 80.203 ;
     RECT  102.528 80.203 103.194 80.491 ;
     RECT  102.492 80.491 103.194 80.635 ;
     RECT  25.2 78.665 101.358 80.671 ;
     RECT  102.096 80.635 103.194 80.671 ;
     RECT  25.2 80.671 103.194 80.861 ;
     RECT  100.836 80.861 103.194 81.401 ;
     RECT  100.836 81.401 102.654 81.581 ;
     RECT  25.2 80.861 99.99 82.021 ;
     RECT  102.636 81.581 102.654 82.283 ;
     RECT  25.2 82.021 100.026 82.291 ;
     RECT  100.836 81.581 101.682 82.291 ;
     RECT  25.2 82.291 101.682 83.065 ;
     RECT  102.6 82.939 102.618 83.065 ;
     RECT  25.2 83.065 102.618 83.213 ;
     RECT  102.6 83.213 102.618 83.275 ;
     RECT  102.6 83.275 102.762 83.851 ;
     RECT  102.6 83.851 103.194 83.947 ;
     RECT  25.2 83.213 101.754 84.029 ;
     RECT  102.6 83.947 103.23 84.043 ;
     RECT  99.468 84.029 101.754 84.065 ;
     RECT  98.1 84.029 98.622 84.101 ;
     RECT  98.604 84.101 98.622 84.335 ;
     RECT  102.6 84.043 103.302 84.415 ;
     RECT  102.6 84.415 103.338 84.749 ;
     RECT  102.6 84.749 103.266 84.845 ;
     RECT  99.615 84.065 101.754 84.875 ;
     RECT  102.672 84.845 103.266 84.941 ;
     RECT  103.176 84.941 103.266 85.325 ;
     RECT  99.615 84.875 100.314 85.459 ;
     RECT  101.232 84.875 101.718 85.487 ;
     RECT  25.2 84.029 97.326 85.675 ;
     RECT  25.2 85.675 98.046 85.723 ;
     RECT  99 85.459 100.314 85.723 ;
     RECT  103.176 85.325 103.194 85.793 ;
     RECT  25.2 85.723 100.314 86.333 ;
     RECT  103.968 86.92 103.986 86.926 ;
     RECT  103.968 86.926 104.058 86.957 ;
     RECT  104.04 86.957 104.058 87.005 ;
     RECT  98.028 86.333 100.314 87.115 ;
     RECT  101.232 85.487 101.682 87.115 ;
     RECT  98.028 87.115 101.682 87.269 ;
     RECT  100.836 87.269 101.682 87.305 ;
     RECT  103.176 86.635 103.194 87.355 ;
     RECT  25.2 86.333 97.197 87.385 ;
     RECT  98.028 87.269 100.026 87.385 ;
     RECT  102.564 87.355 103.194 87.499 ;
     RECT  101.232 87.305 101.682 88.075 ;
     RECT  102.456 87.499 103.194 88.075 ;
     RECT  25.2 87.385 100.026 88.267 ;
     RECT  25.2 88.267 100.314 88.363 ;
     RECT  101.232 88.075 103.194 88.363 ;
     RECT  25.2 88.363 103.194 88.457 ;
     RECT  25.2 88.457 102.654 88.493 ;
     RECT  102.456 88.493 102.654 88.685 ;
     RECT  25.2 88.493 101.466 88.799 ;
     RECT  25.2 88.799 99.897 88.925 ;
     RECT  102.564 88.685 102.654 89.227 ;
     RECT  100.692 88.799 101.466 89.231 ;
     RECT  102.564 89.227 103.194 89.419 ;
     RECT  102.564 89.419 103.23 89.515 ;
     RECT  102.528 89.515 103.23 89.573 ;
     RECT  100.692 89.231 101.034 89.741 ;
     RECT  25.2 88.925 98.55 89.779 ;
     RECT  99.432 88.925 99.897 89.779 ;
     RECT  102.528 89.573 103.194 89.843 ;
     RECT  103.176 89.843 103.194 89.879 ;
     RECT  25.2 89.779 99.954 89.969 ;
     RECT  100.692 89.741 100.818 89.969 ;
     RECT  100.692 89.969 100.71 90.005 ;
     RECT  99.432 89.969 99.954 90.029 ;
     RECT  99.432 90.029 99.897 90.041 ;
     RECT  99.576 90.041 99.897 90.383 ;
     RECT  25.2 89.969 98.55 90.689 ;
     RECT  25.2 90.689 98.082 90.887 ;
     RECT  25.2 90.887 98.01 91.319 ;
     RECT  97.992 91.319 98.01 92.705 ;
     RECT  25.2 91.319 97.197 99.023 ;
     RECT  90.396 99.023 97.197 100.265 ;
     RECT  93.384 100.265 97.197 100.607 ;
     RECT  90.396 100.265 92.466 100.679 ;
     RECT  25.2 99.023 89.658 100.877 ;
     RECT  93.384 100.607 96.138 100.913 ;
     RECT  93.744 100.913 96.138 101.219 ;
     RECT  25.2 100.877 89.55 101.417 ;
     RECT  25.2 101.417 89.097 101.489 ;
     RECT  25.2 101.489 86.742 101.615 ;
     RECT  90.432 100.679 92.466 101.651 ;
     RECT  25.2 101.615 86.67 101.741 ;
     RECT  25.2 101.741 84.402 101.821 ;
     RECT  95.472 101.219 96.138 101.885 ;
     RECT  85.356 101.741 86.67 101.957 ;
     RECT  25.164 101.821 84.402 102.155 ;
     RECT  85.5 101.957 86.67 102.221 ;
     RECT  90.432 101.651 90.45 102.221 ;
     RECT  85.5 102.221 86.634 102.299 ;
     RECT  87.588 101.489 89.097 102.497 ;
     RECT  25.2 102.155 84.402 102.731 ;
     RECT  87.768 102.497 89.097 102.803 ;
     RECT  91.515 101.651 92.466 103.037 ;
     RECT  93.744 101.219 94.497 103.073 ;
     RECT  25.2 102.731 84.15 103.109 ;
     RECT  93.852 103.073 94.497 103.109 ;
     RECT  2.415 48.425 2.697 103.157 ;
     RECT  5.115 48.839 5.397 103.157 ;
     RECT  7.815 2.413 8.097 103.157 ;
     RECT  10.515 2.413 10.797 103.157 ;
     RECT  13.215 48.029 13.497 103.157 ;
     RECT  15.915 2.413 16.197 103.157 ;
     RECT  18.615 2.413 18.897 103.157 ;
     RECT  21.315 48.029 21.597 103.157 ;
     RECT  24.015 2.413 24.297 103.157 ;
     RECT  88.815 102.803 89.097 103.157 ;
     RECT  91.515 103.037 91.797 103.157 ;
     RECT  94.215 103.109 94.497 103.157 ;
     RECT  96.915 100.607 97.197 103.157 ;
     RECT  99.615 90.383 99.897 103.157 ;
     RECT  25.2 103.109 33.966 103.171 ;
     RECT  34.704 103.109 84.15 103.199 ;
     RECT  25.056 103.171 33.966 103.229 ;
     RECT  34.704 103.199 44.91 103.229 ;
     RECT  45.807 103.199 84.15 103.229 ;
     RECT  34.776 103.229 44.91 103.235 ;
     RECT  96.048 101.885 96.138 103.271 ;
     RECT  34.776 103.235 44.658 103.307 ;
     RECT  25.236 103.229 33.966 103.373 ;
     RECT  55.476 103.229 84.15 103.373 ;
     RECT  34.776 103.307 44.478 103.393 ;
     RECT  2.607 103.157 2.697 103.427 ;
     RECT  5.307 103.157 5.397 103.427 ;
     RECT  8.007 103.157 8.097 103.427 ;
     RECT  10.707 103.157 10.797 103.427 ;
     RECT  13.407 103.157 13.497 103.427 ;
     RECT  16.107 103.157 16.197 103.427 ;
     RECT  18.807 103.157 18.897 103.427 ;
     RECT  21.507 103.157 21.597 103.427 ;
     RECT  24.207 103.157 24.297 103.427 ;
     RECT  35.007 103.393 44.478 103.427 ;
     RECT  45.807 103.229 54.594 103.427 ;
     RECT  55.584 103.373 84.15 103.427 ;
     RECT  85.752 102.299 86.397 103.427 ;
     RECT  89.007 103.157 89.097 103.427 ;
     RECT  91.707 103.157 91.797 103.427 ;
     RECT  94.407 103.157 94.497 103.427 ;
     RECT  97.107 103.157 97.197 103.427 ;
     RECT  99.807 103.157 99.897 103.427 ;
     RECT  45.936 103.427 54.594 103.469 ;
     RECT  57.06 103.427 82.998 103.469 ;
     RECT  87.768 102.803 87.93 103.505 ;
     RECT  57.06 103.469 79.794 103.517 ;
     RECT  25.236 103.373 31.086 103.541 ;
     RECT  31.896 103.373 33.966 103.541 ;
     RECT  35.28 103.427 39.69 103.541 ;
     RECT  80.604 103.469 82.998 103.541 ;
     RECT  80.604 103.541 82.638 103.565 ;
     RECT  35.28 103.541 39.33 103.577 ;
     RECT  41.112 103.427 44.478 103.577 ;
     RECT  46.296 103.469 54.594 103.577 ;
     RECT  87.912 103.505 87.93 103.577 ;
     RECT  57.06 103.517 62.262 103.613 ;
     RECT  63.252 103.517 79.794 103.613 ;
     RECT  80.64 103.565 82.638 103.613 ;
     RECT  84.132 103.427 84.15 103.613 ;
     RECT  55.584 103.427 56.286 103.649 ;
     RECT  96.12 103.271 96.138 103.649 ;
     RECT  35.316 103.577 39.33 103.661 ;
     RECT  46.296 103.577 54.486 103.661 ;
     RECT  57.06 103.613 57.33 103.661 ;
     RECT  68.868 103.613 79.794 103.661 ;
     RECT  80.64 103.613 81.846 103.661 ;
     RECT  57.06 103.661 57.294 103.694 ;
     RECT  79.776 103.661 79.794 103.694 ;
     RECT  80.64 103.661 81.378 103.694 ;
     RECT  85.752 103.427 85.77 103.694 ;
     RECT  35.496 103.661 39.33 103.709 ;
     RECT  58.176 103.613 62.262 103.709 ;
     RECT  68.868 103.661 79.038 103.709 ;
     RECT  80.892 103.694 81.378 103.709 ;
     RECT  35.604 103.709 39.33 103.739 ;
     RECT  82.62 103.613 82.638 103.739 ;
     RECT  26.856 103.541 31.086 103.757 ;
     RECT  31.896 103.541 33.606 103.757 ;
     RECT  46.296 103.661 54.126 103.757 ;
     RECT  57.276 103.694 57.294 103.757 ;
     RECT  58.176 103.709 61.794 103.757 ;
     RECT  68.868 103.709 76.014 103.757 ;
     RECT  76.752 103.709 79.038 103.757 ;
     RECT  80.892 103.709 81.054 103.757 ;
     RECT  35.604 103.739 39.114 103.805 ;
     RECT  72.252 103.757 72.414 103.805 ;
     RECT  75.636 103.757 76.014 103.805 ;
     RECT  80.892 103.757 80.91 103.805 ;
     RECT  78.336 103.757 78.57 104.189 ;
     RECT  26.856 103.757 29.394 104.285 ;
     RECT  33.12 103.757 33.138 104.285 ;
     RECT  36.324 103.805 39.114 104.285 ;
     RECT  58.176 103.757 60.138 104.285 ;
     RECT  61.236 103.757 61.794 104.285 ;
     RECT  68.868 103.757 71.046 104.285 ;
     RECT  73.836 103.757 74.862 104.285 ;
     RECT  78.372 104.189 78.57 104.285 ;
     RECT  58.968 104.285 60.138 104.333 ;
     RECT  72.252 103.805 72.27 104.333 ;
     RECT  74.304 104.285 74.862 104.333 ;
     RECT  58.176 104.285 58.194 104.861 ;
     RECT  58.968 104.333 59.67 104.861 ;
     RECT  68.868 104.285 70.074 104.861 ;
     RECT  75.996 103.805 76.014 104.861 ;
     RECT  31.896 103.757 32.274 104.863 ;
     RECT  26.856 104.285 29.322 104.891 ;
     RECT  68.868 104.861 69.678 104.891 ;
     RECT  30.456 103.757 30.87 104.909 ;
     RECT  69.444 104.891 69.678 104.909 ;
     RECT  70.956 104.285 71.046 104.909 ;
     RECT  74.52 104.333 74.862 104.909 ;
     RECT  25.236 103.541 25.974 104.957 ;
     RECT  71.028 104.909 71.046 104.957 ;
     RECT  80.136 105.403 80.154 105.451 ;
     RECT  46.296 103.757 53.586 105.499 ;
     RECT  79.92 105.451 80.154 105.499 ;
     RECT  63.252 103.613 67.806 105.511 ;
     RECT  46.296 105.499 54.234 105.629 ;
     RECT  69.444 104.909 69.498 105.629 ;
     RECT  79.92 105.499 80.298 105.629 ;
     RECT  46.368 105.629 53.586 105.665 ;
     RECT  25.236 104.957 25.65 105.677 ;
     RECT  41.112 103.577 43.83 105.701 ;
     RECT  46.368 105.665 53.55 105.701 ;
     RECT  25.632 105.677 25.65 105.725 ;
     RECT  31.788 104.863 32.274 105.725 ;
     RECT  55.584 103.649 55.602 105.725 ;
     RECT  56.916 105.499 56.934 105.725 ;
     RECT  58.968 104.861 58.986 105.725 ;
     RECT  61.236 104.285 61.254 105.725 ;
     RECT  69.48 105.629 69.498 105.725 ;
     RECT  76.752 103.757 77.202 105.725 ;
     RECT  78.408 104.285 78.426 105.725 ;
     RECT  79.992 105.629 80.298 105.725 ;
     RECT  36.72 104.285 39.114 105.773 ;
     RECT  41.112 105.701 43.794 105.773 ;
     RECT  46.476 105.701 53.406 105.773 ;
     RECT  63.252 105.511 67.878 105.773 ;
     RECT  26.964 104.891 29.214 105.804 ;
     RECT  36.756 105.773 39.006 105.804 ;
     RECT  41.364 105.773 43.614 105.804 ;
     RECT  46.548 105.773 53.406 105.804 ;
     RECT  63.252 105.773 67.806 105.804 ;
    LAYER M4 ;
     RECT  0.06 47.76 0.137 48.552 ;
     RECT  0.137 47.76 0.227 48.456 ;
     RECT  0.227 47.856 0.371 48.456 ;
     RECT  0.371 47.952 2.408 48.456 ;
     RECT  0.325 64.656 2.408 64.68 ;
     RECT  0.181 75.984 2.408 76.008 ;
     RECT  2.408 2.148 2.512 103.152 ;
     RECT  2.512 2.418 2.6 103.152 ;
     RECT  2.6 2.418 2.704 103.422 ;
     RECT  2.704 47.856 2.765 48.264 ;
     RECT  2.765 47.856 5.108 48.024 ;
     RECT  2.704 64.656 5.108 64.68 ;
     RECT  2.704 75.984 5.108 76.008 ;
     RECT  5.108 2.148 5.212 103.152 ;
     RECT  5.212 2.418 5.3 103.152 ;
     RECT  5.3 2.418 5.404 103.422 ;
     RECT  5.404 47.856 7.808 48.024 ;
     RECT  5.404 64.656 7.808 64.68 ;
     RECT  5.404 75.984 7.808 76.008 ;
     RECT  7.808 2.148 7.912 103.152 ;
     RECT  7.912 2.418 8 103.152 ;
     RECT  8 2.418 8.104 103.422 ;
     RECT  8.104 47.856 10.508 47.928 ;
     RECT  8.104 64.656 10.508 64.68 ;
     RECT  8.104 75.984 10.508 76.008 ;
     RECT  10.508 2.148 10.612 103.152 ;
     RECT  10.612 2.418 10.7 103.152 ;
     RECT  10.7 2.418 10.804 103.422 ;
     RECT  10.804 47.856 13.208 48.024 ;
     RECT  10.804 64.656 13.208 64.68 ;
     RECT  10.804 75.984 13.208 76.008 ;
     RECT  13.208 2.148 13.312 103.152 ;
     RECT  13.312 2.418 13.4 103.152 ;
     RECT  13.4 2.418 13.504 103.422 ;
     RECT  13.504 47.856 14.861 48.024 ;
     RECT  14.861 47.856 15.908 47.928 ;
     RECT  13.504 64.656 15.908 64.68 ;
     RECT  13.504 75.984 15.908 76.008 ;
     RECT  15.908 2.148 16.012 103.152 ;
     RECT  16.012 2.418 16.1 103.152 ;
     RECT  16.1 2.418 16.204 103.422 ;
     RECT  16.204 47.856 18.608 47.928 ;
     RECT  16.204 64.656 18.608 64.68 ;
     RECT  16.204 75.984 18.608 76.008 ;
     RECT  18.608 2.148 18.712 103.152 ;
     RECT  18.712 2.418 18.8 103.152 ;
     RECT  18.8 2.418 18.904 103.422 ;
     RECT  18.904 47.856 21.308 48.024 ;
     RECT  18.904 64.656 21.308 64.68 ;
     RECT  18.904 75.984 21.308 76.008 ;
     RECT  21.308 2.148 21.412 103.152 ;
     RECT  21.412 2.418 21.5 103.152 ;
     RECT  21.5 2.418 21.604 103.422 ;
     RECT  21.604 47.856 22.853 48.024 ;
     RECT  22.853 47.856 24.008 47.928 ;
     RECT  21.604 64.656 24.008 64.68 ;
     RECT  21.604 75.984 24.008 76.008 ;
     RECT  24.008 2.148 24.112 103.152 ;
     RECT  24.112 2.418 24.2 103.152 ;
     RECT  24.2 2.418 24.304 103.422 ;
     RECT  24.304 103.2 25.369 103.224 ;
     RECT  25.369 102.624 25.477 103.224 ;
     RECT  25.477 102.432 25.513 103.224 ;
     RECT  25.225 105.648 25.621 105.672 ;
     RECT  25.621 105.648 25.945 105.72 ;
     RECT  24.304 47.856 26.708 47.928 ;
     RECT  24.304 64.656 26.708 64.68 ;
     RECT  24.304 75.984 26.708 76.008 ;
     RECT  25.945 100.224 26.708 100.248 ;
     RECT  25.513 101.616 26.708 103.224 ;
     RECT  26.708 2.148 26.812 103.224 ;
     RECT  26.812 2.418 26.9 103.224 ;
     RECT  26.9 2.418 27.004 103.422 ;
     RECT  25.945 104.928 27.421 105.72 ;
     RECT  27.004 98.016 27.637 103.422 ;
     RECT  27.637 98.016 27.923 103.752 ;
     RECT  27.923 98.064 28.069 103.752 ;
     RECT  27.421 104.88 28.069 105.72 ;
     RECT  28.069 98.064 28.253 105.72 ;
     RECT  28.253 104.88 28.307 105.72 ;
     RECT  27.004 75.984 29.113 76.008 ;
     RECT  28.307 104.88 29.171 105.672 ;
     RECT  29.249 72.384 29.269 72.408 ;
     RECT  28.253 98.064 29.317 103.752 ;
     RECT  29.317 98.064 29.405 104.28 ;
     RECT  27.004 47.856 29.408 47.928 ;
     RECT  28.717 61.008 29.408 61.032 ;
     RECT  28.933 62.16 29.408 62.184 ;
     RECT  28.393 63.264 29.408 63.288 ;
     RECT  27.004 64.656 29.408 64.68 ;
     RECT  28.501 66.288 29.408 66.312 ;
     RECT  29.401 67.584 29.408 67.608 ;
     RECT  29.269 71.664 29.408 72.408 ;
     RECT  29.113 75.216 29.408 76.008 ;
     RECT  29.405 98.064 29.408 103.752 ;
     RECT  29.408 2.148 29.512 103.752 ;
     RECT  29.171 105.6 29.555 105.672 ;
     RECT  29.555 105.6 29.651 105.624 ;
     RECT  29.512 2.418 29.704 103.752 ;
     RECT  29.704 59.76 29.765 59.88 ;
     RECT  29.704 69.456 29.843 69.768 ;
     RECT  29.704 78.48 29.843 78.744 ;
     RECT  29.704 62.16 29.981 62.184 ;
     RECT  29.704 98.352 29.981 103.752 ;
     RECT  29.704 63.264 30.017 65.304 ;
     RECT  29.704 71.28 30.089 71.688 ;
     RECT  29.704 73.104 30.377 74.088 ;
     RECT  29.843 78.48 30.521 78.648 ;
     RECT  30.521 78.624 30.557 78.648 ;
     RECT  29.704 75.216 30.629 77.496 ;
     RECT  30.629 75.504 30.701 76.488 ;
     RECT  30.017 64.656 30.733 65.304 ;
     RECT  29.704 66.288 30.733 66.312 ;
     RECT  30.428 104.88 30.757 104.904 ;
     RECT  30.733 64.656 30.769 66.312 ;
     RECT  29.704 67.296 30.769 68.28 ;
     RECT  29.981 98.352 30.773 103.704 ;
     RECT  29.704 47.856 30.809 48.024 ;
     RECT  29.704 80.592 30.845 82.536 ;
     RECT  30.845 81.36 30.877 82.536 ;
     RECT  30.701 75.504 30.881 76.44 ;
     RECT  30.773 98.352 30.899 101.448 ;
     RECT  30.757 104.88 30.899 105.624 ;
     RECT  30.629 77.472 30.913 77.496 ;
     RECT  30.881 75.888 30.947 76.44 ;
     RECT  30.899 105.6 30.947 105.624 ;
     RECT  29.843 69.456 30.949 69.48 ;
     RECT  30.947 75.984 30.988 76.44 ;
     RECT  30.913 80.352 31.025 80.376 ;
     RECT  30.899 98.352 31.045 101.352 ;
     RECT  30.949 69.456 31.057 70.056 ;
     RECT  30.773 102.576 31.057 103.704 ;
     RECT  30.877 81.36 31.093 82.632 ;
     RECT  30.017 63.264 31.129 63.624 ;
     RECT  31.057 69.456 31.309 70.104 ;
     RECT  30.089 71.28 31.309 71.304 ;
     RECT  31.129 62.832 31.345 63.624 ;
     RECT  31.309 69.456 31.381 71.304 ;
     RECT  29.765 59.76 31.489 59.784 ;
     RECT  31.489 59.76 31.561 60.408 ;
     RECT  31.381 69.456 31.633 72.264 ;
     RECT  31.345 62.64 31.885 63.624 ;
     RECT  30.769 64.656 31.885 68.28 ;
     RECT  30.377 73.536 31.909 74.088 ;
     RECT  30.988 75.984 31.909 76.344 ;
     RECT  31.045 97.92 31.916 101.352 ;
     RECT  31.057 102.576 31.916 103.752 ;
     RECT  31.633 69.264 31.957 72.264 ;
     RECT  31.909 73.536 31.957 76.344 ;
     RECT  31.525 105.696 31.957 105.72 ;
     RECT  31.921 79.44 31.993 79.464 ;
     RECT  30.809 47.856 32.108 47.928 ;
     RECT  31.561 59.28 32.108 60.408 ;
     RECT  30.805 61.584 32.108 61.608 ;
     RECT  31.885 62.64 32.108 68.28 ;
     RECT  31.957 69.264 32.108 76.344 ;
     RECT  30.913 77.472 32.108 77.592 ;
     RECT  31.993 78.72 32.108 79.464 ;
     RECT  31.093 81.36 32.108 82.68 ;
     RECT  31.916 97.92 32.108 103.752 ;
     RECT  32.108 2.148 32.212 103.752 ;
     RECT  31.957 105.648 32.243 105.72 ;
     RECT  32.243 105.696 32.285 105.72 ;
     RECT  32.212 2.418 32.404 103.752 ;
     RECT  32.404 59.28 32.573 61.128 ;
     RECT  32.404 102.72 32.573 103.752 ;
     RECT  32.404 62.688 32.579 64.68 ;
     RECT  32.404 71.808 32.861 73.656 ;
     RECT  32.404 74.64 33.059 79.464 ;
     RECT  32.573 102.768 33.061 103.752 ;
     RECT  32.573 59.424 33.107 61.128 ;
     RECT  32.404 65.76 33.113 67.752 ;
     RECT  32.404 68.976 33.113 70.104 ;
     RECT  33.059 75.84 33.12 79.464 ;
     RECT  33.061 102.768 33.149 104.28 ;
     RECT  32.404 98.736 33.157 101.496 ;
     RECT  33.107 60.624 33.221 61.128 ;
     RECT  32.579 62.688 33.257 63.528 ;
     RECT  33.12 77.28 33.581 79.464 ;
     RECT  32.404 57.84 33.589 57.864 ;
     RECT  33.107 59.424 33.589 59.448 ;
     RECT  33.149 102.768 33.617 103.752 ;
     RECT  33.589 57.84 33.635 59.448 ;
     RECT  32.579 64.656 33.721 64.68 ;
     RECT  33.113 65.76 33.721 66.168 ;
     RECT  32.404 80.88 33.725 84.072 ;
     RECT  32.861 71.808 33.829 73.32 ;
     RECT  33.581 78.624 33.865 79.464 ;
     RECT  33.829 71.232 34.021 73.32 ;
     RECT  33.157 98.736 34.021 101.4 ;
     RECT  33.865 78.624 34.045 79.8 ;
     RECT  33.725 80.88 34.045 82.488 ;
     RECT  33.059 74.64 34.153 74.76 ;
     RECT  33.12 75.84 34.153 76.008 ;
     RECT  33.257 62.784 34.172 63.528 ;
     RECT  33.721 64.656 34.172 66.168 ;
     RECT  34.021 71.232 34.333 73.416 ;
     RECT  34.172 62.784 34.477 66.168 ;
     RECT  33.113 67.344 34.477 67.752 ;
     RECT  33.581 77.28 34.693 77.352 ;
     RECT  34.045 78.624 34.693 82.488 ;
     RECT  33.617 102.768 34.789 103.368 ;
     RECT  32.404 47.856 34.808 47.928 ;
     RECT  32.404 51.936 34.808 51.96 ;
     RECT  33.635 57.84 34.808 58.68 ;
     RECT  33.221 60.624 34.808 60.936 ;
     RECT  34.477 62.784 34.808 67.752 ;
     RECT  33.113 69.264 34.808 70.104 ;
     RECT  34.333 71.232 34.808 73.512 ;
     RECT  34.153 74.64 34.808 76.008 ;
     RECT  34.693 77.28 34.808 77.4 ;
     RECT  34.693 78.624 34.808 82.824 ;
     RECT  33.725 84.048 34.808 84.072 ;
     RECT  34.021 98.592 34.808 101.4 ;
     RECT  34.789 102.768 34.808 103.752 ;
     RECT  34.808 2.148 34.912 103.752 ;
     RECT  34.981 105.456 35.077 105.48 ;
     RECT  34.912 2.418 35.104 103.752 ;
     RECT  35.077 105.36 35.173 105.48 ;
     RECT  35.173 105.36 35.219 105.672 ;
     RECT  35.219 105.456 35.267 105.672 ;
     RECT  35.104 71.952 35.345 73.32 ;
     RECT  35.267 105.648 35.363 105.672 ;
     RECT  35.104 58.992 35.489 60.696 ;
     RECT  35.104 67.632 35.489 70.824 ;
     RECT  35.104 75.168 35.489 80.952 ;
     RECT  35.104 98.592 35.593 103.752 ;
     RECT  35.104 82.224 35.597 82.488 ;
     RECT  35.489 75.168 35.699 79.848 ;
     RECT  35.489 58.992 35.705 60.648 ;
     RECT  35.699 75.168 35.741 79.416 ;
     RECT  35.705 59.04 35.813 60.648 ;
     RECT  35.104 86.352 35.891 86.76 ;
     RECT  35.593 98.592 35.941 103.8 ;
     RECT  35.489 67.632 36.085 68.376 ;
     RECT  35.104 64.656 36.131 65.64 ;
     RECT  35.489 69.744 36.209 70.824 ;
     RECT  36.085 66.912 36.227 68.376 ;
     RECT  35.597 82.224 36.245 82.248 ;
     RECT  35.104 51.936 36.277 51.96 ;
     RECT  35.941 98.592 36.353 104.28 ;
     RECT  36.313 66.624 36.425 66.648 ;
     RECT  36.353 98.592 36.497 103.752 ;
     RECT  35.104 84.048 36.565 85.32 ;
     RECT  36.524 49.92 36.661 49.944 ;
     RECT  36.565 83.76 36.668 85.32 ;
     RECT  35.104 57.84 36.709 57.864 ;
     RECT  36.209 70.8 36.709 70.824 ;
     RECT  35.345 71.952 36.709 73.128 ;
     RECT  36.277 51.936 36.745 52.776 ;
     RECT  35.104 54.144 36.745 54.168 ;
     RECT  36.497 98.592 36.745 103.32 ;
     RECT  35.104 63.216 36.757 63.528 ;
     RECT  36.131 64.656 36.757 64.968 ;
     RECT  35.489 80.928 36.757 80.952 ;
     RECT  35.813 59.856 36.781 60.648 ;
     RECT  36.757 80.88 36.805 80.952 ;
     RECT  36.745 51.936 36.889 54.168 ;
     RECT  35.104 55.776 36.889 55.992 ;
     RECT  36.227 67.632 36.925 68.376 ;
     RECT  36.209 69.744 36.925 69.816 ;
     RECT  36.668 83.136 36.997 85.32 ;
     RECT  35.891 86.352 36.997 86.664 ;
     RECT  36.661 49.536 37.033 49.944 ;
     RECT  36.709 70.8 37.033 73.128 ;
     RECT  36.889 51.936 37.213 55.992 ;
     RECT  36.925 67.632 37.357 69.816 ;
     RECT  36.169 74.64 37.381 74.664 ;
     RECT  35.741 75.888 37.381 79.416 ;
     RECT  36.709 57.6 37.393 57.864 ;
     RECT  36.781 58.944 37.393 60.648 ;
     RECT  37.177 105.744 37.397 105.768 ;
     RECT  35.104 47.856 37.508 47.928 ;
     RECT  37.033 49.296 37.508 49.944 ;
     RECT  37.213 51.936 37.508 56.376 ;
     RECT  37.393 57.6 37.508 60.648 ;
     RECT  37.033 61.68 37.508 61.704 ;
     RECT  36.757 63.216 37.508 64.968 ;
     RECT  37.357 66.864 37.508 69.816 ;
     RECT  37.033 70.8 37.508 73.368 ;
     RECT  37.381 74.64 37.508 79.416 ;
     RECT  36.805 80.88 37.508 81.192 ;
     RECT  36.997 83.136 37.508 86.664 ;
     RECT  37.393 87.648 37.508 87.672 ;
     RECT  36.745 98.352 37.508 103.32 ;
     RECT  37.508 2.148 37.612 103.32 ;
     RECT  37.612 2.418 37.7 103.32 ;
     RECT  37.7 2.418 37.804 103.422 ;
     RECT  37.804 87.648 37.901 87.816 ;
     RECT  37.804 83.76 37.937 84.648 ;
     RECT  37.804 98.352 37.937 103.032 ;
     RECT  37.804 55.536 38.003 61.224 ;
     RECT  37.804 72 38.009 73.368 ;
     RECT  37.897 105.696 38.045 105.72 ;
     RECT  37.804 90.288 38.195 91.176 ;
     RECT  38.003 55.536 38.333 58.68 ;
     RECT  37.804 66.24 38.477 67.656 ;
     RECT  37.937 83.76 38.549 84.36 ;
     RECT  38.195 90.288 38.549 90.552 ;
     RECT  37.804 68.928 38.773 70.44 ;
     RECT  38.009 72 38.773 73.032 ;
     RECT  37.804 47.904 38.801 48.024 ;
     RECT  37.804 74.976 38.801 75 ;
     RECT  38.003 59.856 38.821 61.224 ;
     RECT  37.804 62.688 38.821 63.096 ;
     RECT  37.804 79.44 38.909 82.776 ;
     RECT  37.937 98.592 38.981 103.032 ;
     RECT  37.804 92.64 39.017 92.664 ;
     RECT  37.804 50.736 39.049 54.168 ;
     RECT  38.333 55.536 39.053 58.152 ;
     RECT  38.821 59.856 39.061 63.096 ;
     RECT  38.909 79.44 39.121 81.672 ;
     RECT  39.121 78.912 39.157 81.672 ;
     RECT  37.901 87.792 39.161 87.816 ;
     RECT  39.061 59.808 39.301 63.096 ;
     RECT  38.477 67.248 39.301 67.656 ;
     RECT  38.477 66.24 39.445 66.264 ;
     RECT  39.301 67.248 39.445 67.8 ;
     RECT  37.804 49.296 39.493 49.56 ;
     RECT  39.049 50.736 39.493 54.216 ;
     RECT  39.445 66.24 39.541 67.8 ;
     RECT  39.493 49.296 39.553 54.216 ;
     RECT  37.804 75.984 39.589 77.352 ;
     RECT  39.301 59.808 39.596 63.672 ;
     RECT  39.553 49.296 39.661 54.36 ;
     RECT  38.549 84.048 39.661 84.36 ;
     RECT  39.589 75.984 39.685 77.544 ;
     RECT  39.661 92.88 39.685 93.048 ;
     RECT  39.596 59.616 39.733 63.672 ;
     RECT  38.909 82.752 39.769 82.776 ;
     RECT  39.661 83.808 39.769 84.36 ;
     RECT  38.977 88.896 39.769 88.92 ;
     RECT  39.661 49.296 39.841 54.408 ;
     RECT  38.801 47.904 39.949 47.928 ;
     RECT  39.829 74.4 39.949 74.424 ;
     RECT  39.769 88.896 39.949 89.544 ;
     RECT  39.589 91.152 39.949 91.176 ;
     RECT  38.981 98.592 39.983 98.616 ;
     RECT  38.981 99.744 39.983 103.032 ;
     RECT  39.841 49.296 40.093 54.456 ;
     RECT  39.053 55.536 40.093 57.864 ;
     RECT  39.733 59.568 40.093 63.672 ;
     RECT  39.685 92.88 40.093 93.768 ;
     RECT  37.804 43.056 40.208 43.08 ;
     RECT  39.949 47.856 40.208 47.928 ;
     RECT  40.093 49.296 40.208 57.864 ;
     RECT  40.093 59.28 40.208 63.672 ;
     RECT  37.804 64.656 40.208 64.968 ;
     RECT  39.541 66.096 40.208 67.8 ;
     RECT  38.773 68.928 40.208 73.032 ;
     RECT  39.949 74.304 40.208 74.424 ;
     RECT  39.685 75.984 40.208 77.688 ;
     RECT  39.157 78.672 40.208 81.672 ;
     RECT  39.769 82.752 40.208 84.36 ;
     RECT  37.804 85.728 40.208 86.664 ;
     RECT  39.949 88.896 40.208 91.176 ;
     RECT  40.093 92.88 40.208 94.056 ;
     RECT  39.983 98.592 40.208 103.032 ;
     RECT  40.208 2.148 40.312 103.152 ;
     RECT  40.312 2.418 40.4 103.152 ;
     RECT  40.4 2.418 40.504 103.422 ;
     RECT  40.504 98.88 40.565 103.224 ;
     RECT  40.504 46.272 40.637 55.56 ;
     RECT  40.565 100.8 40.643 103.224 ;
     RECT  40.637 54.192 40.673 55.56 ;
     RECT  40.504 59.184 40.681 64.968 ;
     RECT  40.681 59.184 40.709 63.576 ;
     RECT  40.504 69.456 40.709 69.528 ;
     RECT  40.504 93.024 40.817 95.208 ;
     RECT  40.643 100.8 40.817 102.792 ;
     RECT  40.504 96.912 40.853 96.936 ;
     RECT  40.673 54.192 40.889 54.84 ;
     RECT  40.504 75.984 40.925 86.904 ;
     RECT  40.925 77.328 41.033 86.904 ;
     RECT  40.817 94.656 41.075 95.208 ;
     RECT  40.889 54.384 41.105 54.84 ;
     RECT  40.504 88.368 41.105 91.8 ;
     RECT  41.075 95.088 41.105 95.208 ;
     RECT  40.637 46.272 41.123 52.776 ;
     RECT  41.123 47.04 41.141 52.776 ;
     RECT  41.105 54.672 41.141 54.84 ;
     RECT  40.709 59.184 41.177 63.192 ;
     RECT  41.105 90.336 41.177 91.752 ;
     RECT  40.817 101.088 41.285 102.792 ;
     RECT  40.681 64.656 41.468 64.968 ;
     RECT  41.177 59.184 41.501 61.896 ;
     RECT  41.177 63.072 41.501 63.192 ;
     RECT  40.925 75.984 41.501 76.344 ;
     RECT  41.033 82.608 41.507 86.904 ;
     RECT  40.709 69.504 41.533 69.528 ;
     RECT  41.468 64.656 41.555 65.928 ;
     RECT  40.504 67.056 41.555 68.376 ;
     RECT  40.817 93.024 41.557 93.384 ;
     RECT  41.533 69.504 41.564 69.816 ;
     RECT  40.504 70.8 41.564 74.952 ;
     RECT  41.285 101.088 41.573 101.448 ;
     RECT  41.564 69.504 41.651 74.952 ;
     RECT  41.033 77.328 41.717 81.48 ;
     RECT  41.105 88.368 41.717 89.16 ;
     RECT  40.504 56.592 41.749 58.104 ;
     RECT  41.717 77.328 41.789 79.272 ;
     RECT  41.651 71.088 41.821 74.952 ;
     RECT  41.749 96.288 41.857 96.312 ;
     RECT  41.821 71.088 41.897 75 ;
     RECT  41.749 56.592 41.929 58.152 ;
     RECT  41.501 59.184 41.929 61.656 ;
     RECT  41.857 96.192 41.929 96.312 ;
     RECT  41.897 74.304 41.933 75 ;
     RECT  41.933 74.4 41.989 75 ;
     RECT  41.501 75.984 41.989 76.008 ;
     RECT  41.573 101.088 42.073 101.352 ;
     RECT  41.105 95.088 42.14 95.16 ;
     RECT  41.177 90.48 42.181 91.752 ;
     RECT  41.557 92.832 42.181 93.384 ;
     RECT  42.14 94.608 42.181 95.16 ;
     RECT  42.181 90.096 42.284 91.752 ;
     RECT  42.181 92.832 42.284 95.16 ;
     RECT  41.929 56.592 42.325 61.656 ;
     RECT  41.507 85.104 42.325 86.904 ;
     RECT  41.141 47.04 42.361 50.376 ;
     RECT  41.141 51.408 42.361 52.776 ;
     RECT  40.565 98.88 42.397 99.192 ;
     RECT  42.073 100.32 42.397 101.352 ;
     RECT  41.555 67.296 42.541 68.376 ;
     RECT  41.929 96.192 42.757 96.6 ;
     RECT  41.285 102.768 42.757 102.792 ;
     RECT  42.325 85.104 42.793 87.336 ;
     RECT  41.717 88.368 42.793 88.92 ;
     RECT  40.504 43.056 42.908 43.08 ;
     RECT  42.361 47.04 42.908 52.776 ;
     RECT  41.141 54.672 42.908 54.696 ;
     RECT  42.325 55.728 42.908 61.656 ;
     RECT  41.501 63.072 42.908 63.096 ;
     RECT  41.555 64.656 42.908 65.784 ;
     RECT  42.541 67.296 42.908 68.664 ;
     RECT  41.651 69.792 42.908 70.008 ;
     RECT  41.897 71.088 42.908 73.08 ;
     RECT  41.989 74.4 42.908 76.008 ;
     RECT  41.789 77.328 42.908 78.936 ;
     RECT  41.717 80.304 42.908 81.48 ;
     RECT  41.507 82.608 42.908 84.072 ;
     RECT  42.793 85.104 42.908 88.92 ;
     RECT  42.284 90.096 42.908 95.16 ;
     RECT  42.757 96.192 42.908 97.032 ;
     RECT  42.397 98.88 42.908 101.352 ;
     RECT  42.757 102.672 42.908 102.792 ;
     RECT  42.908 2.148 43.009 103.152 ;
     RECT  43.009 2.148 43.012 103.224 ;
     RECT  43.012 2.418 43.1 103.224 ;
     RECT  42.937 104.832 43.189 104.856 ;
     RECT  43.1 2.418 43.204 103.422 ;
     RECT  43.204 99.984 43.265 103.224 ;
     RECT  43.204 71.088 43.301 78.936 ;
     RECT  43.204 80.832 43.331 87.672 ;
     RECT  43.204 88.848 43.331 89.544 ;
     RECT  43.189 104.832 43.337 105.768 ;
     RECT  43.204 49.008 43.373 52.296 ;
     RECT  43.204 90.576 43.409 94.488 ;
     RECT  43.265 99.984 43.409 103.176 ;
     RECT  43.337 104.832 43.445 104.856 ;
     RECT  43.301 71.664 43.589 78.936 ;
     RECT  43.204 46.656 43.612 47.928 ;
     RECT  43.373 49.008 43.633 52.2 ;
     RECT  43.409 100.032 43.763 103.176 ;
     RECT  43.409 90.624 43.841 94.488 ;
     RECT  43.204 66.72 43.905 70.008 ;
     RECT  43.905 66.72 43.907 68.424 ;
     RECT  43.204 53.568 43.955 54.888 ;
     RECT  43.612 46.8 44.057 47.928 ;
     RECT  43.331 80.832 44.165 87.336 ;
     RECT  43.841 93.264 44.165 94.488 ;
     RECT  43.204 56.592 44.233 61.992 ;
     RECT  43.204 63.072 44.233 65.688 ;
     RECT  44.233 56.592 44.237 65.688 ;
     RECT  43.204 95.616 44.237 97.032 ;
     RECT  44.237 56.592 44.269 60.936 ;
     RECT  43.589 71.664 44.273 78.696 ;
     RECT  44.269 55.968 44.305 60.936 ;
     RECT  43.955 54.048 44.413 54.888 ;
     RECT  44.305 55.872 44.413 60.936 ;
     RECT  43.204 43.056 44.449 43.08 ;
     RECT  44.273 71.664 44.449 75 ;
     RECT  43.331 88.848 44.449 88.872 ;
     RECT  43.907 67.296 44.453 68.424 ;
     RECT  43.905 69.408 44.557 70.008 ;
     RECT  44.413 54.048 44.561 60.936 ;
     RECT  44.165 80.832 44.561 86.856 ;
     RECT  43.763 100.032 44.597 102.072 ;
     RECT  43.763 103.152 44.597 103.176 ;
     RECT  44.273 75.984 44.629 78.696 ;
     RECT  43.841 90.624 44.737 92.232 ;
     RECT  44.165 93.984 44.737 94.488 ;
     RECT  44.557 69.408 44.773 70.344 ;
     RECT  44.449 71.376 44.773 75 ;
     RECT  44.485 38.016 44.809 38.04 ;
     RECT  44.809 37.584 44.845 38.04 ;
     RECT  44.557 36.048 44.876 36.072 ;
     RECT  44.597 100.272 44.881 102.072 ;
     RECT  44.845 40.944 44.953 40.968 ;
     RECT  44.449 43.056 44.989 43.848 ;
     RECT  43.633 49.008 45.013 50.568 ;
     RECT  45.061 45.696 45.169 45.72 ;
     RECT  45.167 34.08 45.205 34.104 ;
     RECT  44.737 90.24 45.205 92.232 ;
     RECT  44.989 42.288 45.253 43.848 ;
     RECT  45.169 45.168 45.253 45.72 ;
     RECT  44.057 46.8 45.253 47.304 ;
     RECT  44.561 54.048 45.277 60.6 ;
     RECT  44.449 87.888 45.313 88.872 ;
     RECT  45.205 90.24 45.313 92.904 ;
     RECT  44.237 61.968 45.349 65.688 ;
     RECT  45.277 53.616 45.421 60.6 ;
     RECT  45.253 45.168 45.529 47.304 ;
     RECT  45.452 31.296 45.608 31.32 ;
     RECT  45.493 32.832 45.608 32.856 ;
     RECT  45.205 34.08 45.608 34.824 ;
     RECT  44.876 36.048 45.608 36.168 ;
     RECT  44.845 37.584 45.608 38.808 ;
     RECT  44.953 40.416 45.608 40.968 ;
     RECT  45.253 42 45.608 43.848 ;
     RECT  45.529 45.168 45.608 47.736 ;
     RECT  45.013 48.912 45.608 50.568 ;
     RECT  43.633 51.648 45.608 52.2 ;
     RECT  45.421 53.568 45.608 60.6 ;
     RECT  45.349 61.968 45.608 65.976 ;
     RECT  44.453 67.296 45.608 67.32 ;
     RECT  44.453 68.4 45.608 68.424 ;
     RECT  44.773 69.408 45.608 75 ;
     RECT  44.629 75.984 45.608 79.032 ;
     RECT  44.561 81.744 45.608 86.856 ;
     RECT  45.313 87.888 45.608 92.904 ;
     RECT  44.737 93.984 45.608 94.584 ;
     RECT  44.237 95.616 45.608 96.744 ;
     RECT  43.204 98.88 45.608 98.904 ;
     RECT  44.881 100.272 45.608 103.032 ;
     RECT  45.608 2.148 45.712 103.152 ;
     RECT  45.712 2.418 45.8 103.152 ;
     RECT  45.8 2.418 45.904 103.422 ;
     RECT  45.904 87.072 45.965 91.992 ;
     RECT  45.904 100.272 46.001 103.032 ;
     RECT  45.904 38.496 46.019 43.848 ;
     RECT  45.904 48.72 46.019 48.984 ;
     RECT  45.904 61.68 46.019 66.744 ;
     RECT  45.904 47.712 46.073 47.736 ;
     RECT  45.904 50.304 46.073 52.296 ;
     RECT  46.019 38.496 46.163 43.176 ;
     RECT  45.904 81.744 46.181 85.944 ;
     RECT  45.904 45.024 46.211 46.2 ;
     RECT  46.073 51.84 46.217 52.296 ;
     RECT  45.904 71.616 46.217 80.568 ;
     RECT  45.965 90.048 46.217 91.992 ;
     RECT  45.904 53.616 46.289 58.68 ;
     RECT  46.211 45.696 46.325 46.2 ;
     RECT  46.181 81.744 46.325 85.8 ;
     RECT  46.217 71.664 46.355 80.568 ;
     RECT  46.355 71.664 46.397 80.376 ;
     RECT  45.965 87.072 46.397 88.68 ;
     RECT  46.325 82.464 46.469 85.8 ;
     RECT  46.073 50.304 46.505 50.712 ;
     RECT  46.217 90.048 46.577 91.32 ;
     RECT  45.904 93.984 46.577 96.36 ;
     RECT  46.577 90.24 46.588 91.32 ;
     RECT  46.505 50.352 46.613 50.712 ;
     RECT  46.577 95.232 46.721 96.36 ;
     RECT  46.469 82.656 46.729 85.8 ;
     RECT  46.397 71.664 46.757 79.224 ;
     RECT  46.577 93.984 46.793 94.152 ;
     RECT  46.289 55.728 47.005 58.68 ;
     RECT  45.904 60.048 47.005 60.696 ;
     RECT  46.397 87.072 47.009 88.152 ;
     RECT  46.001 100.272 47.041 100.296 ;
     RECT  46.001 101.472 47.041 103.032 ;
     RECT  46.019 61.68 47.077 63.096 ;
     RECT  46.019 64.08 47.077 64.872 ;
     RECT  46.397 80.352 47.081 80.376 ;
     RECT  47.041 100.272 47.081 103.032 ;
     RECT  46.289 53.904 47.117 54.744 ;
     RECT  46.729 82.704 47.149 85.8 ;
     RECT  45.904 31.92 47.18 31.992 ;
     RECT  46.721 95.52 47.219 96.36 ;
     RECT  47.117 54.672 47.293 54.744 ;
     RECT  47.005 55.728 47.293 60.696 ;
     RECT  47.081 100.272 47.305 100.92 ;
     RECT  47.029 44.064 47.329 44.088 ;
     RECT  46.217 51.84 47.329 51.864 ;
     RECT  47.329 51.84 47.365 52.296 ;
     RECT  46.325 45.696 47.437 45.72 ;
     RECT  46.163 38.496 47.473 43.08 ;
     RECT  47.005 68.448 47.473 68.472 ;
     RECT  45.904 34.608 47.573 35.208 ;
     RECT  46.757 71.664 47.612 74.952 ;
     RECT  47.401 80.784 47.617 80.808 ;
     RECT  45.904 98.64 47.617 99.192 ;
     RECT  47.305 100.272 47.617 100.872 ;
     RECT  47.219 95.52 47.689 95.784 ;
     RECT  47.293 47.904 47.701 47.928 ;
     RECT  46.019 66.72 47.725 66.744 ;
     RECT  47.473 67.824 47.725 68.472 ;
     RECT  45.904 69.456 47.725 70.104 ;
     RECT  47.077 61.68 47.761 64.872 ;
     RECT  47.473 37.872 47.797 43.08 ;
     RECT  47.329 44.064 47.797 44.472 ;
     RECT  47.617 80.784 47.797 81.528 ;
     RECT  47.149 82.704 47.797 86.76 ;
     RECT  47.612 71.088 47.833 74.952 ;
     RECT  46.757 75.984 47.833 79.224 ;
     RECT  47.797 37.872 47.845 44.472 ;
     RECT  47.437 45.552 47.845 45.72 ;
     RECT  47.18 31.92 47.869 32.616 ;
     RECT  47.573 34.608 47.869 35.352 ;
     RECT  46.793 94.032 47.893 94.152 ;
     RECT  47.689 95.424 47.893 95.784 ;
     RECT  45.904 36.336 47.905 36.792 ;
     RECT  47.845 37.872 47.905 45.72 ;
     RECT  46.613 50.544 48.013 50.712 ;
     RECT  47.365 51.84 48.013 53.592 ;
     RECT  47.797 80.784 48.085 86.76 ;
     RECT  46.588 90.24 48.085 90.936 ;
     RECT  48.085 80.64 48.121 86.76 ;
     RECT  48.121 80.352 48.193 86.76 ;
     RECT  47.009 87.888 48.193 88.152 ;
     RECT  47.905 36.336 48.301 45.72 ;
     RECT  47.905 46.896 48.301 46.92 ;
     RECT  46.861 105.744 48.305 105.768 ;
     RECT  47.869 31.92 48.308 32.76 ;
     RECT  47.869 34.08 48.308 35.352 ;
     RECT  48.301 36.336 48.308 46.92 ;
     RECT  47.701 47.904 48.308 48.456 ;
     RECT  48.013 50.544 48.308 53.592 ;
     RECT  47.293 54.672 48.308 60.696 ;
     RECT  47.761 61.68 48.308 65.544 ;
     RECT  47.725 66.72 48.308 70.104 ;
     RECT  47.833 71.088 48.308 79.224 ;
     RECT  48.193 80.352 48.308 88.152 ;
     RECT  48.085 89.28 48.308 90.936 ;
     RECT  47.893 94.032 48.308 95.784 ;
     RECT  48.121 97.296 48.308 97.32 ;
     RECT  47.617 98.64 48.308 100.872 ;
     RECT  47.081 102.048 48.308 103.032 ;
     RECT  48.308 2.148 48.412 103.152 ;
     RECT  48.412 2.418 48.5 103.152 ;
     RECT  48.5 2.418 48.604 103.422 ;
     RECT  48.604 45.696 48.755 49.608 ;
     RECT  48.604 82.224 48.773 93.048 ;
     RECT  48.604 94.032 48.845 96.312 ;
     RECT  48.604 55.68 48.851 69 ;
     RECT  48.604 40.416 48.917 44.472 ;
     RECT  48.604 34.08 49.061 34.104 ;
     RECT  48.773 82.752 49.061 92.712 ;
     RECT  48.845 94.032 49.061 94.152 ;
     RECT  48.755 45.696 49.091 49.032 ;
     RECT  48.604 97.296 49.097 103.272 ;
     RECT  48.604 32.448 49.133 32.76 ;
     RECT  48.851 60.048 49.133 69 ;
     RECT  48.604 35.184 49.169 39 ;
     RECT  49.061 86.592 49.169 92.712 ;
     RECT  49.097 97.296 49.177 102.744 ;
     RECT  48.917 40.416 49.205 43.08 ;
     RECT  49.169 35.184 49.313 37.416 ;
     RECT  49.169 86.592 49.349 89.304 ;
     RECT  48.604 50.928 49.385 54.696 ;
     RECT  49.061 82.752 49.457 85.512 ;
     RECT  49.169 90.288 49.457 92.712 ;
     RECT  48.845 95.232 49.493 96.312 ;
     RECT  49.309 105.744 49.525 105.768 ;
     RECT  49.349 89.04 49.565 89.304 ;
     RECT  48.917 44.448 49.573 44.472 ;
     RECT  49.091 45.696 49.573 46.872 ;
     RECT  49.493 95.424 49.621 96.312 ;
     RECT  49.177 97.296 49.621 101.496 ;
     RECT  49.349 86.592 49.637 87.192 ;
     RECT  49.385 52.848 49.667 54.696 ;
     RECT  49.133 60.048 49.667 67.704 ;
     RECT  48.604 71.376 49.705 74.952 ;
     RECT  48.604 75.984 49.705 78.36 ;
     RECT  49.705 71.376 49.741 78.36 ;
     RECT  49.457 82.752 49.745 84.936 ;
     RECT  49.525 104.88 49.777 105.768 ;
     RECT  49.091 47.904 49.781 49.032 ;
     RECT  49.457 90.288 49.859 91.848 ;
     RECT  49.667 53.088 49.861 54.696 ;
     RECT  48.851 55.68 49.861 58.92 ;
     RECT  49.205 41.376 49.885 43.08 ;
     RECT  49.805 92.928 49.889 92.952 ;
     RECT  49.133 68.832 49.921 69 ;
     RECT  49.385 50.928 49.925 51.768 ;
     RECT  49.861 53.088 49.948 58.92 ;
     RECT  49.637 86.592 49.961 87.144 ;
     RECT  49.573 44.448 50.053 46.872 ;
     RECT  49.169 38.4 50.065 39 ;
     RECT  49.777 104.256 50.099 105.768 ;
     RECT  49.781 49.008 50.101 49.032 ;
     RECT  49.993 50.304 50.101 50.328 ;
     RECT  49.741 71.376 50.149 78.744 ;
     RECT  49.885 41.376 50.173 43.272 ;
     RECT  49.621 95.424 50.173 101.496 ;
     RECT  49.177 102.624 50.173 102.744 ;
     RECT  50.173 95.424 50.237 102.744 ;
     RECT  49.921 68.832 50.245 69.576 ;
     RECT  50.149 71.376 50.245 79.08 ;
     RECT  49.313 35.712 50.293 37.176 ;
     RECT  50.065 38.4 50.293 39.048 ;
     RECT  50.173 41.376 50.293 43.32 ;
     RECT  50.245 68.832 50.317 79.08 ;
     RECT  50.293 35.712 50.437 39.048 ;
     RECT  50.293 40.176 50.437 40.2 ;
     RECT  50.293 41.184 50.437 43.32 ;
     RECT  49.061 94.032 50.485 94.056 ;
     RECT  49.667 60.048 50.533 61.416 ;
     RECT  50.425 34.704 50.569 34.728 ;
     RECT  49.667 62.688 50.581 67.704 ;
     RECT  50.317 68.832 50.581 79.176 ;
     RECT  50.437 35.712 50.597 43.32 ;
     RECT  50.053 44.448 50.597 47.688 ;
     RECT  50.581 62.688 50.677 79.176 ;
     RECT  48.604 80.352 50.677 81.192 ;
     RECT  49.961 86.688 50.677 87.144 ;
     RECT  50.237 95.424 50.677 103.176 ;
     RECT  50.099 104.256 50.677 104.328 ;
     RECT  50.099 105.504 50.681 105.768 ;
     RECT  49.948 55.44 50.725 58.92 ;
     RECT  50.533 59.952 50.725 61.416 ;
     RECT  49.859 90.288 50.725 90.984 ;
     RECT  49.133 32.448 50.857 32.472 ;
     RECT  49.745 82.752 50.869 84.696 ;
     RECT  50.677 86.688 50.893 87.816 ;
     RECT  49.565 89.04 50.893 89.064 ;
     RECT  48.604 31.296 51.008 31.32 ;
     RECT  50.857 32.448 51.008 32.568 ;
     RECT  50.569 34.464 51.008 34.728 ;
     RECT  50.597 35.712 51.008 47.688 ;
     RECT  50.101 49.008 51.008 50.328 ;
     RECT  49.925 51.36 51.008 51.768 ;
     RECT  49.948 53.088 51.008 54.456 ;
     RECT  50.725 55.44 51.008 61.416 ;
     RECT  50.677 62.688 51.008 81.192 ;
     RECT  50.869 82.272 51.008 84.696 ;
     RECT  50.893 86.688 51.008 89.064 ;
     RECT  50.725 90.048 51.008 90.984 ;
     RECT  50.485 93.504 51.008 94.056 ;
     RECT  50.677 95.424 51.008 104.328 ;
     RECT  51.008 2.148 51.112 104.328 ;
     RECT  51.112 2.418 51.304 104.328 ;
     RECT  51.304 95.424 51.365 104.328 ;
     RECT  51.304 36.528 51.401 39.24 ;
     RECT  51.304 93.504 51.473 94.056 ;
     RECT  51.365 104.256 51.577 104.328 ;
     RECT  50.681 105.504 51.577 105.72 ;
     RECT  51.577 104.256 51.685 105.72 ;
     RECT  51.304 50.304 51.689 51.24 ;
     RECT  51.304 53.328 51.689 61.032 ;
     RECT  51.304 44.928 51.761 45 ;
     RECT  51.304 45.984 51.761 47.688 ;
     RECT  51.304 62.688 51.833 66.744 ;
     RECT  51.304 75.984 51.833 81.192 ;
     RECT  51.304 82.656 51.869 87.384 ;
     RECT  51.761 47.328 51.905 47.688 ;
     RECT  51.685 104.256 52.013 105.768 ;
     RECT  51.869 83.04 52.265 87.384 ;
     RECT  52.013 104.784 52.265 105.768 ;
     RECT  51.304 34.464 52.271 34.488 ;
     RECT  51.304 32.544 52.289 32.616 ;
     RECT  51.304 88.608 52.297 88.776 ;
     RECT  51.304 41.136 52.357 43.8 ;
     RECT  51.905 47.664 52.364 47.688 ;
     RECT  51.304 48.672 52.364 49.224 ;
     RECT  51.689 53.328 52.364 60.936 ;
     RECT  51.304 31.344 52.373 31.368 ;
     RECT  51.689 50.736 52.405 51.24 ;
     RECT  52.265 104.832 52.409 105.768 ;
     RECT  51.304 70.656 52.441 74.952 ;
     RECT  52.297 88.368 52.589 88.776 ;
     RECT  52.357 40.368 52.597 43.8 ;
     RECT  51.304 90.048 52.621 90.36 ;
     RECT  51.833 62.688 52.661 66.648 ;
     RECT  51.304 67.824 52.661 69.528 ;
     RECT  51.401 36.528 52.693 36.552 ;
     RECT  51.401 37.584 52.693 39.24 ;
     RECT  51.473 94.032 52.693 94.056 ;
     RECT  52.693 93.504 52.733 94.056 ;
     RECT  52.597 40.368 52.741 43.848 ;
     RECT  51.761 44.976 52.741 45 ;
     RECT  52.589 88.608 52.765 88.776 ;
     RECT  52.765 88.608 52.789 88.968 ;
     RECT  52.621 90.048 52.789 91.08 ;
     RECT  52.405 50.736 52.801 51.624 ;
     RECT  51.365 95.424 52.801 102.984 ;
     RECT  52.801 95.424 52.837 103.032 ;
     RECT  52.837 95.424 52.921 103.752 ;
     RECT  52.271 34.176 52.94 34.488 ;
     RECT  52.364 47.664 52.945 49.224 ;
     RECT  52.801 50.592 52.945 51.624 ;
     RECT  51.761 45.984 53.017 46.344 ;
     RECT  52.945 47.664 53.017 51.624 ;
     RECT  52.364 52.704 53.017 60.936 ;
     RECT  52.661 69.504 53.029 69.528 ;
     RECT  52.441 70.608 53.029 74.952 ;
     RECT  53.029 69.504 53.197 74.952 ;
     RECT  51.833 75.984 53.197 77.688 ;
     RECT  52.661 62.976 53.233 66.648 ;
     RECT  52.661 67.824 53.233 68.424 ;
     RECT  52.289 32.544 53.305 33.048 ;
     RECT  52.409 104.88 53.363 105.72 ;
     RECT  52.94 34.176 53.365 34.776 ;
     RECT  53.363 105.408 53.381 105.72 ;
     RECT  53.305 32.496 53.449 33.048 ;
     RECT  53.365 34.176 53.449 35.352 ;
     RECT  52.693 36.528 53.485 39.24 ;
     RECT  52.741 40.368 53.485 45 ;
     RECT  53.449 32.496 53.593 35.352 ;
     RECT  53.485 36.528 53.593 45 ;
     RECT  52.921 95.424 53.593 103.56 ;
     RECT  53.197 69.504 53.629 77.688 ;
     RECT  51.833 78.72 53.629 81.192 ;
     RECT  52.733 93.504 53.665 93.528 ;
     RECT  53.305 31.392 53.708 31.416 ;
     RECT  53.593 32.496 53.708 45 ;
     RECT  53.017 45.984 53.708 60.936 ;
     RECT  53.125 61.92 53.708 61.944 ;
     RECT  53.233 62.976 53.708 68.424 ;
     RECT  53.629 69.504 53.708 81.192 ;
     RECT  52.265 83.232 53.708 87.384 ;
     RECT  52.789 88.608 53.708 91.08 ;
     RECT  53.665 93.216 53.708 93.528 ;
     RECT  53.593 94.848 53.708 103.56 ;
     RECT  53.708 2.148 53.812 103.56 ;
     RECT  53.812 2.418 53.893 103.56 ;
     RECT  53.893 2.418 53.941 103.608 ;
     RECT  53.941 2.418 54.004 103.752 ;
     RECT  54.004 31.392 54.065 32.568 ;
     RECT  54.004 33.6 54.131 48.744 ;
     RECT  54.004 61.728 54.131 67.176 ;
     RECT  53.381 105.408 54.131 105.624 ;
     RECT  54.004 92.976 54.137 103.752 ;
     RECT  54.131 33.6 54.179 40.392 ;
     RECT  54.004 49.872 54.179 52.296 ;
     RECT  54.179 36.576 54.209 40.392 ;
     RECT  54.004 53.568 54.209 55.8 ;
     RECT  54.004 56.88 54.209 60.6 ;
     RECT  54.131 61.728 54.209 67.08 ;
     RECT  54.004 90.096 54.245 91.848 ;
     RECT  54.131 105.504 54.245 105.624 ;
     RECT  54.245 105.6 54.268 105.624 ;
     RECT  54.131 41.904 54.281 48.744 ;
     RECT  54.065 31.392 54.317 32.52 ;
     RECT  54.209 36.576 54.389 38.808 ;
     RECT  54.004 82.272 54.389 88.968 ;
     RECT  54.179 33.6 54.425 35.064 ;
     RECT  54.389 37.152 54.425 38.808 ;
     RECT  54.179 50.112 54.461 52.296 ;
     RECT  54.137 92.976 54.497 103.656 ;
     RECT  54.425 34.8 54.533 35.064 ;
     RECT  54.373 105.648 54.563 105.672 ;
     RECT  54.004 80.832 54.569 81.192 ;
     RECT  54.317 32.304 54.641 32.52 ;
     RECT  54.425 37.152 54.677 37.992 ;
     RECT  54.677 37.632 54.713 37.992 ;
     RECT  54.461 50.16 54.713 52.296 ;
     RECT  54.004 68.16 54.713 68.424 ;
     RECT  54.497 92.976 54.713 103.368 ;
     RECT  54.281 41.904 54.821 46.536 ;
     RECT  54.641 32.496 54.995 32.52 ;
     RECT  54.425 33.6 54.995 33.624 ;
     RECT  54.713 96 55.037 103.368 ;
     RECT  54.533 34.8 55.073 34.824 ;
     RECT  54.209 40.128 55.109 40.392 ;
     RECT  54.713 92.976 55.145 95.016 ;
     RECT  55.109 40.368 55.177 40.392 ;
     RECT  54.821 41.904 55.177 46.248 ;
     RECT  54.004 69.504 55.177 79.56 ;
     RECT  54.245 90.096 55.213 91.656 ;
     RECT  55.145 92.976 55.213 93.528 ;
     RECT  54.713 37.872 55.217 37.992 ;
     RECT  54.209 61.728 55.249 66.888 ;
     RECT  54.389 82.272 55.253 87.816 ;
     RECT  54.569 80.928 55.321 81.192 ;
     RECT  54.209 57.024 55.325 60.6 ;
     RECT  55.145 94.56 55.325 95.016 ;
     RECT  55.321 80.928 55.361 81.672 ;
     RECT  55.253 82.8 55.396 87.816 ;
     RECT  54.209 53.568 55.429 55.512 ;
     RECT  54.713 50.688 55.477 52.296 ;
     RECT  55.429 53.328 55.477 55.512 ;
     RECT  55.037 96.336 55.532 103.368 ;
     RECT  54.389 88.896 55.573 88.968 ;
     RECT  55.213 90.096 55.573 93.528 ;
     RECT  55.525 105.696 55.613 105.72 ;
     RECT  55.325 60.384 55.789 60.6 ;
     RECT  55.249 61.728 55.789 67.032 ;
     RECT  55.177 69.504 55.861 79.752 ;
     RECT  55.477 50.688 56.041 55.512 ;
     RECT  55.325 57.024 56.041 59.208 ;
     RECT  55.789 60.384 56.053 67.032 ;
     RECT  54.713 68.16 56.053 68.232 ;
     RECT  55.177 40.368 56.077 46.248 ;
     RECT  54.281 47.664 56.149 48.744 ;
     RECT  55.573 88.896 56.149 93.528 ;
     RECT  55.325 94.56 56.149 94.968 ;
     RECT  55.217 37.872 56.185 37.896 ;
     RECT  56.077 40.128 56.221 46.248 ;
     RECT  56.149 47.664 56.221 49.272 ;
     RECT  56.041 50.688 56.245 59.208 ;
     RECT  56.185 37.392 56.293 37.896 ;
     RECT  56.293 37.392 56.408 38.52 ;
     RECT  56.221 40.128 56.408 49.272 ;
     RECT  56.245 50.304 56.408 59.208 ;
     RECT  56.053 60.384 56.408 68.232 ;
     RECT  55.861 69.504 56.408 79.848 ;
     RECT  55.361 81.12 56.408 81.672 ;
     RECT  55.396 82.8 56.408 87.864 ;
     RECT  56.149 88.896 56.408 94.968 ;
     RECT  55.532 96.336 56.408 103.752 ;
     RECT  56.408 2.148 56.512 103.752 ;
     RECT  56.149 105.648 56.581 105.672 ;
     RECT  56.512 2.418 56.704 103.752 ;
     RECT  56.704 37.392 56.765 68.28 ;
     RECT  56.704 81.12 56.819 103.752 ;
     RECT  56.581 104.832 56.861 105.672 ;
     RECT  56.765 50.112 56.873 68.28 ;
     RECT  56.819 81.12 56.909 82.056 ;
     RECT  56.704 74.064 56.945 79.56 ;
     RECT  56.909 81.168 56.945 82.056 ;
     RECT  56.861 104.832 56.945 105.72 ;
     RECT  56.945 104.832 56.963 105.528 ;
     RECT  56.765 37.392 57.017 49.08 ;
     RECT  56.819 83.616 57.305 103.752 ;
     RECT  56.945 78.384 57.413 79.56 ;
     RECT  56.704 69.264 57.805 73.08 ;
     RECT  56.945 74.064 57.805 77.352 ;
     RECT  57.305 83.616 57.917 103.704 ;
     RECT  57.017 37.392 57.953 48.744 ;
     RECT  57.917 93.504 57.953 103.704 ;
     RECT  57.805 69.264 58.021 77.352 ;
     RECT  57.413 78.384 58.021 78.408 ;
     RECT  57.917 83.616 58.165 92.472 ;
     RECT  56.963 104.832 58.205 104.856 ;
     RECT  57.953 42.24 58.213 48.744 ;
     RECT  57.413 79.44 58.237 79.56 ;
     RECT  56.945 81.168 58.237 81.192 ;
     RECT  57.953 94.8 58.405 103.704 ;
     RECT  58.213 42.24 58.417 49.224 ;
     RECT  58.417 42.24 58.561 49.656 ;
     RECT  58.237 79.44 58.561 81.192 ;
     RECT  58.561 79.44 58.669 82.152 ;
     RECT  58.165 83.232 58.669 92.472 ;
     RECT  58.405 94.8 58.673 104.28 ;
     RECT  56.873 50.688 58.705 68.28 ;
     RECT  58.021 69.264 58.705 78.408 ;
     RECT  58.673 94.8 58.853 104.232 ;
     RECT  57.953 37.392 58.921 41.256 ;
     RECT  58.705 50.688 58.921 78.408 ;
     RECT  58.669 79.44 58.921 92.472 ;
     RECT  58.837 105.6 58.957 105.624 ;
     RECT  58.921 36.912 58.981 41.256 ;
     RECT  58.561 42.24 58.981 49.704 ;
     RECT  57.953 93.504 58.981 93.528 ;
     RECT  58.957 105.6 59.041 105.72 ;
     RECT  58.981 93.504 59.065 93.768 ;
     RECT  58.853 94.8 59.065 103.752 ;
     RECT  58.981 36.912 59.108 49.704 ;
     RECT  58.921 50.688 59.108 92.472 ;
     RECT  59.065 93.504 59.108 103.752 ;
     RECT  59.108 2.148 59.212 103.752 ;
     RECT  59.212 2.418 59.404 103.752 ;
     RECT  59.404 51.216 59.429 61.56 ;
     RECT  59.041 105.6 59.555 105.672 ;
     RECT  59.404 47.664 59.573 49.224 ;
     RECT  59.404 63.072 59.681 85.992 ;
     RECT  59.641 104.832 59.725 104.856 ;
     RECT  59.681 63.072 59.939 68.184 ;
     RECT  59.404 94.944 60.109 103.752 ;
     RECT  60.109 94.944 60.221 104.328 ;
     RECT  59.939 63.072 60.365 65.016 ;
     RECT  60.365 63.072 60.373 64.92 ;
     RECT  59.429 60.672 60.419 61.56 ;
     RECT  59.429 51.216 60.469 59.448 ;
     RECT  60.419 60.672 60.469 60.936 ;
     RECT  60.428 35.088 60.515 35.112 ;
     RECT  59.573 47.664 60.572 48.984 ;
     RECT  59.404 36.096 60.577 39.096 ;
     RECT  59.404 40.176 60.577 40.968 ;
     RECT  59.681 69.264 60.581 85.992 ;
     RECT  59.404 42.24 60.613 46.056 ;
     RECT  60.373 62.736 60.649 64.92 ;
     RECT  60.577 35.424 60.685 39.096 ;
     RECT  60.577 40.176 60.685 41.112 ;
     RECT  59.404 88.128 60.685 92.472 ;
     RECT  59.404 93.744 60.685 93.912 ;
     RECT  60.221 95.616 60.755 104.328 ;
     RECT  60.685 35.424 60.805 41.112 ;
     RECT  60.613 42.24 60.901 46.248 ;
     RECT  60.572 47.28 60.901 48.984 ;
     RECT  59.939 66.096 60.973 68.184 ;
     RECT  60.581 69.264 60.973 81.72 ;
     RECT  60.581 83.232 61.081 85.992 ;
     RECT  59.404 87.12 61.081 87.144 ;
     RECT  60.805 38.496 61.117 41.112 ;
     RECT  60.901 42.24 61.117 48.984 ;
     RECT  61.081 83.232 61.196 87.144 ;
     RECT  60.685 88.128 61.196 93.912 ;
     RECT  60.973 66.096 61.261 81.72 ;
     RECT  61.181 105.696 61.265 105.72 ;
     RECT  60.469 50.16 61.333 50.184 ;
     RECT  60.469 51.216 61.333 60.936 ;
     RECT  61.117 38.496 61.532 48.984 ;
     RECT  60.755 95.616 61.549 104.28 ;
     RECT  61.532 38.496 61.573 49.032 ;
     RECT  61.333 50.16 61.573 60.936 ;
     RECT  60.805 35.424 61.621 37.416 ;
     RECT  61.549 95.136 61.805 104.28 ;
     RECT  61.621 34.8 61.808 37.416 ;
     RECT  61.573 38.496 61.808 60.936 ;
     RECT  60.649 62.256 61.808 64.92 ;
     RECT  61.261 65.952 61.808 81.72 ;
     RECT  61.196 83.232 61.808 93.912 ;
     RECT  61.805 95.136 61.808 103.704 ;
     RECT  61.808 2.148 61.912 103.704 ;
     RECT  61.912 2.418 62.104 103.704 ;
     RECT  62.104 87.936 62.201 103.704 ;
     RECT  62.201 96.336 62.273 103.704 ;
     RECT  62.104 47.808 62.309 53.352 ;
     RECT  62.273 96.336 62.741 103.512 ;
     RECT  62.104 82.512 62.812 85.848 ;
     RECT  62.104 36.816 62.885 46.728 ;
     RECT  62.309 47.808 62.957 49.752 ;
     RECT  62.885 40.224 63.029 46.728 ;
     RECT  62.104 65.952 63.065 77.352 ;
     RECT  62.104 78.432 63.133 80.088 ;
     RECT  62.104 81.072 63.133 81.096 ;
     RECT  62.201 87.936 63.203 95.16 ;
     RECT  62.309 51.216 63.205 53.352 ;
     RECT  62.104 54.384 63.205 64.92 ;
     RECT  63.203 88.368 63.205 95.16 ;
     RECT  62.741 96.336 63.205 103.32 ;
     RECT  62.104 35.424 63.209 35.832 ;
     RECT  63.029 46.704 63.241 46.728 ;
     RECT  62.957 47.808 63.241 49.512 ;
     RECT  63.205 51.216 63.245 64.92 ;
     RECT  62.885 36.816 63.281 39.192 ;
     RECT  63.205 88.368 63.317 103.32 ;
     RECT  63.245 51.312 63.493 64.92 ;
     RECT  63.065 65.952 63.493 69.336 ;
     RECT  62.812 82.512 63.529 85.8 ;
     RECT  63.133 78.432 63.601 81.096 ;
     RECT  63.529 82.464 63.601 85.8 ;
     RECT  63.74 104.736 63.773 104.76 ;
     RECT  63.709 105.744 63.773 105.768 ;
     RECT  63.773 104.736 63.827 105.768 ;
     RECT  63.065 70.32 63.853 77.352 ;
     RECT  63.601 78.432 63.853 85.8 ;
     RECT  63.827 104.832 63.857 105.768 ;
     RECT  63.857 105.744 64.019 105.768 ;
     RECT  63.281 36.864 64.141 39.192 ;
     RECT  63.029 40.224 64.141 45.288 ;
     RECT  63.241 46.704 64.285 49.512 ;
     RECT  64.285 46.704 64.393 50.04 ;
     RECT  63.493 51.312 64.393 69.336 ;
     RECT  63.853 70.32 64.393 85.8 ;
     RECT  63.169 27.36 64.508 27.384 ;
     RECT  63.209 35.616 64.508 35.832 ;
     RECT  64.141 36.864 64.508 45.288 ;
     RECT  64.393 46.704 64.508 69.336 ;
     RECT  64.393 70.32 64.508 85.992 ;
     RECT  63.317 88.368 64.508 91.992 ;
     RECT  63.317 93.072 64.508 103.32 ;
     RECT  64.508 2.148 64.612 103.32 ;
     RECT  64.612 2.418 64.7 103.32 ;
     RECT  64.7 2.418 64.804 103.422 ;
     RECT  64.804 96.48 64.825 103.422 ;
     RECT  64.804 94.416 64.931 95.448 ;
     RECT  64.825 96.48 64.979 103.752 ;
     RECT  64.804 41.424 65.081 49.56 ;
     RECT  65.041 105.648 65.225 105.672 ;
     RECT  64.804 50.544 65.297 72.456 ;
     RECT  64.804 88.32 65.315 91.944 ;
     RECT  65.297 50.544 65.356 65.256 ;
     RECT  65.081 41.424 65.613 48.936 ;
     RECT  65.613 41.616 65.747 48.936 ;
     RECT  64.804 73.488 65.833 85.992 ;
     RECT  64.931 94.464 65.893 95.448 ;
     RECT  64.979 96.48 65.893 103.32 ;
     RECT  65.315 88.656 65.977 91.944 ;
     RECT  64.804 93.072 65.977 93.432 ;
     RECT  65.893 94.464 65.977 103.32 ;
     RECT  65.977 88.656 65.98 103.32 ;
     RECT  65.98 88.656 65.981 95.496 ;
     RECT  65.653 105.696 66.125 105.768 ;
     RECT  65.833 73.488 66.161 86.088 ;
     RECT  65.747 42.576 66.179 48.936 ;
     RECT  66.179 46.896 66.181 48.936 ;
     RECT  65.297 66.336 66.229 72.456 ;
     RECT  66.161 73.488 66.229 74.328 ;
     RECT  64.804 35.28 66.301 40.44 ;
     RECT  66.125 105.696 66.305 105.72 ;
     RECT  65.356 52.464 66.565 65.256 ;
     RECT  66.229 66.336 66.565 74.328 ;
     RECT  65.356 50.544 66.589 51.384 ;
     RECT  66.565 52.464 66.589 74.328 ;
     RECT  66.301 34.992 66.625 40.44 ;
     RECT  66.161 75.504 66.661 86.088 ;
     RECT  66.62 87.216 66.661 87.24 ;
     RECT  66.625 34.992 66.709 40.68 ;
     RECT  66.179 42.576 67.093 45.576 ;
     RECT  64.804 32.304 67.208 32.328 ;
     RECT  66.709 34.992 67.208 40.824 ;
     RECT  67.093 42 67.208 45.576 ;
     RECT  66.181 46.896 67.208 48.984 ;
     RECT  66.589 50.544 67.208 74.328 ;
     RECT  66.661 75.504 67.208 87.672 ;
     RECT  65.981 88.656 67.208 94.152 ;
     RECT  65.981 95.184 67.208 95.496 ;
     RECT  65.98 96.816 67.208 103.32 ;
     RECT  67.208 2.148 67.312 103.32 ;
     RECT  67.312 2.418 67.4 103.32 ;
     RECT  67.4 2.418 67.504 103.422 ;
     RECT  67.504 36.576 67.565 40.68 ;
     RECT  67.705 105.648 67.817 105.672 ;
     RECT  67.504 41.712 67.853 61.464 ;
     RECT  67.504 65.952 68.105 66.12 ;
     RECT  67.853 41.712 68.285 48.744 ;
     RECT  67.565 36.576 68.429 40.296 ;
     RECT  68.285 41.712 68.609 48.264 ;
     RECT  67.504 69.216 68.641 81.912 ;
     RECT  67.504 82.992 68.641 93.672 ;
     RECT  67.504 34.992 68.677 35.448 ;
     RECT  68.429 36.576 68.677 36.84 ;
     RECT  67.504 67.104 68.713 68.232 ;
     RECT  68.641 69.216 68.713 93.672 ;
     RECT  67.504 95.376 68.78 103.32 ;
     RECT  68.497 33.936 68.857 33.96 ;
     RECT  68.78 94.848 68.867 103.32 ;
     RECT  67.853 50.208 68.929 61.464 ;
     RECT  67.504 62.496 68.929 64.92 ;
     RECT  68.713 67.104 68.965 93.672 ;
     RECT  68.429 37.92 69.061 40.296 ;
     RECT  68.609 41.712 69.061 45.576 ;
     RECT  68.857 33.312 69.145 33.96 ;
     RECT  68.677 34.992 69.145 36.84 ;
     RECT  67.504 32.304 69.217 32.328 ;
     RECT  69.145 33.312 69.217 36.84 ;
     RECT  69.253 105.696 69.349 105.72 ;
     RECT  68.929 50.208 69.397 64.92 ;
     RECT  68.105 66.048 69.397 66.12 ;
     RECT  69.217 32.304 69.433 36.84 ;
     RECT  69.061 37.92 69.433 45.576 ;
     RECT  69.397 50.208 69.445 66.12 ;
     RECT  68.867 95.76 69.445 103.32 ;
     RECT  69.445 49.44 69.469 66.12 ;
     RECT  68.965 67.104 69.469 94.584 ;
     RECT  69.349 105.6 69.509 105.72 ;
     RECT  69.509 105.6 69.649 105.672 ;
     RECT  69.433 32.304 69.908 45.576 ;
     RECT  68.609 46.8 69.908 48.264 ;
     RECT  69.469 49.44 69.908 94.584 ;
     RECT  69.445 95.76 69.908 103.752 ;
     RECT  69.649 104.88 70.001 105.672 ;
     RECT  69.908 2.148 70.012 103.752 ;
     RECT  70.012 2.418 70.117 103.752 ;
     RECT  70.001 104.832 70.117 105.672 ;
     RECT  70.117 2.418 70.204 105.672 ;
     RECT  70.204 70.368 70.403 105.672 ;
     RECT  70.204 51.216 70.409 51.384 ;
     RECT  70.403 70.368 70.409 104.952 ;
     RECT  70.409 70.368 70.445 81.72 ;
     RECT  70.445 70.368 70.625 81.672 ;
     RECT  70.204 53.904 70.691 69.336 ;
     RECT  70.409 82.704 70.697 104.952 ;
     RECT  70.204 32.304 70.733 48.264 ;
     RECT  70.204 52.752 70.733 52.872 ;
     RECT  70.691 67.536 70.733 69.336 ;
     RECT  70.697 82.704 70.949 103.752 ;
     RECT  70.697 104.88 70.985 104.952 ;
     RECT  70.733 32.304 71.021 48.216 ;
     RECT  70.691 53.904 71.057 65.976 ;
     RECT  70.985 104.928 71.123 104.952 ;
     RECT  71.021 32.304 71.129 46.824 ;
     RECT  71.057 53.904 71.237 65.304 ;
     RECT  71.237 53.904 71.345 65.16 ;
     RECT  70.733 67.632 71.845 69.336 ;
     RECT  70.625 70.368 71.845 81.432 ;
     RECT  71.845 66.576 71.881 66.6 ;
     RECT  71.845 67.632 71.881 81.432 ;
     RECT  71.021 47.904 72.169 48.216 ;
     RECT  70.949 83.328 72.241 103.752 ;
     RECT  71.129 46.032 72.277 46.824 ;
     RECT  72.169 47.856 72.277 48.216 ;
     RECT  72.241 83.328 72.421 104.328 ;
     RECT  72.421 83.184 72.467 104.328 ;
     RECT  71.129 32.304 72.608 45.048 ;
     RECT  72.277 46.032 72.608 48.216 ;
     RECT  70.409 51.36 72.608 51.384 ;
     RECT  70.733 52.752 72.608 52.776 ;
     RECT  71.345 53.904 72.608 64.92 ;
     RECT  71.881 66.576 72.608 81.432 ;
     RECT  72.467 83.184 72.608 103.8 ;
     RECT  72.608 2.148 72.712 103.8 ;
     RECT  72.712 2.418 72.904 103.8 ;
     RECT  72.904 44.352 73.001 47.88 ;
     RECT  72.904 51.36 73.379 51.384 ;
     RECT  72.904 49.536 73.397 50.328 ;
     RECT  72.904 54.096 73.397 103.8 ;
     RECT  73.001 44.352 73.523 46.92 ;
     RECT  73.397 54.096 73.541 103.224 ;
     RECT  73.541 54.096 73.829 102.84 ;
     RECT  72.904 32.304 73.901 42.744 ;
     RECT  72.904 52.752 73.957 52.776 ;
     RECT  73.829 54.096 73.957 69.336 ;
     RECT  73.523 46.896 74.009 46.92 ;
     RECT  73.573 104.256 74.245 104.28 ;
     RECT  73.957 52.752 74.261 69.336 ;
     RECT  74.245 104.256 74.341 104.328 ;
     RECT  74.341 104.256 74.492 104.808 ;
     RECT  74.492 104.256 74.513 104.904 ;
     RECT  74.513 104.784 74.585 104.904 ;
     RECT  73.901 32.304 74.653 34.728 ;
     RECT  73.397 50.304 74.725 50.328 ;
     RECT  73.523 44.352 74.773 45.288 ;
     RECT  73.829 70.368 74.869 102.84 ;
     RECT  74.585 104.88 75.061 104.904 ;
     RECT  73.901 35.712 75.085 42.744 ;
     RECT  74.869 70.368 75.109 103.224 ;
     RECT  75.085 35.712 75.121 42.84 ;
     RECT  74.941 48.96 75.193 48.984 ;
     RECT  74.689 47.904 75.265 47.928 ;
     RECT  74.653 32.208 75.308 34.728 ;
     RECT  75.121 35.712 75.308 43.032 ;
     RECT  74.773 44.352 75.308 45.48 ;
     RECT  75.265 47.424 75.308 47.928 ;
     RECT  75.193 48.96 75.308 49.032 ;
     RECT  74.725 50.304 75.308 50.76 ;
     RECT  74.261 52.752 75.308 62.184 ;
     RECT  74.261 63.36 75.308 69.336 ;
     RECT  75.109 70.368 75.308 103.752 ;
     RECT  75.308 2.148 75.412 103.752 ;
     RECT  75.412 2.418 75.493 103.752 ;
     RECT  75.493 2.418 75.604 103.8 ;
     RECT  75.604 95.376 75.665 98.472 ;
     RECT  75.604 63.36 75.737 94.392 ;
     RECT  75.061 104.88 75.779 105.672 ;
     RECT  75.737 63.36 75.953 94.344 ;
     RECT  75.604 47.328 76.067 51.24 ;
     RECT  75.953 93.552 76.133 94.344 ;
     RECT  75.985 104.832 76.211 104.856 ;
     RECT  75.953 63.36 76.241 91.992 ;
     RECT  75.604 99.744 76.453 103.8 ;
     RECT  75.604 44.352 76.457 45.48 ;
     RECT  76.241 63.36 76.597 91.944 ;
     RECT  75.665 95.616 76.643 98.472 ;
     RECT  75.604 52.368 76.693 61.8 ;
     RECT  76.597 62.976 76.693 91.944 ;
     RECT  76.643 96.528 76.693 98.472 ;
     RECT  76.453 99.744 76.693 104.28 ;
     RECT  75.604 32.208 76.745 43.176 ;
     RECT  76.693 96.528 76.787 104.28 ;
     RECT  76.693 52.368 76.813 91.944 ;
     RECT  76.813 52.224 76.853 91.944 ;
     RECT  76.067 47.328 76.885 50.952 ;
     RECT  76.853 52.224 76.925 65.496 ;
     RECT  76.787 98.88 76.925 104.28 ;
     RECT  76.457 44.352 76.957 44.472 ;
     RECT  76.885 46.848 76.997 50.952 ;
     RECT  76.925 52.224 76.997 65.4 ;
     RECT  76.741 105.696 77.267 105.72 ;
     RECT  76.997 47.328 77.317 50.952 ;
     RECT  76.997 52.224 77.317 65.256 ;
     RECT  76.745 32.208 77.929 42.84 ;
     RECT  77.929 31.968 78.008 42.84 ;
     RECT  76.957 43.92 78.008 44.472 ;
     RECT  76.457 45.456 78.008 45.48 ;
     RECT  77.317 47.328 78.008 65.256 ;
     RECT  76.853 66.528 78.008 91.944 ;
     RECT  76.133 94.32 78.008 94.344 ;
     RECT  76.787 96.528 78.008 97.896 ;
     RECT  76.925 98.88 78.008 103.8 ;
     RECT  78.008 2.148 78.085 103.8 ;
     RECT  78.085 2.148 78.112 104.28 ;
     RECT  78.112 2.418 78.304 104.28 ;
     RECT  78.277 105.696 78.437 105.72 ;
     RECT  78.304 31.968 78.545 92.136 ;
     RECT  78.304 96.432 78.581 104.28 ;
     RECT  78.581 96.432 78.797 103.752 ;
     RECT  78.545 32.496 78.803 92.136 ;
     RECT  78.803 32.496 78.844 46.872 ;
     RECT  78.844 32.496 79.193 46.824 ;
     RECT  78.803 47.904 79.229 92.136 ;
     RECT  79.229 47.904 79.337 67.752 ;
     RECT  79.193 34.08 79.409 46.824 ;
     RECT  79.229 68.736 79.585 92.136 ;
     RECT  78.304 93.312 79.585 94.344 ;
     RECT  79.193 32.496 79.661 33.048 ;
     RECT  78.797 98.928 79.667 103.752 ;
     RECT  79.667 99.024 79.708 103.752 ;
     RECT  79.585 68.736 79.765 94.344 ;
     RECT  79.813 105.504 79.909 105.528 ;
     RECT  79.909 105.456 79.954 105.624 ;
     RECT  79.954 105.456 80.125 105.72 ;
     RECT  80.125 105.408 80.243 105.72 ;
     RECT  80.243 105.504 80.332 105.72 ;
     RECT  79.337 48.048 80.341 67.752 ;
     RECT  79.765 68.736 80.341 94.968 ;
     RECT  80.332 105.6 80.387 105.72 ;
     RECT  79.409 35.184 80.389 46.824 ;
     RECT  80.341 48.048 80.389 94.968 ;
     RECT  79.661 32.496 80.708 32.616 ;
     RECT  79.409 34.08 80.708 34.104 ;
     RECT  80.389 35.184 80.708 94.968 ;
     RECT  78.797 96.432 80.708 97.848 ;
     RECT  79.708 99.12 80.708 103.752 ;
     RECT  80.708 2.148 80.812 103.752 ;
     RECT  80.812 2.418 80.869 103.752 ;
     RECT  80.869 2.418 80.956 103.8 ;
     RECT  80.956 2.418 81.004 103.752 ;
     RECT  81.004 99.888 81.065 103.752 ;
     RECT  81.004 47.328 81.137 95.064 ;
     RECT  80.387 105.648 81.203 105.72 ;
     RECT  81.203 105.696 81.347 105.72 ;
     RECT  81.065 99.888 81.389 103.704 ;
     RECT  81.004 32.496 81.569 32.568 ;
     RECT  81.137 47.328 81.569 66.12 ;
     RECT  81.389 99.888 81.713 103.656 ;
     RECT  81.713 99.984 81.857 103.656 ;
     RECT  81.857 99.984 81.929 103.608 ;
     RECT  81.137 67.104 81.965 95.064 ;
     RECT  81.965 94.32 81.997 95.064 ;
     RECT  81.004 96.576 81.997 98.088 ;
     RECT  81.965 67.104 82.145 93.336 ;
     RECT  81.569 48.144 82.165 66.12 ;
     RECT  82.145 67.104 82.165 67.128 ;
     RECT  81.004 34.176 82.285 34.2 ;
     RECT  81.004 35.184 82.285 41.496 ;
     RECT  81.929 99.984 82.289 103.56 ;
     RECT  81.997 94.32 82.325 98.088 ;
     RECT  82.289 100.08 82.577 103.56 ;
     RECT  81.569 32.496 82.645 32.52 ;
     RECT  82.577 100.08 82.649 103.512 ;
     RECT  81.004 42.48 82.789 46.344 ;
     RECT  82.649 100.08 82.793 103.464 ;
     RECT  82.789 42.48 82.861 46.92 ;
     RECT  82.165 48.144 82.861 67.128 ;
     RECT  82.285 34.176 82.933 41.496 ;
     RECT  82.861 42.48 82.933 67.128 ;
     RECT  82.145 68.16 83.113 93.336 ;
     RECT  82.325 94.32 83.113 95.064 ;
     RECT  82.933 34.176 83.269 67.128 ;
     RECT  82.645 32.496 83.408 32.616 ;
     RECT  83.269 34.176 83.408 67.176 ;
     RECT  83.113 68.16 83.408 95.064 ;
     RECT  82.325 96.576 83.408 98.088 ;
     RECT  82.793 100.08 83.408 103.422 ;
     RECT  83.408 2.148 83.512 103.422 ;
     RECT  83.512 2.418 83.704 103.422 ;
     RECT  83.704 60.816 83.884 98.184 ;
     RECT  83.704 100.512 83.945 100.632 ;
     RECT  83.704 34.176 83.981 59.832 ;
     RECT  83.884 60.816 84.161 68.52 ;
     RECT  83.884 69.792 84.449 98.184 ;
     RECT  84.449 69.792 84.611 95.496 ;
     RECT  84.611 93.744 84.665 95.496 ;
     RECT  83.981 47.904 84.697 59.832 ;
     RECT  84.161 60.816 84.697 62.568 ;
     RECT  84.161 63.552 84.913 68.52 ;
     RECT  84.611 69.792 84.913 92.472 ;
     RECT  83.981 34.176 84.953 46.872 ;
     RECT  84.697 47.904 84.953 62.568 ;
     RECT  84.449 96.576 84.953 98.184 ;
     RECT  83.945 100.512 85.025 100.536 ;
     RECT  83.704 101.712 85.061 102.264 ;
     RECT  84.953 48.384 85.237 62.568 ;
     RECT  84.913 63.552 85.237 92.472 ;
     RECT  84.665 94.32 85.477 95.496 ;
     RECT  84.953 96.576 85.477 98.088 ;
     RECT  84.953 34.176 85.573 46.776 ;
     RECT  85.573 34.08 86.065 46.776 ;
     RECT  85.477 94.32 86.101 98.088 ;
     RECT  86.065 33.12 86.108 46.776 ;
     RECT  85.237 48.384 86.108 92.472 ;
     RECT  86.101 93.504 86.108 98.088 ;
     RECT  85.061 102.24 86.108 102.264 ;
     RECT  86.108 2.148 86.212 103.152 ;
     RECT  86.212 2.418 86.3 103.152 ;
     RECT  86.3 2.418 86.404 103.422 ;
     RECT  86.404 32.592 86.573 67.992 ;
     RECT  86.573 32.592 86.645 64.104 ;
     RECT  86.404 96.576 86.645 98.088 ;
     RECT  86.404 102.096 86.681 102.216 ;
     RECT  86.404 69.312 86.812 91.8 ;
     RECT  86.645 33.84 86.825 64.104 ;
     RECT  86.645 96.576 86.969 97.8 ;
     RECT  86.825 33.84 87.221 63.816 ;
     RECT  86.573 65.136 87.397 67.992 ;
     RECT  86.969 96.576 87.401 96.6 ;
     RECT  86.645 32.592 87.433 32.616 ;
     RECT  86.404 93.36 87.433 94.344 ;
     RECT  86.404 95.472 87.433 95.496 ;
     RECT  87.221 33.84 87.437 63.624 ;
     RECT  87.433 93.36 87.505 95.496 ;
     RECT  87.433 32.208 87.649 32.616 ;
     RECT  87.437 33.84 87.649 63.576 ;
     RECT  87.649 32.208 87.653 63.576 ;
     RECT  87.505 92.88 87.721 95.496 ;
     RECT  86.812 69.696 87.733 91.8 ;
     RECT  87.721 92.88 87.733 96.312 ;
     RECT  87.733 69.696 87.779 96.312 ;
     RECT  87.721 29.28 87.937 29.304 ;
     RECT  86.969 97.776 88.009 97.8 ;
     RECT  87.397 65.136 88.081 68.28 ;
     RECT  88.081 65.136 88.117 68.52 ;
     RECT  87.779 69.696 88.117 91.128 ;
     RECT  87.397 30.624 88.657 30.648 ;
     RECT  88.009 97.776 88.693 98.088 ;
     RECT  87.937 29.232 88.729 29.304 ;
     RECT  88.729 29.232 88.765 29.352 ;
     RECT  88.657 30.384 88.765 30.648 ;
     RECT  87.779 92.4 88.765 92.424 ;
     RECT  88.765 29.232 88.808 30.648 ;
     RECT  87.653 32.208 88.808 62.568 ;
     RECT  88.117 65.136 88.808 91.128 ;
     RECT  88.765 92.256 88.808 92.424 ;
     RECT  87.779 93.504 88.808 96.312 ;
     RECT  88.693 97.392 88.808 98.088 ;
     RECT  86.681 102.192 88.808 102.216 ;
     RECT  88.808 2.148 88.912 103.152 ;
     RECT  88.912 2.418 89 103.152 ;
     RECT  89 2.418 89.104 103.422 ;
     RECT  89.104 95.136 89.273 95.736 ;
     RECT  89.104 70.368 89.309 94.152 ;
     RECT  89.309 70.608 89.345 94.152 ;
     RECT  89.273 95.184 89.345 95.736 ;
     RECT  89.345 95.184 89.381 95.496 ;
     RECT  89.104 65.136 89.489 67.608 ;
     RECT  89.104 31.68 89.597 57.96 ;
     RECT  89.381 95.184 90.137 95.208 ;
     RECT  89.345 70.8 90.245 94.152 ;
     RECT  89.597 31.68 90.353 45.48 ;
     RECT  89.104 29.232 90.457 30.648 ;
     RECT  90.245 82.224 90.457 94.152 ;
     RECT  89.104 102.192 90.461 102.216 ;
     RECT  90.353 44.976 90.565 45.48 ;
     RECT  89.597 47.04 90.565 57.96 ;
     RECT  89.104 68.736 90.637 68.952 ;
     RECT  90.637 68.64 90.764 68.952 ;
     RECT  90.245 70.8 90.764 81.144 ;
     RECT  90.565 44.976 90.817 57.96 ;
     RECT  89.104 26.064 90.853 26.616 ;
     RECT  90.457 29.088 91.105 30.648 ;
     RECT  90.353 31.68 91.105 43.8 ;
     RECT  89.104 59.232 91.213 59.544 ;
     RECT  90.853 26.064 91.321 26.664 ;
     RECT  90.565 27.888 91.321 27.912 ;
     RECT  89.489 65.136 91.321 67.128 ;
     RECT  91.213 59.232 91.349 60.072 ;
     RECT  89.104 61.392 91.349 62.808 ;
     RECT  91.321 26.064 91.501 27.912 ;
     RECT  91.105 29.088 91.501 43.8 ;
     RECT  91.501 26.064 91.508 43.8 ;
     RECT  90.817 44.976 91.508 58.152 ;
     RECT  91.349 59.232 91.508 62.808 ;
     RECT  90.709 63.84 91.508 63.864 ;
     RECT  91.321 65.136 91.508 67.368 ;
     RECT  90.764 68.64 91.508 81.144 ;
     RECT  90.457 82.224 91.508 94.68 ;
     RECT  91.508 2.148 91.612 103.152 ;
     RECT  91.612 2.418 91.7 103.152 ;
     RECT  91.7 2.418 91.804 103.422 ;
     RECT  91.804 91.872 91.865 93.048 ;
     RECT  91.804 59.184 91.901 63.624 ;
     RECT  91.865 91.872 91.937 92.184 ;
     RECT  91.804 35.808 92.195 58.152 ;
     RECT  91.901 61.968 92.369 63.624 ;
     RECT  92.195 40.032 92.513 58.152 ;
     RECT  91.937 91.872 92.657 91.896 ;
     RECT  92.513 41.424 92.693 58.152 ;
     RECT  92.513 40.032 92.729 40.056 ;
     RECT  92.195 35.808 92.869 39 ;
     RECT  92.369 62.016 92.869 63.624 ;
     RECT  91.901 59.184 92.905 60.744 ;
     RECT  91.804 64.944 92.905 69.768 ;
     RECT  91.804 70.8 92.905 90.312 ;
     RECT  92.693 41.472 92.909 58.152 ;
     RECT  92.869 35.52 92.945 39 ;
     RECT  92.905 64.944 92.945 90.312 ;
     RECT  92.869 62.016 92.953 63.864 ;
     RECT  92.909 45.264 92.977 58.152 ;
     RECT  92.905 59.184 92.977 60.888 ;
     RECT  92.953 62.016 92.981 63.624 ;
     RECT  92.981 62.016 93.011 62.472 ;
     RECT  92.981 63.504 93.017 63.624 ;
     RECT  92.945 64.944 93.125 90.12 ;
     RECT  93.125 64.944 93.553 88.92 ;
     RECT  92.977 45.264 93.625 60.888 ;
     RECT  93.445 23.952 93.805 23.976 ;
     RECT  92.945 35.52 93.913 38.184 ;
     RECT  93.805 23.088 94.021 23.976 ;
     RECT  94.021 23.088 94.208 24.648 ;
     RECT  91.804 26.064 94.208 34.104 ;
     RECT  93.913 35.52 94.208 38.232 ;
     RECT  92.909 41.472 94.208 44.232 ;
     RECT  93.625 45.264 94.208 60.984 ;
     RECT  93.011 62.16 94.208 62.472 ;
     RECT  93.017 63.6 94.208 63.624 ;
     RECT  93.553 64.608 94.208 88.92 ;
     RECT  93.125 90.096 94.208 90.12 ;
     RECT  94.208 2.148 94.312 103.152 ;
     RECT  94.312 2.418 94.4 103.152 ;
     RECT  94.4 2.418 94.504 103.422 ;
     RECT  94.504 35.424 94.717 39.912 ;
     RECT  94.504 41.04 95.171 41.064 ;
     RECT  94.504 45.456 95.465 60.936 ;
     RECT  94.504 62.448 95.749 88.68 ;
     RECT  95.465 45.456 95.897 59.304 ;
     RECT  95.465 60.384 96.181 60.936 ;
     RECT  95.897 45.456 96.277 48.216 ;
     RECT  96.181 60.384 96.469 60.984 ;
     RECT  95.749 62.208 96.469 88.68 ;
     RECT  95.897 49.296 96.709 59.304 ;
     RECT  94.504 90 96.721 90.552 ;
     RECT  96.277 44.88 96.757 48.216 ;
     RECT  96.469 60.384 96.757 88.776 ;
     RECT  96.613 21.504 96.908 21.528 ;
     RECT  94.504 23.088 96.908 34.104 ;
     RECT  94.717 35.424 96.908 39.576 ;
     RECT  96.757 44.688 96.908 48.216 ;
     RECT  96.709 49.296 96.908 59.352 ;
     RECT  96.757 60.384 96.908 88.92 ;
     RECT  96.721 90 96.908 90.648 ;
     RECT  96.908 2.148 97.012 103.152 ;
     RECT  97.012 2.418 97.1 103.152 ;
     RECT  97.1 2.418 97.204 103.422 ;
     RECT  97.204 35.424 97.265 39.576 ;
     RECT  97.204 43.776 97.301 63.528 ;
     RECT  97.204 64.608 97.337 75.432 ;
     RECT  97.301 43.776 97.661 58.248 ;
     RECT  97.204 77.28 97.661 90.552 ;
     RECT  97.661 43.776 98.129 58.104 ;
     RECT  97.337 64.608 98.233 74.952 ;
     RECT  97.301 59.76 98.305 63.528 ;
     RECT  98.233 64.56 98.305 74.952 ;
     RECT  97.265 35.52 98.521 39.576 ;
     RECT  98.305 59.76 98.561 74.952 ;
     RECT  97.204 20.112 98.629 34.104 ;
     RECT  98.521 35.28 98.629 39.576 ;
     RECT  98.129 43.776 98.633 57.96 ;
     RECT  98.561 59.856 98.773 74.952 ;
     RECT  97.661 77.472 98.773 90.552 ;
     RECT  98.773 76.896 99.157 90.552 ;
     RECT  98.629 20.112 99.608 39.576 ;
     RECT  98.305 42.192 99.608 42.216 ;
     RECT  98.633 43.872 99.608 57.96 ;
     RECT  98.773 59.856 99.608 75.432 ;
     RECT  99.157 76.512 99.608 90.552 ;
     RECT  99.608 2.148 99.712 103.152 ;
     RECT  99.712 2.418 99.8 103.152 ;
     RECT  99.8 2.418 99.904 103.422 ;
     RECT  99.904 60.96 100.037 74.952 ;
     RECT  99.904 76.656 100.037 90.072 ;
     RECT  99.904 42.192 100.073 57.96 ;
     RECT  100.037 77.376 100.109 90.072 ;
     RECT  100.109 77.616 100.307 90.072 ;
     RECT  100.073 42.192 100.613 57.864 ;
     RECT  100.307 77.616 100.829 89.832 ;
     RECT  100.613 42.192 100.835 57.624 ;
     RECT  100.835 42.192 100.883 57.048 ;
     RECT  100.829 77.616 100.901 89.736 ;
     RECT  100.901 77.712 101.045 89.736 ;
     RECT  99.904 20.112 101.365 38.28 ;
     RECT  100.037 60.96 101.693 73.848 ;
     RECT  101.545 58.704 101.945 58.728 ;
     RECT  101.693 61.392 102.053 73.848 ;
     RECT  100.037 74.928 102.665 74.952 ;
     RECT  101.045 77.712 103.165 89.64 ;
     RECT  100.883 42.192 103.201 56.712 ;
     RECT  101.365 19.92 104.028 38.28 ;
     RECT  103.201 42.192 104.028 56.808 ;
     RECT  102.053 61.392 104.028 73.608 ;
     RECT  103.165 77.52 104.028 89.736 ;
     RECT  104.028 20.448 104.069 20.472 ;
     RECT  104.028 30.144 104.069 30.168 ;
     RECT  104.028 31.392 104.069 31.416 ;
     RECT  104.028 38.112 104.069 38.136 ;
     RECT  104.028 55.008 104.069 55.032 ;
     RECT  104.028 71.424 104.069 71.448 ;
     RECT  104.028 78.912 104.069 78.936 ;
     RECT  104.028 86.976 104.069 87 ;
    LAYER M5 ;
     RECT  2.4 2.137 2.52 2.151 ;
     RECT  5.1 2.137 5.22 2.151 ;
     RECT  7.8 2.137 7.92 2.151 ;
     RECT  10.5 2.137 10.62 2.151 ;
     RECT  13.2 2.137 13.32 2.151 ;
     RECT  15.9 2.137 16.02 2.151 ;
     RECT  18.6 2.137 18.72 2.151 ;
     RECT  21.3 2.137 21.42 2.151 ;
     RECT  24 2.137 24.12 2.151 ;
     RECT  26.7 2.137 26.82 2.151 ;
     RECT  29.4 2.137 29.52 2.151 ;
     RECT  32.1 2.137 32.22 2.151 ;
     RECT  34.8 2.137 34.92 2.151 ;
     RECT  37.5 2.137 37.62 2.151 ;
     RECT  40.2 2.137 40.32 2.151 ;
     RECT  42.9 2.137 43.02 2.151 ;
     RECT  45.6 2.137 45.72 2.151 ;
     RECT  48.3 2.137 48.42 2.151 ;
     RECT  51 2.137 51.12 2.151 ;
     RECT  53.7 2.137 53.82 2.151 ;
     RECT  56.4 2.137 56.52 2.151 ;
     RECT  59.1 2.137 59.22 2.151 ;
     RECT  61.8 2.137 61.92 2.151 ;
     RECT  64.5 2.137 64.62 2.151 ;
     RECT  67.2 2.137 67.32 2.151 ;
     RECT  69.9 2.137 70.02 2.151 ;
     RECT  72.6 2.137 72.72 2.151 ;
     RECT  75.3 2.137 75.42 2.151 ;
     RECT  78 2.137 78.12 2.151 ;
     RECT  80.7 2.137 80.82 2.151 ;
     RECT  83.4 2.137 83.52 2.151 ;
     RECT  86.1 2.137 86.22 2.151 ;
     RECT  88.8 2.137 88.92 2.151 ;
     RECT  91.5 2.137 91.62 2.151 ;
     RECT  94.2 2.137 94.32 2.151 ;
     RECT  96.9 2.137 97.02 2.151 ;
     RECT  99.6 2.137 99.72 2.151 ;
     RECT  101.376 19.909 101.4 20.005 ;
     RECT  101.376 20.005 102.024 20.677 ;
     RECT  99.6 2.151 99.912 23.077 ;
     RECT  101.232 20.677 102.024 23.077 ;
     RECT  96.9 2.151 97.212 23.125 ;
     RECT  101.232 23.077 102.6 23.315 ;
     RECT  96.9 23.125 98.04 23.509 ;
     RECT  99.168 23.077 99.912 23.509 ;
     RECT  96.9 23.509 99.912 23.653 ;
     RECT  101.232 23.315 102.024 24.035 ;
     RECT  96.9 23.653 100.2 24.229 ;
     RECT  94.2 2.151 94.512 24.613 ;
     RECT  96.9 24.229 100.536 25.139 ;
     RECT  101.568 24.035 102.024 25.715 ;
     RECT  98.4 25.139 100.536 26.005 ;
     RECT  101.616 25.715 102.024 26.243 ;
     RECT  94.032 24.613 94.512 26.293 ;
     RECT  96.9 25.139 97.212 26.533 ;
     RECT  98.4 26.005 100.584 26.533 ;
     RECT  96.9 26.533 100.584 26.771 ;
     RECT  101.616 26.243 101.976 26.819 ;
     RECT  98.496 26.771 100.584 26.867 ;
     RECT  99.312 26.867 100.584 26.915 ;
     RECT  94.032 26.293 95.496 27.061 ;
     RECT  93.456 27.061 95.496 27.109 ;
     RECT  96.9 26.771 97.464 27.109 ;
     RECT  93.456 27.109 97.464 27.395 ;
     RECT  101.616 26.819 101.64 27.395 ;
     RECT  91.5 2.151 91.812 27.877 ;
     RECT  99.456 26.915 100.584 27.971 ;
     RECT  93.456 27.395 97.32 28.067 ;
     RECT  94.2 28.067 97.32 28.451 ;
     RECT  94.2 28.451 97.212 28.547 ;
     RECT  98.544 28.213 98.568 29.029 ;
     RECT  90.576 27.877 91.812 29.123 ;
     RECT  99.6 27.971 100.584 29.123 ;
     RECT  95.712 28.547 97.212 29.699 ;
     RECT  96.24 29.699 97.212 29.797 ;
     RECT  96.24 29.797 97.512 29.987 ;
     RECT  96.768 29.987 97.512 30.469 ;
     RECT  98.544 29.029 98.616 30.469 ;
     RECT  102.528 30.757 102.648 30.947 ;
     RECT  103.92 30.757 103.944 30.947 ;
     RECT  45.6 2.151 45.912 31.285 ;
     RECT  51 2.151 51.312 31.333 ;
     RECT  96.768 30.469 98.616 31.381 ;
     RECT  92.88 30.421 92.904 31.523 ;
     RECT  88.8 2.151 89.112 31.669 ;
     RECT  88.8 31.669 89.496 32.005 ;
     RECT  96.672 31.381 98.616 32.005 ;
     RECT  99.6 29.123 99.912 32.005 ;
     RECT  75.3 2.151 75.612 32.293 ;
     RECT  75.168 32.293 75.612 32.483 ;
     RECT  53.7 2.151 54.012 32.485 ;
     RECT  96.672 32.005 99.912 32.531 ;
     RECT  51 31.333 51.912 32.627 ;
     RECT  96.768 32.531 99.912 32.725 ;
     RECT  78 2.151 78.312 32.773 ;
     RECT  96.768 32.725 100.296 32.821 ;
     RECT  96.768 32.821 100.872 32.917 ;
     RECT  101.904 32.437 101.928 32.917 ;
     RECT  91.5 29.123 91.812 33.013 ;
     RECT  96.768 32.917 101.976 33.013 ;
     RECT  88.8 32.005 90.072 33.107 ;
     RECT  78 32.773 78.456 33.203 ;
     RECT  96.768 33.013 102.024 33.491 ;
     RECT  72.6 2.151 72.912 33.541 ;
     RECT  91.392 33.013 91.812 33.589 ;
     RECT  96.768 33.491 101.976 33.683 ;
     RECT  98.592 33.683 100.296 33.779 ;
     RECT  101.376 33.683 101.976 33.779 ;
     RECT  90.576 33.589 91.812 33.925 ;
     RECT  72.6 33.541 73.512 34.019 ;
     RECT  45.504 31.285 45.912 34.069 ;
     RECT  86.1 2.151 86.412 34.069 ;
     RECT  78 33.203 78.312 34.165 ;
     RECT  52.32 33.013 52.344 34.211 ;
     RECT  101.376 33.779 101.928 34.259 ;
     RECT  99.504 33.779 100.296 34.403 ;
     RECT  77.904 34.165 78.312 34.693 ;
     RECT  53.7 32.485 54.984 34.741 ;
     RECT  83.4 2.151 83.712 34.741 ;
     RECT  45.216 34.069 45.912 34.835 ;
     RECT  52.992 34.741 54.984 34.835 ;
     RECT  101.424 34.259 101.928 34.885 ;
     RECT  99.504 34.403 99.912 34.933 ;
     RECT  45.264 34.835 45.912 35.077 ;
     RECT  47.232 32.581 47.256 35.077 ;
     RECT  88.8 33.107 89.496 35.077 ;
     RECT  85.584 34.069 86.412 35.171 ;
     RECT  45.264 35.077 47.256 35.173 ;
     RECT  48.3 2.151 48.612 35.173 ;
     RECT  88.512 35.077 89.496 35.221 ;
     RECT  87.792 35.221 89.496 35.267 ;
     RECT  64.5 2.151 64.812 35.269 ;
     RECT  72.6 34.019 72.912 35.269 ;
     RECT  83.4 34.741 83.832 35.269 ;
     RECT  88.8 35.267 89.496 35.363 ;
     RECT  90.576 33.925 92.328 35.411 ;
     RECT  64.5 35.269 65.064 35.701 ;
     RECT  68.736 35.317 68.76 35.845 ;
     RECT  69.9 2.151 70.212 35.845 ;
     RECT  72.48 35.269 72.912 35.845 ;
     RECT  101.424 34.885 102.024 35.939 ;
     RECT  98.784 34.933 99.912 36.035 ;
     RECT  45.264 35.173 48.612 36.133 ;
     RECT  72.192 35.845 72.912 36.277 ;
     RECT  82.56 35.269 83.832 36.277 ;
     RECT  60.48 35.077 60.504 36.467 ;
     RECT  90.624 35.411 92.328 36.515 ;
     RECT  101.568 35.939 102.024 36.515 ;
     RECT  87.792 35.267 87.816 36.517 ;
     RECT  87.408 36.517 87.816 36.659 ;
     RECT  101.568 36.515 101.976 36.707 ;
     RECT  75.3 32.483 75.612 36.709 ;
     RECT  85.776 35.171 86.412 36.755 ;
     RECT  86.1 36.755 86.412 36.901 ;
     RECT  87.792 36.659 87.816 36.901 ;
     RECT  88.8 35.363 89.112 36.901 ;
     RECT  94.2 28.547 94.512 36.901 ;
     RECT  75.3 36.709 75.768 36.997 ;
     RECT  77.184 34.693 78.312 36.997 ;
     RECT  64.5 35.701 65.448 37.043 ;
     RECT  87.792 36.901 89.112 37.043 ;
     RECT  88.8 37.043 89.112 37.045 ;
     RECT  90.624 36.515 92.136 37.045 ;
     RECT  88.8 37.045 92.136 37.091 ;
     RECT  98.88 36.035 99.912 37.091 ;
     RECT  101.568 36.707 101.592 37.091 ;
     RECT  88.8 37.091 91.812 37.187 ;
     RECT  67.2 2.151 67.512 37.429 ;
     RECT  82.56 36.277 84.168 37.429 ;
     RECT  44.928 36.133 48.612 37.573 ;
     RECT  51 32.627 51.312 37.573 ;
     RECT  52.992 34.835 54.168 37.621 ;
     RECT  52.752 37.621 54.168 37.667 ;
     RECT  90.624 37.187 91.812 37.667 ;
     RECT  93.456 36.901 94.512 37.667 ;
     RECT  60.768 37.573 60.792 37.861 ;
     RECT  75.3 36.997 78.312 37.955 ;
     RECT  44.928 37.573 48.984 38.005 ;
     RECT  82.512 37.429 84.168 38.099 ;
     RECT  76.704 37.955 78.312 38.147 ;
     RECT  61.8 2.151 62.112 38.149 ;
     RECT  88.8 37.187 89.112 38.149 ;
     RECT  87.792 37.043 87.816 38.197 ;
     RECT  88.8 38.149 89.208 38.197 ;
     RECT  44.88 38.005 48.984 38.243 ;
     RECT  94.032 37.667 94.512 38.243 ;
     RECT  57.696 37.429 57.72 38.435 ;
     RECT  68.736 35.845 71.064 38.531 ;
     RECT  50.304 37.573 51.312 38.533 ;
     RECT  52.752 37.667 54.012 38.533 ;
     RECT  60.384 37.861 60.792 38.677 ;
     RECT  61.8 38.149 63.048 38.677 ;
     RECT  94.2 38.243 94.512 38.677 ;
     RECT  44.88 38.243 48.612 38.819 ;
     RECT  60.384 38.677 63.048 38.819 ;
     RECT  87.792 38.197 89.208 38.819 ;
     RECT  75.3 37.955 75.612 38.965 ;
     RECT  66.72 37.429 67.512 39.013 ;
     RECT  68.736 38.531 68.76 39.013 ;
     RECT  77.184 38.147 78.312 39.107 ;
     RECT  50.304 38.533 54.012 39.251 ;
     RECT  66.72 39.013 68.76 39.251 ;
     RECT  90.816 37.667 91.812 39.301 ;
     RECT  90.816 39.301 92.184 39.347 ;
     RECT  88.704 38.819 89.208 39.395 ;
     RECT  99.456 37.091 99.912 39.395 ;
     RECT  57.84 38.725 57.864 39.491 ;
     RECT  82.512 38.099 83.712 39.493 ;
     RECT  68.736 39.251 68.76 39.539 ;
     RECT  74.832 38.965 75.612 39.541 ;
     RECT  94.2 38.677 94.68 39.541 ;
     RECT  69.9 38.531 71.064 39.637 ;
     RECT  64.5 37.043 64.812 39.781 ;
     RECT  64.224 39.781 64.812 39.829 ;
     RECT  74.832 39.541 75.816 39.877 ;
     RECT  64.224 39.829 65.736 40.259 ;
     RECT  88.8 39.395 89.208 40.355 ;
     RECT  52.752 39.251 54.012 40.357 ;
     RECT  59.1 2.151 59.412 40.405 ;
     RECT  58.992 40.405 59.412 40.645 ;
     RECT  60.72 38.819 63.048 40.645 ;
     RECT  72.192 36.277 73.272 40.741 ;
     RECT  74.496 39.877 75.816 40.741 ;
     RECT  66.72 39.251 67.512 40.835 ;
     RECT  72.192 40.741 75.816 40.837 ;
     RECT  77.328 39.107 78.312 40.837 ;
     RECT  72.192 40.837 78.312 40.883 ;
     RECT  44.928 38.819 48.612 40.981 ;
     RECT  82.512 39.493 84.36 41.029 ;
     RECT  86.1 36.901 86.52 41.029 ;
     RECT  57.888 39.829 57.912 41.075 ;
     RECT  94.2 39.541 95.16 41.075 ;
     RECT  52.368 40.357 54.012 41.173 ;
     RECT  82.512 41.029 86.52 41.173 ;
     RECT  82.08 41.173 86.52 41.219 ;
     RECT  50.304 39.251 51.312 41.411 ;
     RECT  91.5 39.347 92.184 41.509 ;
     RECT  83.4 41.219 84.36 41.555 ;
     RECT  64.5 40.259 65.736 41.651 ;
     RECT  58.992 40.645 63.048 41.699 ;
     RECT  44.928 40.981 48.984 41.891 ;
     RECT  50.448 41.411 51.312 41.891 ;
     RECT  88.8 40.355 89.112 42.325 ;
     RECT  99.6 39.395 99.912 42.373 ;
     RECT  83.4 41.555 84.264 42.517 ;
     RECT  99.6 42.373 100.296 42.565 ;
     RECT  101.424 42.277 101.448 42.565 ;
     RECT  56.4 2.151 56.712 42.709 ;
     RECT  52.368 41.173 54.12 42.803 ;
     RECT  80.7 2.151 81.012 42.805 ;
     RECT  82.08 41.219 82.104 42.997 ;
     RECT  83.4 42.517 85.08 42.997 ;
     RECT  57.84 41.461 57.864 43.043 ;
     RECT  99.6 42.565 101.448 43.141 ;
     RECT  68.784 39.637 71.064 43.235 ;
     RECT  86.1 41.219 86.52 43.235 ;
     RECT  66.816 40.835 67.512 43.237 ;
     RECT  44.928 41.891 48.744 43.379 ;
     RECT  88.8 42.325 89.208 43.525 ;
     RECT  96.9 33.683 97.212 43.765 ;
     RECT  91.056 41.509 92.184 43.811 ;
     RECT  87.504 43.573 87.528 43.861 ;
     RECT  88.704 43.525 89.208 43.861 ;
     RECT  96.9 43.765 98.04 44.053 ;
     RECT  80.592 42.805 81.012 44.099 ;
     RECT  82.08 42.997 85.08 44.099 ;
     RECT  69.792 43.235 71.064 44.147 ;
     RECT  66.672 43.237 67.512 44.149 ;
     RECT  96.9 44.053 98.616 44.149 ;
     RECT  99.6 43.141 102.024 44.149 ;
     RECT  66.144 44.149 67.512 44.195 ;
     RECT  68.784 43.235 68.808 44.195 ;
     RECT  56.256 42.709 56.712 44.197 ;
     RECT  72.192 40.883 76.632 44.387 ;
     RECT  72.192 44.387 76.536 44.483 ;
     RECT  84.816 44.099 85.08 44.483 ;
     RECT  87.504 43.861 89.208 44.483 ;
     RECT  59.1 41.699 63.048 44.677 ;
     RECT  96.9 44.149 102.024 44.677 ;
     RECT  78 40.883 78.312 44.725 ;
     RECT  58.56 44.677 63.048 44.771 ;
     RECT  96.768 44.677 102.024 44.869 ;
     RECT  82.08 44.099 83.712 44.963 ;
     RECT  50.544 41.891 51.312 44.965 ;
     RECT  69.9 44.147 71.064 44.965 ;
     RECT  78 44.725 78.408 44.965 ;
     RECT  58.56 44.771 59.544 45.011 ;
     RECT  60.672 44.771 63.048 45.059 ;
     RECT  82.32 44.963 83.712 45.059 ;
     RECT  96.288 44.869 102.024 45.059 ;
     RECT  55.824 44.197 56.712 45.155 ;
     RECT  99.024 45.059 102.024 45.155 ;
     RECT  52.368 42.803 54.012 45.253 ;
     RECT  91.5 43.811 92.184 45.397 ;
     RECT  99.024 45.155 101.976 45.635 ;
     RECT  67.2 44.195 67.512 46.069 ;
     RECT  66.144 44.195 66.168 46.211 ;
     RECT  99.024 45.635 101.88 46.211 ;
     RECT  60.72 45.059 63.048 46.213 ;
     RECT  78 44.965 78.792 46.213 ;
     RECT  40.2 2.151 40.512 46.261 ;
     RECT  44.928 43.379 48.612 46.357 ;
     RECT  49.584 44.965 51.312 46.357 ;
     RECT  86.1 43.235 86.412 46.501 ;
     RECT  42.9 2.151 43.212 46.645 ;
     RECT  84.816 44.483 84.84 46.787 ;
     RECT  99.024 46.211 101.4 46.787 ;
     RECT  99.024 46.787 101.256 46.883 ;
     RECT  91.5 45.397 92.328 47.027 ;
     RECT  44.928 46.357 51.312 47.075 ;
     RECT  87.504 44.483 89.112 47.173 ;
     RECT  42.9 46.645 43.56 47.315 ;
     RECT  60.624 46.213 63.048 47.315 ;
     RECT  78 46.213 79.512 47.317 ;
     RECT  80.7 44.099 81.012 47.317 ;
     RECT  67.2 46.069 67.848 47.363 ;
     RECT  96.288 45.059 98.04 47.363 ;
     RECT  99.024 46.883 100.872 47.363 ;
     RECT  67.2 47.363 67.608 47.459 ;
     RECT  87.504 47.173 90.072 47.653 ;
     RECT  91.5 47.027 91.992 47.653 ;
     RECT  78 47.317 81.012 47.699 ;
     RECT  87.504 47.653 91.992 47.699 ;
     RECT  86.1 46.501 86.52 47.749 ;
     RECT  87.504 47.699 91.944 47.749 ;
     RECT  0.192 47.749 0.216 47.845 ;
     RECT  37.5 2.151 37.812 47.845 ;
     RECT  58.56 45.011 59.412 47.845 ;
     RECT  40.2 46.261 41.112 47.891 ;
     RECT  69.9 44.965 71.112 47.893 ;
     RECT  99.072 47.363 100.872 47.939 ;
     RECT  79.488 47.699 81.012 48.083 ;
     RECT  66.192 47.845 66.216 48.181 ;
     RECT  69.792 47.893 71.112 48.229 ;
     RECT  83.4 45.059 83.712 48.421 ;
     RECT  42.9 47.315 43.212 48.469 ;
     RECT  86.1 47.749 91.944 48.515 ;
     RECT  99.504 47.939 100.872 48.515 ;
     RECT  82.32 45.059 82.344 48.805 ;
     RECT  83.4 48.421 84.648 48.805 ;
     RECT  45.504 47.075 51.312 48.901 ;
     RECT  80.7 48.083 81.012 48.949 ;
     RECT  82.32 48.805 84.648 48.949 ;
     RECT  66 48.181 66.216 48.995 ;
     RECT  78 47.699 78.408 48.997 ;
     RECT  79.488 48.083 79.512 48.997 ;
     RECT  45.024 48.901 51.312 49.043 ;
     RECT  90.576 48.515 91.944 49.139 ;
     RECT  58.224 47.845 59.412 49.235 ;
     RECT  92.928 49.237 92.952 49.379 ;
     RECT  94.2 41.075 94.512 49.477 ;
     RECT  99.6 48.515 100.872 49.477 ;
     RECT  102 47.845 102.024 49.477 ;
     RECT  36.672 47.845 37.812 49.525 ;
     RECT  72.192 44.483 75.816 49.525 ;
     RECT  94.08 49.477 94.512 49.573 ;
     RECT  93.36 49.573 94.512 49.859 ;
     RECT  36.672 49.525 38.76 49.909 ;
     RECT  56.4 45.155 56.712 50.101 ;
     RECT  86.1 48.515 89.112 50.101 ;
     RECT  96.9 47.363 98.04 50.101 ;
     RECT  80.7 48.949 84.648 50.147 ;
     RECT  96.768 50.101 98.04 50.195 ;
     RECT  56.4 50.101 56.808 50.293 ;
     RECT  94.032 49.859 94.512 50.341 ;
     RECT  86.1 50.101 89.256 50.389 ;
     RECT  86.1 50.389 89.688 50.435 ;
     RECT  36.576 49.909 38.76 50.437 ;
     RECT  40.2 47.891 40.512 50.437 ;
     RECT  78 48.997 79.512 50.533 ;
     RECT  64.5 41.651 64.812 50.581 ;
     RECT  66 48.995 66.024 50.581 ;
     RECT  91.5 49.139 91.944 50.581 ;
     RECT  86.1 50.435 86.412 50.629 ;
     RECT  42.672 48.469 43.212 50.677 ;
     RECT  77.904 50.533 79.512 50.677 ;
     RECT  42.672 50.677 43.608 50.723 ;
     RECT  69.456 48.229 71.112 50.725 ;
     RECT  36.576 50.437 40.512 50.771 ;
     RECT  96.768 50.195 97.656 50.915 ;
     RECT  91.5 50.581 92.04 50.917 ;
     RECT  94.032 50.341 95.016 50.965 ;
     RECT  96.9 50.915 97.656 51.059 ;
     RECT  94.032 50.965 95.352 51.109 ;
     RECT  72.192 49.525 76.056 51.251 ;
     RECT  93.84 51.109 95.352 51.251 ;
     RECT  85.968 50.629 86.412 51.347 ;
     RECT  39.504 50.771 40.512 51.397 ;
     RECT  39.504 51.397 40.92 51.443 ;
     RECT  60.72 47.315 63.048 51.541 ;
     RECT  87.504 50.435 89.688 51.541 ;
     RECT  40.2 51.443 40.92 51.923 ;
     RECT  64.5 50.581 66.024 51.923 ;
     RECT  32.1 2.151 32.412 51.925 ;
     RECT  99.6 49.477 102.024 51.925 ;
     RECT  94.032 51.251 95.352 51.971 ;
     RECT  45.504 49.043 51.312 52.019 ;
     RECT  98.64 51.925 102.024 52.019 ;
     RECT  42.9 50.723 43.608 52.165 ;
     RECT  42.9 52.165 44.472 52.211 ;
     RECT  40.2 51.923 40.512 52.405 ;
     RECT  60.72 51.541 63.24 52.405 ;
     RECT  64.5 51.923 64.812 52.405 ;
     RECT  77.76 50.677 79.512 52.405 ;
     RECT  94.08 51.971 95.352 52.405 ;
     RECT  96.9 51.059 97.464 52.405 ;
     RECT  91.296 50.917 92.04 52.453 ;
     RECT  72.192 51.251 75.864 52.499 ;
     RECT  94.08 52.405 97.464 52.499 ;
     RECT  87.504 51.541 90.072 52.547 ;
     RECT  66 51.923 66.024 52.597 ;
     RECT  67.2 47.459 67.512 52.597 ;
     RECT  82.32 50.147 84.648 52.693 ;
     RECT  91.296 52.453 92.28 52.693 ;
     RECT  36.576 50.771 37.812 52.741 ;
     RECT  52.368 45.253 55.128 52.789 ;
     RECT  56.256 50.293 56.808 52.789 ;
     RECT  82.32 52.693 84.84 52.835 ;
     RECT  86.1 51.347 86.412 52.885 ;
     RECT  52.368 52.789 56.808 53.027 ;
     RECT  60.72 52.405 64.812 53.029 ;
     RECT  66 52.597 67.512 53.029 ;
     RECT  60.72 53.029 67.512 53.075 ;
     RECT  101.088 52.019 102.024 53.125 ;
     RECT  60.72 53.075 66.024 53.171 ;
     RECT  101.088 53.125 102.216 53.315 ;
     RECT  77.76 52.405 79.608 53.365 ;
     RECT  80.7 50.147 81.336 53.365 ;
     RECT  101.088 53.315 101.784 53.411 ;
     RECT  98.64 52.019 99.912 53.461 ;
     RECT  94.2 52.499 97.464 53.555 ;
     RECT  42.9 52.211 43.212 53.557 ;
     RECT  44.448 52.211 44.472 53.557 ;
     RECT  72.192 52.499 75.816 53.557 ;
     RECT  77.76 53.365 81.336 53.557 ;
     RECT  82.32 52.835 82.344 53.557 ;
     RECT  85.92 52.885 86.412 53.653 ;
     RECT  87.504 52.547 90.024 53.653 ;
     RECT  91.152 52.693 92.28 53.699 ;
     RECT  94.2 53.555 97.416 53.699 ;
     RECT  83.4 52.835 84.84 53.941 ;
     RECT  91.296 53.699 92.28 53.989 ;
     RECT  94.2 53.699 97.368 53.989 ;
     RECT  91.296 53.989 92.328 54.083 ;
     RECT  60.72 53.171 64.812 54.085 ;
     RECT  98.592 53.461 99.912 54.133 ;
     RECT  94.08 53.989 97.368 54.179 ;
     RECT  98.592 54.133 100.008 54.275 ;
     RECT  42.9 53.557 44.472 54.323 ;
     RECT  69.12 50.725 71.112 54.469 ;
     RECT  77.76 53.557 82.344 54.469 ;
     RECT  85.92 53.653 90.024 54.515 ;
     RECT  98.64 54.275 100.008 54.517 ;
     RECT  101.136 53.411 101.784 54.517 ;
     RECT  77.52 54.469 82.344 54.565 ;
     RECT  94.08 54.179 95.16 54.565 ;
     RECT  85.92 54.515 89.736 54.611 ;
     RECT  67.056 53.075 67.512 54.659 ;
     RECT  98.64 54.517 101.784 54.659 ;
     RECT  68.592 54.469 71.112 54.661 ;
     RECT  72.192 53.557 76.056 54.661 ;
     RECT  77.472 54.565 82.344 54.661 ;
     RECT  93.504 54.565 95.16 54.707 ;
     RECT  45.6 52.019 51.312 54.709 ;
     RECT  68.496 54.661 76.056 54.709 ;
     RECT  77.424 54.661 82.344 54.709 ;
     RECT  98.784 54.659 101.784 54.755 ;
     RECT  91.344 54.083 92.328 54.949 ;
     RECT  68.496 54.709 82.344 55.187 ;
     RECT  67.2 54.659 67.512 55.189 ;
     RECT  68.496 55.187 68.616 55.189 ;
     RECT  91.344 54.949 92.856 55.235 ;
     RECT  102.48 54.901 102.6 55.283 ;
     RECT  69.9 55.187 82.344 55.331 ;
     RECT  86.1 54.611 89.736 55.331 ;
     RECT  98.784 54.755 101.448 55.331 ;
     RECT  44.832 54.709 51.312 55.427 ;
     RECT  39.792 52.405 40.512 55.525 ;
     RECT  74.592 55.331 82.344 55.525 ;
     RECT  83.4 53.941 84.888 55.525 ;
     RECT  58.56 49.235 59.412 55.813 ;
     RECT  60.624 54.085 64.812 55.813 ;
     RECT  45.312 55.427 51.312 55.861 ;
     RECT  52.368 53.027 56.712 55.861 ;
     RECT  67.2 55.189 68.616 55.907 ;
     RECT  74.592 55.525 84.888 55.907 ;
     RECT  96.24 54.179 97.368 55.907 ;
     RECT  98.784 55.331 100.872 55.907 ;
     RECT  94.08 54.707 95.16 55.957 ;
     RECT  58.56 55.813 64.812 56.099 ;
     RECT  99.12 55.907 100.872 56.099 ;
     RECT  68.496 55.907 68.616 56.197 ;
     RECT  69.9 55.331 73.512 56.197 ;
     RECT  68.496 56.197 73.512 56.435 ;
     RECT  91.5 55.235 92.856 56.579 ;
     RECT  39.408 55.525 40.512 56.723 ;
     RECT  91.5 56.579 92.328 56.771 ;
     RECT  68.496 56.435 71.112 56.819 ;
     RECT  93.936 55.957 95.16 56.821 ;
     RECT  66 53.171 66.024 57.013 ;
     RECT  74.592 55.907 81.336 57.059 ;
     RECT  99.312 56.099 100.872 57.059 ;
     RECT  86.1 55.331 86.52 57.109 ;
     RECT  87.504 55.331 89.736 57.109 ;
     RECT  96.9 55.907 97.368 57.109 ;
     RECT  93.936 56.821 95.736 57.155 ;
     RECT  61.8 56.099 64.812 57.205 ;
     RECT  91.5 56.771 91.812 57.301 ;
     RECT  61.8 57.205 65.016 57.347 ;
     RECT  86.1 57.109 89.736 57.443 ;
     RECT  45.312 55.861 56.712 57.539 ;
     RECT  67.2 55.907 67.512 57.541 ;
     RECT  68.496 56.819 68.52 57.541 ;
     RECT  96.768 57.109 97.368 57.541 ;
     RECT  74.592 57.059 78.312 57.587 ;
     RECT  82.32 55.907 84.888 57.589 ;
     RECT  99.312 57.059 100.824 57.635 ;
     RECT  79.488 57.059 81.336 57.731 ;
     RECT  99.312 57.635 100.536 57.731 ;
     RECT  99.312 57.731 99.912 57.781 ;
     RECT  96.768 57.541 97.464 57.829 ;
     RECT  98.784 57.781 99.912 57.971 ;
     RECT  72.192 56.435 73.512 57.973 ;
     RECT  74.592 57.587 75.816 57.973 ;
     RECT  66 57.013 66.12 58.021 ;
     RECT  67.2 57.541 68.52 58.021 ;
     RECT  41.76 52.261 41.784 58.069 ;
     RECT  58.56 56.099 60.744 58.115 ;
     RECT  36.288 52.741 37.812 58.117 ;
     RECT  42.9 54.323 43.212 58.117 ;
     RECT  69.9 56.819 71.112 58.117 ;
     RECT  72.192 57.973 75.816 58.117 ;
     RECT  91.392 57.301 91.812 58.117 ;
     RECT  41.568 58.069 41.784 58.163 ;
     RECT  82.32 57.589 85.08 58.163 ;
     RECT  60.624 58.115 60.744 58.501 ;
     RECT  61.8 57.347 64.812 58.501 ;
     RECT  45.6 57.539 56.712 58.597 ;
     RECT  32.1 51.925 33.384 58.645 ;
     RECT  66 58.021 68.52 58.739 ;
     RECT  69.9 58.117 75.816 58.739 ;
     RECT  87.504 57.443 89.736 58.883 ;
     RECT  86.1 57.443 86.52 59.027 ;
     RECT  76.896 57.587 78.312 59.123 ;
     RECT  42.9 58.117 43.464 59.173 ;
     RECT  60.624 58.501 64.812 59.221 ;
     RECT  66 58.739 66.024 59.221 ;
     RECT  69.9 58.739 73.272 59.221 ;
     RECT  41.568 58.163 41.592 59.315 ;
     RECT  91.392 58.117 92.376 59.315 ;
     RECT  94.2 57.155 95.736 59.315 ;
     RECT  96.72 57.829 97.464 59.363 ;
     RECT  32.1 58.645 33.624 59.459 ;
     RECT  58.56 58.115 59.64 59.459 ;
     RECT  39.792 56.723 40.512 59.605 ;
     RECT  60.624 59.221 66.024 59.795 ;
     RECT  39.648 59.605 40.512 59.797 ;
     RECT  36.288 58.117 37.992 59.891 ;
     RECT  94.2 59.315 95.304 59.891 ;
     RECT  42.768 59.173 43.464 60.085 ;
     RECT  34.8 2.151 35.112 60.277 ;
     RECT  36.288 59.891 37.812 60.277 ;
     RECT  42.768 60.085 43.752 60.373 ;
     RECT  45.024 58.597 56.712 60.611 ;
     RECT  58.56 59.459 59.412 60.661 ;
     RECT  60.624 59.795 60.744 60.661 ;
     RECT  94.2 59.891 95.016 60.707 ;
     RECT  94.2 60.707 94.728 60.755 ;
     RECT  74.592 58.739 75.816 60.805 ;
     RECT  82.32 58.163 82.344 60.949 ;
     RECT  83.4 58.163 85.08 60.949 ;
     RECT  96.9 59.363 97.464 60.949 ;
     RECT  99.6 57.971 99.912 60.949 ;
     RECT  91.392 59.315 91.812 61.043 ;
     RECT  87.504 58.883 87.528 61.189 ;
     RECT  96.48 60.949 97.464 61.189 ;
     RECT  74.256 60.805 75.816 61.381 ;
     RECT  77.472 59.123 78.312 61.523 ;
     RECT  96.48 61.189 98.328 61.619 ;
     RECT  42.72 60.373 43.752 61.667 ;
     RECT  39.072 59.797 40.512 61.765 ;
     RECT  99.6 60.949 100.872 61.765 ;
     RECT  102 61.669 102.024 61.765 ;
     RECT  74.256 61.381 76.104 62.005 ;
     RECT  87.504 61.189 87.672 62.051 ;
     RECT  92.976 60.085 93 62.051 ;
     RECT  77.712 61.523 78.312 62.195 ;
     RECT  82.32 60.949 85.08 62.195 ;
     RECT  96.768 61.619 98.328 62.195 ;
     RECT  99.6 61.765 102.024 62.245 ;
     RECT  38.832 61.765 40.512 62.293 ;
     RECT  98.304 62.195 98.328 62.387 ;
     RECT  91.5 61.043 91.812 62.533 ;
     RECT  86.1 59.027 86.412 62.581 ;
     RECT  87.504 62.051 87.528 62.581 ;
     RECT  91.056 62.533 91.812 62.581 ;
     RECT  79.488 57.731 81.012 62.677 ;
     RECT  82.32 62.195 84.648 62.677 ;
     RECT  88.8 58.883 89.736 62.677 ;
     RECT  90.72 62.581 91.812 62.677 ;
     RECT  88.8 62.677 91.812 62.819 ;
     RECT  99.6 62.245 102.312 62.821 ;
     RECT  99.6 62.821 102.6 62.963 ;
     RECT  74.256 62.005 76.728 63.011 ;
     RECT  96.768 62.195 97.212 63.011 ;
     RECT  34.8 60.277 37.812 63.061 ;
     RECT  38.832 62.293 40.872 63.061 ;
     RECT  45.6 60.611 56.712 63.061 ;
     RECT  34.8 63.061 40.872 63.203 ;
     RECT  86.1 62.581 87.528 63.251 ;
     RECT  69.696 59.221 73.272 63.299 ;
     RECT  29.4 2.151 29.712 63.493 ;
     RECT  45.6 63.061 57.576 63.493 ;
     RECT  61.8 59.795 66.024 63.493 ;
     RECT  67.2 58.739 68.52 63.493 ;
     RECT  99.6 62.963 102.312 63.493 ;
     RECT  45.168 63.493 57.576 63.589 ;
     RECT  58.56 60.661 60.744 63.589 ;
     RECT  34.8 63.203 40.632 63.875 ;
     RECT  79.488 62.677 84.648 63.875 ;
     RECT  90.72 62.819 91.812 63.875 ;
     RECT  92.88 63.205 92.904 63.875 ;
     RECT  99.264 63.493 102.312 63.971 ;
     RECT  45.168 63.589 60.744 64.355 ;
     RECT  32.1 59.459 33.384 64.357 ;
     RECT  34.8 63.875 40.512 64.357 ;
     RECT  96.9 63.011 97.212 64.597 ;
     RECT  0.192 47.845 0.36 64.691 ;
     RECT  42.9 61.667 43.752 64.789 ;
     RECT  78 62.195 78.312 64.933 ;
     RECT  79.488 63.875 81.012 64.933 ;
     RECT  82.32 63.875 82.344 64.933 ;
     RECT  88.8 62.819 89.736 65.171 ;
     RECT  86.1 63.251 86.412 65.173 ;
     RECT  32.1 64.357 40.512 65.219 ;
     RECT  82.272 64.933 82.344 65.221 ;
     RECT  83.4 63.875 84.648 65.221 ;
     RECT  91.5 63.875 91.812 65.509 ;
     RECT  96.9 64.597 98.088 65.651 ;
     RECT  45.6 64.355 60.744 65.699 ;
     RECT  99.264 63.971 102.024 65.989 ;
     RECT  94.2 60.755 94.512 66.085 ;
     RECT  88.8 65.171 89.112 66.229 ;
     RECT  94.2 66.085 94.728 66.373 ;
     RECT  96.9 65.651 97.212 66.373 ;
     RECT  99.264 65.989 102.6 66.469 ;
     RECT  86.1 65.173 86.52 66.515 ;
     RECT  87.504 63.251 87.528 66.565 ;
     RECT  88.8 66.229 89.208 66.565 ;
     RECT  99.168 66.469 102.6 66.565 ;
     RECT  96.192 66.373 97.212 66.757 ;
     RECT  82.272 65.221 84.648 66.901 ;
     RECT  34.8 65.219 40.512 67.045 ;
     RECT  41.52 64.933 41.544 67.045 ;
     RECT  98.496 66.565 102.6 67.045 ;
     RECT  34.8 67.045 41.544 67.091 ;
     RECT  96.192 66.757 97.464 67.141 ;
     RECT  82.176 66.901 84.648 67.237 ;
     RECT  87.504 66.565 89.208 67.331 ;
     RECT  91.5 65.509 92.376 67.331 ;
     RECT  98.448 67.045 102.6 67.331 ;
     RECT  61.8 63.493 68.52 67.477 ;
     RECT  69.9 63.299 73.272 67.477 ;
     RECT  42.9 64.789 43.896 67.621 ;
     RECT  34.8 67.091 41.304 67.859 ;
     RECT  82.176 67.237 84.984 68.243 ;
     RECT  98.544 67.331 102.6 68.291 ;
     RECT  60.624 65.699 60.744 68.341 ;
     RECT  61.8 67.477 73.272 68.341 ;
     RECT  74.256 63.011 76.104 68.341 ;
     RECT  94.2 66.373 95.16 68.341 ;
     RECT  82.176 68.243 82.344 68.435 ;
     RECT  96.144 67.141 97.464 68.435 ;
     RECT  98.544 68.291 101.976 68.435 ;
     RECT  98.544 68.435 101.736 68.483 ;
     RECT  98.544 68.483 101.688 68.677 ;
     RECT  60.624 68.341 76.104 69.251 ;
     RECT  86.1 66.515 86.412 69.301 ;
     RECT  87.504 67.331 89.112 69.301 ;
     RECT  93.984 68.341 95.16 69.349 ;
     RECT  91.5 67.331 91.812 69.493 ;
     RECT  42.9 67.621 44.184 69.541 ;
     RECT  45.6 65.699 59.412 69.541 ;
     RECT  98.496 68.677 101.688 69.587 ;
     RECT  98.496 69.587 101.544 69.683 ;
     RECT  98.496 69.683 101.208 69.779 ;
     RECT  91.152 69.493 91.812 69.877 ;
     RECT  42.9 69.541 59.412 69.973 ;
     RECT  60.624 69.251 60.744 69.973 ;
     RECT  32.1 65.219 33.384 70.069 ;
     RECT  34.8 67.859 40.512 70.069 ;
     RECT  93.984 69.349 95.736 70.163 ;
     RECT  98.496 69.779 98.616 70.163 ;
     RECT  93.984 70.163 95.16 70.261 ;
     RECT  96.9 68.435 97.464 70.501 ;
     RECT  41.616 69.493 41.64 70.547 ;
     RECT  82.272 68.435 82.344 70.645 ;
     RECT  83.4 68.243 84.984 70.645 ;
     RECT  86.1 69.301 89.112 70.691 ;
     RECT  61.8 69.251 76.104 70.789 ;
     RECT  78 64.933 81.012 70.789 ;
     RECT  82.272 70.645 84.984 70.789 ;
     RECT  78 70.789 84.984 70.837 ;
     RECT  42.9 69.973 60.744 71.077 ;
     RECT  61.8 70.789 76.968 71.219 ;
     RECT  78 70.837 85.128 71.219 ;
     RECT  32.1 70.069 40.512 71.267 ;
     RECT  61.8 71.219 76.104 71.315 ;
     RECT  93.696 70.261 95.16 71.365 ;
     RECT  82.272 71.219 84.984 71.603 ;
     RECT  78 71.219 81.012 71.605 ;
     RECT  29.4 63.493 30.552 71.653 ;
     RECT  96.9 70.501 97.896 71.891 ;
     RECT  86.1 70.691 86.412 71.941 ;
     RECT  87.504 70.691 89.112 71.941 ;
     RECT  34.8 71.267 40.512 71.989 ;
     RECT  41.952 71.077 60.744 71.989 ;
     RECT  61.8 71.315 73.272 71.989 ;
     RECT  93.696 71.365 95.352 72.037 ;
     RECT  90.816 69.877 91.812 72.133 ;
     RECT  93.696 72.037 95.544 72.133 ;
     RECT  96.9 71.891 97.512 72.133 ;
     RECT  32.1 71.267 33.384 72.229 ;
     RECT  90.816 72.133 92.424 72.229 ;
     RECT  93.696 72.133 97.512 72.229 ;
     RECT  34.8 71.989 40.776 72.275 ;
     RECT  90.816 72.229 97.512 72.275 ;
     RECT  86.1 71.941 89.112 72.325 ;
     RECT  29.28 71.653 30.552 72.419 ;
     RECT  41.952 71.989 73.272 72.419 ;
     RECT  77.616 71.605 81.012 72.419 ;
     RECT  90.816 72.275 91.812 72.419 ;
     RECT  99.6 69.779 101.208 72.419 ;
     RECT  69.9 72.419 73.272 72.421 ;
     RECT  74.256 71.315 76.104 72.421 ;
     RECT  93.12 72.275 97.512 72.467 ;
     RECT  82.272 71.603 82.344 72.661 ;
     RECT  98.592 72.805 98.616 72.949 ;
     RECT  99.6 72.419 100.008 72.949 ;
     RECT  41.952 72.419 44.184 72.995 ;
     RECT  93.12 72.467 97.464 72.995 ;
     RECT  101.136 72.419 101.16 72.995 ;
     RECT  98.592 72.949 100.008 73.139 ;
     RECT  98.688 73.139 100.008 73.235 ;
     RECT  31.968 72.229 33.384 73.381 ;
     RECT  34.8 72.275 40.512 73.381 ;
     RECT  69.9 72.421 76.104 73.381 ;
     RECT  42.9 72.995 44.184 73.477 ;
     RECT  31.968 73.381 40.512 73.525 ;
     RECT  69.9 73.381 76.392 73.525 ;
     RECT  93.12 72.995 95.736 73.619 ;
     RECT  93.12 73.619 95.688 73.907 ;
     RECT  82.032 72.661 82.344 73.957 ;
     RECT  83.4 71.603 84.984 73.957 ;
     RECT  78 72.419 81.012 74.053 ;
     RECT  91.152 72.419 91.812 74.053 ;
     RECT  93.12 73.907 94.512 74.053 ;
     RECT  90.72 74.053 94.512 74.099 ;
     RECT  86.1 72.325 89.208 74.147 ;
     RECT  96.9 72.995 97.464 74.147 ;
     RECT  95.52 73.907 95.688 74.195 ;
     RECT  95.568 74.195 95.688 74.291 ;
     RECT  45.6 72.419 68.712 74.293 ;
     RECT  69.9 73.525 76.536 74.293 ;
     RECT  98.688 73.235 99.912 74.579 ;
     RECT  88.704 74.147 89.208 74.581 ;
     RECT  96.9 74.147 97.212 74.581 ;
     RECT  42.9 73.477 44.424 74.627 ;
     RECT  31.92 73.525 40.512 74.675 ;
     RECT  82.032 73.957 84.984 74.723 ;
     RECT  88.704 74.581 89.688 75.011 ;
     RECT  88.8 75.011 89.688 75.203 ;
     RECT  45.6 74.293 76.536 75.251 ;
     RECT  90.72 74.099 92.376 75.299 ;
     RECT  99.168 74.579 99.912 75.395 ;
     RECT  77.904 74.053 81.012 75.493 ;
     RECT  31.92 74.675 33.816 75.539 ;
     RECT  42.9 74.627 44.184 75.781 ;
     RECT  32.1 75.539 33.816 75.875 ;
     RECT  86.1 74.147 87.528 75.875 ;
     RECT  93.696 74.099 94.512 75.875 ;
     RECT  29.4 72.419 30.552 75.877 ;
     RECT  0.192 64.691 0.216 76.019 ;
     RECT  45.6 75.251 76.104 76.019 ;
     RECT  94.2 75.875 94.512 76.357 ;
     RECT  61.8 76.019 76.104 76.403 ;
     RECT  82.272 74.723 84.984 76.403 ;
     RECT  69.744 76.403 76.104 76.453 ;
     RECT  77.376 75.493 81.012 76.453 ;
     RECT  99.6 75.395 99.912 76.501 ;
     RECT  69.744 76.453 81.012 76.789 ;
     RECT  82.272 76.403 84.648 76.789 ;
     RECT  94.2 76.357 95.16 76.885 ;
     RECT  99.168 76.501 99.912 76.885 ;
     RECT  90.72 75.299 91.812 77.123 ;
     RECT  96.288 74.581 97.212 77.123 ;
     RECT  29.4 75.877 30.936 77.507 ;
     RECT  42 75.781 44.184 77.555 ;
     RECT  69.744 76.789 84.648 77.747 ;
     RECT  96.768 77.123 97.212 77.939 ;
     RECT  45.6 76.019 60.744 77.941 ;
     RECT  94.08 76.885 95.16 77.941 ;
     RECT  34.8 74.675 40.512 78.037 ;
     RECT  42 77.555 43.752 78.037 ;
     RECT  86.1 75.875 86.412 78.037 ;
     RECT  91.392 77.123 91.812 78.083 ;
     RECT  44.832 77.941 60.744 78.131 ;
     RECT  74.256 77.747 84.648 78.131 ;
     RECT  87.504 75.875 87.528 78.133 ;
     RECT  88.8 75.203 89.544 78.133 ;
     RECT  98.784 76.885 99.912 78.181 ;
     RECT  100.944 78.037 100.968 78.181 ;
     RECT  93.744 77.941 95.16 78.229 ;
     RECT  77.376 78.131 84.648 78.277 ;
     RECT  77.376 78.277 84.984 78.419 ;
     RECT  87.504 78.133 89.544 78.419 ;
     RECT  98.784 78.181 100.968 78.419 ;
     RECT  86.1 78.037 86.52 78.565 ;
     RECT  77.376 78.419 84.648 78.659 ;
     RECT  60.624 78.131 60.744 78.661 ;
     RECT  61.8 76.403 68.712 78.661 ;
     RECT  98.784 78.419 99.912 78.661 ;
     RECT  77.376 78.659 82.344 78.707 ;
     RECT  32.1 75.875 33.384 78.709 ;
     RECT  69.744 77.747 73.272 78.709 ;
     RECT  74.256 78.131 76.104 78.709 ;
     RECT  92.88 78.229 95.16 78.755 ;
     RECT  44.832 78.131 59.412 78.899 ;
     RECT  32.1 78.709 33.672 78.947 ;
     RECT  88.8 78.419 89.544 79.139 ;
     RECT  85.92 78.565 86.52 79.235 ;
     RECT  34.8 78.037 43.752 79.475 ;
     RECT  93.504 78.755 95.16 79.475 ;
     RECT  69.744 78.709 76.104 79.525 ;
     RECT  77.376 78.707 79.512 79.525 ;
     RECT  96.9 77.939 97.212 79.717 ;
     RECT  98.592 78.661 99.912 79.717 ;
     RECT  102.576 79.477 102.6 79.763 ;
     RECT  96.9 79.717 99.912 79.765 ;
     RECT  94.032 79.475 95.16 79.859 ;
     RECT  96.48 79.765 99.912 80.099 ;
     RECT  83.4 78.659 84.648 80.245 ;
     RECT  60.624 78.661 68.712 80.291 ;
     RECT  85.92 79.235 86.412 80.291 ;
     RECT  69.744 79.525 79.512 80.627 ;
     RECT  94.032 79.859 94.632 80.629 ;
     RECT  90.24 79.669 90.264 80.771 ;
     RECT  83.4 80.245 84.936 80.773 ;
     RECT  69.9 80.627 79.512 80.819 ;
     RECT  100.944 78.419 100.968 80.821 ;
     RECT  80.592 78.707 82.344 80.869 ;
     RECT  100.944 80.821 101.304 80.869 ;
     RECT  32.1 78.947 33.384 80.917 ;
     RECT  34.8 79.475 40.512 80.917 ;
     RECT  100.944 80.869 101.448 80.917 ;
     RECT  83.4 80.773 84.984 80.963 ;
     RECT  93.6 80.629 94.632 80.963 ;
     RECT  96.768 80.099 99.912 80.963 ;
     RECT  100.944 80.917 101.928 80.965 ;
     RECT  87.504 78.419 87.624 81.011 ;
     RECT  98.88 80.963 99.912 81.059 ;
     RECT  83.4 80.963 84.936 81.107 ;
     RECT  99.024 81.059 99.912 81.107 ;
     RECT  42 79.475 43.752 81.445 ;
     RECT  60.624 80.291 60.744 81.445 ;
     RECT  80.544 80.869 82.344 81.539 ;
     RECT  99.12 81.107 99.912 81.539 ;
     RECT  100.944 80.965 102.024 81.587 ;
     RECT  100.944 81.587 101.928 81.683 ;
     RECT  41.616 81.445 43.752 81.733 ;
     RECT  88.8 79.139 89.208 81.829 ;
     RECT  96.768 80.963 97.212 81.829 ;
     RECT  96.48 81.829 97.212 81.973 ;
     RECT  87.504 81.011 87.528 82.021 ;
     RECT  88.8 81.829 89.448 82.021 ;
     RECT  91.5 78.083 91.812 82.021 ;
     RECT  99.168 81.539 99.912 82.021 ;
     RECT  100.944 81.683 101.64 82.021 ;
     RECT  99.168 82.021 101.64 82.115 ;
     RECT  61.8 80.291 68.712 82.165 ;
     RECT  69.9 80.819 73.272 82.165 ;
     RECT  74.256 80.819 79.512 82.211 ;
     RECT  60.528 81.445 60.744 82.451 ;
     RECT  93.888 80.963 94.512 82.645 ;
     RECT  41.616 81.733 43.896 82.691 ;
     RECT  80.544 81.539 81.012 82.691 ;
     RECT  91.5 82.021 92.616 82.837 ;
     RECT  93.888 82.645 95.016 82.837 ;
     RECT  99.6 82.115 101.64 82.885 ;
     RECT  86.1 80.291 86.412 83.029 ;
     RECT  87.504 82.021 89.448 83.029 ;
     RECT  82.272 81.539 82.344 83.173 ;
     RECT  91.5 82.837 95.016 83.219 ;
     RECT  77.376 82.211 79.512 83.221 ;
     RECT  99.6 82.885 102.024 83.267 ;
     RECT  77.136 83.221 79.512 83.363 ;
     RECT  32.1 80.917 40.512 83.509 ;
     RECT  41.616 82.691 43.752 83.509 ;
     RECT  86.1 83.029 89.448 83.749 ;
     RECT  45.6 78.899 59.412 83.797 ;
     RECT  96.48 81.973 97.32 83.843 ;
     RECT  100.896 83.267 102.024 83.843 ;
     RECT  61.8 82.165 73.272 84.035 ;
     RECT  93.408 83.219 95.016 84.035 ;
     RECT  32.1 83.509 43.752 84.083 ;
     RECT  61.8 84.035 68.904 84.083 ;
     RECT  86.1 83.749 89.64 84.275 ;
     RECT  101.136 83.843 102.024 84.419 ;
     RECT  34.8 84.083 43.752 84.563 ;
     RECT  86.1 84.275 86.52 84.611 ;
     RECT  96.48 83.843 97.212 84.611 ;
     RECT  101.184 84.419 101.352 84.755 ;
     RECT  44.976 83.797 59.412 84.851 ;
     RECT  96.72 84.611 97.212 84.899 ;
     RECT  101.232 84.755 101.352 84.995 ;
     RECT  93.408 84.035 94.512 84.997 ;
     RECT  92.928 84.997 94.512 85.139 ;
     RECT  74.256 82.211 76.104 85.381 ;
     RECT  98.448 85.093 98.472 85.429 ;
     RECT  99.6 83.267 99.912 85.429 ;
     RECT  101.232 84.995 101.256 85.523 ;
     RECT  87.504 84.275 89.64 85.667 ;
     RECT  82.08 83.173 82.344 85.717 ;
     RECT  83.4 81.107 84.648 85.717 ;
     RECT  82.08 85.717 84.648 85.763 ;
     RECT  61.8 84.083 68.712 85.957 ;
     RECT  69.9 84.035 73.272 85.957 ;
     RECT  93.552 85.139 94.512 86.003 ;
     RECT  82.272 85.763 84.648 86.195 ;
     RECT  96.9 84.899 97.212 86.437 ;
     RECT  94.2 86.003 94.512 86.485 ;
     RECT  96.768 86.437 97.212 86.579 ;
     RECT  87.504 85.667 89.112 86.725 ;
     RECT  74.256 85.381 76.392 86.771 ;
     RECT  91.5 83.219 91.812 87.061 ;
     RECT  83.4 86.195 84.648 87.253 ;
     RECT  92.928 86.581 92.952 87.253 ;
     RECT  94.2 86.485 94.632 87.253 ;
     RECT  91.056 87.061 91.812 87.301 ;
     RECT  92.928 87.253 94.728 87.301 ;
     RECT  83.4 87.253 84.984 87.395 ;
     RECT  87.504 86.725 90.072 87.539 ;
     RECT  91.056 87.301 94.728 87.637 ;
     RECT  91.056 87.637 94.824 87.779 ;
     RECT  86.1 84.611 86.412 87.781 ;
     RECT  87.504 87.539 89.112 87.781 ;
     RECT  91.056 87.779 94.512 87.827 ;
     RECT  96.9 86.579 97.212 87.829 ;
     RECT  60.624 82.451 60.744 87.973 ;
     RECT  61.8 85.957 73.272 87.973 ;
     RECT  82.272 86.195 82.344 88.069 ;
     RECT  83.4 87.395 84.648 88.069 ;
     RECT  86.1 87.781 89.112 88.163 ;
     RECT  98.448 85.429 99.912 88.259 ;
     RECT  92.88 87.827 94.512 88.403 ;
     RECT  98.448 88.259 98.472 88.403 ;
     RECT  88.8 88.163 89.112 88.693 ;
     RECT  102.576 88.645 102.6 88.835 ;
     RECT  77.376 83.363 79.512 88.837 ;
     RECT  80.592 82.691 81.012 88.837 ;
     RECT  88.8 88.693 89.928 88.885 ;
     RECT  96.9 87.829 97.464 88.885 ;
     RECT  93.072 88.403 94.512 88.931 ;
     RECT  82.272 88.069 84.648 88.979 ;
     RECT  88.8 88.885 90.072 89.507 ;
     RECT  77.376 88.837 81.012 89.555 ;
     RECT  91.152 87.827 91.812 89.555 ;
     RECT  99.504 88.259 99.912 89.555 ;
     RECT  101.424 87.877 101.448 89.555 ;
     RECT  99.6 89.555 99.912 89.605 ;
     RECT  93.072 88.931 93.096 89.987 ;
     RECT  34.8 84.563 40.512 89.989 ;
     RECT  60.624 87.973 73.272 89.989 ;
     RECT  74.256 86.771 76.104 89.989 ;
     RECT  99.6 89.605 100.296 90.083 ;
     RECT  96.768 88.885 97.464 90.515 ;
     RECT  77.376 89.555 79.512 90.565 ;
     RECT  82.272 88.979 82.344 90.565 ;
     RECT  83.4 88.979 84.648 90.565 ;
     RECT  96.768 90.515 97.212 90.659 ;
     RECT  80.592 89.555 81.012 90.901 ;
     RECT  82.272 90.565 84.984 90.901 ;
     RECT  34.8 89.989 40.68 91.187 ;
     RECT  80.592 90.901 84.984 91.235 ;
     RECT  80.592 91.235 84.648 91.331 ;
     RECT  80.7 91.331 84.648 91.475 ;
     RECT  80.7 91.475 84.6 91.715 ;
     RECT  42 84.563 43.752 91.717 ;
     RECT  82.272 91.715 84.6 91.763 ;
     RECT  86.1 88.163 87.528 91.765 ;
     RECT  60.624 89.989 76.104 92.339 ;
     RECT  83.4 91.763 84.6 92.915 ;
     RECT  86.1 91.765 87.768 92.915 ;
     RECT  88.8 89.507 89.112 92.917 ;
     RECT  41.568 91.717 43.752 93.251 ;
     RECT  90.48 92.677 90.504 93.347 ;
     RECT  77.376 90.565 79.56 93.443 ;
     RECT  60.672 92.339 76.104 93.539 ;
     RECT  83.4 92.915 84.504 93.779 ;
     RECT  88.8 92.917 89.208 93.875 ;
     RECT  60.672 93.539 73.272 93.923 ;
     RECT  86.1 92.915 87.528 94.355 ;
     RECT  82.272 91.763 82.344 94.453 ;
     RECT  34.8 91.187 40.512 94.645 ;
     RECT  42 93.251 43.752 94.645 ;
     RECT  82.032 94.453 82.344 94.739 ;
     RECT  34.8 94.645 43.752 95.219 ;
     RECT  86.1 94.355 87.384 95.507 ;
     RECT  74.256 93.539 76.104 95.605 ;
     RECT  77.376 93.443 79.512 95.605 ;
     RECT  61.8 93.923 73.272 95.653 ;
     RECT  74.256 95.605 79.512 95.653 ;
     RECT  88.8 93.875 89.112 95.701 ;
     RECT  45.6 84.851 59.412 95.749 ;
     RECT  86.1 95.507 86.412 95.797 ;
     RECT  61.8 95.653 79.512 95.987 ;
     RECT  45.36 95.749 59.412 96.277 ;
     RECT  60.672 93.923 60.744 96.277 ;
     RECT  61.8 95.987 73.272 96.277 ;
     RECT  74.256 95.987 79.512 96.563 ;
     RECT  45.36 96.277 59.544 96.755 ;
     RECT  60.672 96.277 73.272 96.949 ;
     RECT  74.256 96.563 76.104 96.949 ;
     RECT  45.6 96.755 59.544 97.043 ;
     RECT  60.672 96.949 76.104 97.139 ;
     RECT  77.376 96.563 79.512 97.331 ;
     RECT  29.4 77.507 30.552 97.909 ;
     RECT  26.7 2.151 27.012 98.005 ;
     RECT  26.7 98.005 27.912 98.053 ;
     RECT  29.4 97.909 31.08 98.053 ;
     RECT  82.08 94.739 82.344 98.099 ;
     RECT  85.488 95.797 86.412 98.099 ;
     RECT  88.704 95.701 89.112 98.099 ;
     RECT  60.672 97.139 60.744 98.341 ;
     RECT  74.256 97.139 76.104 98.437 ;
     RECT  77.376 97.331 78.936 98.437 ;
     RECT  32.1 84.083 33.384 98.581 ;
     RECT  34.8 95.219 40.512 98.581 ;
     RECT  45.6 97.043 59.412 98.581 ;
     RECT  61.8 97.139 73.272 98.629 ;
     RECT  74.256 98.437 78.936 98.629 ;
     RECT  26.7 98.053 31.08 98.675 ;
     RECT  60.624 98.341 60.744 98.725 ;
     RECT  61.8 98.629 78.936 98.725 ;
     RECT  32.1 98.581 40.512 98.869 ;
     RECT  28.56 98.675 31.08 98.917 ;
     RECT  32.1 98.869 40.632 98.917 ;
     RECT  45.6 98.581 59.592 98.917 ;
     RECT  60.624 98.725 78.936 98.917 ;
     RECT  80.7 91.715 81.012 100.117 ;
     RECT  45.6 98.917 79.656 100.261 ;
     RECT  80.7 100.117 81.144 100.261 ;
     RECT  45.6 100.261 81.144 100.837 ;
     RECT  45.504 100.837 81.144 100.933 ;
     RECT  82.272 98.099 82.344 100.933 ;
     RECT  28.56 98.917 40.632 101.123 ;
     RECT  42 95.219 43.752 101.123 ;
     RECT  45.504 100.933 82.344 101.123 ;
     RECT  45.504 101.123 81.336 101.507 ;
     RECT  45.504 101.507 45.912 101.747 ;
     RECT  47.28 101.507 81.336 102.083 ;
     RECT  47.28 102.083 66.024 102.131 ;
     RECT  47.28 102.131 65.304 102.227 ;
     RECT  47.28 102.227 62.808 102.275 ;
     RECT  47.28 102.275 62.52 102.467 ;
     RECT  38.784 101.123 40.632 102.515 ;
     RECT  67.104 102.083 81.336 102.563 ;
     RECT  63.984 102.227 65.304 102.611 ;
     RECT  26.7 98.675 27.012 102.613 ;
     RECT  28.56 101.123 37.812 102.613 ;
     RECT  39.312 102.515 40.632 102.659 ;
     RECT  47.28 102.467 62.424 102.659 ;
     RECT  82.32 101.123 82.344 102.707 ;
     RECT  45.6 101.747 45.912 102.709 ;
     RECT  42.9 101.123 43.752 102.803 ;
     RECT  45.6 102.709 46.776 102.851 ;
     RECT  63.984 102.611 65.16 102.851 ;
     RECT  25.488 102.421 25.512 103.235 ;
     RECT  40.2 102.659 40.632 103.235 ;
     RECT  48.3 102.659 62.424 103.235 ;
     RECT  67.104 102.563 67.512 103.235 ;
     RECT  68.496 102.563 81.336 103.283 ;
     RECT  2.4 2.151 2.712 103.419 ;
     RECT  5.1 2.151 5.412 103.419 ;
     RECT  7.8 2.151 8.112 103.419 ;
     RECT  10.5 2.151 10.812 103.419 ;
     RECT  13.2 2.151 13.512 103.419 ;
     RECT  15.9 2.151 16.212 103.419 ;
     RECT  18.6 2.151 18.912 103.419 ;
     RECT  21.3 2.151 21.612 103.419 ;
     RECT  24 2.151 24.312 103.419 ;
     RECT  26.7 102.613 37.812 103.419 ;
     RECT  40.2 103.235 40.512 103.419 ;
     RECT  42.9 102.803 43.212 103.419 ;
     RECT  45.6 102.851 45.912 103.419 ;
     RECT  48.3 103.235 62.112 103.419 ;
     RECT  67.2 103.235 67.512 103.419 ;
     RECT  83.4 93.779 83.712 103.419 ;
     RECT  86.1 98.099 86.412 103.419 ;
     RECT  88.8 98.099 89.112 103.419 ;
     RECT  91.5 89.555 91.812 103.419 ;
     RECT  94.2 88.931 94.512 103.419 ;
     RECT  96.9 90.659 97.212 103.419 ;
     RECT  99.6 90.083 99.912 103.419 ;
     RECT  2.592 103.419 2.712 103.433 ;
     RECT  5.292 103.419 5.412 103.433 ;
     RECT  7.992 103.419 8.112 103.433 ;
     RECT  10.692 103.419 10.812 103.433 ;
     RECT  13.392 103.419 13.512 103.433 ;
     RECT  16.092 103.419 16.212 103.433 ;
     RECT  18.792 103.419 18.912 103.433 ;
     RECT  21.492 103.419 21.612 103.433 ;
     RECT  24.192 103.419 24.312 103.433 ;
     RECT  26.892 103.419 36.552 103.433 ;
     RECT  37.692 103.419 37.812 103.433 ;
     RECT  40.392 103.419 40.512 103.433 ;
     RECT  43.092 103.419 43.212 103.433 ;
     RECT  45.792 103.419 45.912 103.433 ;
     RECT  48.492 103.419 62.112 103.433 ;
     RECT  67.392 103.419 67.512 103.433 ;
     RECT  83.592 103.419 83.712 103.433 ;
     RECT  86.292 103.419 86.412 103.433 ;
     RECT  88.992 103.419 89.112 103.433 ;
     RECT  91.692 103.419 91.812 103.433 ;
     RECT  94.392 103.419 94.512 103.433 ;
     RECT  97.092 103.419 97.212 103.433 ;
     RECT  99.792 103.419 99.912 103.433 ;
     RECT  63.984 102.851 64.968 103.763 ;
     RECT  63.984 103.763 64.008 104.725 ;
     RECT  63.792 104.725 64.008 104.867 ;
     RECT  49.536 103.433 61.896 104.915 ;
     RECT  27.504 103.433 36.552 105.541 ;
     RECT  68.88 103.283 81.336 105.731 ;
     RECT  27.408 105.541 36.552 105.744 ;
     RECT  49.68 104.915 61.896 105.744 ;
     RECT  68.88 105.731 81.096 105.744 ;
     RECT  63.984 104.867 64.008 105.779 ;
  END
END qfd_landh_600_EN_104x106
END LIBRARY
